// TwinCAT 3 PLC project PLC
// ProgramVersion: 3.1.4024.0
// libraries:
//   Tc2_ModbusRTU, * (Beckhoff Automation GmbH)
//   Tc2_Standard, * (Beckhoff Automation GmbH)
//   Tc2_System, * (Beckhoff Automation GmbH)
//   Tc2_Utilities, * (Beckhoff Automation GmbH)
//   Tc3_Module, * (Beckhoff Automation GmbH)
// project tree:
//   DUTs/_00_DUTs_IOMapping/INPUT/ dut_EXH_Input.TcDUT, dut_GB_Input.TcDUT, dut_OP_INPUT.TcDUT
//   DUTs/_00_DUTs_IOMapping/OUTPUT/ dut_EX260_SEC.TcDUT, dut_EXH_Output.TcDUT, dut_GB_Output.TcDUT, dut_OP_Output.TcDUT
//   DUTs/_01_DUTs_PMC_PLC/ dut_Interlock.TcDUT, dut_PMC_to_PLC.TcDUT, dut_PLC_to_PMC.TcDUT
//   DUTs/_09_DUTs_Function/ dut_32Bits.TcDUT, dut_8Bits.TcDUT, dut_UDINT_BOOL.TcDUT, dut_USINT_BOOL.TcDUT
//   GVLs/ AI.TcGVL, AO.TcGVL, GVL.TcGVL, GVL_IO_Mapping.TcGVL
//   / PlcTask.TcTTO
//   POUs/_000_MainPro/ MAIN.TcPOU
//   POUs/_100_IOMapping/ IOMapping.TcPOU
//   POUs/_200_Interlock/ Interlock.TcPOU
//   POUs/_900_FB/ AnalogConverter.TcPOU, FFU.TcPOU, Valve.TcPOU

CONFIGURATION PLC
    RESOURCE PLC ON TwinCAT3
        TASK PlcTask(INTERVAL := T#10ms, PRIORITY := 20);
        PROGRAM MAIN WITH PlcTask : MAIN;
        PROGRAM IOMapping WITH PlcTask : IOMapping;
    END_RESOURCE
END_CONFIGURATION

// ---- DUTs/_00_DUTs_IOMapping/INPUT/dut_EXH_Input.TcDUT
TYPE dut_EXH_Input :
STRUCT

	I300_00			:BOOL;	//	FS105_RHC_Flow_Alarm
	I300_01			:BOOL;	//	FS106_Heater_Jacket_Flow_Alarm
	I300_02			:BOOL;	//	FS202_Heater_Upper_Alarm
	I300_03			:BOOL;	//	FS104_Shutter_Flow_Alarm
	I300_04			:BOOL;	//	FS111_BoatRotation_Flow_Alarm
	I300_05			:BOOL;	//	FS102_Flange_Flow_Alarm
	I300_06			:BOOL;	//	Spare
	I300_07			:BOOL;	//	Spare
	I300_08			:BOOL;	//	VG11_Status_OK
	I300_09			:BOOL;	//	VG11_Low_Alarm
	I300_10			:BOOL;	//	VG11_High_Alarm
	I300_11			:BOOL;	//	VG13_Status_OK
	I300_12			:BOOL;	//	VG13_Low_Alarm
	I300_13			:BOOL;	//	VG13_High_Alarm
	I300_14			:BOOL;	//	AV71_Fan1_Alarm
	I300_15			:BOOL;	//	AV71_Fan2_Alarm
	I301_00			:BOOL;	//	DG1_Low_Limit_Alarm
	I301_01			:BOOL;	//	DG1_High_Limit_Alarm
	I301_02			:BOOL;	//	Spare
	I301_03			:BOOL;	//	Spare
	I301_04			:BOOL;	//	Spare
	I301_05			:BOOL;	//	Spare
	I301_06			:BOOL;	//	Spare
	I301_07			:BOOL;	//	Spare
	I301_08			:BOOL;	//	MP/PS21_Pressure_Low_Alarm
	I301_09			:BOOL;	//	FS101_MainWater_Flow_Alarm-1
	I301_10			:BOOL;	//	FS101_FMainWater_low_Alarm-2
	I301_11			:BOOL;	//	FL301_Flow_Switch
	I301_12			:BOOL;	//	Spare
	I301_13			:BOOL;	//	FS116_Zaxis_Flow_Alarm
	I301_14			:BOOL;	//	PS110_Pressure_Low_Alarm
	I301_15			:BOOL;	//	PS110_Pressure_High_Alarm
	I302_00			:BOOL;	//	PG/PS12_Pressure_Low_Alarm
	I302_01			:BOOL;	//	PG/PS12_Pressure_High_Alarm
	I302_02			:BOOL;	//	PS13_ATM_Status
	I302_03			:BOOL;	//	PS13_High_Limit_Alarm
	I302_04			:BOOL;	//	PG101_Water_Pressure_Low_Alarm
	I302_05			:BOOL;	//	PG101_Water_Pressure_High_Alarm
	I302_06			:BOOL;	//	VG14_Status_OK
	I302_07			:BOOL;	//	VG14_LOW_Alarm
	I302_08			:BOOL;	//	VG14_High_Alarm
	I302_09			:BOOL;	//	PS14_Pressure_Low_Alarm
	I302_10			:BOOL;	//	PS14_Pressure_High_Alarm
	I302_11			:BOOL;	//	Spare
	I302_12			:BOOL;	//	Spare
	I302_13			:BOOL;	//	Spare
	I302_14			:BOOL;	//	Spare
	I302_15			:BOOL;	//	Spare
	I303_00			:BOOL;	//	APC_Valve_Status
	I303_01			:BOOL;	//	APC_Alarm_Status
	I303_02			:BOOL;	//	RHC_Cooling_Air_cylinder1_Open
	I303_03			:BOOL;	//	RHC_Cooling_Air_cylinder1_Close
	I303_04			:BOOL;	//	RHC_Cooling_Air_cylinder2_Open
	I303_05			:BOOL;	//	RHC_Cooling_Air_cylinder2_Close
	I303_06			:BOOL;	//	RHC_Cooling_Valve_Open
	I303_07			:BOOL;	//	RHC_Cooling_Valve_Close
	I303_08			:BOOL;	//	RHC_Cooling_ButterflyValves_Open
	I303_09			:BOOL;	//	RHC_Cooling_ButterflyValves_Close
	I303_10			:BOOL;	//	Spare
	I303_11			:BOOL;	//	Spare
	I303_12			:BOOL;	//	GV_Open_NC
	I303_13			:BOOL;	//	GV_Open_NO
	I303_14			:BOOL;	//	GV_Close_NC
	I303_15			:BOOL;	//	GV_Close_NO
	I304_00			:BOOL;	//	RHC_Cooling_BallValve_Open
	I304_01			:BOOL;	//	RHC_Cooling_BallValve_Close
	I304_02			:BOOL;	//	Spare
	I304_03			:BOOL;	//	Spare
	I304_04			:BOOL;	//	Spare
	I304_05			:BOOL;	//	Spare
	I304_06			:BOOL;	//	Spare
	I304_07			:BOOL;	//	Spare
	I304_08			:BOOL;	//	Spare
	I304_09			:BOOL;	//	Spare
	I304_10			:BOOL;	//	Spare
	I304_11			:BOOL;	//	Spare
	I304_12			:BOOL;	//	Spare
	I304_13			:BOOL;	//	Spare
	I304_14			:BOOL;	//	Spare
	I304_15			:BOOL;	//	Spare	

	IW300			:INT;	//	FS105_RHC_Colling_Water_Flow
	IW301			:INT;	//	FS106_Heater_Jacket_Cooling_Water_Flow
	IW302			:INT;	//	FS202_Furnace_Cooling_Water_Flow
	IW303			:INT;	//	FS104_Shutter_Cooling_Water_Flow
	IW304			:INT;	//	FS111_Boat_Rotation_Cooling_Water_Flow
	IW305			:INT;	//	FS102_Flange_Cooling_Water_Flow
	IW306			:INT;	//	SPARE
	IW307			:INT;	//	SPARE
	IW308			:INT;	//	DG1_Pressure
	IW309			:INT;	//	SPARE
	IW310			:INT;	//	SPARE
	IW311			:INT;	//	FS116_Radiator_Cooling_Water_Flow
	IW312			:INT;	//	PS13_Pressure
	IW313			:INT;	//	SPARE
	IW314			:INT;	//	SPARE
	IW315			:INT;	//	SPARE
	IW316			:INT;	//	SPARE
	IW317			:INT;	//	SPARE
	IW318			:INT;	//	PS21_Pressure
	IW319			:INT;	//	PS110_Pressure
	IW320			:INT;	//	PG/PS12_Pressure
	IW321			:INT;	//	VG14_Pressure
	IW322			:INT;	//	PS14_Pressure
	IW323			:INT;	//	SPARE
	IW324			:INT;	//	SPARE
	IW325			:INT;	//	SPARE
	IW326			:INT;	//	SPARE
	IW327			:INT;	//	SPARE
	IW328			:INT;	//	SPARE
	IW329			:INT;	//	SPARE
	IW330			:INT;	//	SPARE
	IW331			:INT;	//	SPARE
	IW332			:INT;	//	spare
	IW333			:INT;	//	SPARE
	IW334			:INT;	//	SPARE
	IW335			:INT;	//	SPARE

END_STRUCT
END_TYPE

// ---- DUTs/_00_DUTs_IOMapping/INPUT/dut_GB_Input.TcDUT
TYPE dut_GB_Input :
STRUCT

	I200_00			:BOOL;	//	PG3_LOW_ALARM
	I200_01			:BOOL;	//	PG3_HIGH_ALARM
	I200_02			:BOOL;	//	PG4_LOW_ALARM
	I200_03			:BOOL;	//	PG4_HIGH_ALARM
	I200_04			:BOOL;	//	PG5_LOW_ALARM
	I200_05			:BOOL;	//	PG5_HIGH_ALARM
	I200_06			:BOOL;	//	PG6_LOW_ALARM
	I200_07			:BOOL;	//	PG6_HIGH_ALARM
	I200_08			:BOOL;	//	PG7_LOW_ALARM
	I200_09			:BOOL;	//	PG7_HIGH_ALARM
	I200_10			:BOOL;	//	PG8_LOW_ALARM
	I200_11			:BOOL;	//	PG8_HIGH_ALARM
	I200_12			:BOOL;	//	PG31_LOW_ALARM
	I200_13			:BOOL;	//	PG31_HIGH_ALARM
	I200_14			:BOOL;	//	PG32_LOW_ALARM
	I200_15			:BOOL;	//	PG32_HIGH_ALARM
	I201_00			:BOOL;	//	LSC_H_LEVEL
	I201_01			:BOOL;	//	LSC_M_LEVEL
	I201_02			:BOOL;	//	LSC_L_LEVEL
	I201_03			:BOOL;	//	VG31_STATUS_OK
	I201_04			:BOOL;	//	VG31_LOW_ALARM
	I201_05			:BOOL;	//	VG31_HIGH_ALARM
	I201_06			:BOOL;	//	GD_FAN1_STOP
	I201_07			:BOOL;	//	GD_FAN2_STOP
	I201_08			:BOOL;	//	OX_MS1
	I201_09			:BOOL;	//	OX_MS2
	I201_10			:BOOL;	//	OX_MS3
	I201_11			:BOOL;	//	OX_MSI1
	I201_12			:BOOL;	//	OX_MSI2
	I201_13			:BOOL;	//	OX_RC1
	I201_14			:BOOL;	//	OX_RC2
	I201_15			:BOOL;	//	OX_RC3
	I202_00			:BOOL;	//	MS2_Pressure_LOW_ALARM
	I202_01			:BOOL;	//	MS2_Pressure_HIGH_ALARM
	I202_02			:BOOL;	//	MS5_Pressure_LOW_ALARM
	I202_03			:BOOL;	//	MS5_Pressure_HIGH_ALARM
	I202_04			:BOOL;	//	SPARE
	I202_05			:BOOL;	//	SPARE
	I202_06			:BOOL;	//	MP/PS20_Pressure_ALARM
	I202_07			:BOOL;	//	MP/PS11_Pressure_ALARM
	I202_08			:BOOL;	//	SPARE
	I202_09			:BOOL;	//	SPARE
	I202_10			:BOOL;	//	SPARE
	I202_11			:BOOL;	//	PG1_LOW_ALARM
	I202_12			:BOOL;	//	PG1_HIGH_ALARM
	I202_13			:BOOL;	//	SPARE
	I202_14			:BOOL;	//	SPARE
	I202_15			:BOOL;	//	SPARE
	I203_00			:BOOL;	//	SPARE
	I203_01			:BOOL;	//	SPARE	
	I203_02			:BOOL;	//	SPARE	
	I203_03			:BOOL;	//	SPARE	
	I203_04			:BOOL;	//	SPARE	
	I203_05			:BOOL;	//	SPARE	
	I203_06			:BOOL;	//	SPARE	
	I203_07			:BOOL;	//	SPARE	
	I203_08			:BOOL;	//	SPARE	
	I203_09			:BOOL;	//	SPARE	
	I203_10			:BOOL;	//	SPARE	
	I203_11			:BOOL;	//	SPARE	
	I203_12			:BOOL;	//	SPARE	
	I203_13			:BOOL;	//	SPARE	
	I203_14			:BOOL;	//	SPARE	
	I203_15			:BOOL;	//	SPARE	
	
	IW250			:INT;	//	PG3_Pressure
	IW251			:INT;	//	PG4_Pressure
	IW252			:INT;	//	PG5_Pressure
	IW253			:INT;	//	PG6_Pressure
	IW254			:INT;	//	PG7_Pressure
	IW255			:INT;	//	PG8_PressureE
	IW256			:INT;	//	PG31_Pressure
	IW257			:INT;	//	PG32_Pressure
	IW258			:INT;	//	VG31_Pressure
	IW259			:INT;	//	PG2_Pressure
	IW260			:INT;	//	PS11_Pressure
	IW261			:INT;	//	PG1_Pressure
	IW262			:INT;	//	MS2_Gasboxleft	 
	IW263			:INT;	//	MS5_Loadingarea	
	IW264			:INT;	//	OX_Value
	IW265			:INT;	//	SPARE
	IW266			:INT;	//	PG21_Pressure
	IW267			:INT;	//	PG22_Pressure
	IW268			:INT;	//	PG23_Pressure
	IW269			:INT;	//	PG33_Pressure
	
END_STRUCT
END_TYPE

// ---- DUTs/_00_DUTs_IOMapping/INPUT/dut_OP_INPUT.TcDUT
TYPE dut_OP_INPUT :
STRUCT
	I600_00			:BOOL;	//	MS8_HC_ExhPress_LOW_ALARM
	I600_01			:BOOL;	//	MS8_HC_ExhPress_HIGH_ALARM
	I600_02			:BOOL;	//	MS1_Heater_ExhPress_LOW_ALARM
	I600_03			:BOOL;	//	MS1_Heater_ExhPress_HIGH_ALARM
	I600_04			:BOOL;	//	MS3_Scavenger_ExhPress_LOW_ALARM
	I600_05			:BOOL;	//	MS3_Scavenger_ExhPress_HIGH_ALARM
	I600_06			:BOOL;	//	MS6_Frontbody_ExhPress_LOW_ALARM
	I600_07			:BOOL;	//	MS6_Frontbody_ExhPress_HIGH_ALARM
	I600_08			:BOOL;	//	MS9_LSC1_ExhPress_LOW_ALARM
	I600_09			:BOOL;	//	MS9_LSC1_ExhPress_HIGH_ALARM
	I600_10			:BOOL;	//	MS11_GasBox_ExhPress_LOW_ALARM
	I600_11			:BOOL;	//	MS11_GasBox_ExhPress_HIGH_ALARM
	I600_12			:BOOL;	//	MS12_GasBox_ExhPress_LOW_ALARM
	I600_13			:BOOL;	//	MS12_GasBox_ExhPress_HIGH_ALARM
	I600_14			:BOOL;	//	SPARE
	I600_15			:BOOL;	//	SPARE
	
	IW600			:INT;	//	MS8_RHC_ExhPress
	IW601			:INT;	//	MS1_Heater_ExhPress
	IW602			:INT;	//	MS3_Scavenger_ExhPress
	IW603			:INT;	//	MS6_Frontbody_ExhPress
	IW604			:INT;	//	MS9_LSC1_ExhPress
	IW605			:INT;	//	MS11_GasBox_ExhPress
	IW606			:INT;	//	MS12_GasBox_ExhPress
	IW607			:INT;	//	SPARE

END_STRUCT
END_TYPE

// ---- DUTs/_00_DUTs_IOMapping/OUTPUT/dut_EX260_SEC.TcDUT
TYPE dut_EX260_SEC :
STRUCT
	A:dut_USINT_BOOL;
	B:dut_USINT_BOOL;
	C:dut_USINT_BOOL;
	D:dut_USINT_BOOL;
END_STRUCT
END_TYPE

// ---- DUTs/_00_DUTs_IOMapping/OUTPUT/dut_EXH_Output.TcDUT
TYPE dut_EXH_Output :
STRUCT
	
	Q300_00				:BOOL;	//	CoolingValve1_Boat
	Q300_01				:BOOL;	//	CoolingValve2_Flange
	Q300_02				:BOOL;
	Q300_03				:BOOL;
	Q300_04				:BOOL;
	Q300_05				:BOOL;
	Q300_06				:BOOL;
	Q300_07				:BOOL;
	Q300_08				:BOOL;	//	APC_auto_close
	Q300_09				:BOOL;	//	APC_pump_on
	Q300_10				:BOOL;
	Q300_11				:BOOL;
	Q300_12				:BOOL;
	Q300_13				:BOOL;
	Q300_14				:BOOL;
	Q300_15				:BOOL;
		
	QEV					:ARRAY[1..1]OF	dut_EX260_SEC ;	//阀岛输出
	
END_STRUCT
END_TYPE

// ---- DUTs/_00_DUTs_IOMapping/OUTPUT/dut_GB_Output.TcDUT
TYPE dut_GB_Output :
STRUCT
								    									
	Q200_00			:BOOL;	//	OX_Pump_On
	Q200_01			:BOOL;	//	Spare1
	Q200_02			:BOOL;	//	Spare2
	Q200_03			:BOOL;	//	Spare3
	Q200_04			:BOOL;	//	Spare4
	Q200_05			:BOOL;	//	Spare5
	Q200_06			:BOOL;	//	Spare6
	Q200_07			:BOOL;	//	Spare7
	Q200_08			:BOOL;	//	Spare8
	Q200_09			:BOOL;	//	Spare9
	Q200_10			:BOOL;	//	Spare10
	Q200_11			:BOOL;	//	Spare11
	Q200_12			:BOOL;	//	Spare12
	Q200_13			:BOOL;	//	Spare13
	Q200_14			:BOOL;	//	Spare14
	Q200_15			:BOOL;	//	Spare15
	
	QEV				:ARRAY[1..5]OF dut_EX260_SEC;	//阀岛输出
	
END_STRUCT
END_TYPE

// ---- DUTs/_00_DUTs_IOMapping/OUTPUT/dut_OP_Output.TcDUT
TYPE dut_OP_Output :
STRUCT
	










END_STRUCT
END_TYPE

// ---- DUTs/_01_DUTs_PMC_PLC/dut_Interlock.TcDUT
TYPE dut_Interlock :
STRUCT
	Alarm1		: BOOL;	// N2-8 pressure low
	Alarm2		: BOOL;	// N2-1 pressure low or high
	Alarm3		: BOOL;	// NH3-1 pressure low or high
	Alarm4		: BOOL;	// NH3-2 pressure low or high
	Alarm5		: BOOL;	// SiH4 pressure low or high
	Alarm6		: BOOL;	// N2-2 pressure low or high
	Alarm7		: BOOL;	// NF3 pressure low or high
	Alarm8		: BOOL;	// 20%F2/N2 pressure low or high
	Alarm9		: BOOL;	// N2-9 pressure low or high
	Alarm10		: BOOL;	// N2-10 pressure low or high
	Alarm11		: BOOL;	// N2-11 pressure low or high
	Alarm12		: BOOL;	// N2-13 pressure low or high
	Alarm13		: BOOL;	// LSC tank over pressure
	Alarm14		: BOOL;	// TI tank over pressure
	Alarm15		: BOOL;	// NH3-1 tank over pressure
	Alarm16		: BOOL;	// Vacuum pressure low
	Alarm17		: BOOL;	// air/N2-1 pressure low
	Alarm18		: BOOL;	// N2-4 pressure low
	Alarm19		: BOOL;	// N2-5 pressure low
	Alarm20		: BOOL;	// N2-6 pressure low
	Alarm21		: BOOL;	// NH3-2 tank over pressure
	Alarm22		: BOOL;	// gas box lower and upper exhaust pressure low
	Alarm23		: BOOL;	// Scavenger exhaust pressure low
	Alarm24		: BOOL;	// Heater exhaust pressure low
	Alarm25		: BOOL;	// RHC pressure low
	Alarm26		: BOOL;	// Z purge in LSC-1 pressure
	Alarm27		: BOOL;	// Gas box lower an upper exhaust pressure low
	Alarm28		: BOOL;	// Abnormal diaphragm sensor reading value
	Alarm29		: BOOL;	// spare
	Alarm30		: BOOL;	// Abnormal furnace port cap seal level
	Alarm31		: BOOL;	// Heater exceeds the upper limit
	Alarm32		: BOOL;	// Heater room temperature high
	Alarm33		: BOOL;	// spare
	Alarm34		: BOOL;	// Heater transformer temperature high
	Alarm35		: BOOL;	// spare
	Alarm36		: BOOL;   // AC100V transformer temperature high
	Alarm37		: BOOL;   // spare
	Alarm38		: BOOL;	// spare
	Alarm39		: BOOL;	// N2 does not flow in each foup
	Alarm40		: BOOL;	// Exhaust pressure high
	Alarm41		: BOOL;	// Power down detected
	Alarm42		: BOOL;	// Front door kept open
	Alarm43		: BOOL;	// Transfer room door kept open
	Alarm44		: BOOL;	// Heater room door kept open
	Alarm45		: BOOL;	// Heater power down
	Alarm46		: BOOL;	// spare
	Alarm47		: BOOL;	// Pump down
	Alarm48		: BOOL;	// Pump alarm
	Alarm49		: BOOL;	// Pump warning
	Alarm50		: BOOL;	// spare
	Alarm51		: BOOL;	// NH3 leak detection
	Alarm52		: BOOL;	// SiH4 leak detection
	Alarm53		: BOOL;	// HCL leak detection
	Alarm54		: BOOL;	// Diaphgram sensor-VG11 negative value
	Alarm55		: BOOL;	// Diaphgram sensor-VG13 negative value
	Alarm56		: BOOL;	// Diaphgram sensor-VG14 negative value
	Alarm57		: BOOL;	// APC alarm
	Alarm58		: BOOL;	// Too high furnace pressure
	Alarm59		: BOOL;	// Main cooling water flow low
	Alarm60		: BOOL;	// Cooling water flow low
	Alarm61		: BOOL;	// NF3 gas leak detection
	Alarm62		: BOOL;	// 20%F2/N2 leak detection
	Alarm63		: BOOL;	// scrubber NG DEPO
	Alarm64		: BOOL;	// scrubber NG CLN
	Alarm65		: BOOL;	// FFU stop
	Alarm66		: BOOL;	// SPARE
	Alarm67		: BOOL;	// Loading area differential pressure abnormal
	Alarm68		: BOOL;	// Clean unit temperature high
	Alarm69		: BOOL;	// Differential pressure NG-DG1
	Alarm70		: BOOL; // RHC flow low
	Alarm71		: BOOL;	// RHC damper abnormal position
	Alarm72		: BOOL;	// Blower overload
	Alarm73		: BOOL;	// RHC cooling water bypass line flow low/damper position abnormal in energy-saving mode
	Alarm74		: BOOL;	// Cooling water pressure low
	Alarm75		: BOOL;	// TI tank refll incorrect
	Alarm76		: BOOL;	// Abnormal float sw position in TI tank
	Alarm77		: BOOL;	// N2-7 pressure low or high
	Alarm78		: BOOL;	// N2-70 pressure low or high
	Alarm79		: BOOL;	// Vent exhaust pressure high
	Alarm80		: BOOL;	// Gas box door kept open
	Alarm81		: BOOL;	// Magnetic leak
	Alarm82		: BOOL;	// Heater room leak
	Alarm83		: BOOL;	// Loading area leak
	Alarm84		: BOOL;	// Exhaust box main leak
	Alarm85		: BOOL;	// SPARE
	Alarm86		: BOOL;	// RHC leak
	Alarm87		: BOOL;	// Exhaust box sup leak
	Alarm88		: BOOL;	// O2 analyzer fault
	Alarm89		: BOOL;	// Heater contactor tripped
	Alarm90		: BOOL;	// AC100V transformer contactor tripped
	Alarm91		: BOOL;	// gas box door kept open
	Alarm92		: BOOL;	// spare
	Alarm93		: BOOL;	// spare
	Alarm94		: BOOL;	// failure of exhaust pressure sensor
	Alarm95		: BOOL;	// Transfer room EMS
	Alarm96		: BOOL;	// Furnace pressure is below ATM pressure
	Alarm97		: BOOL; // Front body exhaust pressure low
	Alarm98		: BOOL;	// Gage valve position error
	Alarm99		: BOOL;	// LSC heater temperature abnormal
	Alarm100	: BOOL;	// Gas line heater temperature abnormal
	Alarm101	: BOOL;	// Exhaust line heater temperature abnormal
	Alarm102	: BOOL;	// VG11/13/14 heater temperature abnormal
	Alarm103	: BOOL;	// Seal cap heater temperature high
	Alarm104	: BOOL;	// spare
	Alarm105	: BOOL;	// Furnace & exhaust line heater temperature beyond a preset value
	Alarm106	: BOOL;	// Intake damper position abnormal
	Alarm107	: BOOL;	// ATM damper position abnormal
	Alarm108	: BOOL;	// Cycle damper position abnormal
	Alarm109	: BOOL;	// LSC tank level HH
	Alarm110	: BOOL;	// LSC tank level H
	Alarm111	: BOOL;	// LSC tank level M
	Alarm112	: BOOL;	// LSC tank level L
	Alarm113	: BOOL;	// LSC leak
	Alarm114	: BOOL;	// spare
	Alarm115	: BOOL;	// sspare
	Alarm116	: BOOL;	// HPM interlock
	Alarm117	: BOOL;	// Scrubber alarm
	Alarm118	: BOOL;	// Foreline heater alarm
	Alarm119	: BOOL;	// Scrubber warning
	Alarm120	: BOOL;	// spare
	Alarm121	: BOOL;	// Customer's auto refill alarm
	Alarm122	: BOOL;	// Customer's auto refill warning
	Alarm123	: BOOL;	// Customer's auto refill bulk empty(not ready)
	Alarm124	: BOOL;	// Gas detector trouble
	Alarm125	: BOOL;	// External EMO in
	Alarm126	: BOOL;	// spare
	Alarm127	: BOOL;	// spare
	Alarm128	: BOOL;	// spare
	Alarm129	: BOOL;	// spare
	Alarm130	: BOOL;	// spare
	Alarm131	: BOOL;	// spare
	Alarm132	: BOOL;	// spare
	Alarm133	: BOOL;	// spare
	Alarm134	: BOOL;	// spare
	Alarm135	: BOOL;	// spare
	Alarm136	: BOOL;	// spare
	Alarm137	: BOOL;	// spare
	Alarm138	: BOOL;	// spare
	Alarm139	: BOOL;	// spare
	Alarm140	: BOOL;	// spare
	Alarm141	: BOOL;	// spare
	Alarm142	: BOOL;	// spare
	Alarm143	: BOOL;	// spare
	Alarm144	: BOOL;	// spare
	Alarm145	: BOOL;	// spare
	Alarm146	: BOOL;	// spare
	Alarm147	: BOOL;	// spare
	Alarm148	: BOOL;	// spare
	Alarm149	: BOOL;	// spare
	Alarm150	: BOOL;	// spare
	
END_STRUCT
END_TYPE

// ---- DUTs/_01_DUTs_PMC_PLC/dut_PMC_to_PLC.TcDUT
TYPE dut_PMC_to_PLC :
STRUCT
	bHeartBeatMonitor	: BOOL;		

	// UI switch
	DP_sw						,
	BWR_sw						,
	DPR1_sw						,
	DPR2_sw						,
	WAT_R_sw					,
	WAT_F_sw					,
	HTR1_sw						,
	HTR2_sw						,
	HTR3_sw						,
	HTR4_sw						,
	HTR5_sw						,
	AGV_sw						,
	DEPO_sw						,
	CLN_sw						,
	T_MNT_sw					,
	T_REF_sw					,
	Pump1_ECO_sw				,
	SP1_sw						,
	PZ_sw						,
	P_CONT_sw					,
	DGZERO_sw					,
	C_EXH_sw					,
	F2_CLN_sw					,
	F_N_sw						,
	GV_AV79_Open				,
	GV_AV79_Close				,
	APC_AV71_Open				,
	APC_AV71_Close				
	: BOOL;
	
	aAV							: ARRAY[1..250] OF BOOL;	
	bAV65Open					: BOOL;
	bAV65Close					: BOOL;
	bAV79Open					: BOOL;
	bAV79Close					: BOOL;
	bAV91Open					: BOOL;
	bAV91Close					: BOOL;
	bAV202Open					: BOOL;
	bAV202Close					: BOOL;
	
	//heater
	Furnace_Temp_abnormal		: BOOL;	// Furnace temp over 1000℃
	LSC_Ht_temp_abnormal		: BOOL;	// LSC heater temperature beyond preset value
	GB_Ht_temp_abnormal			: BOOL; // Gas line heater temperature beyond preset value
	EXH_Ht_temp_abnormal		: BOOL;	// Exhaust line heater temperature beyond preset value
	CLN_Temp_abnormal			: BOOL; // furnace&exhaust line heater temperature beyond preset value
	R_Axis_Temp					: REAL;	// R axis temperature
	Inlet_Ht_1_temp				: REAL;	// Inlet heater 1 temperature
	Inlet_Ht_2_temp				: REAL;	// Inlet heater 2 temperature
	Port_Ht_1_temp				: REAL; // Port heater 1 temperature
	Port_Ht_2_temp				: REAL; // Port heater 2 temperature
	Port_Ht_3_temp				: REAL; // Port heater 3 temperature
	Port_Ht_4_temp				: REAL; // Port heater 4 temperature
	Port_Ht_5_temp				: REAL; // Port heater 5 temperature

	//Power box
	I100_00			:BOOL;	//	UPS_Fault              
	I100_01			:BOOL;	//	UPS_Alarm              
	I100_02			:BOOL;	//	UPS_Bypass_Status      
	I100_03			:BOOL;	//	UPS_Battery_Voltage_Low
	I100_04			:BOOL;	//	UPS_Start              
	I100_05			:BOOL;	//	UPS_AC_Input_Cut_Off   
	I100_06			:BOOL;	//	Powerbox_FrontDoor_sw1
	I100_07			:BOOL;	//	Powerbox_FrontDoor_sw2
	I100_08			:BOOL;	//	Powerbox_BackDoor_sw1
	I100_09			:BOOL;	//	Powerbox_BackDoor_sw2
	I100_10			:BOOL;	//	Spare11
	I100_11			:BOOL;	//	Spare12
	I100_12			:BOOL;	//	Spare13
	I100_13			:BOOL;	//	Spare14
	I100_14			:BOOL;	//	Spare15
	I100_15			:BOOL;	//	Spare16
	I101_00			:BOOL;	//	KM101_ON
	I101_01			:BOOL;	//	KM201_ON
	I101_02			:BOOL;	//	KM102_ON
	I101_03			:BOOL;	//	KM103_ON
	I101_04			:BOOL;	//	KM104_ON
	I101_05			:BOOL;	//	SPARE
	I101_06			:BOOL;	//	SPARE
	I101_07			:BOOL;	//	Furnace_Main_Breaker_Status_Monitor
	I101_08			:BOOL;	//	Blower_Breaker_Status_Feedback
	I101_09			:BOOL;	//	Zone1_Circuit_Breaker_Status_Monitor
	I101_10			:BOOL;	//	Zone2_Circuit_Breaker_Status_Monitor
	I101_11			:BOOL;	//	Zone3_Circuit_Breaker_Status_Monitor
	I101_12			:BOOL;	//	Zone4_Circuit_Breaker_Status_Monitor
	I101_13			:BOOL;	//	Zone5_Circuit_Breaker_Status_Monitor
	I101_14			:BOOL;	//	Zone6_Circuit_Breaker_Status_Monitor
	I101_15			:BOOL;	//	Zone7_Circuit_Breaker_Status_Monitor
	I102_00			:BOOL;	//	LDS1_bulk_to_process_running
	I102_01			:BOOL;	//	LDS1_supply_doing
	I102_02			:BOOL;	//	LDS1_system_ready
	I102_03			:BOOL;	//	LDS1_major_alarm
	I102_04			:BOOL;	//	LDS1_minor_alarm
	I102_05			:BOOL;	//	LDS1_low_level_status
	I102_06			:BOOL;	//	LDS1_process_reservoir_empty
	I102_07			:BOOL;	//	LDS2_bulk_to_process_running
	I102_08			:BOOL;	//	LDS2_supply_doing           
	I102_09			:BOOL;	//	LDS2_system_ready           
	I102_10			:BOOL;	//	LDS2_major_alarm            
	I102_11			:BOOL;	//	LDS2_minor_alarm            
	I102_12			:BOOL;	//	LDS2_low_level_status       
	I102_13			:BOOL;	//	LDS2_process_reservoir_empty
	I102_14			:BOOL;	//	SPARE
	I102_15			:BOOL;	//	SPARE
	I103_00			:BOOL;	//	Vaccum1_Pump_Both_On
	I103_01			:BOOL;	//	Vaccum1_Pump_Warning
	I103_02			:BOOL;	//	Vaccum1_Pump_Alarm
	I103_03			:BOOL;	//	Spare19
	I103_04			:BOOL;	//	Spare20
	I103_05			:BOOL;	//	Spare21
	I103_06			:BOOL;	//	N2_Purge_BOX_PG13_CNT1
	I103_07			:BOOL;	//	N2_Purge_BOX_PG13_CNT2
	I103_08			:BOOL;	//	N2_Purge_BOX_PG14_CNT1
	I103_09			:BOOL;	//	N2_Purge_BOX_PG14_CNT2
	I103_10			:BOOL;	//	N2_Purge_Box_PG15_CNT1
	I103_11			:BOOL;	//	N2_Purge_Box_PG15_CNT2
	I103_12			:BOOL;	//	N2_Purge_Box_PG16_CNT1
	I103_13			:BOOL;	//	N2_Purge_Box_PG16_CNT2
	I103_14			:BOOL;	//	N2_Purge_Box_PG130_CNT1
	I103_15			:BOOL;	//	N2_Purge_Box_PG130_CNT2
	I104_00			:BOOL;	//	PS17_Low_pressure_alarm
	I104_01			:BOOL;	//	Foreline_heater_light_alarm
	I104_02			:BOOL;  //	Foreline_heater_heavy_alarm
	I104_03			:BOOL;  //	Scrubber_warning
	I104_04			:BOOL;  //	Scrubber_alarm
	I104_05			:BOOL;  //	External_HPM_alarm
	I104_06			:BOOL;  //	External_EMO_In
	I104_07			:BOOL;  //	SPARE
	I104_08			:BOOL;  //	SPARE
	I104_09			:BOOL;  //	SPARE
	I104_10			:BOOL;  //	SPARE
	I104_11			:BOOL;  //	SPARE
	I104_12			:BOOL;  //	SPARE
	I104_13			:BOOL;  //	SPARE
	I104_14			:BOOL;  //	SPARE
	I104_15			:BOOL;  //	SPARE
	
	Q100_00			:BOOL;	//	VFD_RES
	Q100_01			:BOOL;	//	VFD_MRS
	Q100_02			:BOOL;	//	VFD_RT
	Q100_03			:BOOL;	//	VFD_JOG
	Q100_04			:BOOL;	//	VFD_RL
	Q100_05			:BOOL;	//	VFD_RM
	Q100_06			:BOOL;	//	VFD_RH
	Q100_07			:BOOL;	//	VFD_STP
	Q100_08			:BOOL;	//	VFD_RTR
	Q100_09			:BOOL;	//	VFD_RTF
	Q100_10			:BOOL;	//	Spare1
	Q100_11			:BOOL;	//	Spare2
	Q100_12			:BOOL;	//	Spare3
	Q100_13			:BOOL;	//	Spare4
	Q100_14			:BOOL;	//	Spare5
	Q100_15			:BOOL;	//	Spare6
	Q101_00			:BOOL;	//	Furnace 1 Zone Heating Enable
	Q101_01			:BOOL;	//	Furnace 2 Zone Heating Enable
	Q101_02			:BOOL;	//	Furnace 3 Zone Heating Enable
	Q101_03			:BOOL;	//	Furnace 4 Zone Heating Enable
	Q101_04			:BOOL;	//	Furnace 5 Zone Heating Enable
	Q101_05			:BOOL;	//	Furnace 6 Zone Heating Enable
	Q101_06			:BOOL;	//	Furnace 7 Zone Heating Enable
	Q101_07			:BOOL;	//	LSC_1_AutoRefill1 Request Or Valve Open
	Q101_08			:BOOL;	//	LSC_1_External_Shutdown
	Q101_09			:BOOL;	//	HPM Valve Out Status
	Q101_10			:BOOL;	//	Forline Heater On
	Q101_11			:BOOL;	//	Spare7
	Q101_12			:BOOL;	//	Spare8
	Q101_13			:BOOL;	//	Spare9
	Q101_14			:BOOL;	//	Spare10
	Q101_15			:BOOL;	//	Spare11
	Q102_00			:BOOL;	//	Vaccum Pump Both On
	Q102_01			:BOOL;	//	Vaccum Pump AUC On
	Q102_02			:BOOL;	//	Vaccum Pump AGV Open
	Q102_03			:BOOL;	//	LSC_2_AutoRefill1 Request Or Valve Open
	Q102_04			:BOOL;	//	LSC_2_External_Shutdown
	Q102_05			:BOOL;	//	Spare
	Q102_06			:BOOL;	//	Spare
	Q102_07			:BOOL;	//	Spare
	Q102_08			:BOOL;	//	Spare
	Q102_09			:BOOL;	//	Spare
	Q102_10			:BOOL;	//	Spare
	Q102_11			:BOOL;	//	Spare
	Q102_12			:BOOL;	//	Spare
	Q102_13			:BOOL;	//	Spare
	Q102_14			:BOOL;	//	Spare
	Q102_15			:BOOL;	//	Spare
	Q103_00			:BOOL;	//	Spare
	Q103_01			:BOOL;	//	Spare
	Q103_02			:BOOL;	//	Spare
	Q103_03			:BOOL;	//	Spare
	Q103_04			:BOOL;	//	Spare
	Q103_05			:BOOL;	//	Spare
	Q103_06			:BOOL;	//	Spare
	Q103_07			:BOOL;	//	Spare
	Q103_08			:BOOL;	//	Spare
	Q103_09			:BOOL;	//	Spare
	Q103_10			:BOOL;	//	Spare
	Q103_11			:BOOL;	//	Spare
	Q103_12			:BOOL;	//	Spare
	Q103_13			:BOOL;	//	Spare
	Q103_14			:BOOL;	//	Spare
	Q103_15			:BOOL;	//	Spare	
	
	PS17_Pressure				: REAL;	// PS17_Pressure
	
	//Gas box
	Q200_00			:BOOL;	//	OX_Pump_On
	Q200_01			:BOOL;	//	Spare1
	Q200_02			:BOOL;	//	Spare2
	Q200_03			:BOOL;	//	Spare3
	Q200_04			:BOOL;	//	Spare4
	Q200_05			:BOOL;	//	Spare5
	Q200_06			:BOOL;	//	Spare6
	Q200_07			:BOOL;	//	Spare7
	Q200_08			:BOOL;	//	Spare8
	Q200_09			:BOOL;	//	Spare9
	Q200_10			:BOOL;	//	Spare10
	Q200_11			:BOOL;	//	Spare11
	Q200_12			:BOOL;	//	Spare12
	Q200_13			:BOOL;	//	Spare13
	Q200_14			:BOOL;	//	Spare14
	Q200_15			:BOOL;	//	Spare15
	
	VG31_Reading_Valid					: BOOL;
	VG31_Overrange_Exceeded				: BOOL;
	VG31_Underrange_Exceeded			: BOOL;
	VG31_Sensor_Value					: REAL;	
	VG31_Active_Device_Warning_Details	: UDINT;
	VG31_Active_Device_Error_Details	: UDINT;
	
	//Exhaust box
	Q300_00				:BOOL;	//	CoolingValve1_Boat
	Q300_01				:BOOL;	//	CoolingValve2_Flange
	Q300_02				:BOOL;
	Q300_03				:BOOL;
	Q300_04				:BOOL;
	Q300_05				:BOOL;
	Q300_06				:BOOL;
	Q300_07				:BOOL;
	Q300_08				:BOOL;	//	APC_auto_close
	Q300_09				:BOOL;	//	APC_pump_on
	Q300_10				:BOOL;	//	BallValve_Open_Close
	Q300_11				:BOOL;
	Q300_12				:BOOL;
	Q300_13				:BOOL;
	Q300_14				:BOOL;
	Q300_15				:BOOL;

	VG11_Reading_Valid					: BOOL;
	VG11_Overrange_Exceeded				: BOOL;
	VG11_Underrange_Exceeded			: BOOL;
	VG11_Sensor_Value					: REAL;	
	VG11_Active_Device_Warning_Details	: UDINT;
	VG11_Active_Device_Error_Details	: UDINT;
	
	VG13_Reading_Valid					: BOOL;
	VG13_Overrange_Exceeded				: BOOL;
	VG13_Underrange_Exceeded			: BOOL;
	VG13_Sensor_Value					: REAL;	
	VG13_Active_Device_Warning_Details	: UDINT;
	VG13_Active_Device_Error_Details	: UDINT;
	
	VG14_Reading_Valid					: BOOL;
	VG14_Overrange_Exceeded				: BOOL;
	VG14_Underrange_Exceeded			: BOOL;
	VG14_Sensor_Value					: REAL;	
	VG14_Active_Device_Warning_Details	: UDINT;
	VG14_Active_Device_Error_Details	: UDINT;
	
	//Frontbody box
	FB_Buffer_N2_Press_Low		: BOOL;
	
	//LA box
	LA_Buffer_N2_Press_Low		: BOOL;
	Boat_at_cap_position		: BOOL;
	
	I500_00			:BOOL;	//	FIMS1_FOUP_Dock
	I500_01			:BOOL;	//	FIMS1_FOUP_Undock
	I500_02			:BOOL;	//	FIMS1_FOUP_Exist
	I500_03			:BOOL;	//	FIMS2_FOUP_Dock
	I500_04			:BOOL;	//	FIMS2_FOUP_Undock
	I500_05			:BOOL;	//	FIMS2_FOUP_Exist
	I500_06			:BOOL;	//	FIMS1_FOUP_Wafer_Shift_Detection
	I500_07			:BOOL;	//	FIMS2_FOUP_Wafer_Shift_Detection
	I500_08			:BOOL;	//	FIMS1_FOUP_Negative_Pressure
	I500_09			:BOOL;	//	FIMS1_FOUP_Ordinary_Pressure
	I500_10			:BOOL;	//	FIMS2_FOUP_Negative_Pressure
	I500_11			:BOOL;	//	FIMS2_FOUP_Ordinary_Pressure
	I500_12			:BOOL;	//	BOAT_Slow_Down_Position_Detection
	I500_13			:BOOL;	//	Buffer_Rotation_Conv_Detect_Sensor
	I500_14			:BOOL;	//	Spare1
	I500_15			:BOOL;	//	Spare2
	I501_00			:BOOL;	//	LA_Internal_Cycle_Switch_Open
	I501_01			:BOOL;	//	LA_Internal_Cycle_Switch_Close
	I501_02			:BOOL;	//	LA_ATM_Switch_Open
	I501_03			:BOOL;	//	LA_ATM_Switch_Close
	I501_04			:BOOL;	//	R-Axis_Air_Cylinder_Extend_Position
	I501_05			:BOOL;	//	R-Axis_Air_Cylinder_Retract_Position
	I501_06			:BOOL;	//	Furnace_Shutter_Open
	I501_07			:BOOL;	//	Furnace_Shutter_Close
	I501_08			:BOOL;	//	FIMS1_Exhaust_Open_Position
	I501_09			:BOOL;	//	FIMS1_Exhaust_Close_Position
	I501_10			:BOOL;	//	FIMS2_Exhaust_Open_Position
	I501_11			:BOOL;	//	FIMS2_Exhaust_Close_Position
	I501_12			:BOOL;	//	Spare3
	I501_13			:BOOL;	//	Spare4
	I501_14			:BOOL;	//	Spare5
	I501_15			:BOOL;	//	Spare6
	I502_00			:BOOL;	//	FIMS1_Seal
	I502_01			:BOOL;	//	FIMS1_Release
	I502_02			:BOOL;	//	FIMS1_Door_Close
	I502_03			:BOOL;	//	FIMS1_Door_Open
	I502_04			:BOOL;	//	FIMS1_FOUP_Latch_Off
	I502_05			:BOOL;	//	FIMS1_FOUP_Latch_On
	I502_06			:BOOL;	//	FIMS1_Collision_Avoidance_Up
	I502_07			:BOOL;	//	FIMS1_Collision_Avoidance_Down
	I502_08			:BOOL;	//	FIMS2_Seal
	I502_09			:BOOL;	//	FIMS2_Release
	I502_10			:BOOL;	//	FIMS2_Door_Close
	I502_11			:BOOL;	//	FIMS2_Door_Open
	I502_12			:BOOL;	//	FIMS2_FOUP_Latch_Off
	I502_13			:BOOL;	//	FIMS2_FOUP_Latch_On
	I502_14			:BOOL;	//	FIMS2_Collision_Avoidance_Up
	I502_15			:BOOL;	//	FIMS2_Collision_Avoidance_Down
	I503_00			:BOOL;	//	Spare7
	I503_01			:BOOL;	//	Spare8
	I503_02			:BOOL;	//	Spare9
	I503_03			:BOOL;	//	Spare10
	I503_04			:BOOL;	//	Spare11
	I503_05			:BOOL;	//	Spare12
	I503_06			:BOOL;	//	Spare13
	I503_07			:BOOL;	//	Spare14
	I503_08			:BOOL;	//	Spare15
	I503_09			:BOOL;	//	Spare16
	I503_10			:BOOL;	//	Spare17
	I503_11			:BOOL;	//	Spare18
	I503_12			:BOOL;	//	Spare19
	I503_13			:BOOL;	//	Spare20
	I503_14			:BOOL;	//	Spare21
	I503_15			:BOOL;	//	Spare22
	I504_00			:BOOL;	//	Spare23
	I504_01			:BOOL;	//	Spare24
	I504_02			:BOOL;	//	Spare25
	I504_03			:BOOL;	//	Spare26
	I504_04			:BOOL;	//	Spare27
	I504_05			:BOOL;	//	Spare28
	I504_06			:BOOL;	//	Spare29
	I504_07			:BOOL;	//	Spare30
	I504_08			:BOOL;	//	Spare31
	I504_09			:BOOL;	//	Spare32
	I504_10			:BOOL;	//	Spare33
	I504_11			:BOOL;	//	Spare34
	I504_12			:BOOL;	//	Spare35
	I504_13			:BOOL;	//	Spare36
	I504_14			:BOOL;	//	Spare37
	I504_15			:BOOL;	//	Spare38
	I505_00			:BOOL;	//	Buffer_A1_N2_Pressure_Alarm
	I505_01			:BOOL;	//	Buffer_A1_FOUP_Detect
	I505_02			:BOOL;	//	Buffer_B1_N2_Pressure_Alarm
	I505_03			:BOOL;	//	Buffer_B1_FOUP_Detect
	I505_04			:BOOL;	//	Buffer_C1_N2_Pressure_Alarm
	I505_05			:BOOL;	//	Buffer_C1_FOUP_Detect
	I505_06			:BOOL;	//	Buffer_D1_N2_Pressure_Alarm
	I505_07			:BOOL;	//	Buffer_D1_FOUP_Detect
	I505_08			:BOOL;	//	Buffer_A2_N2_Pressure_Alarm
	I505_09			:BOOL;	//	Buffer_A2_FOUP_Detect
	I505_10			:BOOL;	//	Buffer_B2_N2_Pressure_Alarm
	I505_11			:BOOL;	//	Buffer_B2_FOUP_Detect
	I505_12			:BOOL;	//	Buffer_C2_N2_Pressure_Alarm
	I505_13			:BOOL;	//	Buffer_C2_FOUP_Detect
	I505_14			:BOOL;	//	Buffer_D2_N2_Pressure_Alarm
	I505_15			:BOOL;	//	Buffer_D2_FOUP_Detect
	I506_00			:BOOL;	//	Buffer_A3_N2_Pressure_Alarm
	I506_01			:BOOL;	//	Buffer_A3_FOUP_Detect
	I506_02			:BOOL;	//	Buffer_B3_N2_Pressure_Alarm
	I506_03			:BOOL;	//	Buffer_B3_FOUP_Detect
	I506_04			:BOOL;	//	Buffer_C3_N2_Pressure_Alarm
	I506_05			:BOOL;	//	Buffer_C3_FOUP_Detect
	I506_06			:BOOL;	//	Buffer_D3_N2_Pressure_Alarm
	I506_07			:BOOL;	//	Buffer_D3_FOUP_Detect
	I506_08			:BOOL;	//	Buffer_A4_N2_Pressure_Alarm
	I506_09			:BOOL;	//	Buffer_A4_FOUP_Detect
	I506_10			:BOOL;	//	Buffer_B4_N2_Pressure_Alarm
	I506_11			:BOOL;	//	Buffer_B4_FOUP_Detect
	I506_12			:BOOL;	//	Buffer_C4_N2_Pressure_Alarm
	I506_13			:BOOL;	//	Buffer_C4_FOUP_Detect
	I506_14			:BOOL;	//	Buffer_D4_N2_Pressure_Alarm
	I506_15			:BOOL;	//	Buffer_D4_FOUP_Detect
	
	Q500_00			:BOOL;	//	LA_Internal_Air_Cycle_Switch_Open
	Q500_01			:BOOL;	//	LA_Internal_Air_Cycle_Switch_Close
	Q500_02			:BOOL;	//	LA_ATM_Switch_Open
	Q500_03			:BOOL;	//	LA_ATM_Switch_Close
	Q500_04			:BOOL;	//	R_Axis_Air_Cylinder_Extend_Switch
	Q500_05			:BOOL;	//	R_Axis_Air_Cylinder_Retract_Switch
	Q500_06			:BOOL;	//	O2_Detector_Switch_LA_POD
	Q500_07			:BOOL;	//	O2_Detector_Switch_POD1_POD2
	Q500_08			:BOOL;	//	LA_Internal_Air_Cycle_Fan1_Switch
	Q500_09			:BOOL;	//	LA_Internal_Air_Cycle_Fan2_Switch
	Q500_10			:BOOL;	//	LA_Internal_Air_Cycle_Fan3_Switch
	Q500_11			:BOOL;	//	LA_Internal_Air_Cycle_Fan4_Switch
	Q500_12			:BOOL;	//	Furnace_Shutter_Open
	Q500_13			:BOOL;	//	Furnace_Shutter_Close
	Q500_14			:BOOL;	//	Spare1
	Q500_15			:BOOL;	//	Spare2
	Q501_00			:BOOL;	//	POD1_Exhaust_Switch_Open
	Q501_01			:BOOL;	//	POD1_Exhaust_Switch_Close
	Q501_02			:BOOL;	//	POD2_Exhaust_Switch_Open
	Q501_03			:BOOL;	//	POD2_Exhaust_Switch_Close
	Q501_04			:BOOL;	//	Spare3
	Q501_05			:BOOL;	//	Spare4
	Q501_06			:BOOL;	//	Spare5
	Q501_07			:BOOL;	//	Spare6
	Q501_08			:BOOL;	//	Spare7
	Q501_09			:BOOL;	//	Spare8
	Q501_10			:BOOL;	//	Spare9
	Q501_11			:BOOL;	//	Spare10
	Q501_12			:BOOL;	//	Spare11
	Q501_13			:BOOL;	//	Spare12
	Q501_14			:BOOL;	//	Spare13
	Q501_15			:BOOL;	//	Spare14
	Q502_00			:BOOL;	//	Buffer_A1_N2_Purge_Switch
	Q502_01			:BOOL;	//	Buffer_B1_N2_Purge_Switch
	Q502_02			:BOOL;	//	Buffer_C1_N2_Purge_Switch
	Q502_03			:BOOL;	//	Buffer_D1_N2_Purge_Switch
	Q502_04			:BOOL;	//	Buffer_A2_N2_Purge_Switch
	Q502_05			:BOOL;	//	Buffer_B2_N2_Purge_Switch
	Q502_06			:BOOL;	//	Buffer_C2_N2_Purge_Switch
	Q502_07			:BOOL;	//	Buffer_D2_N2_Purge_Switch
	Q502_08			:BOOL;	//	Buffer_A3_N2_Purge_Switch
	Q502_09			:BOOL;	//	Buffer_B3_N2_Purge_Switch
	Q502_10			:BOOL;	//	Buffer_C3_N2_Purge_Switch
	Q502_11			:BOOL;	//	Buffer_D3_N2_Purge_Switch
	Q502_12			:BOOL;	//	Buffer_A4_N2_Purge_Switch
	Q502_13			:BOOL;	//	Buffer_B4_N2_Purge_Switch
	Q502_14			:BOOL;	//	Buffer_C4_N2_Purge_Switch
	Q502_15			:BOOL;	//	Buffer_D4_N2_Purge_Switch
	Q503_00			:BOOL;
	Q503_01         :BOOL;
	Q503_02         :BOOL;
	Q503_03         :BOOL;
	Q503_04         :BOOL;
	Q503_05         :BOOL;
	Q503_06         :BOOL;
	Q503_07         :BOOL;
	Q503_08         :BOOL;
	Q503_09         :BOOL;
	Q503_10         :BOOL;
	Q503_11         :BOOL;
	Q503_12         :BOOL;
	Q503_13         :BOOL;
	Q503_14         :BOOL;
	Q503_15	        :BOOL;
	
	//Safety box
	O2_analyzer_over_range_alarm		,
	SCR_ONOFF_SWITCH					,
	O2_analyzer_fault					,
	SMK1_detector_operator				,
	SMK1_detector_fault					,
	SMK1_detector_fire_alarm			,
	GD201_NF3_gas_leak_1st_alarm		,
	GD201_NF3_gas_leak_2nd_alarm		,
	GD202_SiH4_gas_leak_1st_alarm		,
	GD201_fault							,
	GD202_SiH4_gas_leak_2nd_alarm		,
	GD202_fault							,
	GD203_NH3_gas_leak_2nd_alarm		,
	GD203_NH3_gas_leak_1st_alarm		,
	GD203_fault							,
	GD204_HCL_gas_leak_1st_alarm		,
	GD204_fault							,
	GD204_HCL_gas_leak_2nd_alarm		,
	GD205_F2_gas_leak_1st_alarm			,
	GD205_F2_gas_leak_2nd_alarm			,
	GD206_NF3_gas_leak_1st_alarm		,
	GD205_fault							,
	GD206_NF3_gas_leak_2nd_alarm		,
	GD206_fault							,
	GD207_SiH4_gas_leak_2nd_alarm		,
	GD207_SiH4_gas_leak_1st_alarm		,
	GD207_fault							,
	GD208_NH3_gas_leak_1st_alarm		,
	GD208_fault							,
	GD208_NH3_gas_leak_2nd_alarm		,
	GD209_HCL_gas_leak_1st_alarm		,
	GD209_HCL_gas_leak_2nd_alarm		,
	GD210_F2_gas_leak_1st_alarm			,
	GD209_fault							,
	GD210_F2_gas_leak_2nd_alarm			,
	GD210_fault							,
	TS31_Cap_outside_temp_sw			,
	TS30_Cap_inside_temp_sw				,
	TS34_R_axis_rotation_temp_sw		,
	Loading_area_EMS					,
	SL201_gas_box_door_sw1_1			,
	FFU_temp_sw							,
	SL201_gas_box_door_sw1_2			,
	SL202_gas_box_door_sw2_1			,
	SL203_gas_box_door_sw3_1			,
	SL202_gas_box_door_sw2_2			,
	SL203_gas_box_door_sw3_2			,
	SL204_gas_box_door_sw4_1			,
	SL205_gas_box_door_sw5_1			,
	SL204_gas_box_door_sw4_2			,
	SL205_gas_box_door_sw5_2			,
	SL501_LA_door_sw1					,
	SL503_LA_door_sw3					,
	SL502_LA_door_sw2					,
	SL504_furnace_door_sw				,
	Gas_box_exhaust_pressure_alarm_1st	,
	MS2_S_gas_box_exhaust_alarm			,
	Gas_box_exhaust_pressure_alarm_2nd	,
	MS11_S_gas_box_exhaust_alarm		,
	MS12_S_gas_box_exhaust_alarm		,
	LSC_1_leak_alarm					,
	LD501_Magnetic_fluid_leak			,
	LD502_Cooling_water_leak			,
	TS305_RHC_temp_sw					,
	LD503_RHC_leak						,
	TS306_Main_furnace_Temp_sw			,
	LD301_water_leak_alarm				,
	EMO301_Exhaust_box_EMO				,
	LD302_water_leak_alarm				,
	FS101_water_flow_alarm1				,	//水路总流量
	Buffer_motor_EDM					,
	R_axis_motor_EDM					,
	E_axis_motor_EDM					,
	FS101_water_flow_alarm2				,	//水路总流量
	EMO101_power_box_EMO				,
	Furnace_transformer_temp_sw			,
	Power_box_fire_detector_alarm		,
	AC100V_transformer_temp_sw			,
	Furnace_power_on_switch				,
	Power_box_reset_button				,
	AC100V_transformer_power_on_switch	,
	VFD_EDM								,
	Light_curtain_fault					,
	Light_curtain_OSSD2					,
	Light_curtain_OSSD1					,
	Gas_box_reset_button				,
	EMO401_frontbody_EMO				,
	Frontbody_IO_shutter				,
	Frontbody_door_sw					,
	Frontbody_reset_button	
	:BOOL;
	
	//IO mapping
	HPM_valve_power_on_off				,
	Furnace_power_on					,
	Cap_heater_enable					,
	//spare
	AC100V_transformer_power_on			,
	VFD_Enable							,
	Blower_power_on						,
	Buffer_motor_enable1				,
	Buffer_motor_enable2				,
	Boat_motor_enable2					,
	Boat_motor_enable1					,
	FTR_enable1							,
	FTR_enable2							,
	WTR_enable1							,
	FTR_interlock_reset					,
	WTR_enable2							,
	WTR_interlock_reset					,
	R_axis_motor_enable2				,
	R_axis_motor_enable1				,
	//spare
	//spare
	Light_curtain_idle					,
	//spare
	Frontbody_interlock_indicator		,
	GasBox_interlock_indicator
	: BOOL;
	
	//FFU
	FFU_ALARM_EN	:	REAL;	//报警输出使能
	FFU_HSPEED		:	REAL;	//转速上限
	FFU_LSPEED		:	REAL;	//转速下限
	
	FFU1_1_POWER_ON	:	REAL	;	//	0:停止，1：运行
	FFU1_2_POWER_ON	:	REAL	;	//	0:停止，1：运行
	FFU1_3_POWER_ON	:	REAL	;	//	0:停止，1：运行
	FFU1_4_POWER_ON	:	REAL	;	//	0:停止，1：运行
	FFU1_5_POWER_ON	:	REAL	;	//	0:停止，1：运行
	FFU1_6_POWER_ON	:	REAL	;	//	0:停止，1：运行
	FFU2_1_POWER_ON	:	REAL	;	//	0:停止，1：运行
	FFU2_2_POWER_ON	:	REAL	;	//	0:停止，1：运行
	FFU2_3_POWER_ON	:	REAL	;	//	0:停止，1：运行
	FFU2_4_POWER_ON	:	REAL	;	//	0:停止，1：运行
	FFU2_5_POWER_ON	:	REAL	;	//	0:停止，1：运行
	FFU2_6_POWER_ON	:	REAL	;	//	0:停止，1：运行
	FFU3_1_POWER_ON	:	REAL	;	//	0:停止，1：运行
	FFU3_2_POWER_ON	:	REAL	;	//	0:停止，1：运行
	FFU3_3_POWER_ON	:	REAL	;	//	0:停止，1：运行
	FFU3_4_POWER_ON	:	REAL	;	//	0:停止，1：运行
	FFU3_5_POWER_ON	:	REAL	;	//	0:停止，1：运行
	FFU3_6_POWER_ON	:	REAL	;	//	0:停止，1：运行
	
	FFU1_1_SPEED_SV	:	REAL	;	//	FFU1_1设定转速
	FFU1_2_SPEED_SV	:	REAL	;	//	FFU1_2设定转速
	FFU1_3_SPEED_SV	:	REAL	;	//	FFU1_3设定转速
	FFU1_4_SPEED_SV	:	REAL	;	//	FFU1_4设定转速
	FFU1_5_SPEED_SV	:	REAL	;	//	FFU1_5设定转速
	FFU1_6_SPEED_SV	:	REAL	;	//	FFU1_6设定转速
	FFU2_1_SPEED_SV	:	REAL	;	//	FFU2_1设定转速
	FFU2_2_SPEED_SV	:	REAL	;	//	FFU2_2设定转速
	FFU2_3_SPEED_SV	:	REAL	;	//	FFU2_3设定转速
	FFU2_4_SPEED_SV	:	REAL	;	//	FFU2_4设定转速
	FFU2_5_SPEED_SV	:	REAL	;	//	FFU2_5设定转速
	FFU2_6_SPEED_SV	:	REAL	;	//	FFU2_6设定转速
	FFU3_1_SPEED_SV	:	REAL	;	//	FFU3_1设定转速
	FFU3_2_SPEED_SV	:	REAL	;	//	FFU3_2设定转速
	FFU3_3_SPEED_SV	:	REAL	;	//	FFU3_3设定转速
	FFU3_4_SPEED_SV	:	REAL	;	//	FFU3_4设定转速
	FFU3_5_SPEED_SV	:	REAL	;	//	FFU3_5设定转速
	FFU3_6_SPEED_SV	:	REAL	;	//	FFU3_6设定转速
	
	FFU1_1_EN		:	REAL	;	//	FFU1_1使能
	FFU1_2_EN		:	REAL	;	//	FFU1_2使能
	FFU1_3_EN		:	REAL	;	//	FFU1_3使能
	FFU1_4_EN		:	REAL	;	//	FFU1_4使能
	FFU1_5_EN		:	REAL	;	//	FFU1_5使能
	FFU1_6_EN		:	REAL	;	//	FFU1_6使能
	FFU2_1_EN		:	REAL	;	//	FFU2_1使能
	FFU2_2_EN		:	REAL	;	//	FFU2_2使能
	FFU2_3_EN		:	REAL	;	//	FFU2_3使能
	FFU2_4_EN		:	REAL	;	//	FFU2_4使能
	FFU2_5_EN		:	REAL	;	//	FFU2_5使能
	FFU2_6_EN		:	REAL	;	//	FFU2_6使能
	FFU3_1_EN		:	REAL	;	//	FFU3_1使能
	FFU3_2_EN		:	REAL	;	//	FFU3_2使能
	FFU3_3_EN		:	REAL	;	//	FFU3_3使能
	FFU3_4_EN		:	REAL	;	//	FFU3_4使能
	FFU3_5_EN		:	REAL	;	//	FFU3_5使能
	FFU3_6_EN		:	REAL	;	//	FFU3_6使能
		
END_STRUCT
END_TYPE

// ---- DUTs/_01_DUTs_PMC_PLC/dut_PLC_to_PMC.TcDUT
TYPE dut_PLC_to_PMC :
STRUCT
	bHeartBeatMonitor	: BOOL;		

	//interlock status
	DP					,
	BWR					,
	DPR1				,
	DPR2				,
	WAT_R				,
	WAT_F				,
	HTR1				,
	HTR2				,
	HTR3				,
	HTR4				,
	HTR5				,
	T_MNT				,
	T_REF				,
	DEPO				,
	CLN					,
	ECO					,
	AGV					,
	SP1					,
	PZ					,
	P_CONT				,
	DGZERO				,
	C_EXH				,
	F2_CLN				,
	F_N					
	: BOOL;
	
	//automatic valve status
	P_RUN				,
	LSC1_Level_HH		,
	LSC1_Level_H		,
	LSC1_Level_M		,
	LSC1_Level_L		,
	LSC1_OverFill		,
	LSC1_Ref_RDY		,
	T_REF_On			,
	D_Gas_OK			,
	DEPO_OK				,
	CLN_OK				,
	ATM					,
	F2_CLN_OK			,
	VAC1				,
	VAC2				,
	VAC3				,
	VAC4				,
	VAC5				
	: BOOL;
	

	aILK_AV				: ARRAY[1..250]	OF BOOL;
	aVAC				: ARRAY[1..10]	OF BOOL;
	bAV540				: BOOL;
	bBoatUnLoad_ILK		: BOOL;// boat unload condition
	stIntlk				: dut_Interlock ;
	
	
	//Gas box input
	
	I200_00			:BOOL;	//	PG3_LOW_ALARM
	I200_01			:BOOL;	//	PG3_HIGH_ALARM
	I200_02			:BOOL;	//	PG4_LOW_ALARM
	I200_03			:BOOL;	//	PG4_HIGH_ALARM
	I200_04			:BOOL;	//	PG5_LOW_ALARM
	I200_05			:BOOL;	//	PG5_HIGH_ALARM
	I200_06			:BOOL;	//	PG6_LOW_ALARM
	I200_07			:BOOL;	//	PG6_HIGH_ALARM
	I200_08			:BOOL;	//	PG7_LOW_ALARM
	I200_09			:BOOL;	//	PG7_HIGH_ALARM
	I200_10			:BOOL;	//	PG8_LOW_ALARM
	I200_11			:BOOL;	//	PG8_HIGH_ALARM
	I200_12			:BOOL;	//	PG31_LOW_ALARM
	I200_13			:BOOL;	//	PG31_HIGH_ALARM
	I200_14			:BOOL;	//	PG32_LOW_ALARM
	I200_15			:BOOL;	//	PG32_HIGH_ALARM
	I201_00			:BOOL;	//	LSC_H_LEVEL
	I201_01			:BOOL;	//	LSC_M_LEVEL
	I201_02			:BOOL;	//	LSC_L_LEVEL
	I201_03			:BOOL;	//	VG31_STATUS_OK
	I201_04			:BOOL;	//	VG31_LOW_ALARM
	I201_05			:BOOL;	//	VG31_HIGH_ALARM
	I201_06			:BOOL;	//	GD_FAN1_STOP
	I201_07			:BOOL;	//	GD_FAN2_STOP
	I201_08			:BOOL;	//	OX_MS1
	I201_09			:BOOL;	//	OX_MS2
	I201_10			:BOOL;	//	OX_MS3
	I201_11			:BOOL;	//	OX_MSI1
	I201_12			:BOOL;	//	OX_MSI2
	I201_13			:BOOL;	//	OX_RC1
	I201_14			:BOOL;	//	OX_RC2
	I201_15			:BOOL;	//	OX_RC3
	I202_00			:BOOL;	//	MS2_Pressure_LOW_ALARM
	I202_01			:BOOL;	//	MS2_Pressure_HIGH_ALARM
	I202_02			:BOOL;	//	MS321_Pressure_LOW_ALARM
	I202_03			:BOOL;	//	MS321_Pressure_HIGH_ALARM
	I202_04			:BOOL;	//	SPARE
	I202_05			:BOOL;	//	SPARE
	I202_06			:BOOL;	//	MP/PS20_Pressure_ALARM
	I202_07			:BOOL;	//	MP/PS11_Pressure_ALARM
	I202_08			:BOOL;	//	SPARE
	I202_09			:BOOL;	//	SPARE
	I202_10			:BOOL;	//	SPARE
	I202_11			:BOOL;	//	PG1_LOW_ALARM
	I202_12			:BOOL;	//	PG1_HIGH_ALARM
	I202_13			:BOOL;	//	PG2_LOW_ALARM
	I202_14			:BOOL;	//	PG2_HIGH_ALARM
	I202_15			:BOOL;	//	SPARE
	
	//Exhaust box input
	
	I300_00			:BOOL;	//	FS105_RHC_Flow_Alarm
	I300_01			:BOOL;	//	FS106_Heater_Jacket_Flow_Alarm
	I300_02			:BOOL;	//	FS202_Heater_Upper_Alarm
	I300_03			:BOOL;	//	FS104_Shutter_Flow_Alarm
	I300_04			:BOOL;	//	FS111_BoatRotation_Flow_Alarm
	I300_05			:BOOL;	//	FS102_Flange_Flow_Alarm
	I300_06			:BOOL;	//	Spare
	I300_07			:BOOL;	//	Spare
	I300_08			:BOOL;	//	VG11_Status_OK
	I300_09			:BOOL;	//	VG11_Low_Alarm
	I300_10			:BOOL;	//	VG11_High_Alarm
	I300_11			:BOOL;	//	VG13_Status_OK
	I300_12			:BOOL;	//	VG13_Low_Alarm
	I300_13			:BOOL;	//	VG13_High_Alarm
	I300_14			:BOOL;	//	AV71_Fan1_Alarm
	I300_15			:BOOL;	//	AV71_Fan2_Alarm
	I301_00			:BOOL;	//	DG1_Low_Limit_Alarm
	I301_01			:BOOL;	//	DG1_High_Limit_Alarm
	I301_02			:BOOL;	//	Spare
	I301_03			:BOOL;	//	Spare
	I301_04			:BOOL;	//	Spare
	I301_05			:BOOL;	//	Spare
	I301_06			:BOOL;	//	Spare
	I301_07			:BOOL;	//	Spare
	I301_08			:BOOL;	//	MP21/PS_Pressure_Low_Alarm
	I301_09			:BOOL;	//	FS101_MainWater_Flow_Alarm-1
	I301_10			:BOOL;	//	FS101_FMainWater_low_Alarm-2
	I301_11			:BOOL;	//	FL301_Flow_Switch
	I301_12			:BOOL;	//	FL72_Flow_Switch
	I301_13			:BOOL;	//	FS116_Zaxis_Flow_Alarm
	I301_14			:BOOL;	//	PS110_Pressure_Low_Alarm
	I301_15			:BOOL;	//	PS110_Pressure_High_Alarm
	I302_00			:BOOL;	//	PG/PS12_Pressure_Low_Alarm
	I302_01			:BOOL;	//	PG/PS12_Pressure_High_Alarm
	I302_02			:BOOL;	//	PS13_ATM_Status
	I302_03			:BOOL;	//	PS13_High_Limit_Alarm
	I302_04			:BOOL;	//	PG101_Water_Pressure_Low_Alarm
	I302_05			:BOOL;	//	PG101_Water_Pressure_High_Alarm
	I302_06			:BOOL;	//	VG14_Status_OK
	I302_07			:BOOL;	//	VG14_LOW_Alarm
	I302_08			:BOOL;	//	VG14_High_Alarm
	I302_09			:BOOL;	//	PS14_Pressure_Low_Alarm
	I302_10			:BOOL;	//	PS14_Pressure_High_Alarm
	I302_11			:BOOL;	//	Spare
	I302_12			:BOOL;	//	Spare
	I302_13			:BOOL;	//	Spare
	I302_14			:BOOL;	//	Spare
	I302_15			:BOOL;	//	Spare
	I303_00			:BOOL;	//	APC_Valve_Status
	I303_01			:BOOL;	//	APC_Alarm_Status
	I303_02			:BOOL;	//	RHC_Cooling_Air_cylinder1_Open
	I303_03			:BOOL;	//	RHC_Cooling_Air_cylinder1_Close
	I303_04			:BOOL;	//	RHC_Cooling_Air_cylinder2_Open
	I303_05			:BOOL;	//	RHC_Cooling_Air_cylinder2_Close
	I303_06			:BOOL;	//	RHC_Cooling_Valve_Open
	I303_07			:BOOL;	//	RHC_Cooling_Valve_Close
	I303_08			:BOOL;	//	RHC_Cooling_ButterflyValves_Open
	I303_09			:BOOL;	//	RHC_Cooling_ButterflyValves_Close
	I303_10			:BOOL;	//	Spare
	I303_11			:BOOL;	//	Spare
	I303_12			:BOOL;	//	GV_Open_NC
	I303_13			:BOOL;	//	GV_Open_NO
	I303_14			:BOOL;	//	GV_Close_NC
	I303_15			:BOOL;	//	GV_Close_NO
	I304_00			:BOOL;	//	RHC_Cooling_BallValve_Open
	I304_01			:BOOL;	//	RHC_Cooling_BallValve_Close
	I304_02			:BOOL;	//	Spare
	I304_03			:BOOL;	//	Spare
	I304_04			:BOOL;	//	Spare
	I304_05			:BOOL;	//	Spare
	I304_06			:BOOL;	//	Spare
	I304_07			:BOOL;	//	Spare
	I304_08			:BOOL;	//	Spare
	I304_09			:BOOL;	//	Spare
	I304_10			:BOOL;	//	Spare
	I304_11			:BOOL;	//	Spare
	I304_12			:BOOL;	//	Spare
	I304_13			:BOOL;	//	Spare
	I304_14			:BOOL;	//	Spare
	I304_15			:BOOL;	//	Spare	
	
	//Operation box input
	
	I600_00			:BOOL;	//	MS8_HC_ExhPress_LOW_ALARM
	I600_01			:BOOL;	//	MS8_HC_ExhPress_HIGH_ALARM
	I600_02			:BOOL;	//	MS1_Heater_ExhPress_LOW_ALARM
	I600_03			:BOOL;	//	MS1_Heater_ExhPress_HIGH_ALARM
	I600_04			:BOOL;	//	MS3_Scavenger_ExhPress_LOW_ALARM
	I600_05			:BOOL;	//	MS3_Scavenger_ExhPress_HIGH_ALARM
	I600_06			:BOOL;	//	MS6_Frontbody_ExhPress_LOW_ALARM
	I600_07			:BOOL;	//	MS6_Frontbody_ExhPress_HIGH_ALARM
	I600_08			:BOOL;	//	MS9_LSC1_ExhPress_LOW_ALARM
	I600_09			:BOOL;	//	MS9_LSC1_ExhPress_HIGH_ALARM
	I600_10			:BOOL;	//	MS11_GasBox_ExhPress_LOW_ALARM
	I600_11			:BOOL;	//	MS11_GasBox_ExhPress_HIGH_ALARM
	I600_12			:BOOL;	//	MS12_GasBox_ExhPress_LOW_ALARM
	I600_13			:BOOL;	//	MS12_GasBox_ExhPress_HIGH_ALARM
	I600_14			:BOOL;	//	SPARE
	I600_15			:BOOL;	//	SPARE
	
	//Sensor reading value
	
	PG3_Pressure		,	// IW250
	PG4_Pressure		,	// IW251
	PG5_Pressure		,	// IW252
	PG6_Pressure		,	// IW253
	PG7_Pressure		,	// IW254
	PG8_Pressure		,	// IW255
	PG31_Pressure		,	// IW256
	PG32_Pressure		,	// IW257
	VG31_Pressure		,	// IW258
	PG2_Pressure		,	// IW259
	PS11_Pressure		,	// IW260
	PG1_Pressure		,	// IW261
	MS2_Gasboxleft		,	// IW262
	MS5_Loadingarea		,	// IW263
	OX_Value			,	// IW264
                   	
	PG21_Pressure		,	// IW266
	PG22_Pressure		,	// IW267
	PG23_Pressure		,	// IW268
	PS33_Pressure		,	// IW269
	

	FS105_Flow			,	// IW300
	FS106_Flow          ,   // IW301
	FS202_Flow          ,   // IW302
	FS104_Flow          ,   // IW303
	FS111_Flow          ,   // IW304
	FS102_Flow          ,   // IW305
	DG1_Pressure        ,   // IW308
	FS116_Flow          ,   // IW311
	PS13_Pressure       ,   // IW312
	PS21_Pressure    	,   // IW318
	PS110_Pressure      ,   // IW319
	PG12_Pressure    	,   // IW320
	VG14_Pressure       ,   // IW321
	PS14_Pressure       ,   // IW322
	MS8_RHC_ExhPress    ,  	// IW332
	
	
	(*MS8_RHC_ExhPress		// IW600*)
	MS1_Heater			,	// IW601
	MS3_Scavenger		,	// IW602
	MS6_Frontbody		,	// IW603
	MS9_LSC1			,	// IW604
	MS11_GasBox			,	// IW605
	MS12_GasBox				// IW606
	:REAL;
	
	//FFU
	FFU1_1_STATUS	:	REAL	;	//	FFU1_1运行状态	
	FFU1_2_STATUS	:	REAL	;	//	FFU1_2运行状态	
	FFU1_3_STATUS	:	REAL	;	//	FFU1_3运行状态	
	FFU1_4_STATUS	:	REAL	;	//	FFU1_4运行状态	
	FFU1_5_STATUS	:	REAL	;	//	FFU1_5运行状态	
	FFU1_6_STATUS	:	REAL	;	//	FFU1_6运行状态	
	FFU2_1_STATUS	:	REAL	;	//	FFU2_1运行状态	
	FFU2_2_STATUS	:	REAL	;	//	FFU2_2运行状态	
	FFU2_3_STATUS	:	REAL	;	//	FFU2_3运行状态	
	FFU2_4_STATUS	:	REAL	;	//	FFU2_4运行状态	
	FFU2_5_STATUS	:	REAL	;	//	FFU2_5运行状态	
	FFU2_6_STATUS	:	REAL	;	//	FFU2_6运行状态	
	FFU3_1_STATUS	:	REAL	;	//	FFU3_1运行状态	
	FFU3_2_STATUS	:	REAL	;	//	FFU3_2运行状态	
	FFU3_3_STATUS	:	REAL	;	//	FFU3_3运行状态	
	FFU3_4_STATUS	:	REAL	;	//	FFU3_4运行状态	
	FFU3_5_STATUS	:	REAL	;	//	FFU3_5运行状态	
	FFU3_6_STATUS	:	REAL	;	//	FFU3_6运行状态	
		
	FFU1_1_SPEED_PV	:	REAL	;	//	FFU1_1当前转速	
	FFU1_2_SPEED_PV	:	REAL	;	//	FFU1_2当前转速	
	FFU1_3_SPEED_PV	:	REAL	;	//	FFU1_3当前转速	
	FFU1_4_SPEED_PV	:	REAL	;	//	FFU1_4当前转速	
	FFU1_5_SPEED_PV	:	REAL	;	//	FFU1_5当前转速	
	FFU1_6_SPEED_PV	:	REAL	;	//	FFU1_6当前转速	
	FFU2_1_SPEED_PV	:	REAL	;	//	FFU2_1当前转速	
	FFU2_2_SPEED_PV	:	REAL	;	//	FFU2_2当前转速	
	FFU2_3_SPEED_PV	:	REAL	;	//	FFU2_3当前转速	
	FFU2_4_SPEED_PV	:	REAL	;	//	FFU2_4当前转速	
	FFU2_5_SPEED_PV	:	REAL	;	//	FFU2_5当前转速	
	FFU2_6_SPEED_PV	:	REAL	;	//	FFU2_6当前转速	
	FFU3_1_SPEED_PV	:	REAL	;	//	FFU3_1当前转速	
	FFU3_2_SPEED_PV	:	REAL	;	//	FFU3_2当前转速	
	FFU3_3_SPEED_PV	:	REAL	;	//	FFU3_3当前转速	
	FFU3_4_SPEED_PV	:	REAL	;	//	FFU3_4当前转速	
	FFU3_5_SPEED_PV	:	REAL	;	//	FFU3_5当前转速	
	FFU3_6_SPEED_PV	:	REAL	;	//	FFU3_6当前转速	
	
	
END_STRUCT
END_TYPE

// ---- DUTs/_09_DUTs_Function/dut_32Bits.TcDUT
TYPE dut_32Bits :
STRUCT
	
	bBit0	: BIT;
	bBit1	: BIT;
	bBit2	: BIT;
	bBit3	: BIT;
	bBit4	: BIT;
	bBit5	: BIT;
	bBit6	: BIT;
	bBit7	: BIT;
	bBit8	: BIT;
	bBit9	: BIT;
	bBit10	: BIT;
	bBit11	: BIT;
	bBit12	: BIT;
	bBit13	: BIT;
	bBit14	: BIT;
	bBit15	: BIT;
	bBit16	: BIT;
	bBit17	: BIT;
	bBit18	: BIT;
	bBit19	: BIT;
	bBit20	: BIT;
	bBit21	: BIT;
	bBit22	: BIT;
	bBit23	: BIT;
	bBit24	: BIT;
	bBit25	: BIT;
	bBit26	: BIT;
	bBit27	: BIT;
	bBit28	: BIT;
	bBit29	: BIT;
	bBit30	: BIT;
	bBit31	: BIT;
	
END_STRUCT
END_TYPE

// ---- DUTs/_09_DUTs_Function/dut_8Bits.TcDUT
TYPE dut_8Bits :
STRUCT
	v1 ,
	v2 ,
	v3 ,
	v4 ,
	v5 ,
	v6 ,
	v7 ,
	v8 
	:BIT;
END_STRUCT
END_TYPE

// ---- DUTs/_09_DUTs_Function/dut_UDINT_BOOL.TcDUT
TYPE dut_UDINT_BOOL :
UNION
	Data_UDINT	:UDINT;
	Data_Bit	:dut_32Bits;
END_UNION
END_TYPE

// ---- DUTs/_09_DUTs_Function/dut_USINT_BOOL.TcDUT
TYPE dut_USINT_BOOL :
UNION
	uUSINT 	: USINT;
	uBit  	: dut_8Bits;
END_UNION
END_TYPE

// ---- GVLs/AI.TcGVL
{attribute 'qualified_only'}
VAR_GLOBAL
	//FFU
	FFU1_1_STATUS	:	UINT	;	//	FFU1_1运行状态
	FFU1_2_STATUS	:	UINT	;	//	FFU1_2运行状态
	FFU1_3_STATUS	:	UINT	;	//	FFU1_3运行状态
	FFU1_4_STATUS	:	UINT	;	//	FFU1_4运行状态
	FFU1_5_STATUS	:	UINT	;	//	FFU1_5运行状态
	FFU1_6_STATUS	:	UINT	;	//	FFU1_6运行状态
	FFU2_1_STATUS	:	UINT	;	//	FFU2_1运行状态
	FFU2_2_STATUS	:	UINT	;	//	FFU2_2运行状态
	FFU2_3_STATUS	:	UINT	;	//	FFU2_3运行状态
	FFU2_4_STATUS	:	UINT	;	//	FFU2_4运行状态
	FFU2_5_STATUS	:	UINT	;	//	FFU2_5运行状态
	FFU2_6_STATUS	:	UINT	;	//	FFU2_6运行状态
	FFU3_1_STATUS	:	UINT	;	//	FFU3_1运行状态
	FFU3_2_STATUS	:	UINT	;	//	FFU3_2运行状态
	FFU3_3_STATUS	:	UINT	;	//	FFU3_3运行状态
	FFU3_4_STATUS	:	UINT	;	//	FFU3_4运行状态
	FFU3_5_STATUS	:	UINT	;	//	FFU3_5运行状态
	FFU3_6_STATUS	:	UINT	;	//	FFU3_6运行状态

	FFU1_1_SPEED_PV	:	UINT	;	//	FFU1_1当前转速
	FFU1_2_SPEED_PV	:	UINT	;	//	FFU1_2当前转速
	FFU1_3_SPEED_PV	:	UINT	;	//	FFU1_3当前转速
	FFU1_4_SPEED_PV	:	UINT	;	//	FFU1_4当前转速
	FFU1_5_SPEED_PV	:	UINT	;	//	FFU1_5当前转速
	FFU1_6_SPEED_PV	:	UINT	;	//	FFU1_6当前转速
	FFU2_1_SPEED_PV	:	UINT	;	//	FFU2_1当前转速
	FFU2_2_SPEED_PV	:	UINT	;	//	FFU2_2当前转速
	FFU2_3_SPEED_PV	:	UINT	;	//	FFU2_3当前转速
	FFU2_4_SPEED_PV	:	UINT	;	//	FFU2_4当前转速
	FFU2_5_SPEED_PV	:	UINT	;	//	FFU2_5当前转速
	FFU2_6_SPEED_PV	:	UINT	;	//	FFU2_6当前转速
	FFU3_1_SPEED_PV	:	UINT	;	//	FFU3_1当前转速
	FFU3_2_SPEED_PV	:	UINT	;	//	FFU3_2当前转速
	FFU3_3_SPEED_PV	:	UINT	;	//	FFU3_3当前转速
	FFU3_4_SPEED_PV	:	UINT	;	//	FFU3_4当前转速
	FFU3_5_SPEED_PV	:	UINT	;	//	FFU3_5当前转速
	FFU3_6_SPEED_PV	:	UINT	;	//	FFU3_6当前转速


END_VAR

// ---- GVLs/AO.TcGVL
{attribute 'qualified_only'}
VAR_GLOBAL

	//FFU
	FFU_ALARM_EN	:	UINT;	//报警输出使能
	FFU_HSPEED		:	UINT;	//转速上限
	FFU_LSPEED		:	UINT;	//转速下限
	
	FFU1_1_POWER_ON	:	UINT	;	//	0:停止，1：运行
	FFU1_2_POWER_ON	:	UINT	;	//	0:停止，1：运行
	FFU1_3_POWER_ON	:	UINT	;	//	0:停止，1：运行
	FFU1_4_POWER_ON	:	UINT	;	//	0:停止，1：运行
	FFU1_5_POWER_ON	:	UINT	;	//	0:停止，1：运行
	FFU1_6_POWER_ON	:	UINT	;	//	0:停止，1：运行
	FFU2_1_POWER_ON	:	UINT	;	//	0:停止，1：运行
	FFU2_2_POWER_ON	:	UINT	;	//	0:停止，1：运行
	FFU2_3_POWER_ON	:	UINT	;	//	0:停止，1：运行
	FFU2_4_POWER_ON	:	UINT	;	//	0:停止，1：运行
	FFU2_5_POWER_ON	:	UINT	;	//	0:停止，1：运行
	FFU2_6_POWER_ON	:	UINT	;	//	0:停止，1：运行
	FFU3_1_POWER_ON	:	UINT	;	//	0:停止，1：运行
	FFU3_2_POWER_ON	:	UINT	;	//	0:停止，1：运行
	FFU3_3_POWER_ON	:	UINT	;	//	0:停止，1：运行
	FFU3_4_POWER_ON	:	UINT	;	//	0:停止，1：运行
	FFU3_5_POWER_ON	:	UINT	;	//	0:停止，1：运行
	FFU3_6_POWER_ON	:	UINT	;	//	0:停止，1：运行

	FFU1_1_SPEED_SV	:	UINT	;	//	FFU1_1设定转速
	FFU1_2_SPEED_SV	:	UINT	;	//	FFU1_2设定转速
	FFU1_3_SPEED_SV	:	UINT	;	//	FFU1_3设定转速
	FFU1_4_SPEED_SV	:	UINT	;	//	FFU1_4设定转速
	FFU1_5_SPEED_SV	:	UINT	;	//	FFU1_5设定转速
	FFU1_6_SPEED_SV	:	UINT	;	//	FFU1_6设定转速
	FFU2_1_SPEED_SV	:	UINT	;	//	FFU2_1设定转速
	FFU2_2_SPEED_SV	:	UINT	;	//	FFU2_2设定转速
	FFU2_3_SPEED_SV	:	UINT	;	//	FFU2_3设定转速
	FFU2_4_SPEED_SV	:	UINT	;	//	FFU2_4设定转速
	FFU2_5_SPEED_SV	:	UINT	;	//	FFU2_5设定转速
	FFU2_6_SPEED_SV	:	UINT	;	//	FFU2_6设定转速
	FFU3_1_SPEED_SV	:	UINT	;	//	FFU3_1设定转速
	FFU3_2_SPEED_SV	:	UINT	;	//	FFU3_2设定转速
	FFU3_3_SPEED_SV	:	UINT	;	//	FFU3_3设定转速
	FFU3_4_SPEED_SV	:	UINT	;	//	FFU3_4设定转速
	FFU3_5_SPEED_SV	:	UINT	;	//	FFU3_5设定转速
	FFU3_6_SPEED_SV	:	UINT	;	//	FFU3_6设定转速

	FFU1_1_EN		:	UINT	;	//	FFU1_1使能
	FFU1_2_EN		:	UINT	;	//	FFU1_2使能
	FFU1_3_EN		:	UINT	;	//	FFU1_3使能
	FFU1_4_EN		:	UINT	;	//	FFU1_4使能
	FFU1_5_EN		:	UINT	;	//	FFU1_5使能
	FFU1_6_EN		:	UINT	;	//	FFU1_6使能
	FFU2_1_EN		:	UINT	;	//	FFU2_1使能
	FFU2_2_EN		:	UINT	;	//	FFU2_2使能
	FFU2_3_EN		:	UINT	;	//	FFU2_3使能
	FFU2_4_EN		:	UINT	;	//	FFU2_4使能
	FFU2_5_EN		:	UINT	;	//	FFU2_5使能
	FFU2_6_EN		:	UINT	;	//	FFU2_6使能
	FFU3_1_EN		:	UINT	;	//	FFU3_1使能
	FFU3_2_EN		:	UINT	;	//	FFU3_2使能
	FFU3_3_EN		:	UINT	;	//	FFU3_3使能
	FFU3_4_EN		:	UINT	;	//	FFU3_4使能
	FFU3_5_EN		:	UINT	;	//	FFU3_5使能
	FFU3_6_EN		:	UINT	;	//	FFU3_6使能

END_VAR

// ---- GVLs/GVL.TcGVL
{attribute 'qualified_only'}
VAR_GLOBAL
	stPLCtoPMC		:	dut_PLC_to_PMC ;	// PLC传送到PMC数据
	stPMCtoPLC		:	dut_PMC_to_PLC ;	// PMC传送到PLC数据
	
	bAV65Open		:BOOL;
	bAV65Close		:BOOL;
	bAV79Open		:BOOL;
	bAV79Close		:BOOL;
	bAV202Open		: BOOL;
	bAV202Close		: BOOL;
	bAV91Open		:BOOL;
	bAV91Close		:BOOL;
END_VAR

// ---- GVLs/GVL_IO_Mapping.TcGVL

VAR_GLOBAL
//***********************************************
//!!!!!以下对应实际硬件，绝对禁止在程序中使用!!!!
//***********************************************
	GB_EL1889 	AT %I*: ARRAY[1..3, 0..15] OF BOOL;
	GB_EL3164 	AT %I*: ARRAY[1..4, 1..4]  OF INT;
	GB_EL3124 	AT %I*: ARRAY[1..1, 1..4]  OF INT;
	GB_EL6022 	AT %Q*: ARRAY[1..1, 0..21] OF USINT;
	GB_EL2889 	AT %Q*: ARRAY[1..1, 0..15] OF BOOL;
	GB_EV		AT %Q*:	ARRAY[1..5] OF dut_EX260_SEC;
	
	EXH_EL1889  AT %I*: ARRAY[1..5, 0..15] OF BOOL;
	EXH_EL3124  AT %I*: ARRAY[1..5, 1..4]  OF INT;
	EXH_EL3164  AT %I*: ARRAY[1..4, 1..4]  OF INT;
	EXH_EL2889  AT %Q*: ARRAY[1..1, 0..15] OF BOOL;
	EXH_EV		AT %Q*:	ARRAY[1..1] OF dut_EX260_SEC;
	
	OP_EL1889   AT %I*: ARRAY[1..1, 0..15] OF BOOL;
	OP_EL3124   AT %I*: ARRAY[1..2, 1..4]  OF INT;
	
//***********************************************
//!!!!!以下对对应软件，允许在程序中使用
//***********************************************
	//程序内部使用输入
	stGBI			:	dut_GB_Input;
	stEXHI			:	dut_EXH_Input;
	stOPI			:	dut_OP_INPUT;
	
	//程序内部使用输出
	stGBQ			:	dut_GB_Output;
	stEXHQ			:	dut_EXH_Output;
	stOPQ			:	dut_OP_Output;
	
	
	stILK			:	dut_Interlock ;
	aILK_AV			:	ARRAY[1..250] OF BOOL ;
	aVAC			:	ARRAY[1..10]  OF BOOL ;
	
	aAV				:	ARRAY[1..250] OF BOOL ;
	bAV540			: 	BOOL;
	
END_VAR

// ---- POUs/_000_MainPro/MAIN.TcPOU
PROGRAM MAIN
VAR
	FFU:FFU;
	tHeatbeat					:Ton;
	tON							:TON;
	bAdsCommErr					:BOOL;
	tOFF						:TON;
	
	//CE远程桌面开启
	bEnableCerDisp:BOOL;
	NT_StartProcess_Test:NT_StartProcess;
	
END_VAR

FFU();
IOMapping();
Interlock();


// PLC建立心跳
tHeatbeat(IN:=NOT tHeatbeat.Q , PT:=T#1S , Q=> , ET=> );
IF tHeatbeat.Q THEN
	GVL.stPLCtoPMC.bHeartBeatMonitor			:=NOT GVL.stPLCtoPMC.bHeartBeatMonitor;
END_IF

// PLC监控PMC心跳
IF GVL.stPMCtoPLC.bHeartBeatMonitor THEN
	tON(IN:=GVL.stPMCtoPLC.bHeartBeatMonitor , PT:=T#2S , Q=> , ET=> );
	tOFF(IN:=FALSE , PT:=T#2S , Q=> , ET=> );
	IF tON.Q THEN
		bAdsCommErr					:=TRUE;
	ELSE
		bAdsCommErr					:=FALSE;
	END_IF
ELSE
	tOFF(IN:=NOT GVL.stPMCtoPLC.bHeartBeatMonitor , PT:=T#2S , Q=> , ET=> );
	tON(IN:=FALSE , PT:=T#2S , Q=> , ET=> );
	IF tOFF.Q THEN
		bAdsCommErr					:=TRUE;
	ELSE
		bAdsCommErr					:=FALSE;
	END_IF
END_IF


//CE远程桌面开启
NT_StartProcess_Test(
	NETID:= ,
	PATHSTR:='\windows\CerDisp.exe' ,
	DIRNAME:='\windows' ,
	COMNDLINE:= , 
	START:=bEnableCerDisp ,
	TMOUT:= , 
	BUSY=> , 
	ERR=> , 
	ERRID=> );

END_PROGRAM

// ---- POUs/_900_FB/FFU.TcPOU
FUNCTION_BLOCK FFU
VAR_INPUT
END_VAR
VAR_OUTPUT
END_VAR
VAR
    MBMaster			:ModbusRtuMaster_KL6x22B;  // ModbusRTU Master功能块
	STAGE				:INT;
	STAGE_BF			:INT;
	
	FFU_ALARM_EN		:UINT;	//报警输出使能
	FFU_HSPEED			:UINT;	//转速上限
	FFU_LSPEED			:UINT;	//转速下限
	
	DATA_READ			:ARRAY[1..18] OF UINT;
	DATA_WRITE			:ARRAY[1..18] OF UINT;
	
	FFU_AI_STATUS		:ARRAY[1..18] OF UINT;
	FFU_AI_SPEED_PV		:ARRAY[1..18] OF UINT;
	
	FFU_AO_CTRLWORD		:ARRAY[1..3] OF UINT;
	FFU_AO_POWER_ON		:ARRAY[1..18] OF UINT;
	FFU_AO_SPEED_SV		:ARRAY[1..18] OF WORD;
	FFU_AO_EN			:ARRAY[1..18] OF UINT;
	
	FFU_CTRLWORD_BUFFER	:ARRAY[1..3] OF UINT;
	FFU_POWER_ON_BUFFER	:ARRAY[1..18] OF UINT;
	FFU_SPEED_SV_BUFFER	:ARRAY[1..18] OF UINT;
	FFU_EN_BUFFER			:ARRAY[1..18] OF UINT;
	
	WRITE_EN1			:DINT;
	WRITE_EN2			:DINT;
	WRITE_EN3			:DINT;
	WRITE_EN4			:DINT;
	WRITE_EN5			:DINT;
	WRITE_EN6			:DINT;
	WRITE_EN7			:DINT;
	
	FORCE_WRITE_TIMES	:INT;
	FORCE_WRITE			:BOOL;
	ERRID				:INT;
	TEST1:BOOL;
	TEST2:BOOL;
	TEST3:BOOL;
	TEST4:BOOL;
	TEST5:BOOL;
	TEST6:BOOL;
	TEST7:BOOL;
END_VAR

//AI数据
	AI.	FFU1_1_STATUS	:=	FFU_AI_STATUS	[	1	]	;
	AI.	FFU1_2_STATUS	:=	FFU_AI_STATUS	[	2	]	;
	AI.	FFU1_3_STATUS	:=	FFU_AI_STATUS	[	3	]	;
	AI.	FFU1_4_STATUS	:=	FFU_AI_STATUS	[	4	]	;
	AI.	FFU1_5_STATUS	:=	FFU_AI_STATUS	[	5	]	;
	AI.	FFU1_6_STATUS	:=	FFU_AI_STATUS	[	6	]	;
	AI.	FFU2_1_STATUS	:=	FFU_AI_STATUS	[	7	]	;
	AI.	FFU2_2_STATUS	:=	FFU_AI_STATUS	[	8	]	;
	AI.	FFU2_3_STATUS	:=	FFU_AI_STATUS	[	9	]	;
	AI.	FFU2_4_STATUS	:=	FFU_AI_STATUS	[	10	]	;
	AI.	FFU2_5_STATUS	:=	FFU_AI_STATUS	[	11	]	;
	AI.	FFU2_6_STATUS	:=	FFU_AI_STATUS	[	12	]	;
	AI.	FFU3_1_STATUS	:=	FFU_AI_STATUS	[	13	]	;
	AI.	FFU3_2_STATUS	:=	FFU_AI_STATUS	[	14	]	;
	AI.	FFU3_3_STATUS	:=	FFU_AI_STATUS	[	15	]	;
	AI.	FFU3_4_STATUS	:=	FFU_AI_STATUS	[	16	]	;
	AI.	FFU3_5_STATUS	:=	FFU_AI_STATUS	[	17	]	;
	AI.	FFU3_6_STATUS	:=	FFU_AI_STATUS	[	18	]	;
								
	AI.	FFU1_1_SPEED_PV	:=	FFU_AI_SPEED_PV	[	1	]	;
	AI.	FFU1_2_SPEED_PV	:=	FFU_AI_SPEED_PV	[	2	]	;
	AI.	FFU1_3_SPEED_PV	:=	FFU_AI_SPEED_PV	[	3	]	;
	AI.	FFU1_4_SPEED_PV	:=	FFU_AI_SPEED_PV	[	4	]	;
	AI.	FFU1_5_SPEED_PV	:=	FFU_AI_SPEED_PV	[	5	]	;
	AI.	FFU1_6_SPEED_PV	:=	FFU_AI_SPEED_PV	[	6	]	;
	AI.	FFU2_1_SPEED_PV	:=	FFU_AI_SPEED_PV	[	7	]	;
	AI.	FFU2_2_SPEED_PV	:=	FFU_AI_SPEED_PV	[	8	]	;
	AI.	FFU2_3_SPEED_PV	:=	FFU_AI_SPEED_PV	[	9	]	;
	AI.	FFU2_4_SPEED_PV	:=	FFU_AI_SPEED_PV	[	10	]	;
	AI.	FFU2_5_SPEED_PV	:=	FFU_AI_SPEED_PV	[	11	]	;
	AI.	FFU2_6_SPEED_PV	:=	FFU_AI_SPEED_PV	[	12	]	;
	AI.	FFU3_1_SPEED_PV	:=	FFU_AI_SPEED_PV	[	13	]	;
	AI.	FFU3_2_SPEED_PV	:=	FFU_AI_SPEED_PV	[	14	]	;
	AI.	FFU3_3_SPEED_PV	:=	FFU_AI_SPEED_PV	[	15	]	;
	AI.	FFU3_4_SPEED_PV	:=	FFU_AI_SPEED_PV	[	16	]	;
	AI.	FFU3_5_SPEED_PV	:=	FFU_AI_SPEED_PV	[	17	]	;
	AI.	FFU3_6_SPEED_PV	:=	FFU_AI_SPEED_PV	[	18	]	;

//AO数据比较
	FFU_AO_CTRLWORD	[	1	]	:=	AO.	FFU_ALARM_EN	;
	FFU_AO_CTRLWORD	[	2	]	:=	AO.	FFU_LSPEED		;
	FFU_AO_CTRLWORD	[	3	]	:=	AO.	FFU_HSPEED	;
								
	FFU_AO_POWER_ON	[	1	]	:=	AO.	FFU1_1_POWER_ON	;
	FFU_AO_POWER_ON	[	2	]	:=	AO.	FFU1_2_POWER_ON	;
	FFU_AO_POWER_ON	[	3	]	:=	AO.	FFU1_3_POWER_ON	;
	FFU_AO_POWER_ON	[	4	]	:=	AO.	FFU1_4_POWER_ON	;
	FFU_AO_POWER_ON	[	5	]	:=	AO.	FFU1_5_POWER_ON	;
	FFU_AO_POWER_ON	[	6	]	:=	AO.	FFU1_6_POWER_ON	;
	FFU_AO_POWER_ON	[	7	]	:=	AO.	FFU2_1_POWER_ON	;
	FFU_AO_POWER_ON	[	8	]	:=	AO.	FFU2_2_POWER_ON	;
	FFU_AO_POWER_ON	[	9	]	:=	AO.	FFU2_3_POWER_ON	;
	FFU_AO_POWER_ON	[	10	]	:=	AO.	FFU2_4_POWER_ON	;
	FFU_AO_POWER_ON	[	11	]	:=	AO.	FFU2_5_POWER_ON	;
	FFU_AO_POWER_ON	[	12	]	:=	AO.	FFU2_6_POWER_ON	;
	FFU_AO_POWER_ON	[	13	]	:=	AO.	FFU3_1_POWER_ON	;
	FFU_AO_POWER_ON	[	14	]	:=	AO.	FFU3_2_POWER_ON	;
	FFU_AO_POWER_ON	[	15	]	:=	AO.	FFU3_3_POWER_ON	;
	FFU_AO_POWER_ON	[	16	]	:=	AO.	FFU3_4_POWER_ON	;
	FFU_AO_POWER_ON	[	17	]	:=	AO.	FFU3_5_POWER_ON	;
	FFU_AO_POWER_ON	[	18	]	:=	AO.	FFU3_6_POWER_ON	;
								
	FFU_AO_SPEED_SV	[	1	]	:=	AO.	FFU1_1_SPEED_SV	;
	FFU_AO_SPEED_SV	[	2	]	:=	AO.	FFU1_2_SPEED_SV	;
	FFU_AO_SPEED_SV	[	3	]	:=	AO.	FFU1_3_SPEED_SV	;
	FFU_AO_SPEED_SV	[	4	]	:=	AO.	FFU1_4_SPEED_SV	;
	FFU_AO_SPEED_SV	[	5	]	:=	AO.	FFU1_5_SPEED_SV	;
	FFU_AO_SPEED_SV	[	6	]	:=	AO.	FFU1_6_SPEED_SV	;
	FFU_AO_SPEED_SV	[	7	]	:=	AO.	FFU2_1_SPEED_SV	;
	FFU_AO_SPEED_SV	[	8	]	:=	AO.	FFU2_2_SPEED_SV	;
	FFU_AO_SPEED_SV	[	9	]	:=	AO.	FFU2_3_SPEED_SV	;
	FFU_AO_SPEED_SV	[	10	]	:=	AO.	FFU2_4_SPEED_SV	;	
	FFU_AO_SPEED_SV	[	11	]	:=	AO.	FFU2_5_SPEED_SV	;
	FFU_AO_SPEED_SV	[	12	]	:=	AO.	FFU2_6_SPEED_SV	;
	FFU_AO_SPEED_SV	[	13	]	:=	AO.	FFU3_1_SPEED_SV	;
	FFU_AO_SPEED_SV	[	14	]	:=	AO.	FFU3_2_SPEED_SV	;
	FFU_AO_SPEED_SV	[	15	]	:=	AO.	FFU3_3_SPEED_SV	;
	FFU_AO_SPEED_SV	[	16	]	:=	AO.	FFU3_4_SPEED_SV	;
	FFU_AO_SPEED_SV	[	17	]	:=	AO.	FFU3_5_SPEED_SV	;
	FFU_AO_SPEED_SV	[	18	]	:=	AO.	FFU3_6_SPEED_SV	;
	
	FFU_AO_EN	[	1	]	:=	AO.	FFU1_1_EN	;
	FFU_AO_EN	[	2	]	:=	AO.	FFU1_2_EN	;
	FFU_AO_EN	[	3	]	:=	AO.	FFU1_3_EN	;
	FFU_AO_EN	[	4	]	:=	AO.	FFU1_4_EN	;
	FFU_AO_EN	[	5	]	:=	AO.	FFU1_5_EN	;
	FFU_AO_EN	[	6	]	:=	AO.	FFU1_6_EN	;
	FFU_AO_EN	[	7	]	:=	AO.	FFU2_1_EN	;
	FFU_AO_EN	[	8	]	:=	AO.	FFU2_2_EN	;
	FFU_AO_EN	[	9	]	:=	AO.	FFU2_3_EN	;
	FFU_AO_EN	[	10	]	:=	AO.	FFU2_4_EN	;	
	FFU_AO_EN	[	11	]	:=	AO.	FFU2_5_EN	;
	FFU_AO_EN	[	12	]	:=	AO.	FFU2_6_EN	;
	FFU_AO_EN	[	13	]	:=	AO.	FFU3_1_EN	;
	FFU_AO_EN	[	14	]	:=	AO.	FFU3_2_EN	;
	FFU_AO_EN	[	15	]	:=	AO.	FFU3_3_EN	;
	FFU_AO_EN	[	16	]	:=	AO.	FFU3_4_EN	;
	FFU_AO_EN	[	17	]	:=	AO.	FFU3_5_EN	;
	FFU_AO_EN	[	18	]	:=	AO.	FFU3_6_EN	;



	WRITE_EN1:=MEMCMP(pBuf1:=ADR(FFU_AO_CTRLWORD) , pBuf2:= ADR(FFU_CTRLWORD_BUFFER), n:=SIZEOF(FFU_CTRLWORD_BUFFER) );
	
	WRITE_EN2:=MEMCMP(pBuf1:=ADR(FFU_AO_POWER_ON) , pBuf2:= ADR(FFU_POWER_ON_BUFFER), n:=SIZEOF(FFU_POWER_ON_BUFFER) );
	
	WRITE_EN3:=MEMCMP(pBuf1:=ADR(FFU_AO_SPEED_SV) , pBuf2:= ADR(FFU_SPEED_SV_BUFFER), n:=SIZEOF(FFU_SPEED_SV_BUFFER) );
	
	WRITE_EN4:=MEMCMP(pBuf1:=ADR(FFU_AO_EN) , pBuf2:= ADR(FFU_EN_BUFFER), n:=SIZEOF(FFU_EN_BUFFER) );
	
	
	
IF FORCE_WRITE_TIMES>=1000 
	THEN 
	FORCE_WRITE:=TRUE;	
END_IF


(*
	MBMaster.WriteRegs(
	UnitID:= 1, 
	Quantity:= 18, 
	MBAddr:= 16#401, 
	cbLength:= SIZEOF(FFU_AO_SPEED_SV), 
	pMemoryAddr:= ADR(FFU_AO_SPEED_SV), 
	Execute:= TEST6,//TRUE, 
	Timeout:= T#2000MS,
	);
	TEST6:=FALSE;
	MBMaster.BUSY;
	MBMaster.Error;
	MBMaster.ErrorId;
*)
(*
	MBMaster.ReadRegs(
	UnitID:= 1, 
	Quantity:= 18, 
	MBAddr:= 257, 
	cbLength:= SIZEOF(FFU_AI_STATUS), 
	pMemoryAddr:= ADR(FFU_AI_STATUS), 
	Execute:= TEST1,//TRUE, 
	Timeout:= T#200MS, 
	 );
	ERRID:= MBMaster.ErrorId;
	IF NOT MBMaster.BUSY THEN
		TEST1:=FALSE; 
		//MBMaster.ReadRegs(Execute:=FALSE,);
		//FORCE_WRITE_TIMES:=FORCE_WRITE_TIMES+1;
		STAGE:=2;
	END_IF
*)

CASE STAGE OF 
	0://首次通讯
	STAGE:=1;
	
	1://读状态
	MBMaster.ReadRegs(
	UnitID:= 1, 
	Quantity:= 18, 
	MBAddr:= 257, 
	cbLength:= SIZEOF(FFU_AI_STATUS), 
	pMemoryAddr:= ADR(FFU_AI_STATUS), 
	Execute:= TRUE, 
	Timeout:= T#200MS, 
	 );
	IF NOT MBMaster.BUSY THEN
		//TEST1:=FALSE; 
		MBMaster.ReadRegs(Execute:=FALSE,);
		FORCE_WRITE_TIMES:=FORCE_WRITE_TIMES+1;
		STAGE:=2;
	END_IF
	
	2://读转速
	MBMaster.ReadRegs(
	UnitID:= 1, 
	Quantity:= 18, 
	MBAddr:= 513, 
	cbLength:= SIZEOF(FFU_AI_SPEED_PV), 
	pMemoryAddr:= ADR(FFU_AI_SPEED_PV), 
	Execute:= TRUE, 
	Timeout:= T#200MS, 
	 );
	IF NOT MBMaster.BUSY THEN
		//TEST2:=FALSE; 
		MBMaster.ReadRegs(Execute:=FALSE,);
		FORCE_WRITE_TIMES:=FORCE_WRITE_TIMES+1;
		STAGE:=3;
	END_IF
	
	3://数值变更判断
	IF WRITE_EN1<>0 OR FORCE_WRITE
		THEN
		STAGE:=4;
		ELSIF WRITE_EN2<>0
			THEN
			STAGE:=5;
			ELSIF WRITE_EN3<>0
				THEN
				STAGE:=6;
				ELSIF WRITE_EN4<>0
					THEN
					STAGE:=7;
					ELSIF WRITE_EN5<>0
						THEN
						STAGE:=8;				
	ELSE
		STAGE:=1;
	END_IF
	
	4://写控制字
	MBMaster.WriteRegs(
	UnitID:= 1, 
	Quantity:= 3, 
	MBAddr:= 2, 
	cbLength:= SIZEOF(FFU_AO_CTRLWORD), 
	pMemoryAddr:= ADR(FFU_AO_CTRLWORD), 
	Execute:= TRUE, 
	Timeout:= T#200MS,
	);
	IF NOT MBMaster.BUSY THEN 
		//TEST4:=FALSE;
		MBMaster.WriteRegs(Execute:=FALSE,);
		MEMCPY(destAddr:= ADR(FFU_CTRLWORD_BUFFER), srcAddr:= ADR(FFU_AO_CTRLWORD), n:= SIZEOF(FFU_AO_CTRLWORD));
		IF NOT FORCE_WRITE
		THEN
		STAGE:=1;
		ELSE
		STAGE:=5;
		END_IF		
	END_IF
	
	5://写启停
	MBMaster.WriteRegs(
	UnitID:= 1, 
	Quantity:= 18, 
	MBAddr:= 769, 
	cbLength:= SIZEOF(FFU_AO_POWER_ON), 
	pMemoryAddr:= ADR(FFU_AO_POWER_ON), 
	Execute:= TRUE, 
	Timeout:= T#200MS,
	);
	IF NOT MBMaster.BUSY THEN 
		//TEST5:=FALSE;
		MBMaster.WriteRegs(Execute:=FALSE,);
		MEMCPY(destAddr:= ADR(FFU_POWER_ON_BUFFER), srcAddr:= ADR(FFU_AO_POWER_ON), n:= SIZEOF(FFU_AO_POWER_ON));
		IF NOT FORCE_WRITE
		THEN
		STAGE:=1;
		ELSE
		STAGE:=6;
		END_IF		
	END_IF
	
	6://写转速
	MBMaster.WriteRegs(
	UnitID:= 1, 
	Quantity:= 18, 
	MBAddr:= 1025, 
	cbLength:= SIZEOF(FFU_AO_SPEED_SV), 
	pMemoryAddr:= ADR(FFU_AO_SPEED_SV), 
	Execute:= TRUE, 
	Timeout:= T#200MS,
	);
	IF NOT MBMaster.BUSY THEN 
		//TEST6:=FALSE;
		MBMaster.WriteRegs(Execute:=FALSE,);
		MEMCPY(destAddr:= ADR(FFU_SPEED_SV_BUFFER), srcAddr:= ADR(FFU_AO_SPEED_SV), n:= SIZEOF(FFU_AO_SPEED_SV));
		IF NOT FORCE_WRITE
		THEN
		STAGE:=1;
		ELSE
		STAGE:=7;
		END_IF		
	END_IF
	
	7://写使能
	MBMaster.WriteRegs(
	UnitID:= 1, 
	Quantity:= 18, 
	MBAddr:= 1281, 
	cbLength:= SIZEOF(FFU_AO_EN), 
	pMemoryAddr:= ADR(FFU_AO_EN), 
	Execute:= TRUE, 
	Timeout:= T#200MS,
	);
	IF NOT MBMaster.BUSY THEN 
		//TEST7:=FALSE;
		MBMaster.WriteRegs(Execute:=FALSE,);
		MEMCPY(destAddr:= ADR(FFU_EN_BUFFER), srcAddr:= ADR(FFU_AO_EN), n:= SIZEOF(FFU_AO_EN));
		STAGE:=1;
		IF FORCE_WRITE
		THEN
		FORCE_WRITE_TIMES:=0;
		FORCE_WRITE:=FALSE;
		END_IF		
	END_IF	
END_CASE

END_FUNCTION_BLOCK

// ---- POUs/_100_IOMapping/IOMapping.TcPOU
PROGRAM IOMapping
VAR
	GasAnalogRead	: ARRAY[250..269] OF AnalogConverter ;
	ExhAnalogRead	: ARRAY[300..335] OF AnalogConverter ;
	OpAnalogRead	: ARRAY[600..607] OF AnalogConverter ;
	AV				: ARRAY[1..250] OF Valve ;
	bEMOStatus		: BOOL;
	aForceOpValve	: ARRAY[1..250] OF BOOL;
	AV65Open: Valve;
	bForceAV65Open: BOOL;
	AV65Close: Valve;
	bForceAV65Close: BOOL;
	AV202Open: Valve;
	AV202Close:Valve ;
	bForceAV202Open: BOOL;
	bForceAV202Close: BOOL;
	AV79Open: Valve;
	bForceAV79Open: BOOL;
	bForceAV79Close: BOOL;
	AV79Close: Valve;
	rO2Range: REAL;
	AV91Open: Valve;
	bForceAV91Open: BOOL;
	AV91Close: Valve;
	bForceAV91Close: BOOL;
END_VAR

Input();
Output();
Analog();
ValveCtrl();
ValveMapping();
PLC_to_PMC();
PMC_to_PLC();

ACTION Analog:
//模拟量读值转换实际读值程序
GasAnalogRead[250](	// PG/PS3 NH3 in pipe pressure
	AnalogRdValue_In_Int:= stGBI.IW250 , 
	AnalogResMin_In_Int:= 0 , 
	AnalogResMax_In_Int:= 32767 , 
	AnalogPhyMin_In_Real:= -0.1 , 
	AnalogPhyMax_In_Real:= 1 , 
	AnalogRdOffset_In_Real:= , 
	ActRdValue_Out_Real=> GVL.stPLCtoPMC.PG3_Pressure );
	
GasAnalogRead[251](	// PG/PS4 NH3-2 in pipe pressure
	AnalogRdValue_In_Int:= stGBI.IW251 , 
	AnalogResMin_In_Int:= 0 , 
	AnalogResMax_In_Int:= 32767 , 
	AnalogPhyMin_In_Real:= -0.1 , 
	AnalogPhyMax_In_Real:= 1 , 
	AnalogRdOffset_In_Real:= , 
	ActRdValue_Out_Real=> GVL.stPLCtoPMC.PG4_Pressure );

GasAnalogRead[252](	// PG/PS5 SiH4 in pipe pressure
	AnalogRdValue_In_Int:= stGBI.IW252 , 
	AnalogResMin_In_Int:= 0 , 
	AnalogResMax_In_Int:= 32767 , 
	AnalogPhyMin_In_Real:= -0.1 , 
	AnalogPhyMax_In_Real:= 1 , 
	AnalogRdOffset_In_Real:= , 
	ActRdValue_Out_Real=> GVL.stPLCtoPMC.PG5_Pressure );

GasAnalogRead[253](	// PG/PS6 N2-2 in pipe pressure
	AnalogRdValue_In_Int:= stGBI.IW253 , 
	AnalogResMin_In_Int:= 0 , 
	AnalogResMax_In_Int:= 32767 , 
	AnalogPhyMin_In_Real:= -0.1 , 
	AnalogPhyMax_In_Real:= 1 , 
	AnalogRdOffset_In_Real:= , 
	ActRdValue_Out_Real=> GVL.stPLCtoPMC.PG6_Pressure );
	
GasAnalogRead[254](	// PG/PS7 NF3 in pipe pressure
	AnalogRdValue_In_Int:= stGBI.IW254 , 
	AnalogResMin_In_Int:= 0 , 
	AnalogResMax_In_Int:= 32767 , 
	AnalogPhyMin_In_Real:= -0.1 , 
	AnalogPhyMax_In_Real:= 1 , 
	AnalogRdOffset_In_Real:= , 
	ActRdValue_Out_Real=> GVL.stPLCtoPMC.PG7_Pressure );
	
GasAnalogRead[255](	// PG/PS8 20%F2/N2 in pipe pressure
	AnalogRdValue_In_Int:= stGBI.IW255 ,  
	AnalogResMin_In_Int:= 0 , 
	AnalogResMax_In_Int:= 32767 , 
	AnalogPhyMin_In_Real:= -0.1 , 
	AnalogPhyMax_In_Real:= 1 , 
	AnalogRdOffset_In_Real:= , 
	ActRdValue_Out_Real=> GVL.stPLCtoPMC.PG8_Pressure );
	
GasAnalogRead[256](	// PG/PS31 N2-10 in pipe pressure
	AnalogRdValue_In_Int:= stGBI.IW256 , 
	AnalogResMin_In_Int:= 0 , 
	AnalogResMax_In_Int:= 32767 , 
	AnalogPhyMin_In_Real:= -0.1 , 
	AnalogPhyMax_In_Real:= 1 , 
	AnalogRdOffset_In_Real:= , 
	ActRdValue_Out_Real=> GVL.stPLCtoPMC.PG31_Pressure );
	
GasAnalogRead[257](	// PG/PS32 N2-11 in pipe pressure
	AnalogRdValue_In_Int:= stGBI.IW257 , 
	AnalogResMin_In_Int:= 0 , 
	AnalogResMax_In_Int:= 32767 , 
	AnalogPhyMin_In_Real:= -0.1 , 
	AnalogPhyMax_In_Real:= 1 , 
	AnalogRdOffset_In_Real:= , 
	ActRdValue_Out_Real=> GVL.stPLCtoPMC.PG32_Pressure );
	
GasAnalogRead[258](	// VG31 tank-1 backward pipe pressure (0~100torr)
	AnalogRdValue_In_Int:= stGBI.IW258 , 
	AnalogResMin_In_Int:= 0 , 
	AnalogResMax_In_Int:= 32767 , 
	AnalogPhyMin_In_Real:= 0 , 
	AnalogPhyMax_In_Real:= 100 , 
	AnalogRdOffset_In_Real:= , 
	ActRdValue_Out_Real=> GVL.stPLCtoPMC.VG31_Pressure );
	
GasAnalogRead[259](	// PG/PS2 HCL pressure
	AnalogRdValue_In_Int:= stGBI.IW259 , 
	AnalogResMin_In_Int:= 0 , 
	AnalogResMax_In_Int:= 32767 , 
	AnalogPhyMin_In_Real:= -0.1 , 
	AnalogPhyMax_In_Real:= 1 , 
	AnalogRdOffset_In_Real:= , 
	ActRdValue_Out_Real=> GVL.stPLCtoPMC.OX_Value );
	
GasAnalogRead[260](	// PS11 N2-8 in pipe pressure
	AnalogRdValue_In_Int:= stGBI.IW260 , 
	AnalogResMin_In_Int:= 1996 , 
	AnalogResMax_In_Int:= 16383 , 
	AnalogPhyMin_In_Real:= 0 , 
	AnalogPhyMax_In_Real:= 1 , 
	AnalogRdOffset_In_Real:= , 
	ActRdValue_Out_Real=> GVL.stPLCtoPMC.PS11_Pressure );
	
GasAnalogRead[261](	// PG/PS1 N2-1 in pipe pressure
	AnalogRdValue_In_Int:= stGBI.IW261 , 
	AnalogResMin_In_Int:= 0 , 
	AnalogResMax_In_Int:= 32767 , 
	AnalogPhyMin_In_Real:= -0.1 , 
	AnalogPhyMax_In_Real:= 1 , 
	AnalogRdOffset_In_Real:= , 
	ActRdValue_Out_Real=> GVL.stPLCtoPMC.PG1_Pressure );
	
GasAnalogRead[262](	// MS2 gas box(左) exhaust pressure
	AnalogRdValue_In_Int:= stGBI.IW262 , 
	AnalogResMin_In_Int:= 0 , 
	AnalogResMax_In_Int:= 32767 , 
	AnalogPhyMin_In_Real:= 0 , 
	AnalogPhyMax_In_Real:= 200 , 
	AnalogRdOffset_In_Real:= , 
	ActRdValue_Out_Real=> GVL.stPLCtoPMC.MS2_Gasboxleft );
	
GasAnalogRead[263]( // MS5 loading area exhaust pressure
	AnalogRdValue_In_Int:= stGBI.IW263 , 
	AnalogResMin_In_Int:= 0 , 
	AnalogResMax_In_Int:= 32767 , 
	AnalogPhyMin_In_Real:= 0 , 
	AnalogPhyMax_In_Real:= 200 , 
	AnalogRdOffset_In_Real:= , 
	ActRdValue_Out_Real=> GVL.stPLCtoPMC.MS5_Loadingarea );
	

//O2 Range judgment
IF NOT stGBI.I201_13 AND stGBI.I201_14 AND stGBI.I201_15 THEN
	rO2Range := 1000000 ; // O2 range 0~100%
END_IF

IF stGBI.I201_13 AND NOT stGBI.I201_14 AND stGBI.I201_15 THEN
	rO2Range := 100000 ; // O2 range 0~10%
END_IF

IF NOT stGBI.I201_13 AND NOT stGBI.I201_14 AND stGBI.I201_15 THEN
	rO2Range := 10000 ; // O2 range 0~1%
END_IF

IF stGBI.I201_13 AND stGBI.I201_14 AND NOT stGBI.I201_15 THEN
	rO2Range := 1000 ; // O2 range 0~1000ppm
END_IF

IF NOT stGBI.I201_13 AND stGBI.I201_14 AND NOT stGBI.I201_15 THEN
	rO2Range := 100 ; // O2 range 0~100ppm
END_IF

IF stGBI.I201_13 AND NOT stGBI.I201_14 AND NOT stGBI.I201_15 THEN
	rO2Range := 10 ; // O2 range 0~10ppm
END_IF

GasAnalogRead[264](	// O2 concention
	AnalogRdValue_In_Int:= stGBI.IW264 ,  
	AnalogResMin_In_Int:= 0 , 
	AnalogResMax_In_Int:= 32767 , 
	AnalogPhyMin_In_Real:= 0 , 
	AnalogPhyMax_In_Real:= rO2Range , 
	AnalogRdOffset_In_Real:= , 
	ActRdValue_Out_Real=> GVL.stPLCtoPMC.OX_Value );
	
GasAnalogRead[265](	// spare
	AnalogRdValue_In_Int:= stGBI.IW265 , 
	AnalogResMin_In_Int:= 0 , 
	AnalogResMax_In_Int:= 32767 , 
	AnalogPhyMin_In_Real:= 0 , 
	AnalogPhyMax_In_Real:= 1 , 
	AnalogRdOffset_In_Real:= , 
	ActRdValue_Out_Real=> );
	
GasAnalogRead[266](	// PG/PS21 Tank-1 forward pipe pressure
	AnalogRdValue_In_Int:= stGBI.IW266 , 
	AnalogResMin_In_Int:= 3277 , 
	AnalogResMax_In_Int:= 16383 , 
	AnalogPhyMin_In_Real:= -100 , 
	AnalogPhyMax_In_Real:= 300 , 
	AnalogRdOffset_In_Real:= , 
	ActRdValue_Out_Real=> GVL.stPLCtoPMC.PG21_Pressure );
	
GasAnalogRead[267](	// PG/PS22 Tank-2 forward pipe pressure
	AnalogRdValue_In_Int:= stGBI.IW267 , 
	AnalogResMin_In_Int:= 3277 , 
	AnalogResMax_In_Int:= 16383 , 
	AnalogPhyMin_In_Real:= -100 , 
	AnalogPhyMax_In_Real:= 300 , 
	AnalogRdOffset_In_Real:= , 
	ActRdValue_Out_Real=> GVL.stPLCtoPMC.PG22_Pressure );
	
GasAnalogRead[268](	// PG/PS23 Tank-3 forward pipe pressure
	AnalogRdValue_In_Int:= stGBI.IW268 , 
	AnalogResMin_In_Int:= 3277 , 
	AnalogResMax_In_Int:= 16383 , 
	AnalogPhyMin_In_Real:= -100 , 
	AnalogPhyMax_In_Real:= 300 , 
	AnalogRdOffset_In_Real:= , 
	ActRdValue_Out_Real=> GVL.stPLCtoPMC.PG23_Pressure );
	
GasAnalogRead[269](	// PS33  LSC tank pressure
	AnalogRdValue_In_Int:= stGBI.IW269 ,  
	AnalogResMin_In_Int:= 3277 , 
	AnalogResMax_In_Int:= 16383 , 
	AnalogPhyMin_In_Real:= -100 , 
	AnalogPhyMax_In_Real:= 500 , 
	AnalogRdOffset_In_Real:= , 
	ActRdValue_Out_Real=> GVL.stPLCtoPMC.PS33_Pressure );	
	
ExhAnalogRead[300](	// FS105 RHC cooling water flow
	AnalogRdValue_In_Int:= stEXHI.IW300 , 
	AnalogResMin_In_Int:= 0 ,
	AnalogResMax_In_Int:= 32767 , 
	AnalogPhyMin_In_Real:= 0 , 
	AnalogPhyMax_In_Real:= 40 , 
	AnalogRdOffset_In_Real:= , 
	ActRdValue_Out_Real=> GVL.stPLCtoPMC.FS105_Flow );
	
ExhAnalogRead[301](	// FS106 Heater jacket cooling water flow
	AnalogRdValue_In_Int:= stEXHI.IW301 , 
	AnalogResMin_In_Int:= 0 ,
	AnalogResMax_In_Int:= 32767 , 
	AnalogPhyMin_In_Real:= 0 , 
	AnalogPhyMax_In_Real:= 16 , 
	AnalogRdOffset_In_Real:= , 
	ActRdValue_Out_Real=> GVL.stPLCtoPMC.FS106_Flow );
	
ExhAnalogRead[302](	// FS202 Furnace cooling water flow
	AnalogRdValue_In_Int:= stEXHI.IW302 , 
	AnalogResMin_In_Int:= 0 ,
	AnalogResMax_In_Int:= 32767 , 
	AnalogPhyMin_In_Real:= 0 , 
	AnalogPhyMax_In_Real:= 16 , 
	AnalogRdOffset_In_Real:= , 
	ActRdValue_Out_Real=> GVL.stPLCtoPMC.FS202_Flow );
	
ExhAnalogRead[303](	// FS104 Shutter cooling water flow
	AnalogRdValue_In_Int:= stEXHI.IW303 , 
	AnalogResMin_In_Int:= 0 ,
	AnalogResMax_In_Int:= 32767 , 
	AnalogPhyMin_In_Real:= 0 , 
	AnalogPhyMax_In_Real:= 4 , 
	AnalogRdOffset_In_Real:= , 
	ActRdValue_Out_Real=> GVL.stPLCtoPMC.FS104_Flow );
	
ExhAnalogRead[304](	// FS111 boat rotation cooling water flow
	AnalogRdValue_In_Int:= stEXHI.IW304 , 
	AnalogResMin_In_Int:= 0 ,
	AnalogResMax_In_Int:= 32767 , 
	AnalogPhyMin_In_Real:= 0 , 
	AnalogPhyMax_In_Real:= 4 , 
	AnalogRdOffset_In_Real:= , 
	ActRdValue_Out_Real=> GVL.stPLCtoPMC.FS111_Flow );
	
ExhAnalogRead[305](	// FS102 Flange cooling water flow
	AnalogRdValue_In_Int:= stEXHI.IW305 , 
	AnalogResMin_In_Int:= 0 ,
	AnalogResMax_In_Int:= 32767 , 
	AnalogPhyMin_In_Real:= 0 , 
	AnalogPhyMax_In_Real:= 4 , 
	AnalogRdOffset_In_Real:= , 
	ActRdValue_Out_Real=> GVL.stPLCtoPMC.FS102_Flow );
	
ExhAnalogRead[306](	// spare
	AnalogRdValue_In_Int:= stEXHI.IW306 , 
	AnalogResMin_In_Int:= 0 ,
	AnalogResMax_In_Int:= 32767 , 
	AnalogPhyMin_In_Real:= 0 , 
	AnalogPhyMax_In_Real:= 1 , 
	AnalogRdOffset_In_Real:= , 
	ActRdValue_Out_Real=> );
	
ExhAnalogRead[307](	// spare
	AnalogRdValue_In_Int:= stEXHI.IW307 , 
	AnalogResMin_In_Int:= 0 ,
	AnalogResMax_In_Int:= 32767 , 
	AnalogPhyMin_In_Real:= 0 , 
	AnalogPhyMax_In_Real:= 1 , 
	AnalogRdOffset_In_Real:= , 
	ActRdValue_Out_Real=> );
	
ExhAnalogRead[308](	// DG1 tube and loading area differential pressure
	AnalogRdValue_In_Int:= stEXHI.IW308 , 
	AnalogResMin_In_Int:= 0 ,
	AnalogResMax_In_Int:= 32767 , 
	AnalogPhyMin_In_Real:= -300 , 
	AnalogPhyMax_In_Real:= 300 , 
	AnalogRdOffset_In_Real:= , 
	ActRdValue_Out_Real=> GVL.stPLCtoPMC.DG1_Pressure );
	
ExhAnalogRead[309](	// spare
	AnalogRdValue_In_Int:= stEXHI.IW309 , 
	AnalogResMin_In_Int:= 0 ,
	AnalogResMax_In_Int:= 32767 , 
	AnalogPhyMin_In_Real:= 0 , 
	AnalogPhyMax_In_Real:= 1 , 
	AnalogRdOffset_In_Real:= , 
	ActRdValue_Out_Real=> );
	
ExhAnalogRead[310](	// spare
	AnalogRdValue_In_Int:= stEXHI.IW310 , 
	AnalogResMin_In_Int:= 0 ,
	AnalogResMax_In_Int:= 32767 , 
	AnalogPhyMin_In_Real:= 0 , 
	AnalogPhyMax_In_Real:= 1 , 
	AnalogRdOffset_In_Real:= , 
	ActRdValue_Out_Real=> );
	
ExhAnalogRead[311](	// FS116 Cooling unit flow
	AnalogRdValue_In_Int:= stEXHI.IW311 , 
	AnalogResMin_In_Int:= 0 ,
	AnalogResMax_In_Int:= 32767 , 
	AnalogPhyMin_In_Real:= 0 , 
	AnalogPhyMax_In_Real:= 16 , 
	AnalogRdOffset_In_Real:= , 
	ActRdValue_Out_Real=> GVL.stPLCtoPMC.FS116_Flow );
	
ExhAnalogRead[312](	// PS13 pressure
	AnalogRdValue_In_Int:= stEXHI.IW312 , 
	AnalogResMin_In_Int:= 0 ,
	AnalogResMax_In_Int:= 32767 , 
	AnalogPhyMin_In_Real:= 0 , 
	AnalogPhyMax_In_Real:= 98.1 , 
	AnalogRdOffset_In_Real:= , 
	ActRdValue_Out_Real=> GVL.stPLCtoPMC.PS13_Pressure );
	
ExhAnalogRead[313](	// spare
	AnalogRdValue_In_Int:= stEXHI.IW313 , 
	AnalogResMin_In_Int:= 0 ,
	AnalogResMax_In_Int:= 32767 , 
	AnalogPhyMin_In_Real:= 0 , 
	AnalogPhyMax_In_Real:= 1 , 
	AnalogRdOffset_In_Real:= , 
	ActRdValue_Out_Real=> );
	
ExhAnalogRead[314](	// spare
	AnalogRdValue_In_Int:= stEXHI.IW314 , 
	AnalogResMin_In_Int:= 0 ,
	AnalogResMax_In_Int:= 32767 , 
	AnalogPhyMin_In_Real:= 0 , 
	AnalogPhyMax_In_Real:= 1 , 
	AnalogRdOffset_In_Real:= , 
	ActRdValue_Out_Real=> );
	
ExhAnalogRead[315](	// spare
	AnalogRdValue_In_Int:= stEXHI.IW315 , 
	AnalogResMin_In_Int:= 0 ,
	AnalogResMax_In_Int:= 32767 , 
	AnalogPhyMin_In_Real:= 0 , 
	AnalogPhyMax_In_Real:= 1 , 
	AnalogRdOffset_In_Real:= , 
	ActRdValue_Out_Real=> );
	
ExhAnalogRead[316](	// spare
	AnalogRdValue_In_Int:= stEXHI.IW316 , 
	AnalogResMin_In_Int:= 0 ,
	AnalogResMax_In_Int:= 32767 , 
	AnalogPhyMin_In_Real:= 0 , 
	AnalogPhyMax_In_Real:= 1 , 
	AnalogRdOffset_In_Real:= , 
	ActRdValue_Out_Real=> );
	
ExhAnalogRead[317](	// spare
	AnalogRdValue_In_Int:= stEXHI.IW317 , 
	AnalogResMin_In_Int:= 0 ,
	AnalogResMax_In_Int:= 32767 , 
	AnalogPhyMin_In_Real:= 0 , 
	AnalogPhyMax_In_Real:= 1 , 
	AnalogRdOffset_In_Real:= , 
	ActRdValue_Out_Real=> );
	
ExhAnalogRead[318](	// PS21 N2-13 in pipe pressure 0.6~5V
	AnalogRdValue_In_Int:= stEXHI.IW318 , 
	AnalogResMin_In_Int:= 3276 ,
	AnalogResMax_In_Int:= 16383 , 
	AnalogPhyMin_In_Real:= -0.1 , 
	AnalogPhyMax_In_Real:= 1 , 
	AnalogRdOffset_In_Real:= , 
	ActRdValue_Out_Real=> GVL.stPLCtoPMC.PS21_Pressure );
	
ExhAnalogRead[319](	// PS110 exhaust pressure
	AnalogRdValue_In_Int:= stEXHI.IW319 , 
	AnalogResMin_In_Int:= 3276 ,
	AnalogResMax_In_Int:= 16383 , 
	AnalogPhyMin_In_Real:= -100 , 
	AnalogPhyMax_In_Real:= 100 , 
	AnalogRdOffset_In_Real:= , 
	ActRdValue_Out_Real=> GVL.stPLCtoPMC.PS110_Pressure );
	
ExhAnalogRead[320](	// PG/PS12 N2-9 in pipe pressure
	AnalogRdValue_In_Int:= stEXHI.IW320 , 
	AnalogResMin_In_Int:= 0 ,
	AnalogResMax_In_Int:= 32767 , 
	AnalogPhyMin_In_Real:= -0.1 , 
	AnalogPhyMax_In_Real:= 1 , 
	AnalogRdOffset_In_Real:= , 
	ActRdValue_Out_Real=> GVL.stPLCtoPMC.PG12_Pressure );
	
ExhAnalogRead[321](	// VG14 pressure
	AnalogRdValue_In_Int:= stEXHI.IW321 , 
	AnalogResMin_In_Int:= 0 ,
	AnalogResMax_In_Int:= 32767 , 
	AnalogPhyMin_In_Real:= 0 , 
	AnalogPhyMax_In_Real:= 10 , 
	AnalogRdOffset_In_Real:= , 
	ActRdValue_Out_Real=> GVL.stPLCtoPMC.VG14_Pressure );
	
ExhAnalogRead[322](	// PS14 pressure
	AnalogRdValue_In_Int:= stEXHI.IW322 , 
	AnalogResMin_In_Int:= 3276 ,
	AnalogResMax_In_Int:= 16383 , 
	AnalogPhyMin_In_Real:= -100 , 
	AnalogPhyMax_In_Real:= 100 , 
	AnalogRdOffset_In_Real:= , 
	ActRdValue_Out_Real=> GVL.stPLCtoPMC.PS14_Pressure );
	
ExhAnalogRead[323](	// spare
	AnalogRdValue_In_Int:= stEXHI.IW323 , 
	AnalogResMin_In_Int:= 0 ,
	AnalogResMax_In_Int:= 32767 , 
	AnalogPhyMin_In_Real:= 0 , 
	AnalogPhyMax_In_Real:= 1 , 
	AnalogRdOffset_In_Real:= , 
	ActRdValue_Out_Real=> );
	
ExhAnalogRead[324](	// spare
	AnalogRdValue_In_Int:= stEXHI.IW324 , 
	AnalogResMin_In_Int:= 0 ,
	AnalogResMax_In_Int:= 32767 , 
	AnalogPhyMin_In_Real:= 0 , 
	AnalogPhyMax_In_Real:= 1 , 
	AnalogRdOffset_In_Real:= , 
	ActRdValue_Out_Real=> );
	
ExhAnalogRead[325](	// spare
	AnalogRdValue_In_Int:= stEXHI.IW325 , 
	AnalogResMin_In_Int:= 0 ,
	AnalogResMax_In_Int:= 32767 , 
	AnalogPhyMin_In_Real:= 0 , 
	AnalogPhyMax_In_Real:= 1 , 
	AnalogRdOffset_In_Real:= , 
	ActRdValue_Out_Real=> );
	
ExhAnalogRead[326](	// spare
	AnalogRdValue_In_Int:= stEXHI.IW326 , 
	AnalogResMin_In_Int:= 0 ,
	AnalogResMax_In_Int:= 32767 , 
	AnalogPhyMin_In_Real:= 0 , 
	AnalogPhyMax_In_Real:= 1 , 
	AnalogRdOffset_In_Real:= , 
	ActRdValue_Out_Real=> );
	
ExhAnalogRead[327](	// spare
	AnalogRdValue_In_Int:= stEXHI.IW327 , 
	AnalogResMin_In_Int:= 0 ,
	AnalogResMax_In_Int:= 32767 , 
	AnalogPhyMin_In_Real:= 0 , 
	AnalogPhyMax_In_Real:= 1 , 
	AnalogRdOffset_In_Real:= , 
	ActRdValue_Out_Real=> );
	
ExhAnalogRead[328](	// spare
	AnalogRdValue_In_Int:= stEXHI.IW328 , 
	AnalogResMin_In_Int:= 0 ,
	AnalogResMax_In_Int:= 32767 , 
	AnalogPhyMin_In_Real:= 0 , 
	AnalogPhyMax_In_Real:= 1 , 
	AnalogRdOffset_In_Real:= , 
	ActRdValue_Out_Real=> );
	
ExhAnalogRead[329](	// spare
	AnalogRdValue_In_Int:= stEXHI.IW329 , 
	AnalogResMin_In_Int:= 0 ,
	AnalogResMax_In_Int:= 32767 , 
	AnalogPhyMin_In_Real:= 0 , 
	AnalogPhyMax_In_Real:= 1 , 
	AnalogRdOffset_In_Real:= , 
	ActRdValue_Out_Real=> );
	
ExhAnalogRead[330](	// spare
	AnalogRdValue_In_Int:= stEXHI.IW330 , 
	AnalogResMin_In_Int:= 0 ,
	AnalogResMax_In_Int:= 32767 , 
	AnalogPhyMin_In_Real:= 0 , 
	AnalogPhyMax_In_Real:= 1 , 
	AnalogRdOffset_In_Real:= , 
	ActRdValue_Out_Real=> );
	
ExhAnalogRead[331](	// spare
	AnalogRdValue_In_Int:= stEXHI.IW331 , 
	AnalogResMin_In_Int:= 0 ,
	AnalogResMax_In_Int:= 32767 , 
	AnalogPhyMin_In_Real:= 0 , 
	AnalogPhyMax_In_Real:= 1 , 
	AnalogRdOffset_In_Real:= , 
	ActRdValue_Out_Real=> );
	
ExhAnalogRead[332](	// spare
	AnalogRdValue_In_Int:= stEXHI.IW332 , 
	AnalogResMin_In_Int:= 0 ,
	AnalogResMax_In_Int:= 32767 , 
	AnalogPhyMin_In_Real:= 0 , 
	AnalogPhyMax_In_Real:= 1 , 
	AnalogRdOffset_In_Real:= , 
	ActRdValue_Out_Real=> );
	
ExhAnalogRead[333](	// spare
	AnalogRdValue_In_Int:= stEXHI.IW333 , 
	AnalogResMin_In_Int:= 0 ,
	AnalogResMax_In_Int:= 32767 , 
	AnalogPhyMin_In_Real:= 0 , 
	AnalogPhyMax_In_Real:= 1 , 
	AnalogRdOffset_In_Real:= , 
	ActRdValue_Out_Real=> );
	
ExhAnalogRead[334](	// spare
	AnalogRdValue_In_Int:= stEXHI.IW334 , 
	AnalogResMin_In_Int:= 0 ,
	AnalogResMax_In_Int:= 32767 , 
	AnalogPhyMin_In_Real:= 0 , 
	AnalogPhyMax_In_Real:= 1 , 
	AnalogRdOffset_In_Real:= , 
	ActRdValue_Out_Real=> );
	
ExhAnalogRead[335](	// spare
	AnalogRdValue_In_Int:= stEXHI.IW335 , 
	AnalogResMin_In_Int:= 0 ,
	AnalogResMax_In_Int:= 32767 , 
	AnalogPhyMin_In_Real:= 0 , 
	AnalogPhyMax_In_Real:= 1 , 
	AnalogRdOffset_In_Real:= , 
	ActRdValue_Out_Real=> );
	
OpAnalogRead[600](	// MS8 RHC exhaust pressure
	AnalogRdValue_In_Int:= stOPI.IW600 , 
	AnalogResMin_In_Int:= 0 ,
	AnalogResMax_In_Int:= 32767 , 
	AnalogPhyMin_In_Real:= 0 , 
	AnalogPhyMax_In_Real:= 2 , 
	AnalogRdOffset_In_Real:= , 
	ActRdValue_Out_Real=> GVL.stPLCtoPMC.MS8_RHC_ExhPress );
	
OpAnalogRead[601](	// MS1 Heater exhaust pressure
	AnalogRdValue_In_Int:= stOPI.IW601 , 
	AnalogResMin_In_Int:= 0 ,
	AnalogResMax_In_Int:= 32767 , 
	AnalogPhyMin_In_Real:= 0 , 
	AnalogPhyMax_In_Real:= 200 , 
	AnalogRdOffset_In_Real:= , 
	ActRdValue_Out_Real=> GVL.stPLCtoPMC.MS1_Heater );
	
OpAnalogRead[602](	// MS3 Scavenger exhaust pressure
	AnalogRdValue_In_Int:= stOPI.IW602 , 
	AnalogResMin_In_Int:= 0 ,
	AnalogResMax_In_Int:= 32767 , 
	AnalogPhyMin_In_Real:= 0 , 
	AnalogPhyMax_In_Real:= 200 , 
	AnalogRdOffset_In_Real:= , 
	ActRdValue_Out_Real=> GVL.stPLCtoPMC.MS3_Scavenger );
	
OpAnalogRead[603](	// MS6 Frontbody exhaust pressure
	AnalogRdValue_In_Int:= stOPI.IW603 , 
	AnalogResMin_In_Int:= 0 ,
	AnalogResMax_In_Int:= 32767 , 
	AnalogPhyMin_In_Real:= 0 , 
	AnalogPhyMax_In_Real:= 200 , 
	AnalogRdOffset_In_Real:= , 
	ActRdValue_Out_Real=> GVL.stPLCtoPMC.MS6_Frontbody );
	
OpAnalogRead[604](	// MS9 LSC1 exhaust pressure
	AnalogRdValue_In_Int:= stOPI.IW604 , 
	AnalogResMin_In_Int:= 0 ,
	AnalogResMax_In_Int:= 32767 , 
	AnalogPhyMin_In_Real:= 0 , 
	AnalogPhyMax_In_Real:= 200 , 
	AnalogRdOffset_In_Real:= , 
	ActRdValue_Out_Real=> GVL.stPLCtoPMC.MS9_LSC1 );
	
OpAnalogRead[605](	// MS11 Gas box(右上) exhaust pressure
	AnalogRdValue_In_Int:= stOPI.IW605 , 
	AnalogResMin_In_Int:= 0 ,
	AnalogResMax_In_Int:= 32767 , 
	AnalogPhyMin_In_Real:= 0 , 
	AnalogPhyMax_In_Real:= 200 , 
	AnalogRdOffset_In_Real:= , 
	ActRdValue_Out_Real=> GVL.stPLCtoPMC.MS11_GasBox );
	
OpAnalogRead[606](	// MS12 Gas box(右下) exhaust pressure
	AnalogRdValue_In_Int:= stOPI.IW606 , 
	AnalogResMin_In_Int:= 0 ,
	AnalogResMax_In_Int:= 32767 , 
	AnalogPhyMin_In_Real:= 0 , 
	AnalogPhyMax_In_Real:= 200 , 
	AnalogRdOffset_In_Real:= , 
	ActRdValue_Out_Real=> GVL.stPLCtoPMC.MS12_GasBox );
	
OpAnalogRead[607](	// spare
	AnalogRdValue_In_Int:= stOPI.IW607 , 
	AnalogResMin_In_Int:= 0 ,
	AnalogResMax_In_Int:= 32767 , 
	AnalogPhyMin_In_Real:= 0 , 
	AnalogPhyMax_In_Real:= 200 , 
	AnalogRdOffset_In_Real:= , 
	ActRdValue_Out_Real=> );
END_ACTION

ACTION Input:
//************************************************************************
//02.Gas Box INput/OUTPUT(气体柜输入/出映射）
//************************************************************************
stGBI.	I200_00	:=		GB_EL1889[1,0]	;
stGBI.	I200_01	:=		GB_EL1889[1,1]	;
stGBI.	I200_02	:=		GB_EL1889[1,2]	;
stGBI.	I200_03	:=		GB_EL1889[1,3]	;
stGBI.	I200_04	:=		GB_EL1889[1,4]	;
stGBI.	I200_05	:=		GB_EL1889[1,5]	;
stGBI.	I200_06	:=		GB_EL1889[1,6]	;
stGBI.	I200_07	:=		GB_EL1889[1,7]	;
stGBI.	I200_08	:=		GB_EL1889[1,8]	;
stGBI.	I200_09	:=		GB_EL1889[1,9]	;
stGBI.	I200_10	:=		GB_EL1889[1,10]	;
stGBI.	I200_11	:=		GB_EL1889[1,11]	;
stGBI.	I200_12	:=		GB_EL1889[1,12]	;
stGBI.	I200_13	:=		GB_EL1889[1,13]	;
stGBI.	I200_14	:=		GB_EL1889[1,14]	;
stGBI.	I200_15	:=		GB_EL1889[1,15]	;
stGBI.	I201_00	:=		GB_EL1889[2,0]	;
stGBI.	I201_01	:=		GB_EL1889[2,1]	;
stGBI.	I201_02	:=		GB_EL1889[2,2]	;
stGBI.	I201_03	:=		GB_EL1889[2,3]	;
stGBI.	I201_04	:=		GB_EL1889[2,4]	;
stGBI.	I201_05	:=		GB_EL1889[2,5]	;
stGBI.	I201_06	:=		GB_EL1889[2,6]	;
stGBI.	I201_07	:=		GB_EL1889[2,7]	;
stGBI.	I201_08	:=		GB_EL1889[2,8]	;
stGBI.	I201_09	:=		GB_EL1889[2,9]	;
stGBI.	I201_10	:=		GB_EL1889[2,10]	;
stGBI.	I201_11	:=		GB_EL1889[2,11]	;
stGBI.	I201_12	:=		GB_EL1889[2,12]	;
stGBI.	I201_13	:=		GB_EL1889[2,13]	;
stGBI.	I201_14	:=		GB_EL1889[2,14]	;
stGBI.	I201_15	:=		GB_EL1889[2,15]	;
stGBI.	I203_00	:=		GB_EL1889[3,0]	;
stGBI.	I203_01	:=		GB_EL1889[3,1]	;
stGBI.	I203_02	:=		GB_EL1889[3,2]	;
stGBI.	I203_03	:=		GB_EL1889[3,3]	;
stGBI.	I203_04	:=		GB_EL1889[3,4]	;
stGBI.	I203_05	:=		GB_EL1889[3,5]	;
stGBI.	I203_06	:=		GB_EL1889[3,6]	;
stGBI.	I203_07	:=		GB_EL1889[3,7]	;
stGBI.	I203_08	:=		GB_EL1889[3,8]	;
stGBI.	I203_09	:=		GB_EL1889[3,9]	;
stGBI.	I203_10	:=		GB_EL1889[3,10]	;
stGBI.	I203_11	:=		GB_EL1889[3,11]	;
stGBI.	I203_12	:=		GB_EL1889[3,12]	;
stGBI.	I203_13	:=		GB_EL1889[3,13]	;
stGBI.	I203_14	:=		GB_EL1889[3,14]	;
stGBI.	I203_15	:=		GB_EL1889[3,15]	;

stGBI.	IW250	:=		GB_EL3164[1,	1]	;
stGBI.	IW251	:=		GB_EL3164[1,	2]	;
stGBI.	IW252	:=		GB_EL3164[1,	3]	;
stGBI.	IW253	:=		GB_EL3164[1,	4]	;
stGBI.	IW254	:=		GB_EL3164[2,	1]	;
stGBI.	IW255	:=		GB_EL3164[2,	2]	;
stGBI.	IW256	:=		GB_EL3164[2,	3]	;
stGBI.	IW257	:=		GB_EL3164[2,	4]	;
stGBI.	IW258	:=		GB_EL3164[3,	1]	;
stGBI.	IW259	:=		GB_EL3164[3,	2]	;
stGBI.	IW260	:=		GB_EL3164[3,	3]	;
stGBI.	IW261	:=		GB_EL3164[3,	4]	;
stGBI.	IW262	:=		GB_EL3124[1,	1]	;
stGBI.	IW263	:=		GB_EL3124[1,	2]	;
stGBI.	IW264	:=		GB_EL3124[1,	3]	;
stGBI.	IW265	:=		GB_EL3124[1,	4]	;
stGBI.	IW266	:=		GB_EL3164[4,	1]	;
stGBI.	IW267	:=		GB_EL3164[4,	2]	;
stGBI.	IW268	:=		GB_EL3164[4,	3]	;
stGBI.	IW269	:=		GB_EL3164[4,	4]	;


//************************************************************************
//03.EXH Box INput/OUTPUT(排气柜输入/出映射）
//************************************************************************
stEXHI.	I300_00	:=		EXH_EL1889[1,0]	;
stEXHI.	I300_01	:=		EXH_EL1889[1,1]	;
stEXHI.	I300_02	:=		EXH_EL1889[1,2]	;
stEXHI.	I300_03	:=		EXH_EL1889[1,3]	;
stEXHI.	I300_04	:=		EXH_EL1889[1,4]	;
stEXHI.	I300_05	:=		EXH_EL1889[1,5]	;
stEXHI.	I300_06	:=		EXH_EL1889[1,6]	;
stEXHI.	I300_07	:=		EXH_EL1889[1,7]	;
stEXHI.	I300_08	:=		EXH_EL1889[1,8]	;
stEXHI.	I300_09	:=		EXH_EL1889[1,9]	;
stEXHI.	I300_10	:=		EXH_EL1889[1,10]	;
stEXHI.	I300_11	:=		EXH_EL1889[1,11]	;
stEXHI.	I300_12	:=		EXH_EL1889[1,12]	;
stEXHI.	I300_13	:=		EXH_EL1889[1,13]	;
stEXHI.	I300_14	:=		EXH_EL1889[1,14]	;
stEXHI.	I300_15	:=		EXH_EL1889[1,15]	;
stEXHI.	I301_00	:=		EXH_EL1889[2,0]	;
stEXHI.	I301_01	:=		EXH_EL1889[2,1]	;
stEXHI.	I301_02	:=		EXH_EL1889[2,2]	;
stEXHI.	I301_03	:=		EXH_EL1889[2,3]	;
stEXHI.	I301_04	:=		EXH_EL1889[2,4]	;
stEXHI.	I301_05	:=		EXH_EL1889[2,5]	;
stEXHI.	I301_06	:=		EXH_EL1889[2,6]	;
stEXHI.	I301_07	:=		EXH_EL1889[2,7]	;
stEXHI.	I301_08	:=		EXH_EL1889[2,8]	;
stEXHI.	I301_09	:=		EXH_EL1889[2,9]	;
stEXHI.	I301_10	:=		EXH_EL1889[2,10]	;
stEXHI.	I301_11	:=		EXH_EL1889[2,11]	;
stEXHI.	I301_12	:=		EXH_EL1889[2,12]	;
stEXHI.	I301_13	:=		EXH_EL1889[2,13]	;
stEXHI.	I301_14	:=		EXH_EL1889[2,14]	;
stEXHI.	I301_15	:=		EXH_EL1889[2,15]	;
stEXHI.	I302_00	:=		EXH_EL1889[3,0]	;
stEXHI.	I302_01	:=		EXH_EL1889[3,1]	;
stEXHI.	I302_02	:=		EXH_EL1889[3,2]	;
stEXHI.	I302_03	:=		EXH_EL1889[3,3]	;
stEXHI.	I302_04	:=		EXH_EL1889[3,4]	;
stEXHI.	I302_05	:=		EXH_EL1889[3,5]	;
stEXHI.	I302_06	:=		EXH_EL1889[3,6]	;
stEXHI.	I302_07	:=		EXH_EL1889[3,7]	;
stEXHI.	I302_08	:=		EXH_EL1889[3,8]	;
stEXHI.	I302_09	:=		EXH_EL1889[3,9]	;
stEXHI.	I302_10	:=		EXH_EL1889[3,10]	;
stEXHI.	I302_11	:=		EXH_EL1889[3,11]	;
stEXHI.	I302_12	:=		EXH_EL1889[3,12]	;
stEXHI.	I302_13	:=		EXH_EL1889[3,13]	;
stEXHI.	I302_14	:=		EXH_EL1889[3,14]	;
stEXHI.	I302_15	:=		EXH_EL1889[3,15]	;
stEXHI.	I303_00	:=		EXH_EL1889[4,0]	;
stEXHI.	I303_01	:=		EXH_EL1889[4,1]	;
stEXHI.	I303_02	:=		EXH_EL1889[4,2]	;
stEXHI.	I303_03	:=		EXH_EL1889[4,3]	;
stEXHI.	I303_04	:=		EXH_EL1889[4,4]	;
stEXHI.	I303_05	:=		EXH_EL1889[4,5]	;
stEXHI.	I303_06	:=		EXH_EL1889[4,6]	;
stEXHI.	I303_07	:=		EXH_EL1889[4,7]	;
stEXHI.	I303_08	:=		EXH_EL1889[4,8]	;
stEXHI.	I303_09	:=		EXH_EL1889[4,9]	;
stEXHI.	I303_10	:=		EXH_EL1889[4,10]	;
stEXHI.	I303_11	:=		EXH_EL1889[4,11]	;
stEXHI.	I303_12	:=		EXH_EL1889[4,12]	;
stEXHI.	I303_13	:=		EXH_EL1889[4,13]	;
stEXHI.	I303_14	:=		EXH_EL1889[4,14]	;
stEXHI.	I303_15	:=		EXH_EL1889[4,15]	;
stEXHI.	I304_00	:=		EXH_EL1889[5,0]	;
stEXHI. I304_01	:=		EXH_EL1889[5,1]	;
stEXHI. I304_02	:=		EXH_EL1889[5,2]	;
stEXHI. I304_03	:=		EXH_EL1889[5,3]	;
stEXHI. I304_04	:=		EXH_EL1889[5,4]	;
stEXHI. I304_05	:=		EXH_EL1889[5,5]	;
stEXHI. I304_06	:=		EXH_EL1889[5,6]	;
stEXHI. I304_07	:=		EXH_EL1889[5,7]	;
stEXHI. I304_08	:=		EXH_EL1889[5,8]	;
stEXHI. I304_09	:=		EXH_EL1889[5,9]	;
stEXHI. I304_10	:=		EXH_EL1889[5,10]	;
stEXHI. I304_11	:=		EXH_EL1889[5,11]	;
stEXHI. I304_12	:=		EXH_EL1889[5,12]	;
stEXHI. I304_13	:=		EXH_EL1889[5,13]	;
stEXHI. I304_14	:=		EXH_EL1889[5,14]	;
stEXHI. I304_15	:=		EXH_EL1889[5,15]	;

stEXHI.	IW300	:=		EXH_EL3124[1,	1]	;
stEXHI.	IW301	:=		EXH_EL3124[1,	2]	;
stEXHI.	IW302	:=		EXH_EL3124[1,	3]	;
stEXHI.	IW303	:=		EXH_EL3124[1,	4]	;
stEXHI.	IW304	:=		EXH_EL3124[2,	1]	;
stEXHI.	IW305	:=		EXH_EL3124[2,	2]	;
stEXHI.	IW306	:=		EXH_EL3124[2,	3]	;
stEXHI.	IW307	:=		EXH_EL3124[2,	4]	;
stEXHI.	IW308	:=		EXH_EL3124[3,	1]	;
stEXHI.	IW309	:=		EXH_EL3124[3,	2]	;
stEXHI.	IW310	:=		EXH_EL3124[3,	3]	;
stEXHI.	IW311	:=		EXH_EL3124[3,	4]	;
stEXHI.	IW312	:=		EXH_EL3124[4,	1]	;
stEXHI.	IW313	:=		EXH_EL3124[4,	2]	;
stEXHI.	IW314	:=		EXH_EL3124[4,	3]	;
stEXHI.	IW315	:=		EXH_EL3124[4,	4]	;
stEXHI.	IW316	:=		EXH_EL3164[1,	1]	;
stEXHI.	IW317	:=		EXH_EL3164[1,	2]	;
stEXHI.	IW318	:=		EXH_EL3164[1,	3]	;
stEXHI.	IW319	:=		EXH_EL3164[1,	4]	;
stEXHI.	IW320	:=		EXH_EL3164[2,	1]	;
stEXHI.	IW321	:=		EXH_EL3164[2,	2]	;
stEXHI.	IW322	:=		EXH_EL3164[2,	3]	;
stEXHI.	IW323	:=		EXH_EL3164[2,	4]	;
stEXHI.	IW324	:=		EXH_EL3164[3,	1]	;
stEXHI.	IW325	:=		EXH_EL3164[3,	2]	;
stEXHI.	IW326	:=		EXH_EL3164[3,	3]	;
stEXHI.	IW327	:=		EXH_EL3164[3,	4]	;
stEXHI.	IW328	:=		EXH_EL3164[4,	1]	;
stEXHI.	IW329	:=		EXH_EL3164[4,	2]	;
stEXHI.	IW330	:=		EXH_EL3164[4,	3]	;
stEXHI.	IW331	:=		EXH_EL3164[4,	4]	;
stEXHI.	IW332	:=		EXH_EL3124[5,	1]	;
stEXHI.	IW333	:=		EXH_EL3124[5,	2]	;
stEXHI.	IW334	:=		EXH_EL3124[5,	3]	;
stEXHI.	IW335	:=		EXH_EL3124[5,	4]	;

//************************************************************************
//06.OP Box INput/OUTPUT(天桥内PLC输入/出映射）
//************************************************************************
stOPI.	I600_00	:=		OP_EL1889[1,0]	;
stOPI.	I600_01	:=		OP_EL1889[1,1]	;
stOPI.	I600_02	:=		OP_EL1889[1,2]	;
stOPI.	I600_03	:=		OP_EL1889[1,3]	;
stOPI.	I600_04	:=		OP_EL1889[1,4]	;
stOPI.	I600_05	:=		OP_EL1889[1,5]	;
stOPI.	I600_06	:=		OP_EL1889[1,6]	;
stOPI.	I600_07	:=		OP_EL1889[1,7]	;
stOPI.	I600_08	:=		OP_EL1889[1,8]	;
stOPI.	I600_09	:=		OP_EL1889[1,9]	;
stOPI.	I600_10	:=		OP_EL1889[1,10]	;
stOPI.	I600_11	:=		OP_EL1889[1,11]	;
stOPI.	I600_12	:=		OP_EL1889[1,12]	;
stOPI.	I600_13	:=		OP_EL1889[1,13]	;
stOPI.	I600_14	:=		OP_EL1889[1,14]	;
stOPI.	I600_15	:=		OP_EL1889[1,15]	;

stOPI.	IW600	:=		OP_EL3124[1,	1]	;
stOPI.	IW601	:=		OP_EL3124[1,	2]	;
stOPI.	IW602	:=		OP_EL3124[1,	3]	;
stOPI.	IW603	:=		OP_EL3124[1,	4]	;
stOPI.	IW604	:=		OP_EL3124[2,	1]	;
stOPI.	IW605	:=		OP_EL3124[2,	2]	;
stOPI.	IW606	:=		OP_EL3124[2,	3]	;
stOPI.	IW607	:=		OP_EL3124[2,	4]	;
END_ACTION

ACTION Output:
//========================================================================
//!!!!!!!!!!!!!!!!!!!!以下依托于硬件，硬件无变动禁止更改!!!!!!!!!!!!!!!!!!
//=======================================================================

//************************************************************************
//02.Gas Box INput/OUTPUT(气体柜输入/出映射）
//************************************************************************
GB_EL2889[1,0]	:=	FALSE(*stGBQ.	Q200_00*)	;
GB_EL2889[1,1]	:=	stGBQ.	Q200_01	;
GB_EL2889[1,2]	:=	stGBQ.	Q200_02	;
GB_EL2889[1,3]	:=	stGBQ.	Q200_03	;
GB_EL2889[1,4]	:=	stGBQ.	Q200_04	;
GB_EL2889[1,5]	:=	stGBQ.	Q200_05	;
GB_EL2889[1,6]	:=	stGBQ.	Q200_06	;
GB_EL2889[1,7]	:=	stGBQ.	Q200_07	;
GB_EL2889[1,8]	:=	stGBQ.	Q200_08	;
GB_EL2889[1,9]	:=	stGBQ.	Q200_09	;
GB_EL2889[1,10]	:=	stGBQ.	Q200_10	;
GB_EL2889[1,11]	:=	stGBQ.	Q200_11	;
GB_EL2889[1,12]	:=	stGBQ.	Q200_12	;
GB_EL2889[1,13]	:=	stGBQ.	Q200_13	;
GB_EL2889[1,14]	:=	stGBQ.	Q200_14	;
GB_EL2889[1,15]	:=	stGBQ.	Q200_15	;

GB_EV := stGBQ.QEV ;

//************************************************************************
//03.EXH Box INput/OUTPUT(排气柜输入/出映射）
//************************************************************************
EXH_EL2889[1,0]		:=	NOT GVL.stPMCtoPLC.WAT_R_sw OR ( GVL.stPMCtoPLC.R_Axis_Temp > 80 ) (*stEXHQ.	Q300_00*)	;
EXH_EL2889[1,1]		:=	FALSE(*NOT GVL.stPMCtoPLC.WAT_F_sw OR 
						(	
							( GVL.stPMCtoPLC.Inlet_Ht_1_temp > 200) OR 
							( GVL.stPMCtoPLC.Inlet_Ht_2_temp > 200) OR
							( GVL.stPMCtoPLC.Port_Ht_1_temp > 200) 	OR
							( GVL.stPMCtoPLC.Port_Ht_2_temp > 200) 	OR
							( GVL.stPMCtoPLC.Port_Ht_3_temp > 200) 	OR
							( GVL.stPMCtoPLC.Port_Ht_4_temp > 200) 	OR
							( GVL.stPMCtoPLC.Port_Ht_5_temp > 200) 	
						)*)(*stEXHQ.	Q300_01*)	;
EXH_EL2889[1,2]		:=	stEXHQ.	Q300_02	;
EXH_EL2889[1,3]		:=	stEXHQ.	Q300_03	;
EXH_EL2889[1,4]		:=	stEXHQ.	Q300_04	;
EXH_EL2889[1,5]		:=	stEXHQ.	Q300_05	;
EXH_EL2889[1,6]		:=	stEXHQ.	Q300_06	;
EXH_EL2889[1,7]		:=	stEXHQ.	Q300_07	;
EXH_EL2889[1,8]		:=	TRUE(*stEXHQ.	Q300_08*) ;
EXH_EL2889[1,9]		:=	GVL.stPMCtoPLC.I103_00(*stEXHQ.	Q300_09*) ;
EXH_EL2889[1,10]	:=	TRUE(*stEXHQ.	Q300_10*) ;
EXH_EL2889[1,11]	:=	stEXHQ.	Q300_11	;
EXH_EL2889[1,12]	:=	stEXHQ.	Q300_12	;
EXH_EL2889[1,13]	:=	stEXHQ.	Q300_13	;
EXH_EL2889[1,14]	:=	stEXHQ.	Q300_14	;
EXH_EL2889[1,15]	:=	stEXHQ.	Q300_15	;

EXH_EV := stEXHQ.QEV ;
END_ACTION

ACTION PLC_to_PMC:
//Gas box
GVL.stPLCtoPMC.	I200_00	:=	stGBI.	I200_00	;
GVL.stPLCtoPMC.	I200_01	:=	stGBI.	I200_01	;
GVL.stPLCtoPMC.	I200_02	:=	stGBI.	I200_02	;
GVL.stPLCtoPMC.	I200_03	:=	stGBI.	I200_03	;
GVL.stPLCtoPMC.	I200_04	:=	stGBI.	I200_04	;
GVL.stPLCtoPMC.	I200_05	:=	stGBI.	I200_05	;
GVL.stPLCtoPMC.	I200_06	:=	stGBI.	I200_06	;
GVL.stPLCtoPMC.	I200_07	:=	stGBI.	I200_07	;
GVL.stPLCtoPMC.	I200_08	:=	stGBI.	I200_08	;
GVL.stPLCtoPMC.	I200_09	:=	stGBI.	I200_09	;
GVL.stPLCtoPMC.	I200_10	:=	stGBI.	I200_10	;
GVL.stPLCtoPMC.	I200_11	:=	stGBI.	I200_11	;
GVL.stPLCtoPMC.	I200_12	:=	stGBI.	I200_12	;
GVL.stPLCtoPMC.	I200_13	:=	stGBI.	I200_13	;
GVL.stPLCtoPMC.	I200_14	:=	stGBI.	I200_14	;
GVL.stPLCtoPMC.	I200_15	:=	stGBI.	I200_15	;
GVL.stPLCtoPMC.	I201_00	:=	stGBI.	I201_00	;
GVL.stPLCtoPMC.	I201_01	:=	stGBI.	I201_01	;
GVL.stPLCtoPMC.	I201_02	:=	stGBI.	I201_02	;
GVL.stPLCtoPMC.	I201_03	:=	stGBI.	I201_03	;
GVL.stPLCtoPMC.	I201_04	:=	stGBI.	I201_04	;
GVL.stPLCtoPMC.	I201_05	:=	stGBI.	I201_05	;
GVL.stPLCtoPMC.	I201_06	:=	stGBI.	I201_06	;
GVL.stPLCtoPMC.	I201_07	:=	stGBI.	I201_07	;
GVL.stPLCtoPMC.	I201_08	:=	stGBI.	I201_08	;
GVL.stPLCtoPMC.	I201_09	:=	stGBI.	I201_09	;
GVL.stPLCtoPMC.	I201_10	:=	stGBI.	I201_10	;
GVL.stPLCtoPMC.	I201_11	:=	stGBI.	I201_11	;
GVL.stPLCtoPMC.	I201_12	:=	stGBI.	I201_12	;
GVL.stPLCtoPMC.	I201_13	:=	stGBI.	I201_13	;
GVL.stPLCtoPMC.	I201_14	:=	stGBI.	I201_14	;
GVL.stPLCtoPMC.	I201_15	:=	stGBI.	I201_15	;
GVL.stPLCtoPMC.	I202_00	:=	stGBI.	I203_00	;
GVL.stPLCtoPMC.	I202_01	:=	stGBI.	I203_01	;
GVL.stPLCtoPMC.	I202_02	:=	stGBI.	I203_02	;
GVL.stPLCtoPMC.	I202_03	:=	stGBI.	I203_03	;
GVL.stPLCtoPMC.	I202_04	:=	stGBI.	I203_04	;
GVL.stPLCtoPMC.	I202_05	:=	stGBI.	I203_05	;
GVL.stPLCtoPMC.	I202_06	:=	stGBI.	I203_06	;
GVL.stPLCtoPMC.	I202_07	:=	stGBI.	I203_07	;
GVL.stPLCtoPMC.	I202_08	:=	stGBI.	I203_08	;
GVL.stPLCtoPMC.	I202_09	:=	stGBI.	I203_09	;
GVL.stPLCtoPMC.	I202_10	:=	stGBI.	I203_10	;
GVL.stPLCtoPMC.	I202_11	:=	stGBI.	I203_11	;
GVL.stPLCtoPMC.	I202_12	:=	stGBI.	I203_12	;
GVL.stPLCtoPMC.	I202_13	:=	stGBI.	I203_13	;
GVL.stPLCtoPMC.	I202_14	:=	stGBI.	I203_14	;
GVL.stPLCtoPMC.	I202_15	:=	stGBI.	I203_15	;

//Exhaust box
GVL.stPLCtoPMC.	I300_00	:=	stEXHI.	I300_00	;
GVL.stPLCtoPMC.	I300_01	:=	stEXHI.	I300_01	;
GVL.stPLCtoPMC.	I300_02	:=	stEXHI.	I300_02	;
GVL.stPLCtoPMC.	I300_03	:=	stEXHI.	I300_03	;
GVL.stPLCtoPMC.	I300_04	:=	stEXHI.	I300_04	;
GVL.stPLCtoPMC.	I300_05	:=	stEXHI.	I300_05	;
GVL.stPLCtoPMC.	I300_06	:=	stEXHI.	I300_06	;
GVL.stPLCtoPMC.	I300_07	:=	stEXHI.	I300_07	;
GVL.stPLCtoPMC.	I300_08	:=	stEXHI.	I300_08	;
GVL.stPLCtoPMC.	I300_09	:=	stEXHI.	I300_09	;
GVL.stPLCtoPMC.	I300_10	:=	stEXHI.	I300_10	;
GVL.stPLCtoPMC.	I300_11	:=	stEXHI.	I300_11	;
GVL.stPLCtoPMC.	I300_12	:=	stEXHI.	I300_12	;
GVL.stPLCtoPMC.	I300_13	:=	stEXHI.	I300_13	;
GVL.stPLCtoPMC.	I300_14	:=	stEXHI.	I300_14	;
GVL.stPLCtoPMC.	I300_15	:=	stEXHI.	I300_15	;
GVL.stPLCtoPMC.	I301_00	:=	stEXHI.	I301_00	;
GVL.stPLCtoPMC.	I301_01	:=	stEXHI.	I301_01	;
GVL.stPLCtoPMC.	I301_02	:=	stEXHI.	I301_02	;
GVL.stPLCtoPMC.	I301_03	:=	stEXHI.	I301_03	;
GVL.stPLCtoPMC.	I301_04	:=	stEXHI.	I301_04	;
GVL.stPLCtoPMC.	I301_05	:=	stEXHI.	I301_05	;
GVL.stPLCtoPMC.	I301_06	:=	stEXHI.	I301_06	;
GVL.stPLCtoPMC.	I301_07	:=	stEXHI.	I301_07	;
GVL.stPLCtoPMC.	I301_08	:=	stEXHI.	I301_08	;
GVL.stPLCtoPMC.	I301_09	:=	stEXHI.	I301_09	;
GVL.stPLCtoPMC.	I301_10	:=	stEXHI.	I301_10	;
GVL.stPLCtoPMC.	I301_11	:=	stEXHI.	I301_11	;
GVL.stPLCtoPMC.	I301_12	:=	stEXHI.	I301_12	;
GVL.stPLCtoPMC.	I301_13	:=	stEXHI.	I301_13	;
GVL.stPLCtoPMC.	I301_14	:=	stEXHI.	I301_14	;
GVL.stPLCtoPMC.	I301_15	:=	stEXHI.	I301_15	;
GVL.stPLCtoPMC.	I302_00	:=	stEXHI.	I302_00	;
GVL.stPLCtoPMC.	I302_01	:=	stEXHI.	I302_01	;
GVL.stPLCtoPMC.	I302_02	:=	stEXHI.	I302_02	;
GVL.stPLCtoPMC.	I302_03	:=	stEXHI.	I302_03	;
GVL.stPLCtoPMC.	I302_04	:=	stEXHI.	I302_04	;
GVL.stPLCtoPMC.	I302_05	:=	stEXHI.	I302_05	;
GVL.stPLCtoPMC.	I302_06	:=	stEXHI.	I302_06	;
GVL.stPLCtoPMC.	I302_07	:=	stEXHI.	I302_07	;
GVL.stPLCtoPMC.	I302_08	:=	stEXHI.	I302_08	;
GVL.stPLCtoPMC.	I302_09	:=	stEXHI.	I302_09	;
GVL.stPLCtoPMC.	I302_10	:=	stEXHI.	I302_10	;
GVL.stPLCtoPMC.	I302_11	:=	stEXHI.	I302_11	;
GVL.stPLCtoPMC.	I302_12	:=	stEXHI.	I302_12	;
GVL.stPLCtoPMC.	I302_13	:=	stEXHI.	I302_13	;
GVL.stPLCtoPMC.	I302_14	:=	stEXHI.	I302_14	;
GVL.stPLCtoPMC.	I302_15	:=	stEXHI.	I302_15	;
GVL.stPLCtoPMC.	I303_00	:=	stEXHI.	I303_00	;
GVL.stPLCtoPMC.	I303_01	:=	stEXHI.	I303_01	;
GVL.stPLCtoPMC.	I303_02	:=	stEXHI.	I303_02	;
GVL.stPLCtoPMC.	I303_03	:=	stEXHI.	I303_03	;
GVL.stPLCtoPMC.	I303_04	:=	stEXHI.	I303_04	;
GVL.stPLCtoPMC.	I303_05	:=	stEXHI.	I303_05	;
GVL.stPLCtoPMC.	I303_06	:=	stEXHI.	I303_06	;
GVL.stPLCtoPMC.	I303_07	:=	stEXHI.	I303_07	;
GVL.stPLCtoPMC.	I303_08	:=	stEXHI.	I303_08	;
GVL.stPLCtoPMC.	I303_09	:=	stEXHI.	I303_09	;
GVL.stPLCtoPMC.	I303_10	:=	stEXHI.	I303_10	;
GVL.stPLCtoPMC.	I303_11	:=	stEXHI.	I303_11	;
GVL.stPLCtoPMC.	I303_12	:=	stEXHI.	I303_12	;
GVL.stPLCtoPMC.	I303_13	:=	stEXHI.	I303_13	;
GVL.stPLCtoPMC.	I303_14	:=	stEXHI.	I303_14	;
GVL.stPLCtoPMC.	I303_15	:=	stEXHI.	I303_15	;
GVL.stPLCtoPMC.	I304_00	:=	stEXHI.	I304_00	;
GVL.stPLCtoPMC.	I304_01	:=	stEXHI.	I304_01	;
GVL.stPLCtoPMC.	I304_02	:=	stEXHI.	I304_02	;
GVL.stPLCtoPMC.	I304_03	:=	stEXHI.	I304_03	;
GVL.stPLCtoPMC.	I304_04	:=	stEXHI.	I304_04	;
GVL.stPLCtoPMC.	I304_05	:=	stEXHI.	I304_05	;
GVL.stPLCtoPMC.	I304_06	:=	stEXHI.	I304_06	;
GVL.stPLCtoPMC.	I304_07	:=	stEXHI.	I304_07	;
GVL.stPLCtoPMC.	I304_08	:=	stEXHI.	I304_08	;
GVL.stPLCtoPMC.	I304_09	:=	stEXHI.	I304_09	;
GVL.stPLCtoPMC.	I304_10	:=	stEXHI.	I304_10	;
GVL.stPLCtoPMC.	I304_11	:=	stEXHI.	I304_11	;
GVL.stPLCtoPMC.	I304_12	:=	stEXHI.	I304_12	;
GVL.stPLCtoPMC.	I304_13	:=	stEXHI.	I304_13	;
GVL.stPLCtoPMC.	I304_14	:=	stEXHI.	I304_14	;
GVL.stPLCtoPMC.	I304_15	:=	stEXHI.	I304_15	;

//Operation box
GVL.stPLCtoPMC.	I600_00	:=	stOPI.	I600_00	;
GVL.stPLCtoPMC.	I600_01	:=	stOPI.	I600_01	;
GVL.stPLCtoPMC.	I600_02	:=	stOPI.	I600_02	;
GVL.stPLCtoPMC.	I600_03	:=	stOPI.	I600_03	;
GVL.stPLCtoPMC.	I600_04	:=	stOPI.	I600_04	;
GVL.stPLCtoPMC.	I600_05	:=	stOPI.	I600_05	;
GVL.stPLCtoPMC.	I600_06	:=	stOPI.	I600_06	;
GVL.stPLCtoPMC.	I600_07	:=	stOPI.	I600_07	;
GVL.stPLCtoPMC.	I600_08	:=	stOPI.	I600_08	;
GVL.stPLCtoPMC.	I600_09	:=	stOPI.	I600_09	;
GVL.stPLCtoPMC.	I600_10	:=	stOPI.	I600_10	;
GVL.stPLCtoPMC.	I600_11	:=	stOPI.	I600_11	;
GVL.stPLCtoPMC.	I600_12	:=	stOPI.	I600_12	;
GVL.stPLCtoPMC.	I600_13	:=	stOPI.	I600_13	;
GVL.stPLCtoPMC.	I600_14	:=	stOPI.	I600_14	;
GVL.stPLCtoPMC.	I600_15	:=	stOPI.	I600_15	;

//FFU
GVL.stPLCtoPMC.	FFU1_1_STATUS	:=	UINT_TO_REAL(AI.	FFU1_1_STATUS	);
GVL.stPLCtoPMC.	FFU1_2_STATUS	:=	UINT_TO_REAL(AI.	FFU1_2_STATUS	);
GVL.stPLCtoPMC.	FFU1_3_STATUS	:=	UINT_TO_REAL(AI.	FFU1_3_STATUS	);
GVL.stPLCtoPMC.	FFU1_4_STATUS	:=	UINT_TO_REAL(AI.	FFU1_4_STATUS	);
GVL.stPLCtoPMC.	FFU1_5_STATUS	:=	UINT_TO_REAL(AI.	FFU1_5_STATUS	);
GVL.stPLCtoPMC.	FFU1_6_STATUS	:=	UINT_TO_REAL(AI.	FFU1_6_STATUS	);
GVL.stPLCtoPMC.	FFU2_1_STATUS	:=	UINT_TO_REAL(AI.	FFU2_1_STATUS	);
GVL.stPLCtoPMC.	FFU2_2_STATUS	:=	UINT_TO_REAL(AI.	FFU2_2_STATUS	);
GVL.stPLCtoPMC.	FFU2_3_STATUS	:=	UINT_TO_REAL(AI.	FFU2_3_STATUS	);
GVL.stPLCtoPMC.	FFU2_4_STATUS	:=	UINT_TO_REAL(AI.	FFU2_4_STATUS	);
GVL.stPLCtoPMC.	FFU2_5_STATUS	:=	UINT_TO_REAL(AI.	FFU2_5_STATUS	);
GVL.stPLCtoPMC.	FFU2_6_STATUS	:=	UINT_TO_REAL(AI.	FFU2_6_STATUS	);
GVL.stPLCtoPMC.	FFU3_1_STATUS	:=	UINT_TO_REAL(AI.	FFU3_1_STATUS	);
GVL.stPLCtoPMC.	FFU3_2_STATUS	:=	UINT_TO_REAL(AI.	FFU3_2_STATUS	);
GVL.stPLCtoPMC.	FFU3_3_STATUS	:=	UINT_TO_REAL(AI.	FFU3_3_STATUS	);
GVL.stPLCtoPMC.	FFU3_4_STATUS	:=	UINT_TO_REAL(AI.	FFU3_4_STATUS	);
GVL.stPLCtoPMC.	FFU3_5_STATUS	:=	UINT_TO_REAL(AI.	FFU3_5_STATUS	);
GVL.stPLCtoPMC.	FFU3_6_STATUS	:=	UINT_TO_REAL(AI.	FFU3_6_STATUS	);

GVL.stPLCtoPMC.	FFU1_1_SPEED_PV	:=	UINT_TO_REAL(AI.	FFU1_1_SPEED_PV	);
GVL.stPLCtoPMC.	FFU1_2_SPEED_PV	:=	UINT_TO_REAL(AI.	FFU1_2_SPEED_PV	);
GVL.stPLCtoPMC.	FFU1_3_SPEED_PV	:=	UINT_TO_REAL(AI.	FFU1_3_SPEED_PV	);
GVL.stPLCtoPMC.	FFU1_4_SPEED_PV	:=	UINT_TO_REAL(AI.	FFU1_4_SPEED_PV	);
GVL.stPLCtoPMC.	FFU1_5_SPEED_PV	:=	UINT_TO_REAL(AI.	FFU1_5_SPEED_PV	);
GVL.stPLCtoPMC.	FFU1_6_SPEED_PV	:=	UINT_TO_REAL(AI.	FFU1_6_SPEED_PV	);
GVL.stPLCtoPMC.	FFU2_1_SPEED_PV	:=	UINT_TO_REAL(AI.	FFU2_1_SPEED_PV	);
GVL.stPLCtoPMC.	FFU2_2_SPEED_PV	:=	UINT_TO_REAL(AI.	FFU2_2_SPEED_PV	);
GVL.stPLCtoPMC.	FFU2_3_SPEED_PV	:=	UINT_TO_REAL(AI.	FFU2_3_SPEED_PV	);
GVL.stPLCtoPMC.	FFU2_4_SPEED_PV	:=	UINT_TO_REAL(AI.	FFU2_4_SPEED_PV	);
GVL.stPLCtoPMC.	FFU2_5_SPEED_PV	:=	UINT_TO_REAL(AI.	FFU2_5_SPEED_PV	);
GVL.stPLCtoPMC.	FFU2_6_SPEED_PV	:=	UINT_TO_REAL(AI.	FFU2_6_SPEED_PV	);
GVL.stPLCtoPMC.	FFU3_1_SPEED_PV	:=	UINT_TO_REAL(AI.	FFU3_1_SPEED_PV	);
GVL.stPLCtoPMC.	FFU3_2_SPEED_PV	:=	UINT_TO_REAL(AI.	FFU3_2_SPEED_PV	);
GVL.stPLCtoPMC.	FFU3_3_SPEED_PV	:=	UINT_TO_REAL(AI.	FFU3_3_SPEED_PV	);
GVL.stPLCtoPMC.	FFU3_4_SPEED_PV	:=	UINT_TO_REAL(AI.	FFU3_4_SPEED_PV	);
GVL.stPLCtoPMC.	FFU3_5_SPEED_PV	:=	UINT_TO_REAL(AI.	FFU3_5_SPEED_PV	);
GVL.stPLCtoPMC.	FFU3_6_SPEED_PV	:=	UINT_TO_REAL(AI.	FFU3_6_SPEED_PV	);
END_ACTION

ACTION PMC_to_PLC:
//Gas box
stGBQ.	Q200_00	:=	GVL.stPMCtoPLC.	Q200_00	;
stGBQ.	Q200_01	:=	GVL.stPMCtoPLC.	Q200_01	;
stGBQ.	Q200_02	:=	GVL.stPMCtoPLC.	Q200_02	;
stGBQ.	Q200_03	:=	GVL.stPMCtoPLC.	Q200_03	;
stGBQ.	Q200_04	:=	GVL.stPMCtoPLC.	Q200_04	;
stGBQ.	Q200_05	:=	GVL.stPMCtoPLC.	Q200_05	;
stGBQ.	Q200_06	:=	GVL.stPMCtoPLC.	Q200_06	;
stGBQ.	Q200_07	:=	GVL.stPMCtoPLC.	Q200_07	;
stGBQ.	Q200_08	:=	GVL.stPMCtoPLC.	Q200_08	;
stGBQ.	Q200_09	:=	GVL.stPMCtoPLC.	Q200_09	;
stGBQ.	Q200_10	:=	GVL.stPMCtoPLC.	Q200_10	;
stGBQ.	Q200_11	:=	GVL.stPMCtoPLC.	Q200_11	;
stGBQ.	Q200_12	:=	GVL.stPMCtoPLC.	Q200_12	;
stGBQ.	Q200_13	:=	GVL.stPMCtoPLC.	Q200_13	;
stGBQ.	Q200_14	:=	GVL.stPMCtoPLC.	Q200_14	;
stGBQ.	Q200_15	:=	GVL.stPMCtoPLC.	Q200_15	;

//Exhaust box
stEXHQ.	Q300_00	:=	GVL.stPMCtoPLC.	Q300_00	;
stEXHQ.	Q300_01	:=	GVL.stPMCtoPLC.	Q300_01	;
stEXHQ.	Q300_02	:=	GVL.stPMCtoPLC.	Q300_02	;
stEXHQ.	Q300_03	:=	GVL.stPMCtoPLC.	Q300_03	;
stEXHQ.	Q300_04	:=	GVL.stPMCtoPLC.	Q300_04	;
stEXHQ.	Q300_05	:=	GVL.stPMCtoPLC.	Q300_05	;
stEXHQ.	Q300_06	:=	GVL.stPMCtoPLC.	Q300_06	;
stEXHQ.	Q300_07	:=	GVL.stPMCtoPLC.	Q300_07	;
stEXHQ.	Q300_08	:=	GVL.stPMCtoPLC.	Q300_08	;
stEXHQ.	Q300_09	:=	GVL.stPMCtoPLC.	Q300_09	;
stEXHQ.	Q300_10	:=	GVL.stPMCtoPLC.	Q300_10	;
stEXHQ.	Q300_11	:=	GVL.stPMCtoPLC.	Q300_11	;
stEXHQ.	Q300_12	:=	GVL.stPMCtoPLC.	Q300_12	;
stEXHQ.	Q300_13	:=	GVL.stPMCtoPLC.	Q300_13	;
stEXHQ.	Q300_14	:=	GVL.stPMCtoPLC.	Q300_14	;
stEXHQ.	Q300_15	:=	GVL.stPMCtoPLC.	Q300_15	;

//FFU
AO.	FFU_ALARM_EN	:=	REAL_TO_UINT(GVL.stPMCtoPLC.	FFU_ALARM_EN	);
AO.	FFU_HSPEED		:=	REAL_TO_UINT(GVL.stPMCtoPLC.	FFU_HSPEED		);
AO.	FFU_LSPEED		:=	REAL_TO_UINT(GVL.stPMCtoPLC.	FFU_LSPEED		);
AO.	FFU1_1_POWER_ON	:=	REAL_TO_UINT(GVL.stPMCtoPLC.	FFU1_1_POWER_ON	);
AO.	FFU1_2_POWER_ON	:=	REAL_TO_UINT(GVL.stPMCtoPLC.	FFU1_2_POWER_ON	);
AO.	FFU1_3_POWER_ON	:=	REAL_TO_UINT(GVL.stPMCtoPLC.	FFU1_3_POWER_ON	);
AO.	FFU1_4_POWER_ON	:=	REAL_TO_UINT(GVL.stPMCtoPLC.	FFU1_4_POWER_ON	);
AO.	FFU1_5_POWER_ON	:=	REAL_TO_UINT(GVL.stPMCtoPLC.	FFU1_5_POWER_ON	);
AO.	FFU1_6_POWER_ON	:=	REAL_TO_UINT(GVL.stPMCtoPLC.	FFU1_6_POWER_ON	);
AO.	FFU2_1_POWER_ON	:=	REAL_TO_UINT(GVL.stPMCtoPLC.	FFU2_1_POWER_ON	);
AO.	FFU2_2_POWER_ON	:=	REAL_TO_UINT(GVL.stPMCtoPLC.	FFU2_2_POWER_ON	);
AO.	FFU2_3_POWER_ON	:=	REAL_TO_UINT(GVL.stPMCtoPLC.	FFU2_3_POWER_ON	);
AO.	FFU2_4_POWER_ON	:=	REAL_TO_UINT(GVL.stPMCtoPLC.	FFU2_4_POWER_ON	);
AO.	FFU2_5_POWER_ON	:=	REAL_TO_UINT(GVL.stPMCtoPLC.	FFU2_5_POWER_ON	);
AO.	FFU2_6_POWER_ON	:=	REAL_TO_UINT(GVL.stPMCtoPLC.	FFU2_6_POWER_ON	);
AO.	FFU3_1_POWER_ON	:=	REAL_TO_UINT(GVL.stPMCtoPLC.	FFU3_1_POWER_ON	);
AO.	FFU3_2_POWER_ON	:=	REAL_TO_UINT(GVL.stPMCtoPLC.	FFU3_2_POWER_ON	);
AO.	FFU3_3_POWER_ON	:=	REAL_TO_UINT(GVL.stPMCtoPLC.	FFU3_3_POWER_ON	);
AO.	FFU3_4_POWER_ON	:=	REAL_TO_UINT(GVL.stPMCtoPLC.	FFU3_4_POWER_ON	);
AO.	FFU3_5_POWER_ON	:=	REAL_TO_UINT(GVL.stPMCtoPLC.	FFU3_5_POWER_ON	);
AO.	FFU3_6_POWER_ON	:=	REAL_TO_UINT(GVL.stPMCtoPLC.	FFU3_6_POWER_ON	);
AO.	FFU1_1_SPEED_SV	:=	REAL_TO_UINT(GVL.stPMCtoPLC.	FFU1_1_SPEED_SV	);
AO.	FFU1_2_SPEED_SV	:=	REAL_TO_UINT(GVL.stPMCtoPLC.	FFU1_2_SPEED_SV	);
AO.	FFU1_3_SPEED_SV	:=	REAL_TO_UINT(GVL.stPMCtoPLC.	FFU1_3_SPEED_SV	);
AO.	FFU1_4_SPEED_SV	:=	REAL_TO_UINT(GVL.stPMCtoPLC.	FFU1_4_SPEED_SV	);
AO.	FFU1_5_SPEED_SV	:=	REAL_TO_UINT(GVL.stPMCtoPLC.	FFU1_5_SPEED_SV	);
AO.	FFU1_6_SPEED_SV	:=	REAL_TO_UINT(GVL.stPMCtoPLC.	FFU1_6_SPEED_SV	);
AO.	FFU2_1_SPEED_SV	:=	REAL_TO_UINT(GVL.stPMCtoPLC.	FFU2_1_SPEED_SV	);
AO.	FFU2_2_SPEED_SV	:=	REAL_TO_UINT(GVL.stPMCtoPLC.	FFU2_2_SPEED_SV	);
AO.	FFU2_3_SPEED_SV	:=	REAL_TO_UINT(GVL.stPMCtoPLC.	FFU2_3_SPEED_SV	);
AO.	FFU2_4_SPEED_SV	:=	REAL_TO_UINT(GVL.stPMCtoPLC.	FFU2_4_SPEED_SV	);
AO.	FFU2_5_SPEED_SV	:=	REAL_TO_UINT(GVL.stPMCtoPLC.	FFU2_5_SPEED_SV	);
AO.	FFU2_6_SPEED_SV	:=	REAL_TO_UINT(GVL.stPMCtoPLC.	FFU2_6_SPEED_SV	);
AO.	FFU3_1_SPEED_SV	:=	REAL_TO_UINT(GVL.stPMCtoPLC.	FFU3_1_SPEED_SV	);
AO.	FFU3_2_SPEED_SV	:=	REAL_TO_UINT(GVL.stPMCtoPLC.	FFU3_2_SPEED_SV	);
AO.	FFU3_3_SPEED_SV	:=	REAL_TO_UINT(GVL.stPMCtoPLC.	FFU3_3_SPEED_SV	);
AO.	FFU3_4_SPEED_SV	:=	REAL_TO_UINT(GVL.stPMCtoPLC.	FFU3_4_SPEED_SV	);
AO.	FFU3_5_SPEED_SV	:=	REAL_TO_UINT(GVL.stPMCtoPLC.	FFU3_5_SPEED_SV	);
AO.	FFU3_6_SPEED_SV	:=	REAL_TO_UINT(GVL.stPMCtoPLC.	FFU3_6_SPEED_SV	);
AO.	FFU1_1_EN		:=	REAL_TO_UINT(GVL.stPMCtoPLC.	FFU1_1_EN		);
AO.	FFU1_2_EN		:=	REAL_TO_UINT(GVL.stPMCtoPLC.	FFU1_2_EN		);
AO.	FFU1_3_EN		:=	REAL_TO_UINT(GVL.stPMCtoPLC.	FFU1_3_EN		);
AO.	FFU1_4_EN		:=	REAL_TO_UINT(GVL.stPMCtoPLC.	FFU1_4_EN		);
AO.	FFU1_5_EN		:=	REAL_TO_UINT(GVL.stPMCtoPLC.	FFU1_5_EN		);
AO.	FFU1_6_EN		:=	REAL_TO_UINT(GVL.stPMCtoPLC.	FFU1_6_EN		);
AO.	FFU2_1_EN		:=	REAL_TO_UINT(GVL.stPMCtoPLC.	FFU2_1_EN		);
AO.	FFU2_2_EN		:=	REAL_TO_UINT(GVL.stPMCtoPLC.	FFU2_2_EN		);
AO.	FFU2_3_EN		:=	REAL_TO_UINT(GVL.stPMCtoPLC.	FFU2_3_EN		);
AO.	FFU2_4_EN		:=	REAL_TO_UINT(GVL.stPMCtoPLC.	FFU2_4_EN		);
AO.	FFU2_5_EN		:=	REAL_TO_UINT(GVL.stPMCtoPLC.	FFU2_5_EN		);
AO.	FFU2_6_EN		:=	REAL_TO_UINT(GVL.stPMCtoPLC.	FFU2_6_EN		);
AO.	FFU3_1_EN		:=	REAL_TO_UINT(GVL.stPMCtoPLC.	FFU3_1_EN		);
AO.	FFU3_2_EN		:=	REAL_TO_UINT(GVL.stPMCtoPLC.	FFU3_2_EN		);
AO.	FFU3_3_EN		:=	REAL_TO_UINT(GVL.stPMCtoPLC.	FFU3_3_EN		);
AO.	FFU3_4_EN		:=	REAL_TO_UINT(GVL.stPMCtoPLC.	FFU3_4_EN		);
AO.	FFU3_5_EN		:=	REAL_TO_UINT(GVL.stPMCtoPLC.	FFU3_5_EN		);
AO.	FFU3_6_EN		:=	REAL_TO_UINT(GVL.stPMCtoPLC.	FFU3_6_EN		);
END_ACTION

ACTION ValveCtrl:
//EMO status
bEMOStatus := 
	GVL.stPMCtoPLC.EMO101_power_box_EMO AND GVL.stPMCtoPLC.EMO301_Exhaust_box_EMO AND GVL.stPMCtoPLC.EMO401_frontbody_EMO AND
	GVL.stPMCtoPLC.SMK1_detector_operator AND GVL.stPMCtoPLC.Power_box_fire_detector_alarm ;

AV[1]				
(	bValveEnable_In 	:= TRUE ,		
	bInterlock1_In		:= bEMOStatus ,	
	bInterlock2_In		:= TRUE ,	
	bInterlock3_In		:= TRUE ,	
	bInterlock4_In		:= TRUE ,	
	bInterlock5_In		:= TRUE ,	
	bForceOpen_In		:= aForceOpValve[1],
	bValveInterlock_In	:= aILK_AV[1] ,		
	bPMCCtrl_In			:= GVL.stPMCtoPLC.aAV[1] ,
	bValveOpen_Out		=> aAV[1] 
);				
				
AV[2]				
(	bValveEnable_In 	:= TRUE ,		
	bInterlock1_In		:= bEMOStatus ,	
	bInterlock2_In		:= TRUE ,	
	bInterlock3_In		:= TRUE ,	
	bInterlock4_In		:= TRUE ,	
	bInterlock5_In		:= TRUE ,	
	bForceOpen_In		:= aForceOpValve[2],
	bValveInterlock_In	:= aILK_AV[2] ,		
	bPMCCtrl_In			:= GVL.stPMCtoPLC.aAV[2] ,
	bValveOpen_Out		=> aAV[2] 	
);				
				
AV[3]				
(	bValveEnable_In 	:= TRUE ,		
	bInterlock1_In		:= bEMOStatus ,	
	bInterlock2_In		:= TRUE ,	
	bInterlock3_In		:= TRUE ,	
	bInterlock4_In		:= TRUE ,	
	bInterlock5_In		:= TRUE ,	
	bForceOpen_In		:= aForceOpValve[3],
	bValveInterlock_In	:= aILK_AV[3] ,		
	bPMCCtrl_In			:= GVL.stPMCtoPLC.aAV[3] ,
	bValveOpen_Out		=> aAV[3] 	
);				
				
AV[4]				
(	bValveEnable_In 	:= TRUE ,		
	bInterlock1_In		:= bEMOStatus ,	
	bInterlock2_In		:= TRUE ,	
	bInterlock3_In		:= TRUE ,	
	bInterlock4_In		:= TRUE ,	
	bInterlock5_In		:= TRUE ,	
	bForceOpen_In		:= aForceOpValve[4],
	bValveInterlock_In	:= aILK_AV[4] ,		
	bPMCCtrl_In			:= GVL.stPMCtoPLC.aAV[4] ,
	bValveOpen_Out		=> aAV[4] 	
);				
				
AV[5]				
(	bValveEnable_In 	:= TRUE ,		
	bInterlock1_In		:= bEMOStatus ,	
	bInterlock2_In		:= TRUE ,	
	bInterlock3_In		:= TRUE ,	
	bInterlock4_In		:= TRUE ,	
	bInterlock5_In		:= TRUE ,	
	bForceOpen_In		:= aForceOpValve[5],
	bValveInterlock_In	:= aILK_AV[5] ,		
	bPMCCtrl_In			:= GVL.stPMCtoPLC.aAV[5] ,
	bValveOpen_Out		=> aAV[5] 	
);				
				
AV[6]				
(	bValveEnable_In 	:= TRUE ,		
	bInterlock1_In		:= bEMOStatus ,	
	bInterlock2_In		:= TRUE ,	
	bInterlock3_In		:= TRUE ,	
	bInterlock4_In		:= TRUE ,	
	bInterlock5_In		:= TRUE ,	
	bForceOpen_In		:= aForceOpValve[6],
	bValveInterlock_In	:= aILK_AV[6] ,		
	bPMCCtrl_In			:= GVL.stPMCtoPLC.aAV[6] ,
	bValveOpen_Out		=> aAV[6] 	
);				
				
AV[7]				
(	bValveEnable_In 	:= TRUE ,		
	bInterlock1_In		:= bEMOStatus ,	
	bInterlock2_In		:= TRUE ,	
	bInterlock3_In		:= TRUE ,	
	bInterlock4_In		:= TRUE ,	
	bInterlock5_In		:= TRUE ,	
	bForceOpen_In		:= aForceOpValve[7],
	bValveInterlock_In	:= aILK_AV[7] ,		
	bPMCCtrl_In			:= GVL.stPMCtoPLC.aAV[7] ,
	bValveOpen_Out		=> aAV[7] 	
);				
				
AV[8]				
(	bValveEnable_In 	:= TRUE ,		
	bInterlock1_In		:= bEMOStatus ,	
	bInterlock2_In		:= TRUE ,	
	bInterlock3_In		:= TRUE ,	
	bInterlock4_In		:= TRUE ,	
	bInterlock5_In		:= TRUE ,	
	bForceOpen_In		:= aForceOpValve[8],
	bValveInterlock_In	:= aILK_AV[8] ,		
	bPMCCtrl_In			:= GVL.stPMCtoPLC.aAV[8] ,
	bValveOpen_Out		=> aAV[8] 	
);				
				
AV[9]				
(	bValveEnable_In 	:= TRUE ,		
	bInterlock1_In		:= bEMOStatus ,	
	bInterlock2_In		:= TRUE ,	
	bInterlock3_In		:= TRUE ,	
	bInterlock4_In		:= TRUE ,	
	bInterlock5_In		:= TRUE ,	
	bForceOpen_In		:= aForceOpValve[9],
	bValveInterlock_In	:= aILK_AV[9] ,		
	bPMCCtrl_In			:= GVL.stPMCtoPLC.aAV[9] ,
	bValveOpen_Out		=> aAV[9] 	
);				
				
AV[10]				
(	bValveEnable_In 	:= TRUE ,		
	bInterlock1_In		:= bEMOStatus ,	
	bInterlock2_In		:= TRUE ,	
	bInterlock3_In		:= TRUE ,	
	bInterlock4_In		:= TRUE ,	
	bInterlock5_In		:= TRUE ,	
	bForceOpen_In		:= aForceOpValve[10],
	bValveInterlock_In	:= aILK_AV[10] ,		
	bPMCCtrl_In			:= GVL.stPMCtoPLC.aAV[10] ,
	bValveOpen_Out		=> aAV[10] 	
);				
				
AV[11]				
(	bValveEnable_In 	:= TRUE ,		
	bInterlock1_In		:= bEMOStatus ,	
	bInterlock2_In		:= TRUE ,	
	bInterlock3_In		:= TRUE ,	
	bInterlock4_In		:= TRUE ,	
	bInterlock5_In		:= TRUE ,	
	bForceOpen_In		:= aForceOpValve[11],
	bValveInterlock_In	:= aILK_AV[11] ,		
	bPMCCtrl_In			:= GVL.stPMCtoPLC.aAV[11] ,
	bValveOpen_Out		=> aAV[11] 	
);				
				
AV[12]				
(	bValveEnable_In 	:= TRUE ,		
	bInterlock1_In		:= bEMOStatus ,	
	bInterlock2_In		:= TRUE ,	
	bInterlock3_In		:= TRUE ,	
	bInterlock4_In		:= TRUE ,	
	bInterlock5_In		:= TRUE ,	
	bForceOpen_In		:= aForceOpValve[12],
	bValveInterlock_In	:= aILK_AV[12] ,		
	bPMCCtrl_In			:= GVL.stPMCtoPLC.aAV[12] ,
	bValveOpen_Out		=> aAV[12] 	
);				
				
AV[13]				
(	bValveEnable_In 	:= TRUE ,		
	bInterlock1_In		:= bEMOStatus ,	
	bInterlock2_In		:= TRUE ,	
	bInterlock3_In		:= TRUE ,	
	bInterlock4_In		:= TRUE ,	
	bInterlock5_In		:= TRUE ,	
	bForceOpen_In		:= aForceOpValve[13],
	bValveInterlock_In	:= aILK_AV[13] ,		
	bPMCCtrl_In			:= GVL.stPMCtoPLC.aAV[13] ,
	bValveOpen_Out		=> aAV[13] 	
);				
				
AV[14]				
(	bValveEnable_In 	:= TRUE ,		
	bInterlock1_In		:= bEMOStatus ,	
	bInterlock2_In		:= TRUE ,	
	bInterlock3_In		:= TRUE ,	
	bInterlock4_In		:= TRUE ,	
	bInterlock5_In		:= TRUE ,	
	bForceOpen_In		:= aForceOpValve[14],
	bValveInterlock_In	:= aILK_AV[14] ,		
	bPMCCtrl_In			:= GVL.stPMCtoPLC.aAV[14] ,
	bValveOpen_Out		=> aAV[14] 	
);				
				
AV[15]				
(	bValveEnable_In 	:= TRUE ,		
	bInterlock1_In		:= bEMOStatus ,	
	bInterlock2_In		:= TRUE ,	
	bInterlock3_In		:= TRUE ,	
	bInterlock4_In		:= TRUE ,	
	bInterlock5_In		:= TRUE ,	
	bForceOpen_In		:= aForceOpValve[15],
	bValveInterlock_In	:= aILK_AV[15] ,		
	bPMCCtrl_In			:= GVL.stPMCtoPLC.aAV[15] ,
	bValveOpen_Out		=> aAV[15] 	
);				
				
AV[16]				
(	bValveEnable_In 	:= TRUE ,		
	bInterlock1_In		:= bEMOStatus ,	
	bInterlock2_In		:= TRUE ,	
	bInterlock3_In		:= TRUE ,	
	bInterlock4_In		:= TRUE ,	
	bInterlock5_In		:= TRUE ,	
	bForceOpen_In		:= aForceOpValve[16],
	bValveInterlock_In	:= aILK_AV[16] ,		
	bPMCCtrl_In			:= GVL.stPMCtoPLC.aAV[16] ,
	bValveOpen_Out		=> aAV[16] 	
);				
				
AV[17]				
(	bValveEnable_In 	:= TRUE ,		
	bInterlock1_In		:= bEMOStatus ,	
	bInterlock2_In		:= TRUE ,	
	bInterlock3_In		:= TRUE ,	
	bInterlock4_In		:= TRUE ,	
	bInterlock5_In		:= TRUE ,	
	bForceOpen_In		:= aForceOpValve[17],
	bValveInterlock_In	:= aILK_AV[17] ,		
	bPMCCtrl_In			:= GVL.stPMCtoPLC.aAV[17] ,
	bValveOpen_Out		=> aAV[17] 	
);				
				
AV[18]				
(	bValveEnable_In 	:= TRUE ,		
	bInterlock1_In		:= bEMOStatus ,	
	bInterlock2_In		:= TRUE ,	
	bInterlock3_In		:= TRUE ,	
	bInterlock4_In		:= TRUE ,	
	bInterlock5_In		:= TRUE ,	
	bForceOpen_In		:= aForceOpValve[18],
	bValveInterlock_In	:= aILK_AV[18] ,		
	bPMCCtrl_In			:= GVL.stPMCtoPLC.aAV[18] ,
	bValveOpen_Out		=> aAV[18] 	
);				
				
AV[19]				
(	bValveEnable_In 	:= TRUE ,		
	bInterlock1_In		:= bEMOStatus ,	
	bInterlock2_In		:= TRUE ,	
	bInterlock3_In		:= TRUE ,	
	bInterlock4_In		:= TRUE ,	
	bInterlock5_In		:= TRUE ,	
	bForceOpen_In		:= aForceOpValve[19],
	bValveInterlock_In	:= aILK_AV[19] ,		
	bPMCCtrl_In			:= GVL.stPMCtoPLC.aAV[19] ,
	bValveOpen_Out		=> aAV[19] 	
);				
				
AV[20]				
(	bValveEnable_In 	:= TRUE ,		
	bInterlock1_In		:= bEMOStatus ,	
	bInterlock2_In		:= TRUE ,	
	bInterlock3_In		:= TRUE ,	
	bInterlock4_In		:= TRUE ,	
	bInterlock5_In		:= TRUE ,	
	bForceOpen_In		:= aForceOpValve[20],
	bValveInterlock_In	:= aILK_AV[20] ,		
	bPMCCtrl_In			:= GVL.stPMCtoPLC.aAV[20] ,
	bValveOpen_Out		=> aAV[20] 	
);				
				
AV[21]				
(	bValveEnable_In 	:= TRUE ,		
	bInterlock1_In		:= bEMOStatus ,	
	bInterlock2_In		:= TRUE ,	
	bInterlock3_In		:= TRUE ,	
	bInterlock4_In		:= TRUE ,	
	bInterlock5_In		:= TRUE ,	
	bForceOpen_In		:= aForceOpValve[21],
	bValveInterlock_In	:= aILK_AV[21] ,		
	bPMCCtrl_In			:= GVL.stPMCtoPLC.aAV[21] ,
	bValveOpen_Out		=> aAV[21] 	
);				
				
AV[22]				
(	bValveEnable_In 	:= TRUE ,		
	bInterlock1_In		:= bEMOStatus ,	
	bInterlock2_In		:= TRUE ,	
	bInterlock3_In		:= TRUE ,	
	bInterlock4_In		:= TRUE ,	
	bInterlock5_In		:= TRUE ,	
	bForceOpen_In		:= aForceOpValve[22],
	bValveInterlock_In	:= aILK_AV[22] ,		
	bPMCCtrl_In			:= GVL.stPMCtoPLC.aAV[22] ,
	bValveOpen_Out		=> aAV[22] 	
);				
				
AV[23]				
(	bValveEnable_In 	:= TRUE ,		
	bInterlock1_In		:= bEMOStatus ,	
	bInterlock2_In		:= TRUE ,	
	bInterlock3_In		:= TRUE ,	
	bInterlock4_In		:= TRUE ,	
	bInterlock5_In		:= TRUE ,	
	bForceOpen_In		:= aForceOpValve[23],
	bValveInterlock_In	:= aILK_AV[23] ,		
	bPMCCtrl_In			:= GVL.stPMCtoPLC.aAV[23] ,
	bValveOpen_Out		=> aAV[23] 	
);				
				
AV[24]				
(	bValveEnable_In 	:= TRUE ,		
	bInterlock1_In		:= bEMOStatus ,	
	bInterlock2_In		:= TRUE ,	
	bInterlock3_In		:= TRUE ,	
	bInterlock4_In		:= TRUE ,	
	bInterlock5_In		:= TRUE ,	
	bForceOpen_In		:= aForceOpValve[24],
	bValveInterlock_In	:= aILK_AV[24] ,		
	bPMCCtrl_In			:= GVL.stPMCtoPLC.aAV[24] ,
	bValveOpen_Out		=> aAV[24] 	
);				
				
AV[25]				
(	bValveEnable_In 	:= TRUE ,		
	bInterlock1_In		:= bEMOStatus ,	
	bInterlock2_In		:= TRUE ,	
	bInterlock3_In		:= TRUE ,	
	bInterlock4_In		:= TRUE ,	
	bInterlock5_In		:= TRUE ,	
	bForceOpen_In		:= aForceOpValve[25],
	bValveInterlock_In	:= aILK_AV[25] ,		
	bPMCCtrl_In			:= GVL.stPMCtoPLC.aAV[25] ,
	bValveOpen_Out		=> aAV[25] 	
);				
				
AV[26]				
(	bValveEnable_In 	:= TRUE ,		
	bInterlock1_In		:= bEMOStatus ,	
	bInterlock2_In		:= TRUE ,	
	bInterlock3_In		:= TRUE ,	
	bInterlock4_In		:= TRUE ,	
	bInterlock5_In		:= TRUE ,	
	bForceOpen_In		:= aForceOpValve[26],
	bValveInterlock_In	:= aILK_AV[26] ,		
	bPMCCtrl_In			:= GVL.stPMCtoPLC.aAV[26] ,
	bValveOpen_Out		=> aAV[26] 	
);				
				
AV[27]				
(	bValveEnable_In 	:= TRUE ,		
	bInterlock1_In		:= bEMOStatus ,	
	bInterlock2_In		:= TRUE ,	
	bInterlock3_In		:= TRUE ,	
	bInterlock4_In		:= TRUE ,	
	bInterlock5_In		:= TRUE ,	
	bForceOpen_In		:= aForceOpValve[27],
	bValveInterlock_In	:= aILK_AV[27] ,		
	bPMCCtrl_In			:= GVL.stPMCtoPLC.aAV[27] ,
	bValveOpen_Out		=> aAV[27] 	
);				
				
AV[28]				
(	bValveEnable_In 	:= TRUE ,		
	bInterlock1_In		:= bEMOStatus ,	
	bInterlock2_In		:= TRUE ,	
	bInterlock3_In		:= TRUE ,	
	bInterlock4_In		:= TRUE ,	
	bInterlock5_In		:= TRUE ,	
	bForceOpen_In		:= aForceOpValve[28],
	bValveInterlock_In	:= aILK_AV[28] ,		
	bPMCCtrl_In			:= GVL.stPMCtoPLC.aAV[28] ,
	bValveOpen_Out		=> aAV[28] 	
);				
				
AV[29]				
(	bValveEnable_In 	:= TRUE ,		
	bInterlock1_In		:= bEMOStatus ,	
	bInterlock2_In		:= TRUE ,	
	bInterlock3_In		:= TRUE ,	
	bInterlock4_In		:= TRUE ,	
	bInterlock5_In		:= TRUE ,	
	bForceOpen_In		:= aForceOpValve[29],
	bValveInterlock_In	:= aILK_AV[29] ,		
	bPMCCtrl_In			:= GVL.stPMCtoPLC.aAV[29] ,
	bValveOpen_Out		=> aAV[29] 	
);				
				
AV[30]				
(	bValveEnable_In 	:= TRUE ,		
	bInterlock1_In		:= bEMOStatus ,	
	bInterlock2_In		:= TRUE ,	
	bInterlock3_In		:= TRUE ,	
	bInterlock4_In		:= TRUE ,	
	bInterlock5_In		:= TRUE ,	
	bForceOpen_In		:= aForceOpValve[30],
	bValveInterlock_In	:= aILK_AV[30] ,		
	bPMCCtrl_In			:= GVL.stPMCtoPLC.aAV[30] ,
	bValveOpen_Out		=> aAV[30] 	
);				
				
AV[31]				
(	bValveEnable_In 	:= TRUE ,		
	bInterlock1_In		:= bEMOStatus ,	
	bInterlock2_In		:= TRUE ,	
	bInterlock3_In		:= TRUE ,	
	bInterlock4_In		:= TRUE ,	
	bInterlock5_In		:= TRUE ,	
	bForceOpen_In		:= aForceOpValve[31],
	bValveInterlock_In	:= aILK_AV[31] ,		
	bPMCCtrl_In			:= GVL.stPMCtoPLC.aAV[31] ,
	bValveOpen_Out		=> aAV[31] 	
);				
				
AV[32]				
(	bValveEnable_In 	:= TRUE ,		
	bInterlock1_In		:= bEMOStatus ,	
	bInterlock2_In		:= TRUE ,	
	bInterlock3_In		:= TRUE ,	
	bInterlock4_In		:= TRUE ,	
	bInterlock5_In		:= TRUE ,	
	bForceOpen_In		:= aForceOpValve[32],
	bValveInterlock_In	:= aILK_AV[32] ,		
	bPMCCtrl_In			:= GVL.stPMCtoPLC.aAV[32] ,
	bValveOpen_Out		=> aAV[32] 	
);				
				
AV[33]				
(	bValveEnable_In 	:= TRUE ,		
	bInterlock1_In		:= bEMOStatus ,	
	bInterlock2_In		:= TRUE ,	
	bInterlock3_In		:= TRUE ,	
	bInterlock4_In		:= TRUE ,	
	bInterlock5_In		:= TRUE ,	
	bForceOpen_In		:= aForceOpValve[33],
	bValveInterlock_In	:= aILK_AV[33] ,		
	bPMCCtrl_In			:= GVL.stPMCtoPLC.aAV[33] ,
	bValveOpen_Out		=> aAV[33] 	
);				
				
AV[34]				
(	bValveEnable_In 	:= TRUE ,		
	bInterlock1_In		:= bEMOStatus ,	
	bInterlock2_In		:= TRUE ,	
	bInterlock3_In		:= TRUE ,	
	bInterlock4_In		:= TRUE ,	
	bInterlock5_In		:= TRUE ,	
	bForceOpen_In		:= aForceOpValve[34],
	bValveInterlock_In	:= aILK_AV[34] ,		
	bPMCCtrl_In			:= GVL.stPMCtoPLC.aAV[34] ,
	bValveOpen_Out		=> aAV[34] 	
);				
				
AV[35]				
(	bValveEnable_In 	:= TRUE ,		
	bInterlock1_In		:= bEMOStatus ,	
	bInterlock2_In		:= TRUE ,	
	bInterlock3_In		:= TRUE ,	
	bInterlock4_In		:= TRUE ,	
	bInterlock5_In		:= TRUE ,	
	bForceOpen_In		:= aForceOpValve[35],
	bValveInterlock_In	:= aILK_AV[35] ,		
	bPMCCtrl_In			:= GVL.stPMCtoPLC.aAV[35] ,
	bValveOpen_Out		=> aAV[35] 	
);				
				
AV[36]				
(	bValveEnable_In 	:= TRUE ,		
	bInterlock1_In		:= bEMOStatus ,	
	bInterlock2_In		:= TRUE ,	
	bInterlock3_In		:= TRUE ,	
	bInterlock4_In		:= TRUE ,	
	bInterlock5_In		:= TRUE ,	
	bForceOpen_In		:= aForceOpValve[36],
	bValveInterlock_In	:= aILK_AV[36] ,		
	bPMCCtrl_In			:= GVL.stPMCtoPLC.aAV[36] ,
	bValveOpen_Out		=> aAV[36] 	
);				
				
AV[37]				
(	bValveEnable_In 	:= TRUE ,		
	bInterlock1_In		:= bEMOStatus ,	
	bInterlock2_In		:= TRUE ,	
	bInterlock3_In		:= TRUE ,	
	bInterlock4_In		:= TRUE ,	
	bInterlock5_In		:= TRUE ,	
	bForceOpen_In		:= aForceOpValve[37],
	bValveInterlock_In	:= aILK_AV[37] ,		
	bPMCCtrl_In			:= GVL.stPMCtoPLC.aAV[37] ,
	bValveOpen_Out		=> aAV[37] 	
);				
				
AV[38]				
(	bValveEnable_In 	:= TRUE ,		
	bInterlock1_In		:= bEMOStatus ,	
	bInterlock2_In		:= TRUE ,	
	bInterlock3_In		:= TRUE ,	
	bInterlock4_In		:= TRUE ,	
	bInterlock5_In		:= TRUE ,	
	bForceOpen_In		:= aForceOpValve[38],
	bValveInterlock_In	:= aILK_AV[38] ,		
	bPMCCtrl_In			:= GVL.stPMCtoPLC.aAV[38] ,
	bValveOpen_Out		=> aAV[38] 	
);				
				
AV[39]				
(	bValveEnable_In 	:= TRUE ,		
	bInterlock1_In		:= bEMOStatus ,	
	bInterlock2_In		:= TRUE ,	
	bInterlock3_In		:= TRUE ,	
	bInterlock4_In		:= TRUE ,	
	bInterlock5_In		:= TRUE ,	
	bForceOpen_In		:= aForceOpValve[39],
	bValveInterlock_In	:= aILK_AV[39] ,		
	bPMCCtrl_In			:= GVL.stPMCtoPLC.aAV[39] ,
	bValveOpen_Out		=> aAV[39] 	
);				
				
AV[40]				
(	bValveEnable_In 	:= TRUE ,		
	bInterlock1_In		:= bEMOStatus ,	
	bInterlock2_In		:= TRUE ,	
	bInterlock3_In		:= TRUE ,	
	bInterlock4_In		:= TRUE ,	
	bInterlock5_In		:= TRUE ,	
	bForceOpen_In		:= aForceOpValve[40],
	bValveInterlock_In	:= aILK_AV[40] ,		
	bPMCCtrl_In			:= GVL.stPMCtoPLC.aAV[40] ,
	bValveOpen_Out		=> aAV[40] 	
);				
				
AV[41]				
(	bValveEnable_In 	:= TRUE ,		
	bInterlock1_In		:= bEMOStatus ,	
	bInterlock2_In		:= TRUE ,	
	bInterlock3_In		:= TRUE ,	
	bInterlock4_In		:= TRUE ,	
	bInterlock5_In		:= TRUE ,	
	bForceOpen_In		:= aForceOpValve[41],
	bValveInterlock_In	:= aILK_AV[41] ,		
	bPMCCtrl_In			:= GVL.stPMCtoPLC.aAV[41] ,
	bValveOpen_Out		=> aAV[41] 	
);				
				
AV[42]				
(	bValveEnable_In 	:= TRUE ,		
	bInterlock1_In		:= bEMOStatus ,	
	bInterlock2_In		:= TRUE ,	
	bInterlock3_In		:= TRUE ,	
	bInterlock4_In		:= TRUE ,	
	bInterlock5_In		:= TRUE ,	
	bForceOpen_In		:= aForceOpValve[42],
	bValveInterlock_In	:= aILK_AV[42] ,		
	bPMCCtrl_In			:= GVL.stPMCtoPLC.aAV[42] ,
	bValveOpen_Out		=> aAV[42] 	
);				
				
AV[43]				
(	bValveEnable_In 	:= TRUE ,		
	bInterlock1_In		:= bEMOStatus ,	
	bInterlock2_In		:= TRUE ,	
	bInterlock3_In		:= TRUE ,	
	bInterlock4_In		:= TRUE ,	
	bInterlock5_In		:= TRUE ,	
	bForceOpen_In		:= aForceOpValve[43],
	bValveInterlock_In	:= aILK_AV[43] ,		
	bPMCCtrl_In			:= GVL.stPMCtoPLC.aAV[43] ,
	bValveOpen_Out		=> aAV[43] 	
);				
				
AV[44]				
(	bValveEnable_In 	:= TRUE ,		
	bInterlock1_In		:= bEMOStatus ,	
	bInterlock2_In		:= TRUE ,	
	bInterlock3_In		:= TRUE ,	
	bInterlock4_In		:= TRUE ,	
	bInterlock5_In		:= TRUE ,	
	bForceOpen_In		:= aForceOpValve[44],
	bValveInterlock_In	:= aILK_AV[44] ,		
	bPMCCtrl_In			:= GVL.stPMCtoPLC.aAV[44] ,
	bValveOpen_Out		=> aAV[44] 	
);				
				
AV[45]				
(	bValveEnable_In 	:= TRUE ,		
	bInterlock1_In		:= bEMOStatus ,	
	bInterlock2_In		:= TRUE ,	
	bInterlock3_In		:= TRUE ,	
	bInterlock4_In		:= TRUE ,	
	bInterlock5_In		:= TRUE ,	
	bForceOpen_In		:= aForceOpValve[45],
	bValveInterlock_In	:= aILK_AV[45] ,		
	bPMCCtrl_In			:= GVL.stPMCtoPLC.aAV[45] ,
	bValveOpen_Out		=> aAV[45] 	
);				
				
AV[46]				
(	bValveEnable_In 	:= TRUE ,		
	bInterlock1_In		:= bEMOStatus ,	
	bInterlock2_In		:= TRUE ,	
	bInterlock3_In		:= TRUE ,	
	bInterlock4_In		:= TRUE ,	
	bInterlock5_In		:= TRUE ,	
	bForceOpen_In		:= aForceOpValve[46],
	bValveInterlock_In	:= aILK_AV[46] ,		
	bPMCCtrl_In			:= GVL.stPMCtoPLC.aAV[46] ,
	bValveOpen_Out		=> aAV[46] 	
);				
				
AV[47]				
(	bValveEnable_In 	:= TRUE ,		
	bInterlock1_In		:= bEMOStatus ,	
	bInterlock2_In		:= TRUE ,	
	bInterlock3_In		:= TRUE ,	
	bInterlock4_In		:= TRUE ,	
	bInterlock5_In		:= TRUE ,	
	bForceOpen_In		:= aForceOpValve[47],
	bValveInterlock_In	:= aILK_AV[47] ,		
	bPMCCtrl_In			:= GVL.stPMCtoPLC.aAV[47] ,
	bValveOpen_Out		=> aAV[47] 	
);				
				
AV[48]				
(	bValveEnable_In 	:= TRUE ,		
	bInterlock1_In		:= bEMOStatus ,	
	bInterlock2_In		:= TRUE ,	
	bInterlock3_In		:= TRUE ,	
	bInterlock4_In		:= TRUE ,	
	bInterlock5_In		:= TRUE ,	
	bForceOpen_In		:= aForceOpValve[48],
	bValveInterlock_In	:= aILK_AV[48] ,		
	bPMCCtrl_In			:= GVL.stPMCtoPLC.aAV[48] ,
	bValveOpen_Out		=> aAV[48] 	
);				
				
AV[49]				
(	bValveEnable_In 	:= TRUE ,		
	bInterlock1_In		:= bEMOStatus ,	
	bInterlock2_In		:= TRUE ,	
	bInterlock3_In		:= TRUE ,	
	bInterlock4_In		:= TRUE ,	
	bInterlock5_In		:= TRUE ,	
	bForceOpen_In		:= aForceOpValve[49],
	bValveInterlock_In	:= aILK_AV[49] ,		
	bPMCCtrl_In			:= GVL.stPMCtoPLC.aAV[49] ,
	bValveOpen_Out		=> aAV[49] 	
);				
				
AV[50]				
(	bValveEnable_In 	:= TRUE ,		
	bInterlock1_In		:= bEMOStatus ,	
	bInterlock2_In		:= TRUE ,	
	bInterlock3_In		:= TRUE ,	
	bInterlock4_In		:= TRUE ,	
	bInterlock5_In		:= TRUE ,	
	bForceOpen_In		:= aForceOpValve[50],
	bValveInterlock_In	:= aILK_AV[50] ,		
	bPMCCtrl_In			:= GVL.stPMCtoPLC.aAV[50] ,
	bValveOpen_Out		=> aAV[50] 	
);				
				
AV[51]				
(	bValveEnable_In 	:= TRUE ,		
	bInterlock1_In		:= bEMOStatus ,	
	bInterlock2_In		:= TRUE ,	
	bInterlock3_In		:= TRUE ,	
	bInterlock4_In		:= TRUE ,	
	bInterlock5_In		:= TRUE ,	
	bForceOpen_In		:= aForceOpValve[51],
	bValveInterlock_In	:= aILK_AV[51] ,		
	bPMCCtrl_In			:= GVL.stPMCtoPLC.aAV[51] ,
	bValveOpen_Out		=> aAV[51] 	
);				
				
AV[52]				
(	bValveEnable_In 	:= TRUE ,		
	bInterlock1_In		:= bEMOStatus ,	
	bInterlock2_In		:= TRUE ,	
	bInterlock3_In		:= TRUE ,	
	bInterlock4_In		:= TRUE ,	
	bInterlock5_In		:= TRUE ,	
	bForceOpen_In		:= aForceOpValve[52],
	bValveInterlock_In	:= aILK_AV[52] ,		
	bPMCCtrl_In			:= GVL.stPMCtoPLC.aAV[52] ,
	bValveOpen_Out		=> aAV[52] 	
);				
				
AV[53]				
(	bValveEnable_In 	:= TRUE ,		
	bInterlock1_In		:= bEMOStatus ,	
	bInterlock2_In		:= TRUE ,	
	bInterlock3_In		:= TRUE ,	
	bInterlock4_In		:= TRUE ,	
	bInterlock5_In		:= TRUE ,	
	bForceOpen_In		:= aForceOpValve[53],
	bValveInterlock_In	:= aILK_AV[53] ,		
	bPMCCtrl_In			:= GVL.stPMCtoPLC.aAV[53] ,
	bValveOpen_Out		=> aAV[53] 	
);				
				
AV[54]				
(	bValveEnable_In 	:= TRUE ,		
	bInterlock1_In		:= bEMOStatus ,	
	bInterlock2_In		:= TRUE ,	
	bInterlock3_In		:= TRUE ,	
	bInterlock4_In		:= TRUE ,	
	bInterlock5_In		:= TRUE ,	
	bForceOpen_In		:= aForceOpValve[54],
	bValveInterlock_In	:= aILK_AV[54] ,		
	bPMCCtrl_In			:= GVL.stPMCtoPLC.aAV[54] ,
	bValveOpen_Out		=> aAV[54] 	
);				
				
AV[55]				
(	bValveEnable_In 	:= TRUE ,		
	bInterlock1_In		:= bEMOStatus ,	
	bInterlock2_In		:= TRUE ,	
	bInterlock3_In		:= TRUE ,	
	bInterlock4_In		:= TRUE ,	
	bInterlock5_In		:= TRUE ,	
	bForceOpen_In		:= aForceOpValve[55],
	bValveInterlock_In	:= aILK_AV[55] ,		
	bPMCCtrl_In			:= GVL.stPMCtoPLC.aAV[55] ,
	bValveOpen_Out		=> aAV[55] 	
);				
				
AV[56]				
(	bValveEnable_In 	:= TRUE ,		
	bInterlock1_In		:= bEMOStatus ,	
	bInterlock2_In		:= TRUE ,	
	bInterlock3_In		:= TRUE ,	
	bInterlock4_In		:= TRUE ,	
	bInterlock5_In		:= TRUE ,	
	bForceOpen_In		:= aForceOpValve[56],
	bValveInterlock_In	:= aILK_AV[56] ,		
	bPMCCtrl_In			:= GVL.stPMCtoPLC.aAV[56] ,
	bValveOpen_Out		=> aAV[56] 	
);				
				
AV[57]				
(	bValveEnable_In 	:= TRUE ,		
	bInterlock1_In		:= bEMOStatus ,	
	bInterlock2_In		:= TRUE ,	
	bInterlock3_In		:= TRUE ,	
	bInterlock4_In		:= TRUE ,	
	bInterlock5_In		:= TRUE ,	
	bForceOpen_In		:= aForceOpValve[57],
	bValveInterlock_In	:= aILK_AV[57] ,		
	bPMCCtrl_In			:= GVL.stPMCtoPLC.aAV[57] ,
	bValveOpen_Out		=> aAV[57] 	
);				
				
AV[58]				
(	bValveEnable_In 	:= TRUE ,		
	bInterlock1_In		:= bEMOStatus ,	
	bInterlock2_In		:= TRUE ,	
	bInterlock3_In		:= TRUE ,	
	bInterlock4_In		:= TRUE ,	
	bInterlock5_In		:= TRUE ,
	bForceOpen_In		:= aForceOpValve[58],	
	bValveInterlock_In	:= aILK_AV[58] ,		
	bPMCCtrl_In			:= GVL.stPMCtoPLC.aAV[58] ,
	bValveOpen_Out		=> aAV[58] 	
);				
				
AV[59]				
(	bValveEnable_In 	:= TRUE ,		
	bInterlock1_In		:= bEMOStatus ,	
	bInterlock2_In		:= TRUE ,	
	bInterlock3_In		:= TRUE ,	
	bInterlock4_In		:= TRUE ,	
	bInterlock5_In		:= TRUE ,	
	bForceOpen_In		:= aForceOpValve[59],
	bValveInterlock_In	:= aILK_AV[59] ,		
	bPMCCtrl_In			:= GVL.stPMCtoPLC.aAV[59] ,
	bValveOpen_Out		=> aAV[59] 	
);				
				
AV[60]	//auto valve				
(	bValveEnable_In 	:= TRUE ,		
	bInterlock1_In		:= bEMOStatus ,	
	bInterlock2_In		:= TRUE ,	
	bInterlock3_In		:= TRUE ,	
	bInterlock4_In		:= TRUE ,	
	bInterlock5_In		:= TRUE ,	
	bForceOpen_In		:= aForceOpValve[60],
	bValveInterlock_In	:= aILK_AV[60] ,		
	bPMCCtrl_In			:= TRUE(*GVL.stPMCtoPLC.aAV[60]*) ,
	bValveOpen_Out		=> aAV[60] 	
);				
				
AV[61]				
(	bValveEnable_In 	:= TRUE ,		
	bInterlock1_In		:= bEMOStatus ,	
	bInterlock2_In		:= TRUE ,	
	bInterlock3_In		:= TRUE ,	
	bInterlock4_In		:= TRUE ,	
	bInterlock5_In		:= TRUE ,	
	bForceOpen_In		:= aForceOpValve[61],
	bValveInterlock_In	:= aILK_AV[61] ,		
	bPMCCtrl_In			:= GVL.stPMCtoPLC.aAV[61] ,
	bValveOpen_Out		=> aAV[61] 	
);				
				
AV[62]				
(	bValveEnable_In 	:= TRUE ,		
	bInterlock1_In		:= bEMOStatus ,	
	bInterlock2_In		:= TRUE ,	
	bInterlock3_In		:= TRUE ,	
	bInterlock4_In		:= TRUE ,	
	bInterlock5_In		:= TRUE ,	
	bForceOpen_In		:= aForceOpValve[62],
	bValveInterlock_In	:= aILK_AV[62] ,		
	bPMCCtrl_In			:= GVL.stPMCtoPLC.aAV[62] ,
	bValveOpen_Out		=> aAV[62] 	
);				
				
AV[63]				
(	bValveEnable_In 	:= TRUE ,		
	bInterlock1_In		:= bEMOStatus ,	
	bInterlock2_In		:= TRUE ,	
	bInterlock3_In		:= TRUE ,	
	bInterlock4_In		:= TRUE ,	
	bInterlock5_In		:= TRUE ,	
	bForceOpen_In		:= aForceOpValve[63],
	bValveInterlock_In	:= aILK_AV[63] ,		
	bPMCCtrl_In			:= GVL.stPMCtoPLC.aAV[63] ,
	bValveOpen_Out		=> aAV[63] 	
);				
				
AV[64]				
(	bValveEnable_In 	:= TRUE ,		
	bInterlock1_In		:= bEMOStatus ,	
	bInterlock2_In		:= TRUE ,	
	bInterlock3_In		:= TRUE ,	
	bInterlock4_In		:= TRUE ,	
	bInterlock5_In		:= TRUE ,	
	bForceOpen_In		:= aForceOpValve[64],
	bValveInterlock_In	:= aILK_AV[64] ,		
	bPMCCtrl_In			:= GVL.stPMCtoPLC.aAV[64] ,
	bValveOpen_Out		=> aAV[64] 	
);				
				
(*AV[65]				
(	bValveEnable_In 	:= TRUE ,		
	bInterlock1_In		:= bEMOStatus ,	
	bInterlock2_In		:= TRUE ,	
	bInterlock3_In		:= TRUE ,	
	bInterlock4_In		:= TRUE ,	
	bInterlock5_In		:= TRUE ,
	bForceOpen_In		:= aForceOpValve[65],	
	bValveInterlock_In	:= aILK_AV[65] ,		
	bPMCCtrl_In			:= GVL.stPMCtoPLC.aAV[65] ,
	bValveOpen_Out		=> aAV[65] 	
);	*)	

AV65Open				
(	bValveEnable_In 	:= TRUE ,		
	bInterlock1_In		:= bEMOStatus ,	
	bInterlock2_In		:= TRUE ,	
	bInterlock3_In		:= TRUE ,	
	bInterlock4_In		:= TRUE ,	
	bInterlock5_In		:= TRUE ,
	bForceOpen_In		:= bForceAV65Open,	
	bValveInterlock_In	:= aILK_AV[65] ,		
	bPMCCtrl_In			:= GVL.stPMCtoPLC.bAV65Open ,
	bValveOpen_Out		=> GVL.bAV65Open 	
);	

AV65Close				
(	bValveEnable_In 	:= TRUE ,		
	bInterlock1_In		:= bEMOStatus ,	
	bInterlock2_In		:= TRUE ,	
	bInterlock3_In		:= TRUE ,	
	bInterlock4_In		:= TRUE ,	
	bInterlock5_In		:= TRUE ,
	bForceOpen_In		:= bForceAV65Close,	
	bValveInterlock_In	:= aILK_AV[65] ,		
	bPMCCtrl_In			:= GVL.stPMCtoPLC.bAV65Close ,
	bValveOpen_Out		=> GVL.bAV65Close 	
);	
				
AV[66]				
(	bValveEnable_In 	:= TRUE ,		
	bInterlock1_In		:= bEMOStatus ,	
	bInterlock2_In		:= TRUE ,	
	bInterlock3_In		:= TRUE ,	
	bInterlock4_In		:= TRUE ,	
	bInterlock5_In		:= TRUE ,	
	bForceOpen_In		:= aForceOpValve[66],
	bValveInterlock_In	:= aILK_AV[66] ,		
	bPMCCtrl_In			:= GVL.stPMCtoPLC.aAV[66] ,
	bValveOpen_Out		=> aAV[66] 	
);				
				
AV[67]				
(	bValveEnable_In 	:= TRUE ,		
	bInterlock1_In		:= bEMOStatus ,	
	bInterlock2_In		:= TRUE ,	
	bInterlock3_In		:= TRUE ,	
	bInterlock4_In		:= TRUE ,	
	bInterlock5_In		:= TRUE ,	
	bForceOpen_In		:= aForceOpValve[67],
	bValveInterlock_In	:= aILK_AV[67] ,		
	bPMCCtrl_In			:= GVL.stPMCtoPLC.aAV[67] ,
	bValveOpen_Out		=> aAV[67] 	
);				
				
AV[68]	// auto valve				
(	bValveEnable_In 	:= TRUE ,		
	bInterlock1_In		:= bEMOStatus ,	
	bInterlock2_In		:= TRUE ,	
	bInterlock3_In		:= TRUE ,	
	bInterlock4_In		:= TRUE ,	
	bInterlock5_In		:= TRUE ,	
	bForceOpen_In		:= aForceOpValve[68],
	bValveInterlock_In	:= aILK_AV[68] ,		
	bPMCCtrl_In			:= TRUE(*GVL.stPMCtoPLC.aAV[68]*) ,
	bValveOpen_Out		=> aAV[68] 	
);				
				
AV[69]				
(	bValveEnable_In 	:= TRUE ,		
	bInterlock1_In		:= bEMOStatus ,	
	bInterlock2_In		:= TRUE ,	
	bInterlock3_In		:= TRUE ,	
	bInterlock4_In		:= TRUE ,	
	bInterlock5_In		:= TRUE ,	
	bForceOpen_In		:= aForceOpValve[69],
	bValveInterlock_In	:= aILK_AV[69] ,		
	bPMCCtrl_In			:= GVL.stPMCtoPLC.aAV[69] ,
	bValveOpen_Out		=> aAV[69] 	
);				
				
AV[70]				
(	bValveEnable_In 	:= TRUE ,		
	bInterlock1_In		:= bEMOStatus ,	
	bInterlock2_In		:= TRUE ,	
	bInterlock3_In		:= TRUE ,	
	bInterlock4_In		:= TRUE ,	
	bInterlock5_In		:= TRUE ,	
	bForceOpen_In		:= aForceOpValve[70],
	bValveInterlock_In	:= aILK_AV[70] ,		
	bPMCCtrl_In			:= GVL.stPMCtoPLC.aAV[70] ,
	bValveOpen_Out		=> aAV[70] 	
);				
				
AV[71]				
(	bValveEnable_In 	:= TRUE ,		
	bInterlock1_In		:= bEMOStatus ,	
	bInterlock2_In		:= TRUE ,	
	bInterlock3_In		:= TRUE ,	
	bInterlock4_In		:= TRUE ,	
	bInterlock5_In		:= TRUE ,	
	bForceOpen_In		:= aForceOpValve[71],
	bValveInterlock_In	:= aILK_AV[71] ,		
	bPMCCtrl_In			:= GVL.stPMCtoPLC.aAV[71] ,
	bValveOpen_Out		=> aAV[71] 	
);				
				
AV[72]				
(	bValveEnable_In 	:= TRUE ,		
	bInterlock1_In		:= bEMOStatus ,	
	bInterlock2_In		:= TRUE ,	
	bInterlock3_In		:= TRUE ,	
	bInterlock4_In		:= TRUE ,	
	bInterlock5_In		:= TRUE ,	
	bForceOpen_In		:= aForceOpValve[72],
	bValveInterlock_In	:= aILK_AV[72] ,		
	bPMCCtrl_In			:= GVL.stPMCtoPLC.aAV[72] ,
	bValveOpen_Out		=> aAV[72] 	
);				
				
AV[73]	// auto valve				
(	bValveEnable_In 	:= TRUE ,		
	bInterlock1_In		:= bEMOStatus ,	
	bInterlock2_In		:= TRUE ,	
	bInterlock3_In		:= TRUE ,	
	bInterlock4_In		:= TRUE ,	
	bInterlock5_In		:= TRUE ,	
	bForceOpen_In		:= aForceOpValve[73],
	bValveInterlock_In	:= aILK_AV[73] ,		
	bPMCCtrl_In			:= TRUE(*GVL.stPMCtoPLC.aAV[73]*) ,
	bValveOpen_Out		=> aAV[73] 	
);				
				
AV[74]	// auto valve				
(	bValveEnable_In 	:= TRUE ,		
	bInterlock1_In		:= bEMOStatus ,	
	bInterlock2_In		:= TRUE ,	
	bInterlock3_In		:= TRUE ,	
	bInterlock4_In		:= TRUE ,	
	bInterlock5_In		:= TRUE ,	
	bForceOpen_In		:= aForceOpValve[74],
	bValveInterlock_In	:= aILK_AV[74] ,		
	bPMCCtrl_In			:= TRUE(*GVL.stPMCtoPLC.aAV[74]*) ,
	bValveOpen_Out		=> aAV[74] 	
);				
				
AV[75]				
(	bValveEnable_In 	:= TRUE ,		
	bInterlock1_In		:= bEMOStatus ,	
	bInterlock2_In		:= TRUE ,	
	bInterlock3_In		:= TRUE ,	
	bInterlock4_In		:= TRUE ,	
	bInterlock5_In		:= TRUE ,	
	bForceOpen_In		:= aForceOpValve[75],
	bValveInterlock_In	:= aILK_AV[75] ,		
	bPMCCtrl_In			:= GVL.stPMCtoPLC.aAV[75] ,
	bValveOpen_Out		=> aAV[75] 	
);				
				
AV[76]				
(	bValveEnable_In 	:= TRUE ,		
	bInterlock1_In		:= bEMOStatus ,	
	bInterlock2_In		:= TRUE ,	
	bInterlock3_In		:= TRUE ,	
	bInterlock4_In		:= TRUE ,	
	bInterlock5_In		:= TRUE ,	
	bForceOpen_In		:= aForceOpValve[76],
	bValveInterlock_In	:= aILK_AV[76] ,		
	bPMCCtrl_In			:= GVL.stPMCtoPLC.aAV[76] ,
	bValveOpen_Out		=> aAV[76] 	
);				
				
AV[77]				
(	bValveEnable_In 	:= TRUE ,		
	bInterlock1_In		:= bEMOStatus ,	
	bInterlock2_In		:= TRUE ,	
	bInterlock3_In		:= TRUE ,	
	bInterlock4_In		:= TRUE ,	
	bInterlock5_In		:= TRUE ,	
	bForceOpen_In		:= aForceOpValve[77],
	bValveInterlock_In	:= aILK_AV[77] ,		
	bPMCCtrl_In			:= GVL.stPMCtoPLC.aAV[77] ,
	bValveOpen_Out		=> aAV[77] 	
);				
				
AV[78]				
(	bValveEnable_In 	:= TRUE ,		
	bInterlock1_In		:= bEMOStatus ,	
	bInterlock2_In		:= TRUE ,	
	bInterlock3_In		:= TRUE ,	
	bInterlock4_In		:= TRUE ,	
	bInterlock5_In		:= TRUE ,	
	bForceOpen_In		:= aForceOpValve[78],
	bValveInterlock_In	:= aILK_AV[78] ,		
	bPMCCtrl_In			:= GVL.stPMCtoPLC.aAV[78] ,
	bValveOpen_Out		=> aAV[78] 	
);		
		
AV79Open				
(	bValveEnable_In 	:= TRUE ,		
	bInterlock1_In		:= bEMOStatus ,	
	bInterlock2_In		:= TRUE ,	
	bInterlock3_In		:= TRUE ,	
	bInterlock4_In		:= TRUE ,	
	bInterlock5_In		:= TRUE ,
	bForceOpen_In		:= bForceAV79Open,	
	bValveInterlock_In	:= aILK_AV[79] ,		
	bPMCCtrl_In			:= GVL.stPMCtoPLC.bAV79Open ,
	bValveOpen_Out		=> GVL.bAV79Open 	
);	

AV79Close				
(	bValveEnable_In 	:= TRUE ,		
	bInterlock1_In		:= bEMOStatus ,	
	bInterlock2_In		:= TRUE ,	
	bInterlock3_In		:= TRUE ,	
	bInterlock4_In		:= TRUE ,	
	bInterlock5_In		:= TRUE ,
	bForceOpen_In		:= bForceAV79Close,	
	bValveInterlock_In	:= aILK_AV[79] ,		
	bPMCCtrl_In			:= GVL.stPMCtoPLC.bAV79Close ,
	bValveOpen_Out		=> GVL.bAV79Close 	
);
		
(*AV[79]				
(	bValveEnable_In 	:= TRUE ,		
	bInterlock1_In		:= bEMOStatus ,	
	bInterlock2_In		:= TRUE ,	
	bInterlock3_In		:= TRUE ,	
	bInterlock4_In		:= TRUE ,	
	bInterlock5_In		:= TRUE ,	
	bForceOpen_In		:= aForceOpValve[79],
	bValveInterlock_In	:= aILK_AV[79] ,		
	bPMCCtrl_In			:= GVL.stPMCtoPLC.aAV[79] ,
	bValveOpen_Out		=> aAV[79] 	
);	*)			
				
AV[80]				
(	bValveEnable_In 	:= TRUE ,		
	bInterlock1_In		:= bEMOStatus ,	
	bInterlock2_In		:= TRUE ,	
	bInterlock3_In		:= TRUE ,	
	bInterlock4_In		:= TRUE ,	
	bInterlock5_In		:= TRUE ,	
	bForceOpen_In		:= aForceOpValve[80],
	bValveInterlock_In	:= aILK_AV[80] ,		
	bPMCCtrl_In			:= GVL.stPMCtoPLC.aAV[80] ,
	bValveOpen_Out		=> aAV[80] 	
);				
				
AV[81]				
(	bValveEnable_In 	:= TRUE ,		
	bInterlock1_In		:= bEMOStatus ,	
	bInterlock2_In		:= TRUE ,	
	bInterlock3_In		:= TRUE ,	
	bInterlock4_In		:= TRUE ,	
	bInterlock5_In		:= TRUE ,	
	bForceOpen_In		:= aForceOpValve[81],
	bValveInterlock_In	:= aILK_AV[81] ,		
	bPMCCtrl_In			:= GVL.stPMCtoPLC.aAV[81] ,
	bValveOpen_Out		=> aAV[81] 	
);				
				
AV[82]				
(	bValveEnable_In 	:= TRUE ,		
	bInterlock1_In		:= bEMOStatus ,	
	bInterlock2_In		:= TRUE ,	
	bInterlock3_In		:= TRUE ,	
	bInterlock4_In		:= TRUE ,	
	bInterlock5_In		:= TRUE ,	
	bForceOpen_In		:= aForceOpValve[82],
	bValveInterlock_In	:= aILK_AV[82] ,		
	bPMCCtrl_In			:= GVL.stPMCtoPLC.aAV[82] ,
	bValveOpen_Out		=> aAV[82] 	
);				
				
AV[83]				
(	bValveEnable_In 	:= TRUE ,		
	bInterlock1_In		:= bEMOStatus ,	
	bInterlock2_In		:= TRUE ,	
	bInterlock3_In		:= TRUE ,	
	bInterlock4_In		:= TRUE ,	
	bInterlock5_In		:= TRUE ,	
	bForceOpen_In		:= aForceOpValve[83],
	bValveInterlock_In	:= aILK_AV[83] ,		
	bPMCCtrl_In			:= GVL.stPMCtoPLC.aAV[83] ,
	bValveOpen_Out		=> aAV[83] 	
);				
				
AV[84]				
(	bValveEnable_In 	:= TRUE ,		
	bInterlock1_In		:= bEMOStatus ,	
	bInterlock2_In		:= TRUE ,	
	bInterlock3_In		:= TRUE ,	
	bInterlock4_In		:= TRUE ,	
	bInterlock5_In		:= TRUE ,	
	bForceOpen_In		:= aForceOpValve[84],
	bValveInterlock_In	:= aILK_AV[84] ,		
	bPMCCtrl_In			:= GVL.stPMCtoPLC.aAV[84] ,
	bValveOpen_Out		=> aAV[84] 	
);				
				
AV[85]				
(	bValveEnable_In 	:= TRUE ,		
	bInterlock1_In		:= bEMOStatus ,	
	bInterlock2_In		:= TRUE ,	
	bInterlock3_In		:= TRUE ,	
	bInterlock4_In		:= TRUE ,	
	bInterlock5_In		:= TRUE ,	
	bForceOpen_In		:= aForceOpValve[85],
	bValveInterlock_In	:= aILK_AV[85] ,		
	bPMCCtrl_In			:= GVL.stPMCtoPLC.aAV[85] ,
	bValveOpen_Out		=> aAV[85] 	
);				
				
AV[86]				
(	bValveEnable_In 	:= TRUE ,		
	bInterlock1_In		:= bEMOStatus ,	
	bInterlock2_In		:= TRUE ,	
	bInterlock3_In		:= TRUE ,	
	bInterlock4_In		:= TRUE ,	
	bInterlock5_In		:= TRUE ,	
	bForceOpen_In		:= aForceOpValve[86],
	bValveInterlock_In	:= aILK_AV[86] ,		
	bPMCCtrl_In			:= GVL.stPMCtoPLC.aAV[86] ,
	bValveOpen_Out		=> aAV[86] 	
);				
				
AV[87]				
(	bValveEnable_In 	:= TRUE ,		
	bInterlock1_In		:= bEMOStatus ,	
	bInterlock2_In		:= TRUE ,	
	bInterlock3_In		:= TRUE ,	
	bInterlock4_In		:= TRUE ,	
	bInterlock5_In		:= TRUE ,	
	bForceOpen_In		:= aForceOpValve[87],
	bValveInterlock_In	:= aILK_AV[87] ,		
	bPMCCtrl_In			:= GVL.stPMCtoPLC.aAV[87] ,
	bValveOpen_Out		=> aAV[87] 	
);				
				
AV[88]				
(	bValveEnable_In 	:= TRUE ,		
	bInterlock1_In		:= bEMOStatus ,	
	bInterlock2_In		:= TRUE ,	
	bInterlock3_In		:= TRUE ,	
	bInterlock4_In		:= TRUE ,	
	bInterlock5_In		:= TRUE ,	
	bForceOpen_In		:= aForceOpValve[88],
	bValveInterlock_In	:= aILK_AV[88] ,		
	bPMCCtrl_In			:= GVL.stPMCtoPLC.aAV[88] ,
	bValveOpen_Out		=> aAV[88] 	
);				
				
AV[89]				
(	bValveEnable_In 	:= TRUE ,		
	bInterlock1_In		:= bEMOStatus ,	
	bInterlock2_In		:= TRUE ,	
	bInterlock3_In		:= TRUE ,	
	bInterlock4_In		:= TRUE ,	
	bInterlock5_In		:= TRUE ,	
	bForceOpen_In		:= aForceOpValve[89],
	bValveInterlock_In	:= aILK_AV[89] ,		
	bPMCCtrl_In			:= GVL.stPMCtoPLC.aAV[89] ,
	bValveOpen_Out		=> aAV[89] 	
);				
				
AV[90]				
(	bValveEnable_In 	:= TRUE ,		
	bInterlock1_In		:= bEMOStatus ,	
	bInterlock2_In		:= TRUE ,	
	bInterlock3_In		:= TRUE ,	
	bInterlock4_In		:= TRUE ,	
	bInterlock5_In		:= TRUE ,	
	bForceOpen_In		:= aForceOpValve[90],
	bValveInterlock_In	:= aILK_AV[90] ,		
	bPMCCtrl_In			:= GVL.stPMCtoPLC.aAV[90] ,
	bValveOpen_Out		=> aAV[90] 	
);				
				
(*AV[91]				
(	bValveEnable_In 	:= TRUE ,		
	bInterlock1_In		:= bEMOStatus ,	
	bInterlock2_In		:= TRUE ,	
	bInterlock3_In		:= TRUE ,	
	bInterlock4_In		:= TRUE ,	
	bInterlock5_In		:= TRUE ,	
	bForceOpen_In		:= aForceOpValve[91],
	bValveInterlock_In	:= aILK_AV[91] ,		
	bPMCCtrl_In			:= FALSE ,
	bValveOpen_Out		=> aAV[91] 	
);	*)

AV91Open				
(	bValveEnable_In 	:= TRUE ,		
	bInterlock1_In		:= bEMOStatus ,	
	bInterlock2_In		:= TRUE ,	
	bInterlock3_In		:= TRUE ,	
	bInterlock4_In		:= TRUE ,	
	bInterlock5_In		:= TRUE ,
	bForceOpen_In		:= bForceAV91Open,	
	bValveInterlock_In	:= TRUE(*aILK_AV[91]*) ,		
	bPMCCtrl_In			:= GVL.stPMCtoPLC.bAV91Open ,
	bValveOpen_Out		=> GVL.bAV91Open 	
);	

AV91Close				
(	bValveEnable_In 	:= TRUE ,		
	bInterlock1_In		:= bEMOStatus ,	
	bInterlock2_In		:= TRUE ,	
	bInterlock3_In		:= TRUE ,	
	bInterlock4_In		:= TRUE ,	
	bInterlock5_In		:= TRUE ,
	bForceOpen_In		:= bForceAV91Close,	
	bValveInterlock_In	:= TRUE(*aILK_AV[91]*) ,		
	bPMCCtrl_In			:= GVL.stPMCtoPLC.bAV91Close ,
	bValveOpen_Out		=> GVL.bAV91Close 	
);			
				
AV[92]				
(	bValveEnable_In 	:= TRUE ,		
	bInterlock1_In		:= bEMOStatus ,	
	bInterlock2_In		:= TRUE ,	
	bInterlock3_In		:= TRUE ,	
	bInterlock4_In		:= TRUE ,	
	bInterlock5_In		:= TRUE ,	
	bForceOpen_In		:= aForceOpValve[92],
	bValveInterlock_In	:= aILK_AV[92] ,		
	bPMCCtrl_In			:= TRUE ,
	bValveOpen_Out		=> aAV[92] 	
);				
				
AV[93]				
(	bValveEnable_In 	:= TRUE ,		
	bInterlock1_In		:= bEMOStatus ,	
	bInterlock2_In		:= TRUE ,	
	bInterlock3_In		:= TRUE ,	
	bInterlock4_In		:= TRUE ,	
	bInterlock5_In		:= TRUE ,	
	bForceOpen_In		:= aForceOpValve[93],
	bValveInterlock_In	:= aILK_AV[93] ,		
	bPMCCtrl_In			:= GVL.stPMCtoPLC.aAV[93] ,
	bValveOpen_Out		=> aAV[93] 	
);				
				
AV[94]				
(	bValveEnable_In 	:= TRUE ,		
	bInterlock1_In		:= bEMOStatus ,	
	bInterlock2_In		:= TRUE ,	
	bInterlock3_In		:= TRUE ,	
	bInterlock4_In		:= TRUE ,	
	bInterlock5_In		:= TRUE ,
bForceOpen_In		:= aForceOpValve[94],	
	bValveInterlock_In	:= aILK_AV[94] ,		
	bPMCCtrl_In			:= GVL.stPMCtoPLC.aAV[94] ,
	bValveOpen_Out		=> aAV[94] 	
);				
				
AV[95]				
(	bValveEnable_In 	:= TRUE ,		
	bInterlock1_In		:= bEMOStatus ,	
	bInterlock2_In		:= TRUE ,	
	bInterlock3_In		:= TRUE ,	
	bInterlock4_In		:= TRUE ,	
	bInterlock5_In		:= TRUE ,	
	bForceOpen_In		:= aForceOpValve[95],
	bValveInterlock_In	:= aILK_AV[95] ,		
	bPMCCtrl_In			:= GVL.stPMCtoPLC.aAV[95] ,
	bValveOpen_Out		=> aAV[95] 	
);				
				
AV[96]				
(	bValveEnable_In 	:= TRUE ,		
	bInterlock1_In		:= bEMOStatus ,	
	bInterlock2_In		:= TRUE ,	
	bInterlock3_In		:= TRUE ,	
	bInterlock4_In		:= TRUE ,	
	bInterlock5_In		:= TRUE ,	
	bForceOpen_In		:= aForceOpValve[96],
	bValveInterlock_In	:= aILK_AV[96] ,		
	bPMCCtrl_In			:= GVL.stPMCtoPLC.aAV[96] ,
	bValveOpen_Out		=> aAV[96] 	
);				
				
AV[97]				
(	bValveEnable_In 	:= TRUE ,		
	bInterlock1_In		:= bEMOStatus ,	
	bInterlock2_In		:= TRUE ,	
	bInterlock3_In		:= TRUE ,	
	bInterlock4_In		:= TRUE ,	
	bInterlock5_In		:= TRUE ,	
	bForceOpen_In		:= aForceOpValve[97],
	bValveInterlock_In	:= aILK_AV[97] ,		
	bPMCCtrl_In			:= GVL.stPMCtoPLC.aAV[97] ,
	bValveOpen_Out		=> aAV[97] 	
);				
				
AV[98]				
(	bValveEnable_In 	:= TRUE ,		
	bInterlock1_In		:= bEMOStatus ,	
	bInterlock2_In		:= TRUE ,	
	bInterlock3_In		:= TRUE ,	
	bInterlock4_In		:= TRUE ,	
	bInterlock5_In		:= TRUE ,	
	bForceOpen_In		:= aForceOpValve[98],
	bValveInterlock_In	:= aILK_AV[98] ,		
	bPMCCtrl_In			:= GVL.stPMCtoPLC.aAV[98] ,
	bValveOpen_Out		=> aAV[98] 	
);				
				
AV[99]				
(	bValveEnable_In 	:= TRUE ,		
	bInterlock1_In		:= bEMOStatus ,	
	bInterlock2_In		:= TRUE ,	
	bInterlock3_In		:= TRUE ,	
	bInterlock4_In		:= TRUE ,	
	bInterlock5_In		:= TRUE ,	
	bForceOpen_In		:= aForceOpValve[99],
	bValveInterlock_In	:= aILK_AV[99] ,		
	bPMCCtrl_In			:= GVL.stPMCtoPLC.aAV[99] ,
	bValveOpen_Out		=> aAV[99] 	
);				
				
AV[100]				
(	bValveEnable_In 	:= TRUE ,		
	bInterlock1_In		:= bEMOStatus ,	
	bInterlock2_In		:= TRUE ,	
	bInterlock3_In		:= TRUE ,	
	bInterlock4_In		:= TRUE ,	
	bInterlock5_In		:= TRUE ,	
	bForceOpen_In		:= aForceOpValve[100],
	bValveInterlock_In	:= aILK_AV[100] ,		
	bPMCCtrl_In			:= NOT GVL.stPMCtoPLC.T_MNT_sw OR ( GVL.stPMCtoPLC.T_MNT_sw AND GVL.stPMCtoPLC.T_REF_sw AND GVL.stPMCtoPLC.aAV[100] )(*GVL.stPMCtoPLC.aAV[100]*) ,
	bValveOpen_Out		=> aAV[100] 	
);				
				
AV[101]				
(	bValveEnable_In 	:= TRUE ,		
	bInterlock1_In		:= bEMOStatus ,	
	bInterlock2_In		:= TRUE ,	
	bInterlock3_In		:= TRUE ,	
	bInterlock4_In		:= TRUE ,	
	bInterlock5_In		:= TRUE ,	
	bForceOpen_In		:= aForceOpValve[101],
	bValveInterlock_In	:= aILK_AV[101] ,		
	bPMCCtrl_In			:= NOT GVL.stPMCtoPLC.T_MNT_sw OR ( GVL.stPMCtoPLC.T_MNT_sw AND GVL.stPMCtoPLC.T_REF_sw AND GVL.stPMCtoPLC.aAV[101] )(*GVL.stPMCtoPLC.aAV[101]*) ,
	bValveOpen_Out		=> aAV[101] 	
);				
				
AV[102]				
(	bValveEnable_In 	:= TRUE ,		
	bInterlock1_In		:= bEMOStatus ,	
	bInterlock2_In		:= TRUE ,	
	bInterlock3_In		:= TRUE ,	
	bInterlock4_In		:= TRUE ,	
	bInterlock5_In		:= TRUE ,	
	bForceOpen_In		:= aForceOpValve[102],
	bValveInterlock_In	:= aILK_AV[102] ,		
	bPMCCtrl_In			:= GVL.stPMCtoPLC.aAV[102] ,
	bValveOpen_Out		=> aAV[102] 	
);				
				
AV[103]				
(	bValveEnable_In 	:= TRUE ,		
	bInterlock1_In		:= bEMOStatus ,	
	bInterlock2_In		:= TRUE ,	
	bInterlock3_In		:= TRUE ,	
	bInterlock4_In		:= TRUE ,	
	bInterlock5_In		:= TRUE ,	
	bForceOpen_In		:= aForceOpValve[103],
	bValveInterlock_In	:= aILK_AV[103] ,		
	bPMCCtrl_In			:= GVL.stPMCtoPLC.aAV[103] ,
	bValveOpen_Out		=> aAV[103] 	
);				
				
AV[104]				
(	bValveEnable_In 	:= TRUE ,		
	bInterlock1_In		:= bEMOStatus ,	
	bInterlock2_In		:= TRUE ,	
	bInterlock3_In		:= TRUE ,	
	bInterlock4_In		:= TRUE ,	
	bInterlock5_In		:= TRUE ,	
	bForceOpen_In		:= aForceOpValve[104],
	bValveInterlock_In	:= aILK_AV[104] ,		
	bPMCCtrl_In			:= GVL.stPMCtoPLC.aAV[104] ,
	bValveOpen_Out		=> aAV[104] 	
);				
				
AV[105]				
(	bValveEnable_In 	:= TRUE ,		
	bInterlock1_In		:= bEMOStatus ,	
	bInterlock2_In		:= TRUE ,	
	bInterlock3_In		:= TRUE ,	
	bInterlock4_In		:= TRUE ,	
	bInterlock5_In		:= TRUE ,	
	bForceOpen_In		:= aForceOpValve[105],
	bValveInterlock_In	:= aILK_AV[105] ,		
	bPMCCtrl_In			:= GVL.stPMCtoPLC.aAV[105] ,
	bValveOpen_Out		=> aAV[105] 	
);				
				
AV[106]				
(	bValveEnable_In 	:= TRUE ,		
	bInterlock1_In		:= bEMOStatus ,	
	bInterlock2_In		:= TRUE ,	
	bInterlock3_In		:= TRUE ,	
	bInterlock4_In		:= TRUE ,	
	bInterlock5_In		:= TRUE ,	
	bForceOpen_In		:= aForceOpValve[106],
	bValveInterlock_In	:= aILK_AV[106] ,		
	bPMCCtrl_In			:= GVL.stPMCtoPLC.aAV[106] ,
	bValveOpen_Out		=> aAV[106] 	
);				
				
AV[107]				
(	bValveEnable_In 	:= TRUE ,		
	bInterlock1_In		:= bEMOStatus ,	
	bInterlock2_In		:= TRUE ,	
	bInterlock3_In		:= TRUE ,	
	bInterlock4_In		:= TRUE ,	
	bInterlock5_In		:= TRUE ,	
	bForceOpen_In		:= aForceOpValve[107],
	bValveInterlock_In	:= aILK_AV[107] ,		
	bPMCCtrl_In			:= GVL.stPMCtoPLC.aAV[107] ,
	bValveOpen_Out		=> aAV[107] 	
);				
				
AV[108]				
(	bValveEnable_In 	:= TRUE ,		
	bInterlock1_In		:= bEMOStatus ,	
	bInterlock2_In		:= TRUE ,	
	bInterlock3_In		:= TRUE ,	
	bInterlock4_In		:= TRUE ,	
	bInterlock5_In		:= TRUE ,	
	bForceOpen_In		:= aForceOpValve[108],
	bValveInterlock_In	:= aILK_AV[108] ,		
	bPMCCtrl_In			:= GVL.stPMCtoPLC.aAV[108] ,
	bValveOpen_Out		=> aAV[108] 	
);				
				
AV[109]				
(	bValveEnable_In 	:= TRUE ,		
	bInterlock1_In		:= bEMOStatus ,	
	bInterlock2_In		:= TRUE ,	
	bInterlock3_In		:= TRUE ,	
	bInterlock4_In		:= TRUE ,	
	bInterlock5_In		:= TRUE ,	
	bForceOpen_In		:= aForceOpValve[109],
	bValveInterlock_In	:= aILK_AV[109] ,		
	bPMCCtrl_In			:= GVL.stPMCtoPLC.aAV[109] ,
	bValveOpen_Out		=> aAV[109] 	
);				
				
AV[110]				
(	bValveEnable_In 	:= TRUE ,		
	bInterlock1_In		:= bEMOStatus ,	
	bInterlock2_In		:= TRUE ,	
	bInterlock3_In		:= TRUE ,	
	bInterlock4_In		:= TRUE ,	
	bInterlock5_In		:= TRUE ,	
	bForceOpen_In		:= aForceOpValve[110],
	bValveInterlock_In	:= aILK_AV[110] ,		
	bPMCCtrl_In			:= GVL.stPMCtoPLC.aAV[110] ,
	bValveOpen_Out		=> aAV[110] 	
);				
				
AV[111]				
(	bValveEnable_In 	:= TRUE ,		
	bInterlock1_In		:= bEMOStatus ,	
	bInterlock2_In		:= TRUE ,	
	bInterlock3_In		:= TRUE ,	
	bInterlock4_In		:= TRUE ,	
	bInterlock5_In		:= TRUE ,
	bForceOpen_In		:= aForceOpValve[111],	
	bValveInterlock_In	:= aILK_AV[111] ,		
	bPMCCtrl_In			:= GVL.stPMCtoPLC.aAV[111] ,
	bValveOpen_Out		=> aAV[111] 	
);				
				
AV[112]				
(	bValveEnable_In 	:= TRUE ,		
	bInterlock1_In		:= bEMOStatus ,	
	bInterlock2_In		:= TRUE ,	
	bInterlock3_In		:= TRUE ,	
	bInterlock4_In		:= TRUE ,	
	bInterlock5_In		:= TRUE ,	
	bForceOpen_In		:= aForceOpValve[112],
	bValveInterlock_In	:= aILK_AV[112] ,		
	bPMCCtrl_In			:= GVL.stPMCtoPLC.aAV[112] ,
	bValveOpen_Out		=> aAV[112] 	
);				
				
AV[113]				
(	bValveEnable_In 	:= TRUE ,		
	bInterlock1_In		:= bEMOStatus ,	
	bInterlock2_In		:= TRUE ,	
	bInterlock3_In		:= TRUE ,	
	bInterlock4_In		:= TRUE ,	
	bInterlock5_In		:= TRUE ,	
	bForceOpen_In		:= aForceOpValve[113],
	bValveInterlock_In	:= aILK_AV[113] ,		
	bPMCCtrl_In			:= GVL.stPMCtoPLC.aAV[113] ,
	bValveOpen_Out		=> aAV[113] 	
);				
				
AV[114]				
(	bValveEnable_In 	:= TRUE ,		
	bInterlock1_In		:= bEMOStatus ,	
	bInterlock2_In		:= TRUE ,	
	bInterlock3_In		:= TRUE ,	
	bInterlock4_In		:= TRUE ,	
	bInterlock5_In		:= TRUE ,	
	bForceOpen_In		:= aForceOpValve[114],
	bValveInterlock_In	:= aILK_AV[114] ,		
	bPMCCtrl_In			:= GVL.stPMCtoPLC.aAV[114] ,
	bValveOpen_Out		=> aAV[114] 	
);				
				
AV[115]				
(	bValveEnable_In 	:= TRUE ,		
	bInterlock1_In		:= bEMOStatus ,	
	bInterlock2_In		:= TRUE ,	
	bInterlock3_In		:= TRUE ,	
	bInterlock4_In		:= TRUE ,	
	bInterlock5_In		:= TRUE ,	
	bForceOpen_In		:= aForceOpValve[115],
	bValveInterlock_In	:= aILK_AV[115] ,		
	bPMCCtrl_In			:= GVL.stPMCtoPLC.aAV[115] ,
	bValveOpen_Out		=> aAV[115] 	
);				
				
AV[116]				
(	bValveEnable_In 	:= TRUE ,		
	bInterlock1_In		:= bEMOStatus ,	
	bInterlock2_In		:= TRUE ,	
	bInterlock3_In		:= TRUE ,	
	bInterlock4_In		:= TRUE ,	
	bInterlock5_In		:= TRUE ,	
	bForceOpen_In		:= aForceOpValve[116],
	bValveInterlock_In	:= aILK_AV[116] ,		
	bPMCCtrl_In			:= GVL.stPMCtoPLC.aAV[116] ,
	bValveOpen_Out		=> aAV[116] 	
);				
				
AV[117]				
(	bValveEnable_In 	:= TRUE ,		
	bInterlock1_In		:= bEMOStatus ,	
	bInterlock2_In		:= TRUE ,	
	bInterlock3_In		:= TRUE ,	
	bInterlock4_In		:= TRUE ,	
	bInterlock5_In		:= TRUE ,	
	bForceOpen_In		:= aForceOpValve[117],
	bValveInterlock_In	:= aILK_AV[117] ,		
	bPMCCtrl_In			:= GVL.stPMCtoPLC.aAV[117] ,
	bValveOpen_Out		=> aAV[117] 	
);				
				
AV[118]				
(	bValveEnable_In 	:= TRUE ,		
	bInterlock1_In		:= bEMOStatus ,	
	bInterlock2_In		:= TRUE ,	
	bInterlock3_In		:= TRUE ,	
	bInterlock4_In		:= TRUE ,	
	bInterlock5_In		:= TRUE ,	
	bForceOpen_In		:= aForceOpValve[118],
	bValveInterlock_In	:= aILK_AV[118] ,		
	bPMCCtrl_In			:= GVL.stPMCtoPLC.aAV[118] ,
	bValveOpen_Out		=> aAV[118] 	
);				
				
AV[119]				
(	bValveEnable_In 	:= TRUE ,		
	bInterlock1_In		:= bEMOStatus ,	
	bInterlock2_In		:= TRUE ,	
	bInterlock3_In		:= TRUE ,	
	bInterlock4_In		:= TRUE ,	
	bInterlock5_In		:= TRUE ,	
	bForceOpen_In		:= aForceOpValve[119],
	bValveInterlock_In	:= aILK_AV[119] ,		
	bPMCCtrl_In			:= GVL.stPMCtoPLC.aAV[119] ,
	bValveOpen_Out		=> aAV[119] 	
);				
				
AV[120]				
(	bValveEnable_In 	:= TRUE ,		
	bInterlock1_In		:= bEMOStatus ,	
	bInterlock2_In		:= TRUE ,	
	bInterlock3_In		:= TRUE ,	
	bInterlock4_In		:= TRUE ,	
	bInterlock5_In		:= TRUE ,	
	bForceOpen_In		:= aForceOpValve[120],
	bValveInterlock_In	:= aILK_AV[120] ,		
	bPMCCtrl_In			:= GVL.stPMCtoPLC.aAV[120] ,
	bValveOpen_Out		=> aAV[120] 	
);				
				
AV[121]				
(	bValveEnable_In 	:= TRUE ,		
	bInterlock1_In		:= bEMOStatus ,	
	bInterlock2_In		:= TRUE ,	
	bInterlock3_In		:= TRUE ,	
	bInterlock4_In		:= TRUE ,	
	bInterlock5_In		:= TRUE ,	
	bForceOpen_In		:= aForceOpValve[121],
	bValveInterlock_In	:= aILK_AV[121] ,		
	bPMCCtrl_In			:= GVL.stPMCtoPLC.aAV[121] ,
	bValveOpen_Out		=> aAV[121] 	
);				
				
AV[122]				
(	bValveEnable_In 	:= TRUE ,		
	bInterlock1_In		:= bEMOStatus ,	
	bInterlock2_In		:= TRUE ,	
	bInterlock3_In		:= TRUE ,	
	bInterlock4_In		:= TRUE ,	
	bInterlock5_In		:= TRUE ,	
	bForceOpen_In		:= aForceOpValve[122],
	bValveInterlock_In	:= aILK_AV[122] ,		
	bPMCCtrl_In			:= GVL.stPMCtoPLC.aAV[122] ,
	bValveOpen_Out		=> aAV[122] 	
);				
				
AV[123]				
(	bValveEnable_In 	:= TRUE ,		
	bInterlock1_In		:= bEMOStatus ,	
	bInterlock2_In		:= TRUE ,	
	bInterlock3_In		:= TRUE ,	
	bInterlock4_In		:= TRUE ,	
	bInterlock5_In		:= TRUE ,	
	bForceOpen_In		:= aForceOpValve[123],
	bValveInterlock_In	:= aILK_AV[123] ,		
	bPMCCtrl_In			:= GVL.stPMCtoPLC.aAV[123] ,
	bValveOpen_Out		=> aAV[123] 	
);				
				
AV[124]				
(	bValveEnable_In 	:= TRUE ,		
	bInterlock1_In		:= bEMOStatus ,	
	bInterlock2_In		:= TRUE ,	
	bInterlock3_In		:= TRUE ,	
	bInterlock4_In		:= TRUE ,	
	bInterlock5_In		:= TRUE ,	
	bForceOpen_In		:= aForceOpValve[124],
	bValveInterlock_In	:= aILK_AV[124] ,		
	bPMCCtrl_In			:= GVL.stPMCtoPLC.aAV[124] ,
	bValveOpen_Out		=> aAV[124] 	
);				
				
AV[125]				
(	bValveEnable_In 	:= TRUE ,		
	bInterlock1_In		:= bEMOStatus ,	
	bInterlock2_In		:= TRUE ,	
	bInterlock3_In		:= TRUE ,	
	bInterlock4_In		:= TRUE ,	
	bInterlock5_In		:= TRUE ,	
	bForceOpen_In		:= aForceOpValve[125],
	bValveInterlock_In	:= aILK_AV[125] ,		
	bPMCCtrl_In			:= GVL.stPMCtoPLC.aAV[125] ,
	bValveOpen_Out		=> aAV[125] 	
);				
				
AV[126]				
(	bValveEnable_In 	:= TRUE ,		
	bInterlock1_In		:= bEMOStatus ,	
	bInterlock2_In		:= TRUE ,	
	bInterlock3_In		:= TRUE ,	
	bInterlock4_In		:= TRUE ,	
	bInterlock5_In		:= TRUE ,	
	bForceOpen_In		:= aForceOpValve[126],
	bValveInterlock_In	:= aILK_AV[126] ,		
	bPMCCtrl_In			:= GVL.stPMCtoPLC.aAV[126] ,
	bValveOpen_Out		=> aAV[126] 	
);				
				
AV[127]				
(	bValveEnable_In 	:= TRUE ,		
	bInterlock1_In		:= bEMOStatus ,	
	bInterlock2_In		:= TRUE ,	
	bInterlock3_In		:= TRUE ,	
	bInterlock4_In		:= TRUE ,	
	bInterlock5_In		:= TRUE ,	
	bForceOpen_In		:= aForceOpValve[127],
	bValveInterlock_In	:= aILK_AV[127] ,		
	bPMCCtrl_In			:= GVL.stPMCtoPLC.aAV[127] ,
	bValveOpen_Out		=> aAV[127] 	
);				
				
AV[128]				
(	bValveEnable_In 	:= TRUE ,		
	bInterlock1_In		:= bEMOStatus ,	
	bInterlock2_In		:= TRUE ,	
	bInterlock3_In		:= TRUE ,	
	bInterlock4_In		:= TRUE ,	
	bInterlock5_In		:= TRUE ,	
	bForceOpen_In		:= aForceOpValve[128],
	bValveInterlock_In	:= aILK_AV[128] ,		
	bPMCCtrl_In			:= GVL.stPMCtoPLC.aAV[128] ,
	bValveOpen_Out		=> aAV[128] 	
);				
				
AV[129]				
(	bValveEnable_In 	:= TRUE ,		
	bInterlock1_In		:= bEMOStatus ,	
	bInterlock2_In		:= TRUE ,	
	bInterlock3_In		:= TRUE ,	
	bInterlock4_In		:= TRUE ,	
	bInterlock5_In		:= TRUE ,	
	bForceOpen_In		:= aForceOpValve[129],
	bValveInterlock_In	:= aILK_AV[129] ,		
	bPMCCtrl_In			:= GVL.stPMCtoPLC.aAV[129] ,
	bValveOpen_Out		=> aAV[129] 	
);				
				
AV[130]				
(	bValveEnable_In 	:= TRUE ,		
	bInterlock1_In		:= bEMOStatus ,	
	bInterlock2_In		:= TRUE ,	
	bInterlock3_In		:= TRUE ,	
	bInterlock4_In		:= TRUE ,	
	bInterlock5_In		:= TRUE ,	
	bForceOpen_In		:= aForceOpValve[130],
	bValveInterlock_In	:= aILK_AV[130] ,		
	bPMCCtrl_In			:= GVL.stPMCtoPLC.aAV[130] ,
	bValveOpen_Out		=> aAV[130] 	
);				
				
AV[131]				
(	bValveEnable_In 	:= TRUE ,		
	bInterlock1_In		:= bEMOStatus ,	
	bInterlock2_In		:= TRUE ,	
	bInterlock3_In		:= TRUE ,	
	bInterlock4_In		:= TRUE ,	
	bInterlock5_In		:= TRUE ,	
	bForceOpen_In		:= aForceOpValve[131],
	bValveInterlock_In	:= aILK_AV[131] ,		
	bPMCCtrl_In			:= GVL.stPMCtoPLC.aAV[131] ,
	bValveOpen_Out		=> aAV[131] 	
);				
				
AV[132]				
(	bValveEnable_In 	:= TRUE ,		
	bInterlock1_In		:= bEMOStatus ,	
	bInterlock2_In		:= TRUE ,	
	bInterlock3_In		:= TRUE ,	
	bInterlock4_In		:= TRUE ,	
	bInterlock5_In		:= TRUE ,	
	bForceOpen_In		:= aForceOpValve[132],
	bValveInterlock_In	:= aILK_AV[132] ,		
	bPMCCtrl_In			:= GVL.stPMCtoPLC.aAV[132] ,
	bValveOpen_Out		=> aAV[132] 	
);				
				
AV[133]				
(	bValveEnable_In 	:= TRUE ,		
	bInterlock1_In		:= bEMOStatus ,	
	bInterlock2_In		:= TRUE ,	
	bInterlock3_In		:= TRUE ,	
	bInterlock4_In		:= TRUE ,	
	bInterlock5_In		:= TRUE ,	
	bForceOpen_In		:= aForceOpValve[133],
	bValveInterlock_In	:= aILK_AV[133] ,		
	bPMCCtrl_In			:= GVL.stPMCtoPLC.aAV[133] ,
	bValveOpen_Out		=> aAV[133] 	
);				
				
AV[134]				
(	bValveEnable_In 	:= TRUE ,		
	bInterlock1_In		:= bEMOStatus ,	
	bInterlock2_In		:= TRUE ,	
	bInterlock3_In		:= TRUE ,	
	bInterlock4_In		:= TRUE ,	
	bInterlock5_In		:= TRUE ,	
	bForceOpen_In		:= aForceOpValve[134],
	bValveInterlock_In	:= aILK_AV[134] ,		
	bPMCCtrl_In			:= GVL.stPMCtoPLC.aAV[134] ,
	bValveOpen_Out		=> aAV[134] 	
);				
				
AV[135]				
(	bValveEnable_In 	:= TRUE ,		
	bInterlock1_In		:= bEMOStatus ,	
	bInterlock2_In		:= TRUE ,	
	bInterlock3_In		:= TRUE ,	
	bInterlock4_In		:= TRUE ,	
	bInterlock5_In		:= TRUE ,	
	bForceOpen_In		:= aForceOpValve[135],
	bValveInterlock_In	:= aILK_AV[135] ,		
	bPMCCtrl_In			:= GVL.stPMCtoPLC.aAV[135] ,
	bValveOpen_Out		=> aAV[135] 	
);				
				
AV[136]				
(	bValveEnable_In 	:= TRUE ,		
	bInterlock1_In		:= bEMOStatus ,	
	bInterlock2_In		:= TRUE ,	
	bInterlock3_In		:= TRUE ,	
	bInterlock4_In		:= TRUE ,	
	bInterlock5_In		:= TRUE ,	
	bForceOpen_In		:= aForceOpValve[136],
	bValveInterlock_In	:= aILK_AV[136] ,		
	bPMCCtrl_In			:= GVL.stPMCtoPLC.aAV[136] ,
	bValveOpen_Out		=> aAV[136] 	
);				
				
AV[137]				
(	bValveEnable_In 	:= TRUE ,		
	bInterlock1_In		:= bEMOStatus ,	
	bInterlock2_In		:= TRUE ,	
	bInterlock3_In		:= TRUE ,	
	bInterlock4_In		:= TRUE ,	
	bInterlock5_In		:= TRUE ,	
	bForceOpen_In		:= aForceOpValve[137],
	bValveInterlock_In	:= aILK_AV[137] ,		
	bPMCCtrl_In			:= GVL.stPMCtoPLC.aAV[137] ,
	bValveOpen_Out		=> aAV[137] 	
);				
				
AV[138]				
(	bValveEnable_In 	:= TRUE ,		
	bInterlock1_In		:= bEMOStatus ,	
	bInterlock2_In		:= TRUE ,	
	bInterlock3_In		:= TRUE ,	
	bInterlock4_In		:= TRUE ,	
	bInterlock5_In		:= TRUE ,	
	bForceOpen_In		:= aForceOpValve[138],
	bValveInterlock_In	:= aILK_AV[138] ,		
	bPMCCtrl_In			:= GVL.stPMCtoPLC.aAV[138] ,
	bValveOpen_Out		=> aAV[138] 	
);				
				
AV[139]				
(	bValveEnable_In 	:= TRUE ,		
	bInterlock1_In		:= bEMOStatus ,	
	bInterlock2_In		:= TRUE ,	
	bInterlock3_In		:= TRUE ,	
	bInterlock4_In		:= TRUE ,	
	bInterlock5_In		:= TRUE ,	
	bForceOpen_In		:= aForceOpValve[139],
	bValveInterlock_In	:= aILK_AV[139] ,		
	bPMCCtrl_In			:= GVL.stPMCtoPLC.aAV[139] ,
	bValveOpen_Out		=> aAV[139] 	
);				
				
AV[140]				
(	bValveEnable_In 	:= TRUE ,		
	bInterlock1_In		:= bEMOStatus ,	
	bInterlock2_In		:= TRUE ,	
	bInterlock3_In		:= TRUE ,	
	bInterlock4_In		:= TRUE ,	
	bInterlock5_In		:= TRUE ,	
	bForceOpen_In		:= aForceOpValve[140],
	bValveInterlock_In	:= aILK_AV[140] ,		
	bPMCCtrl_In			:= GVL.stPMCtoPLC.aAV[140] ,
	bValveOpen_Out		=> aAV[140] 	
);				
				
AV[141]				
(	bValveEnable_In 	:= TRUE ,		
	bInterlock1_In		:= bEMOStatus ,	
	bInterlock2_In		:= TRUE ,	
	bInterlock3_In		:= TRUE ,	
	bInterlock4_In		:= TRUE ,	
	bInterlock5_In		:= TRUE ,	
	bForceOpen_In		:= aForceOpValve[141],
	bValveInterlock_In	:= aILK_AV[141] ,		
	bPMCCtrl_In			:= GVL.stPMCtoPLC.aAV[141] ,
	bValveOpen_Out		=> aAV[141] 	
);				
				
AV[142]				
(	bValveEnable_In 	:= TRUE ,		
	bInterlock1_In		:= bEMOStatus ,	
	bInterlock2_In		:= TRUE ,	
	bInterlock3_In		:= TRUE ,	
	bInterlock4_In		:= TRUE ,	
	bInterlock5_In		:= TRUE ,	
	bForceOpen_In		:= aForceOpValve[142],
	bValveInterlock_In	:= aILK_AV[142] ,		
	bPMCCtrl_In			:= GVL.stPMCtoPLC.aAV[142] ,
	bValveOpen_Out		=> aAV[142] 	
);				
				
AV[143]				
(	bValveEnable_In 	:= TRUE ,		
	bInterlock1_In		:= bEMOStatus ,	
	bInterlock2_In		:= TRUE ,	
	bInterlock3_In		:= TRUE ,	
	bInterlock4_In		:= TRUE ,	
	bInterlock5_In		:= TRUE ,	
	bForceOpen_In		:= aForceOpValve[143],
	bValveInterlock_In	:= aILK_AV[143] ,		
	bPMCCtrl_In			:= GVL.stPMCtoPLC.aAV[143] ,
	bValveOpen_Out		=> aAV[143] 	
);				
				
AV[144]				
(	bValveEnable_In 	:= TRUE ,		
	bInterlock1_In		:= bEMOStatus ,	
	bInterlock2_In		:= TRUE ,	
	bInterlock3_In		:= TRUE ,	
	bInterlock4_In		:= TRUE ,	
	bInterlock5_In		:= TRUE ,	
	bForceOpen_In		:= aForceOpValve[144],
	bValveInterlock_In	:= aILK_AV[144] ,		
	bPMCCtrl_In			:= GVL.stPMCtoPLC.aAV[144] ,
	bValveOpen_Out		=> aAV[144] 	
);				
				
AV[145]				
(	bValveEnable_In 	:= TRUE ,		
	bInterlock1_In		:= bEMOStatus ,	
	bInterlock2_In		:= TRUE ,	
	bInterlock3_In		:= TRUE ,	
	bInterlock4_In		:= TRUE ,	
	bInterlock5_In		:= TRUE ,	
	bForceOpen_In		:= aForceOpValve[145],
	bValveInterlock_In	:= aILK_AV[145] ,		
	bPMCCtrl_In			:= GVL.stPMCtoPLC.aAV[145] ,
	bValveOpen_Out		=> aAV[145] 	
);				
				
AV[146]				
(	bValveEnable_In 	:= TRUE ,		
	bInterlock1_In		:= bEMOStatus ,	
	bInterlock2_In		:= TRUE ,	
	bInterlock3_In		:= TRUE ,	
	bInterlock4_In		:= TRUE ,	
	bInterlock5_In		:= TRUE ,	
	bForceOpen_In		:= aForceOpValve[146],
	bValveInterlock_In	:= aILK_AV[146] ,		
	bPMCCtrl_In			:= GVL.stPMCtoPLC.aAV[146] ,
	bValveOpen_Out		=> aAV[146] 	
);				
				
AV[147]				
(	bValveEnable_In 	:= TRUE ,		
	bInterlock1_In		:= bEMOStatus ,	
	bInterlock2_In		:= TRUE ,	
	bInterlock3_In		:= TRUE ,	
	bInterlock4_In		:= TRUE ,	
	bInterlock5_In		:= TRUE ,	
	bForceOpen_In		:= aForceOpValve[147],
	bValveInterlock_In	:= aILK_AV[147] ,		
	bPMCCtrl_In			:= GVL.stPMCtoPLC.aAV[147] ,
	bValveOpen_Out		=> aAV[147] 	
);				
				
AV[148]				
(	bValveEnable_In 	:= TRUE ,		
	bInterlock1_In		:= bEMOStatus ,	
	bInterlock2_In		:= TRUE ,	
	bInterlock3_In		:= TRUE ,	
	bInterlock4_In		:= TRUE ,	
	bInterlock5_In		:= TRUE ,	
	bForceOpen_In		:= aForceOpValve[148],
	bValveInterlock_In	:= aILK_AV[148] ,		
	bPMCCtrl_In			:= GVL.stPMCtoPLC.aAV[148] ,
	bValveOpen_Out		=> aAV[148] 	
);				
				
AV[149]				
(	bValveEnable_In 	:= TRUE ,		
	bInterlock1_In		:= bEMOStatus ,	
	bInterlock2_In		:= TRUE ,	
	bInterlock3_In		:= TRUE ,	
	bInterlock4_In		:= TRUE ,	
	bInterlock5_In		:= TRUE ,	
	bForceOpen_In		:= aForceOpValve[149],
	bValveInterlock_In	:= aILK_AV[149] ,		
	bPMCCtrl_In			:= GVL.stPMCtoPLC.aAV[149] ,
	bValveOpen_Out		=> aAV[149] 	
);				
				
AV[150]				
(	bValveEnable_In 	:= TRUE ,		
	bInterlock1_In		:= bEMOStatus ,	
	bInterlock2_In		:= TRUE ,	
	bInterlock3_In		:= TRUE ,	
	bInterlock4_In		:= TRUE ,	
	bInterlock5_In		:= TRUE ,	
	bForceOpen_In		:= aForceOpValve[150],
	bValveInterlock_In	:= aILK_AV[150] ,		
	bPMCCtrl_In			:= GVL.stPMCtoPLC.aAV[150] ,
	bValveOpen_Out		=> aAV[150] 	
);		

(*AV[202]
(	bValveEnable_In 	:= TRUE ,		
	bInterlock1_In		:= bEMOStatus ,	
	bInterlock2_In		:= TRUE ,	
	bInterlock3_In		:= TRUE ,	
	bInterlock4_In		:= TRUE ,	
	bInterlock5_In		:= TRUE ,	
	bForceOpen_In		:= aForceOpValve[150],
	bValveInterlock_In	:= TRUE(*aILK_AV[202]*) ,		
	bPMCCtrl_In			:= GVL.stPMCtoPLC.aAV[202] ,
	bValveOpen_Out		=> aAV[202] 	
);	*)

AV202Open				
(	bValveEnable_In 	:= TRUE ,		
	bInterlock1_In		:= bEMOStatus ,	
	bInterlock2_In		:= TRUE ,	
	bInterlock3_In		:= TRUE ,	
	bInterlock4_In		:= TRUE ,	
	bInterlock5_In		:= TRUE ,
	bForceOpen_In		:= bForceAV202Open,	
	bValveInterlock_In	:= aILK_AV[202] ,		
	bPMCCtrl_In			:= GVL.stPMCtoPLC.bAV202Open ,
	bValveOpen_Out		=> GVL.bAV202Open 	
);	

AV202Close				
(	bValveEnable_In 	:= TRUE ,		
	bInterlock1_In		:= bEMOStatus ,	
	bInterlock2_In		:= TRUE ,	
	bInterlock3_In		:= TRUE ,	
	bInterlock4_In		:= TRUE ,	
	bInterlock5_In		:= TRUE ,
	bForceOpen_In		:= bForceAV202Close,	
	bValveInterlock_In	:= aILK_AV[202] ,		
	bPMCCtrl_In			:= GVL.stPMCtoPLC.bAV202Close ,
	bValveOpen_Out		=> GVL.bAV202Close 	
);
END_ACTION

ACTION ValveMapping:
//interlock mapping
GVL.stPLCtoPMC.stIntlk := stILK ; 

//valve interlock mapping
GVL.stPLCtoPMC.aILK_AV := aILK_AV ;

//VAC mapping
GVL.stPLCtoPMC.aVAC		:= aVAC ;

//AV540
GVL.stPLCtoPMC.bAV540	:= bAV540 ;

(*EV1*)
//stGBQ.QEV[1].A.uBit.v1	:=  aAV[];
stGBQ.QEV[1].A.uBit.v2	:=  aAV[52];
//stGBQ.QEV[1].A.uBit.v3	:=  aAV[];
stGBQ.QEV[1].A.uBit.v4	:=  aAV[100];
//stGBQ.QEV[1].A.uBit.v5	:=  aAV[];
stGBQ.QEV[1].A.uBit.v6	:=  aAV[102];
stGBQ.QEV[1].A.uBit.v7	:=  aAV[103];
stGBQ.QEV[1].A.uBit.v8	:=  aAV[104];
	
stGBQ.QEV[1].B.uBit.v1	:=  aAV[105];
stGBQ.QEV[1].B.uBit.v2	:=  aAV[106];
stGBQ.QEV[1].B.uBit.v3	:=  aAV[107];
//stGBQ.QEV[1].B.uBit.v4	:=  aAV[];
//stGBQ.QEV[1].B.uBit.v5	:=  aAV[];
stGBQ.QEV[1].B.uBit.v6	:=  aAV[110];
//stGBQ.QEV[1].B.uBit.v7	:=  aAV[];
stGBQ.QEV[1].B.uBit.v8	:=  aAV[112];
	
//stGBQ.QEV[1].C.uBit.v1	:=  aAV[];
stGBQ.QEV[1].C.uBit.v2	:=  aAV[120];
stGBQ.QEV[1].C.uBit.v3	:=  aAV[121];
stGBQ.QEV[1].C.uBit.v4	:=  aAV[122];
stGBQ.QEV[1].C.uBit.v5	:=  aAV[123];
stGBQ.QEV[1].C.uBit.v6	:=  aAV[124];
stGBQ.QEV[1].C.uBit.v7	:=  aAV[125];
stGBQ.QEV[1].C.uBit.v8	:=  aAV[126];
	
stGBQ.QEV[1].D.uBit.v1	:=  aAV[127];
stGBQ.QEV[1].D.uBit.v2	:=  aAV[128];
stGBQ.QEV[1].D.uBit.v3	:=  aAV[129];
stGBQ.QEV[1].D.uBit.v4	:=  aAV[130];
stGBQ.QEV[1].D.uBit.v5	:=  aAV[131];
//stGBQ.QEV[1].D.uBit.v6	:=  aAV[];
stGBQ.QEV[1].D.uBit.v7	:=  aAV[136];
stGBQ.QEV[1].D.uBit.v8	:=  aAV[137];


//EV2
stGBQ.QEV[2].A.uBit.v1	:=  aAV[101];
stGBQ.QEV[2].A.uBit.v2	:=  aAV[111];
//stGBQ.QEV[2].A.uBit.v3	:=  
//stGBQ.QEV[2].A.uBit.v4	:=  
//stGBQ.QEV[2].A.uBit.v5	:=  
//stGBQ.QEV[2].A.uBit.v6	:=  
//stGBQ.QEV[2].A.uBit.v7	:=  
//stGBQ.QEV[2].A.uBit.v8	:=  
	
(*sstGBQ.QEV[2].B.uBit.v1	:=  
stGBQ.QEV[2].B.uBit.v2	:=  
stGBQ.QEV[2].B.uBit.v3	:=  
stGBQ.QEV[2].B.uBit.v4	:=  
stGBQ.QEV[2].B.uBit.v5	:=  
stGBQ.QEV[2].B.uBit.v6	:=  
stGBQ.QEV[2].B.uBit.v7	:=  
stGBQ.QEV[2].B.uBit.v8	:=  
	
tGBQ.QEV[2].C.uBit.v1	:=  
stGBQ.QEV[2].C.uBit.v2	:=  
stGBQ.QEV[2].C.uBit.v3	:=  
stGBQ.QEV[2].C.uBit.v4	:=  
stGBQ.QEV[2].C.uBit.v5	:=  
stGBQ.QEV[2].C.uBit.v6	:=  
stGBQ.QEV[2].C.uBit.v7	:=  
stGBQ.QEV[2].C.uBit.v8	:=  
	
stGBQ.QEV[2].D.uBit.v1	:=  
stGBQ.QEV[2].D.uBit.v2	:=  
stGBQ.QEV[2].D.uBit.v3	:=  
stGBQ.QEV[2].D.uBit.v4	:=  
stGBQ.QEV[2].D.uBit.v5	:=  
stGBQ.QEV[2].D.uBit.v6	:=  
stGBQ.QEV[2].D.uBit.v7	:=  
stGBQ.QEV[2].D.uBit.v8	:=  *)

//EV3
stGBQ.QEV[3].A.uBit.v1	:=  aAV[1];
//stGBQ.QEV[3].A.uBit.v2	:=  aAV[];
stGBQ.QEV[3].A.uBit.v3	:=  aAV[3];
stGBQ.QEV[3].A.uBit.v4	:=  aAV[4];
stGBQ.QEV[3].A.uBit.v5	:=  aAV[5];
stGBQ.QEV[3].A.uBit.v6	:=  aAV[6];
stGBQ.QEV[3].A.uBit.v7	:=  aAV[7];
stGBQ.QEV[3].A.uBit.v8	:=  aAV[8];
	
stGBQ.QEV[3].B.uBit.v1	:=  aAV[9];
stGBQ.QEV[3].B.uBit.v2	:=  aAV[10];
stGBQ.QEV[3].B.uBit.v3	:=  aAV[11];
stGBQ.QEV[3].B.uBit.v4	:=  aAV[33];
stGBQ.QEV[3].B.uBit.v5	:=  aAV[13];
stGBQ.QEV[3].B.uBit.v6	:=  aAV[14];
stGBQ.QEV[3].B.uBit.v7	:=  aAV[15];
stGBQ.QEV[3].B.uBit.v8	:=  aAV[35];
	
stGBQ.QEV[3].C.uBit.v1	:=  aAV[17];
stGBQ.QEV[3].C.uBit.v2	:=  aAV[18];
stGBQ.QEV[3].C.uBit.v3	:=  aAV[19];
stGBQ.QEV[3].C.uBit.v4	:=  aAV[36];
stGBQ.QEV[3].C.uBit.v5	:=  aAV[21];
stGBQ.QEV[3].C.uBit.v6	:=  aAV[22];
stGBQ.QEV[3].C.uBit.v7	:=  aAV[23];
stGBQ.QEV[3].C.uBit.v8	:=  aAV[24];
	
stGBQ.QEV[3].D.uBit.v1	:=  aAV[25];
//stGBQ.QEV[3].D.uBit.v2	:=  aAV[];
stGBQ.QEV[3].D.uBit.v3	:=  aAV[27];
stGBQ.QEV[3].D.uBit.v4	:=  aAV[28];
stGBQ.QEV[3].D.uBit.v5	:=  aAV[29];
//stGBQ.QEV[3].D.uBit.v6	:=  aAV[];
stGBQ.QEV[3].D.uBit.v7	:=  aAV[31];
stGBQ.QEV[3].D.uBit.v8	:=  aAV[32];

//EV4
stGBQ.QEV[4].A.uBit.v1	:=  aAV[16];
stGBQ.QEV[4].A.uBit.v2	:=  aAV[12];
stGBQ.QEV[4].A.uBit.v3	:=  aAV[26];
stGBQ.QEV[4].A.uBit.v4	:=  aAV[20];
stGBQ.QEV[4].A.uBit.v5	:=  aAV[34];
stGBQ.QEV[4].A.uBit.v6	:=  aAV[30];
//stGBQ.QEV[4].A.uBit.v7	:=  aAV[];
//stGBQ.QEV[4].A.uBit.v8	:=  aAV[];
	
(*stGBQ.QEV[4].B.uBit.v1	:=  
stGBQ.QEV[4].B.uBit.v2	:=  
stGBQ.QEV[4].B.uBit.v3	:=  
stGBQ.QEV[4].B.uBit.v4	:=  
stGBQ.QEV[4].B.uBit.v5	:=  
stGBQ.QEV[4].B.uBit.v6	:=  
stGBQ.QEV[4].B.uBit.v7	:=  
stGBQ.QEV[4].B.uBit.v8	:=  
	
stGBQ.QEV[4].C.uBit.v1	:=  
stGBQ.QEV[4].C.uBit.v2	:=  
stGBQ.QEV[4].C.uBit.v3	:=  
stGBQ.QEV[4].C.uBit.v4	:=  
stGBQ.QEV[4].C.uBit.v5	:=  
stGBQ.QEV[4].C.uBit.v6	:=  
stGBQ.QEV[4].C.uBit.v7	:=  
stGBQ.QEV[4].C.uBit.v8	:=  
	
stGBQ.QEV[4].D.uBit.v1	:=  
stGBQ.QEV[4].D.uBit.v2	:=  
stGBQ.QEV[4].D.uBit.v3	:=  
stGBQ.QEV[4].D.uBit.v4	:=  
stGBQ.QEV[4].D.uBit.v5	:=  
stGBQ.QEV[4].D.uBit.v6	:=  
stGBQ.QEV[4].D.uBit.v7	:=  
stGBQ.QEV[4].D.uBit.v8	:=  *)

//EV5
stGBQ.QEV[5].A.uBit.v1	:=  GVL.bAV65Open;
stGBQ.QEV[5].A.uBit.v2	:=  GVL.bAV65Close;
stGBQ.QEV[5].A.uBit.v3	:=  GVL.bAV202Open;
stGBQ.QEV[5].A.uBit.v4	:=  GVL.bAV202Close;
//stGBQ.QEV[5].A.uBit.v5	:=  
//stGBQ.QEV[5].A.uBit.v6	:=  
//stGBQ.QEV[5].A.uBit.v7	:=  
//stGBQ.QEV[5].A.uBit.v8	:=  
	
(*stGBQ.QEV[5].B.uBit.v1	:=  
stGBQ.QEV[5].B.uBit.v2	:=  
stGBQ.QEV[5].B.uBit.v3	:=  
stGBQ.QEV[5].B.uBit.v4	:=  
stGBQ.QEV[5].B.uBit.v5	:=  
stGBQ.QEV[5].B.uBit.v6	:=  
stGBQ.QEV[5].B.uBit.v7	:=  
stGBQ.QEV[5].B.uBit.v8	:=  
	
stGBQ.QEV[5].C.uBit.v1	:=  
stGBQ.QEV[5].C.uBit.v2	:=  
stGBQ.QEV[5].C.uBit.v3	:=  
stGBQ.QEV[5].C.uBit.v4	:=  
stGBQ.QEV[5].C.uBit.v5	:=  
stGBQ.QEV[5].C.uBit.v6	:=  
stGBQ.QEV[5].C.uBit.v7	:=  
stGBQ.QEV[5].C.uBit.v8	:=  
	
stGBQ.QEV[5].D.uBit.v1	:=  
stGBQ.QEV[5].D.uBit.v2	:=  
stGBQ.QEV[5].D.uBit.v3	:=  
stGBQ.QEV[5].D.uBit.v4	:=  
stGBQ.QEV[5].D.uBit.v5	:=  
stGBQ.QEV[5].D.uBit.v6	:=  
stGBQ.QEV[5].D.uBit.v7	:=  
stGBQ.QEV[5].D.uBit.v8	:=  *)

//VT301
stEXHQ.QEV[1].A.uBit.v1	:=  GVL.bAV79Open(*aAV[78]*);
stEXHQ.QEV[1].A.uBit.v2	:=  GVL.bAV79Close(*aAV[78]*);
//stEXHQ.QEV[1].A.uBit.v3	:=  aAV[];
//stEXHQ.QEV[1].A.uBit.v4	:=  aAV[];
//stEXHQ.QEV[1].A.uBit.v5	:=  aAV[];
//stEXHQ.QEV[1].A.uBit.v6	:=  aAV[];
//stEXHQ.QEV[1].A.uBit.v7	:=  aAV[];
//stEXHQ.QEV[1].A.uBit.v8	:=  aAV[];
	
//stEXHQ.QEV[1].B.uBit.v1	:=  aAV[];
//stEXHQ.QEV[1].B.uBit.v2	:=  aAV[];
stEXHQ.QEV[1].B.uBit.v3	:=  GVL.bAV91Open;
stEXHQ.QEV[1].B.uBit.v4	:=  GVL.bAV91Close;
stEXHQ.QEV[1].B.uBit.v5	:=  FALSE(*aAV[71]*);
//stEXHQ.QEV[1].B.uBit.v6	:=  aAV[];
stEXHQ.QEV[1].B.uBit.v7	:=  aAV[60];
stEXHQ.QEV[1].B.uBit.v8	:=  aAV[67];
	
stEXHQ.QEV[1].C.uBit.v1	:=  aAV[68];
stEXHQ.QEV[1].C.uBit.v2	:=  aAV[72];
stEXHQ.QEV[1].C.uBit.v3	:=  aAV[73];
stEXHQ.QEV[1].C.uBit.v4	:=  aAV[74];
stEXHQ.QEV[1].C.uBit.v5	:=  aAV[75];
stEXHQ.QEV[1].C.uBit.v6	:=  aAV[77];
stEXHQ.QEV[1].C.uBit.v7	:=  aAV[85];
stEXHQ.QEV[1].C.uBit.v8	:=  aAV[86];
	
stEXHQ.QEV[1].D.uBit.v1	:=  aAV[87];
stEXHQ.QEV[1].D.uBit.v2	:=  aAV[88];
(*stEXHQ.QEV[1].D.uBit.v3	:=  
stEXHQ.QEV[1].D.uBit.v4	:=  
stEXHQ.QEV[1].D.uBit.v5	:=  
stEXHQ.QEV[1].D.uBit.v6	:=  
stEXHQ.QEV[1].D.uBit.v7	:=  
stEXHQ.QEV[1].D.uBit.v8	:=  *)
END_ACTION

END_PROGRAM

// ---- POUs/_900_FB/AnalogConverter.TcPOU
FUNCTION_BLOCK AnalogConverter
VAR_INPUT
	AnalogRdValue_In_Int: INT;
	AnalogResMin_In_Int: INT;
	AnalogResMax_In_Int: INT;
	AnalogPhyMin_In_Real: REAL;
	AnalogPhyMax_In_Real: REAL;
	AnalogRdOffset_In_Real: REAL;
END_VAR
VAR_OUTPUT
	ActRdValue_Out_Real: REAL;
END_VAR
VAR
END_VAR

//模拟量输入限定范围
AnalogRdValue_In_Int := LIMIT(	AnalogResMin_In_Int , AnalogRdValue_In_Int , AnalogResMax_In_Int );

ActRdValue_Out_Real := 
	(	INT_TO_REAL (AnalogRdValue_In_Int)  - INT_TO_REAL (AnalogResMin_In_Int) ) / (	INT_TO_REAL (AnalogResMax_In_Int ) - INT_TO_REAL (AnalogResMin_In_Int) ) * 
	(	AnalogPhyMax_In_Real - AnalogPhyMin_In_Real ) + AnalogPhyMin_In_Real + AnalogRdOffset_In_Real ;

END_FUNCTION_BLOCK

// ---- POUs/_900_FB/Valve.TcPOU
FUNCTION_BLOCK Valve
VAR_INPUT
	bValveEnable_In		: BOOL;
	bInterlock1_In		: BOOL;
	bInterlock2_In		: BOOL;
	bInterlock3_In		: BOOL;
	bInterlock4_In		: BOOL;
	bInterlock5_In		: BOOL;
	bValveInterlock_In	: BOOL;
	bPMCCtrl_In			: BOOL;
	bForceOpen_In		: BOOL;
END_VAR
VAR_OUTPUT
	bValveOpen_Out		: BOOL;
END_VAR
VAR
END_VAR

IF bValveEnable_In THEN
	IF bInterlock1_In AND bInterlock2_In AND bInterlock3_In AND bInterlock4_In AND bInterlock5_In THEN
		IF bForceOpen_In OR ( bValveInterlock_In AND bPMCCtrl_In ) THEN
			bValveOpen_Out := TRUE ;
		ELSE
			bValveOpen_Out := FALSE ;
		END_IF
	ELSE
			bValveOpen_Out := FALSE ;
	END_IF
END_IF

END_FUNCTION_BLOCK

// ---- POUs/_200_Interlock/Interlock.TcPOU
PROGRAM Interlock
VAR
	TON_PG21: TON;
	TON_PG22: TOF;
	TON_PG23: TOF;
	MS11_S_TON: TON;
	MS2_S_TON: TON;
	MS12_S_TON: TON;
	BufferN2Press_TON: TON;
	VP1Down_TON: TON;
	DG1_TON: TON;
	OT_RHC_TON: TON;
	BlowerOverLoad_RTrig: R_TRIG;
	HTConc_RTrig: R_TRIG;
	T102Conc_RTrig: R_TRIG;
	
	VAC1_TON: TON;
	VAC1_Bypass: R_TRIG;
	bVAC1_Bypass: BOOL;
	VAC2_TON: TON;
	bVAC2_Bypass: BOOL;
	VAC2_Bypass: R_TRIG;
	VAC3_TON: TON;
	bVAC3_Bypass: BOOL;
	VAC3_Bypass: R_TRIG;
	VAC4_TON: TON;
	bVAC4_Bypass: BOOL;
	VAC4_Bypass: R_TRIG;
	VAC5_TON: TON;
	bVAC5_Bypass: BOOL;
	VAC5_Bypass: R_TRIG;
	AV73_TOF: TOF;
	T_REF_TON: TON;
	FL301_TON: TON;
	
	bRHC_Damper_Open			:BOOL;	// RHC Dapmer in open position
	bRHC_Damper_Close			:BOOL;	// RHC Damper in close position
	bMS2_MS2S_Status_Abnormal	:BOOL;	// MS2和MS2-S状态不一致
	bMS11_MS11S_Status_Abnormal	:BOOL;	// MS11和MS11-S状态不一致
	bMS12_MS12S_Status_Abnormal	:BOOL;	// MS12和MS12-S状态不一致
	bGV_Open					:BOOL;	// Gate valve open status
	bGV_Close					:BOOL;	// Gate valve close status
	bFFUAlarm					:BOOL;	// FFU alarm
	GV_Open_TON: TON;
	GV_Close_TON: TON;
	ATM_Dpr_Cl_TON: TON;
	ATM_Dpr_Op_TON: TON;
	Cycle_Dpr_Op_TON: TON;
	Cycle_Dpr_Cl_TON: TON;
	LSC_Float_Abnormal_TON: TON;
	LSC_HH_TON: TON;
	LSC_H_TON:TON;
	LSC_M_TON: TON;
	LSC_L_TON: TON;
	GasMS_Abnormal_TON :TON;
	T_REF_ET: TIME;
	AV73_ET: TIME;
	GV_Open_ET: TIME;
	GV_Close_ET: TIME;
	BufferN2Press_ET: TIME;
	LSC_Float_Abnormal_ET: TIME;
	TON_PG23_ET: TIME;
	LSC_HH_TON_ET: TIME;
	LSC_H_TON_ET: TIME;
	LSC_M_TON_ET: TIME;
	LSC_L_TON_ET: TIME;
	VP1Down_TON_ET: TIME;
	ATM_Dpr_Op_TON_ET: TIME;
	ATM_Dpr_Cl_TON_ET: TIME;
	Cycle_Dpr_Op_TON_ET: TIME;
	Cycle_Dpr_Cl_TON_ET: TIME;
	MS12_S_TON_ET: TIME;
	MS11_S_TON_ET: TIME;
	MS2_S_TON_ET: TIME;
	FL301_TON_ET: TIME;
	TON_PG22_TON: TIME;
	DG1_TON_ET: TIME;
	GasMS_Abnormal_TON_ET: TIME;
	TON_PG21_ET: TIME;
	OT_RHC_TON_ET: TIME;
	VAC4_TON_ET: TIME;
	VAC1_TON_ET: TIME;
	VAC5_TON_ET: TIME;
	VAC3_TON_ET: TIME;
	VAC2_TON_ET: TIME;
	PG23_TON: TON;
	PG22_TON: TON;
	RHC_Damper_Pos_TON: TON;
	RHC_Damper_Pos_TON_ET: TIME;
	LSC1_Refill_TON: TON;
	LSC1_H_Trig: R_TRIG;
	bLSC1_H_OK: BOOL;
	LSC1_Refill_TON_ET: TIME;
	PS21_TON: TON;
	PS21_TON_ET: TIME;
	VG11_Warning	: dut_UDINT_BOOL ;
	VG11_Error		: dut_UDINT_BOOL ;
	VG13_Warning	: dut_UDINT_BOOL ;
	VG13_Error		: dut_UDINT_BOOL ;
	VG31_Warning	: dut_UDINT_BOOL ;
	VG31_Error		: dut_UDINT_BOOL ;
END_VAR
VAR // added by the converter: edge detectors and wires of the graphical bodies
    _w1, _w2, _w3, _w4, _w5, _w6, _w7, _w8, _w9, _w10, _w11, _w12, _w13, _w14, _w15, _w16, _w17 : BOOL;
    _ft1 : F_TRIG;
END_VAR

//Interlock平时不触发为OFF，触发时为ON并发出报警相关阀无法打开，需要复位后才可进一步操作

INTLK();
Valve_Intlk();
AutoValve_Intlk();
VAC_Condition();
BoatUnload_Intlk();

bRHC_Damper_Open := stEXHI.I303_02 AND stEXHI.I303_04 AND stEXHI.I303_06 AND stEXHI.I303_08 ;
bRHC_Damper_Close:= stEXHI.I303_03 AND stEXHI.I303_05 AND stEXHI.I303_07 AND stEXHI.I303_09 ;

bMS2_MS2S_Status_Abnormal   := stGBI.I202_00 XOR GVL.stPMCtoPLC.MS2_S_gas_box_exhaust_alarm  ;
bMS11_MS11S_Status_Abnormal := stOPI.I600_10 XOR GVL.stPMCtoPLC.MS11_S_gas_box_exhaust_alarm ;
bMS12_MS12S_Status_Abnormal := stOPI.I600_12 XOR GVL.stPMCtoPLC.MS12_S_gas_box_exhaust_alarm ;

bGV_Open	:= stEXHI.I303_13 AND stEXHI.I303_15 ;
bGV_Close	:= stEXHI.I303_12 AND stEXHI.I303_14 ;

VG11_Warning.Data_UDINT := GVL.stPMCtoPLC.VG11_Active_Device_Warning_Details ;
VG11_Error.Data_UDINT	:= GVL.stPMCtoPLC.VG11_Active_Device_Error_Details	 ;

VG13_Warning.Data_UDINT := GVL.stPMCtoPLC.VG13_Active_Device_Warning_Details ;
VG13_Error.Data_UDINT	:= GVL.stPMCtoPLC.VG13_Active_Device_Error_Details	 ;

VG31_Warning.Data_UDINT := GVL.stPMCtoPLC.VG31_Active_Device_Warning_Details ;
VG31_Error.Data_UDINT	:= GVL.stPMCtoPLC.VG31_Active_Device_Error_Details	 ;

//FFU停转状态
bFFUAlarm := 
	( AI.FFU1_1_STATUS = 1 OR AI.FFU1_1_STATUS = 4 ) OR 
	( AI.FFU1_2_STATUS = 1 OR AI.FFU1_2_STATUS = 4 ) OR 
	( AI.FFU1_3_STATUS = 1 OR AI.FFU1_3_STATUS = 4 ) OR 
	( AI.FFU1_4_STATUS = 1 OR AI.FFU1_4_STATUS = 4 ) OR 
	( AI.FFU1_5_STATUS = 1 OR AI.FFU1_5_STATUS = 4 ) OR 
	( AI.FFU1_6_STATUS = 1 OR AI.FFU1_6_STATUS = 4 ) OR 
	( AI.FFU2_1_STATUS = 1 OR AI.FFU2_1_STATUS = 4 ) OR 
	( AI.FFU2_2_STATUS = 1 OR AI.FFU2_2_STATUS = 4 ) OR 
	( AI.FFU2_3_STATUS = 1 OR AI.FFU2_3_STATUS = 4 ) OR 
	( AI.FFU2_4_STATUS = 1 OR AI.FFU2_4_STATUS = 4 ) OR 
	( AI.FFU2_5_STATUS = 1 OR AI.FFU2_5_STATUS = 4 ) OR 
	( AI.FFU2_6_STATUS = 1 OR AI.FFU2_6_STATUS = 4 ) OR 
	( AI.FFU3_1_STATUS = 1 OR AI.FFU3_1_STATUS = 4 ) OR 
	( AI.FFU3_2_STATUS = 1 OR AI.FFU3_2_STATUS = 4 ) OR 
	( AI.FFU3_3_STATUS = 1 OR AI.FFU3_3_STATUS = 4 ) OR 
	( AI.FFU3_4_STATUS = 1 OR AI.FFU3_4_STATUS = 4 ) OR 
	( AI.FFU3_5_STATUS = 1 OR AI.FFU3_5_STATUS = 4 ) OR 
	( AI.FFU3_6_STATUS = 1 OR AI.FFU3_6_STATUS = 4 ) ;

ACTION AutoValve_Intlk:
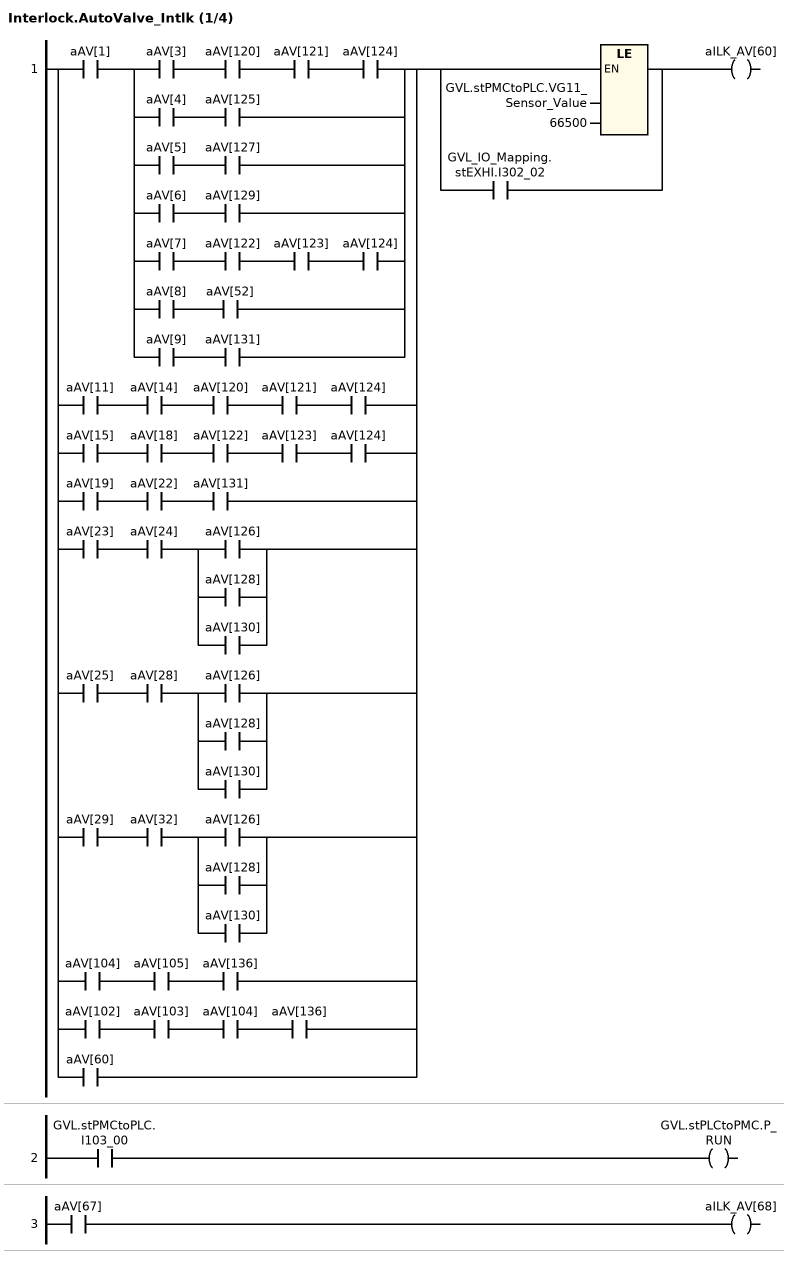
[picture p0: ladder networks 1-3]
// NETWORK 1
_w1 := aAV[1] AND (aAV[3] AND aAV[120] AND aAV[121] AND aAV[124] OR aAV[4] AND aAV[125] OR aAV[5] AND aAV[127] OR aAV[6] AND aAV[129] OR aAV[7] AND aAV[122] AND aAV[123] AND aAV[124] OR aAV[8] AND aAV[52] OR aAV[9] AND aAV[131]) OR aAV[11] AND aAV[14] AND aAV[120] AND aAV[121] AND aAV[124] OR aAV[15] AND aAV[18] AND aAV[122] AND aAV[123] AND aAV[124] OR aAV[19] AND aAV[22] AND aAV[131] OR aAV[23] AND aAV[24] AND (aAV[126] OR aAV[128] OR aAV[130]) OR aAV[25] AND aAV[28] AND (aAV[126] OR aAV[128] OR aAV[130]) OR aAV[29] AND aAV[32] AND (aAV[126] OR aAV[128] OR aAV[130]) OR aAV[104] AND aAV[105] AND aAV[136] OR aAV[102] AND aAV[103] AND aAV[104] AND aAV[136] OR aAV[60];
_w2 := _w1 AND GVL_IO_Mapping.stEXHI.I302_02;
IF NOT _w2 THEN
    _w2 := _w1 AND GVL.stPMCtoPLC.VG11_Sensor_Value <= 66500;
END_IF
aILK_AV[60] := _w2;

// NETWORK 2
GVL.stPLCtoPMC.P_RUN := GVL.stPMCtoPLC.I103_00;

// NETWORK 3
aILK_AV[68] := aAV[67];

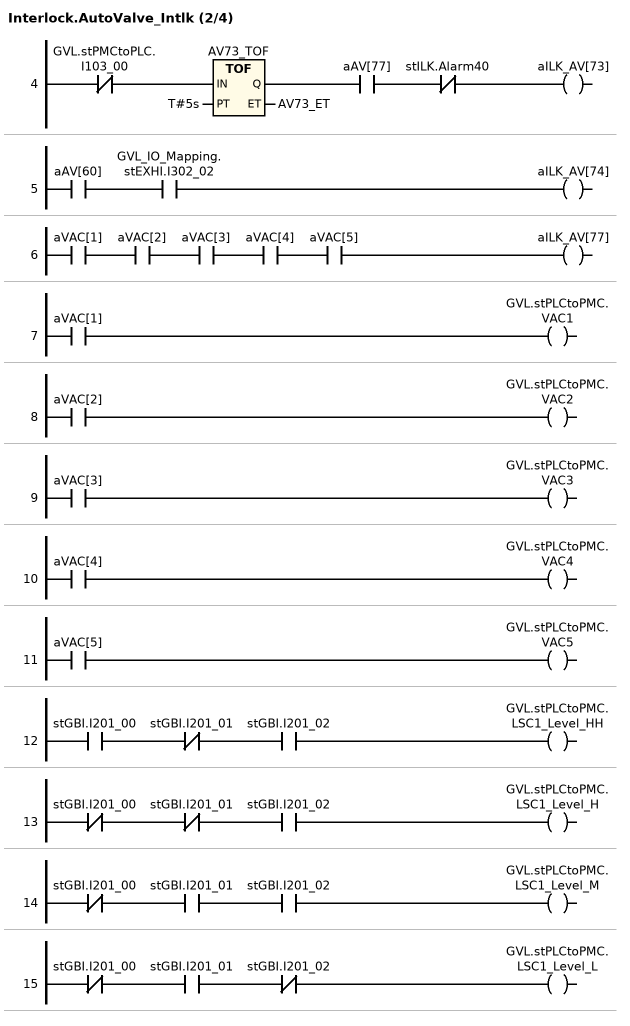
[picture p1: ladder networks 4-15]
// NETWORK 4
AV73_TOF(IN := NOT GVL.stPMCtoPLC.I103_00, PT := T#5s, ET => AV73_ET); // TOF
aILK_AV[73] := AV73_TOF.Q AND aAV[77] AND NOT stILK.Alarm40;

// NETWORK 5
aILK_AV[74] := aAV[60] AND GVL_IO_Mapping.stEXHI.I302_02;

// NETWORK 6
aILK_AV[77] := aVAC[1] AND aVAC[2] AND aVAC[3] AND aVAC[4] AND aVAC[5];

// NETWORK 7
GVL.stPLCtoPMC.VAC1 := aVAC[1];

// NETWORK 8
GVL.stPLCtoPMC.VAC2 := aVAC[2];

// NETWORK 9
GVL.stPLCtoPMC.VAC3 := aVAC[3];

// NETWORK 10
GVL.stPLCtoPMC.VAC4 := aVAC[4];

// NETWORK 11
GVL.stPLCtoPMC.VAC5 := aVAC[5];

// NETWORK 12
GVL.stPLCtoPMC.LSC1_Level_HH := stGBI.I201_00 AND NOT stGBI.I201_01 AND stGBI.I201_02;

// NETWORK 13
GVL.stPLCtoPMC.LSC1_Level_H := NOT stGBI.I201_00 AND NOT stGBI.I201_01 AND stGBI.I201_02;

// NETWORK 14
GVL.stPLCtoPMC.LSC1_Level_M := NOT stGBI.I201_00 AND stGBI.I201_01 AND stGBI.I201_02;

// NETWORK 15
GVL.stPLCtoPMC.LSC1_Level_L := NOT stGBI.I201_00 AND stGBI.I201_01 AND NOT stGBI.I201_02;

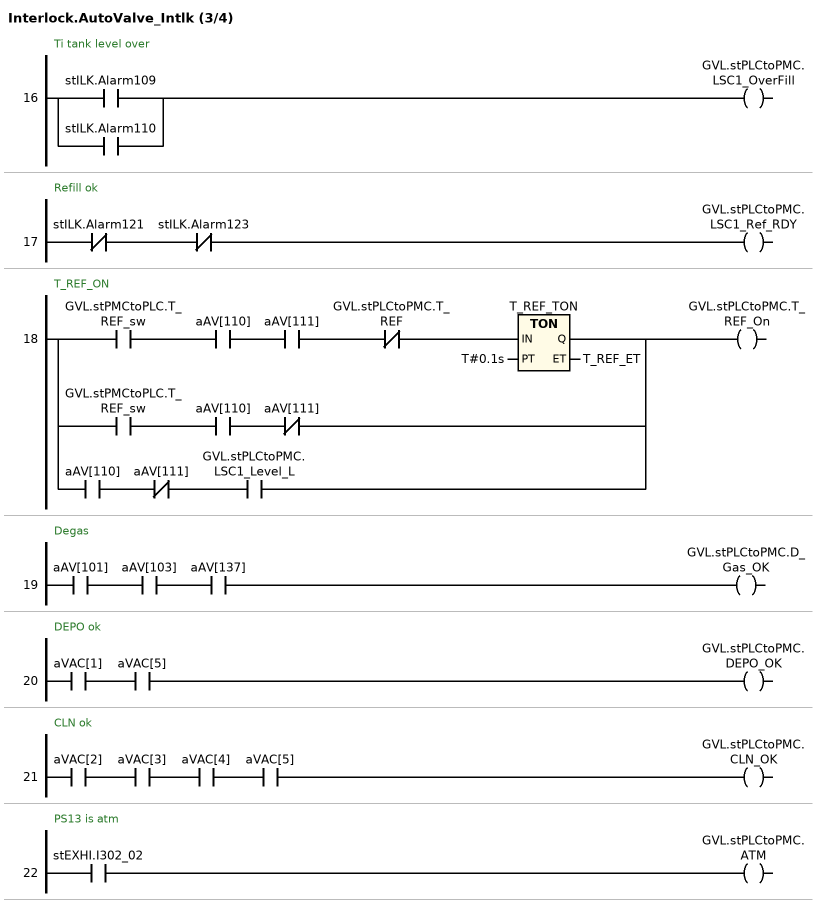
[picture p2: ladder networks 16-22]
// NETWORK 16
// Ti tank level over
GVL.stPLCtoPMC.LSC1_OverFill := stILK.Alarm109 OR stILK.Alarm110;

// NETWORK 17
// Refill ok
GVL.stPLCtoPMC.LSC1_Ref_RDY := NOT stILK.Alarm121 AND NOT stILK.Alarm123;

// NETWORK 18
// T_REF_ON
T_REF_TON(
    IN := GVL.stPMCtoPLC.T_REF_sw AND aAV[110] AND aAV[111] AND NOT GVL.stPLCtoPMC.T_REF,
    PT := T#0.1s,
    ET => T_REF_ET); // TON
GVL.stPLCtoPMC.T_REF_On := T_REF_TON.Q OR GVL.stPMCtoPLC.T_REF_sw AND aAV[110] AND NOT aAV[111] OR aAV[110] AND NOT aAV[111] AND GVL.stPLCtoPMC.LSC1_Level_L;

// NETWORK 19
// Degas
GVL.stPLCtoPMC.D_Gas_OK := aAV[101] AND aAV[103] AND aAV[137];

// NETWORK 20
// DEPO ok
GVL.stPLCtoPMC.DEPO_OK := aVAC[1] AND aVAC[5];

// NETWORK 21
// CLN ok
GVL.stPLCtoPMC.CLN_OK := aVAC[2] AND aVAC[3] AND aVAC[4] AND aVAC[5];

// NETWORK 22
// PS13 is atm
GVL.stPLCtoPMC.ATM := stEXHI.I302_02;

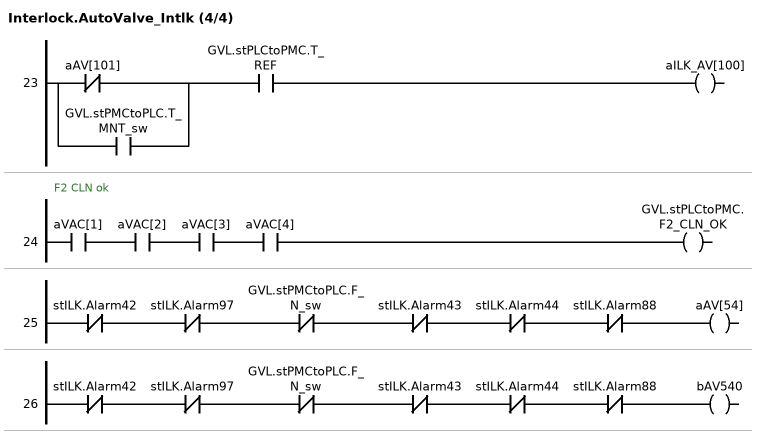
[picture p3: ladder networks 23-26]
// NETWORK 23
aILK_AV[100] := (NOT aAV[101] OR GVL.stPMCtoPLC.T_MNT_sw) AND GVL.stPLCtoPMC.T_REF;

// NETWORK 24
// F2 CLN ok
GVL.stPLCtoPMC.F2_CLN_OK := aVAC[1] AND aVAC[2] AND aVAC[3] AND aVAC[4];

// NETWORK 25
aAV[54] := NOT stILK.Alarm42 AND NOT stILK.Alarm97 AND NOT GVL.stPMCtoPLC.F_N_sw AND NOT stILK.Alarm43 AND NOT stILK.Alarm44 AND NOT stILK.Alarm88;

// NETWORK 26
bAV540 := NOT stILK.Alarm42 AND NOT stILK.Alarm97 AND NOT GVL.stPMCtoPLC.F_N_sw AND NOT stILK.Alarm43 AND NOT stILK.Alarm44 AND NOT stILK.Alarm88;
END_ACTION

ACTION BoatUnload_Intlk:
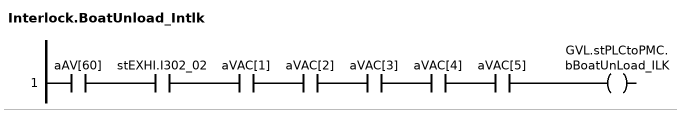
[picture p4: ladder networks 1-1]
// NETWORK 1
GVL.stPLCtoPMC.bBoatUnLoad_ILK := aAV[60] AND stEXHI.I302_02 AND aVAC[1] AND aVAC[2] AND aVAC[3] AND aVAC[4] AND aVAC[5];
END_ACTION

ACTION Intlk:
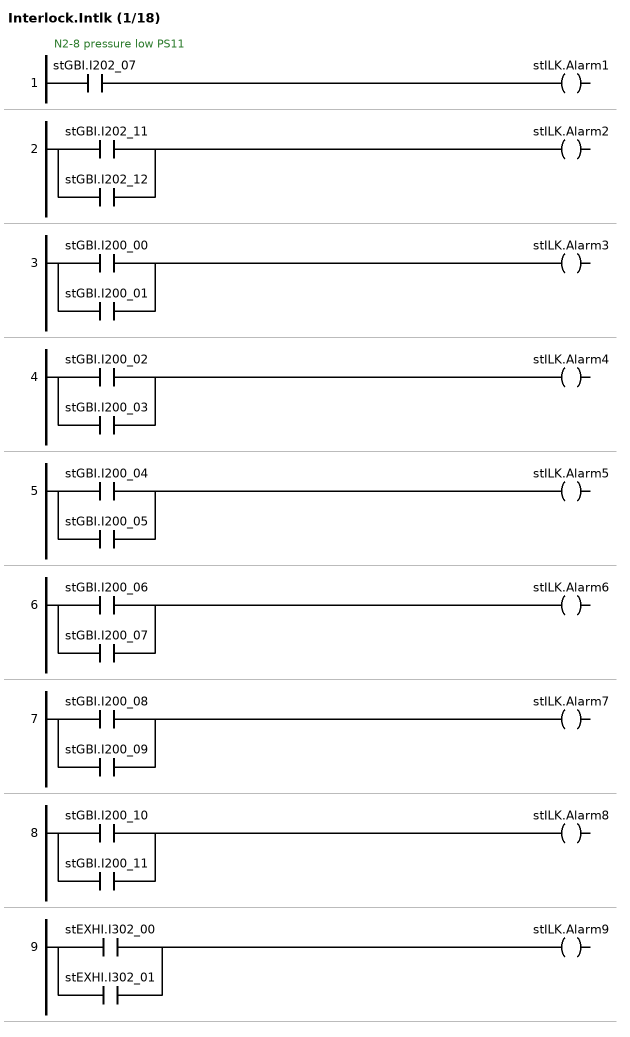
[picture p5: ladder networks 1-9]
// NETWORK 1
// N2-8 pressure low PS11
stILK.Alarm1 := stGBI.I202_07;

// NETWORK 2
stILK.Alarm2 := stGBI.I202_11 OR stGBI.I202_12;

// NETWORK 3
stILK.Alarm3 := stGBI.I200_00 OR stGBI.I200_01;

// NETWORK 4
stILK.Alarm4 := stGBI.I200_02 OR stGBI.I200_03;

// NETWORK 5
stILK.Alarm5 := stGBI.I200_04 OR stGBI.I200_05;

// NETWORK 6
stILK.Alarm6 := stGBI.I200_06 OR stGBI.I200_07;

// NETWORK 7
stILK.Alarm7 := stGBI.I200_08 OR stGBI.I200_09;

// NETWORK 8
stILK.Alarm8 := stGBI.I200_10 OR stGBI.I200_11;

// NETWORK 9
stILK.Alarm9 := stEXHI.I302_00 OR stEXHI.I302_01;

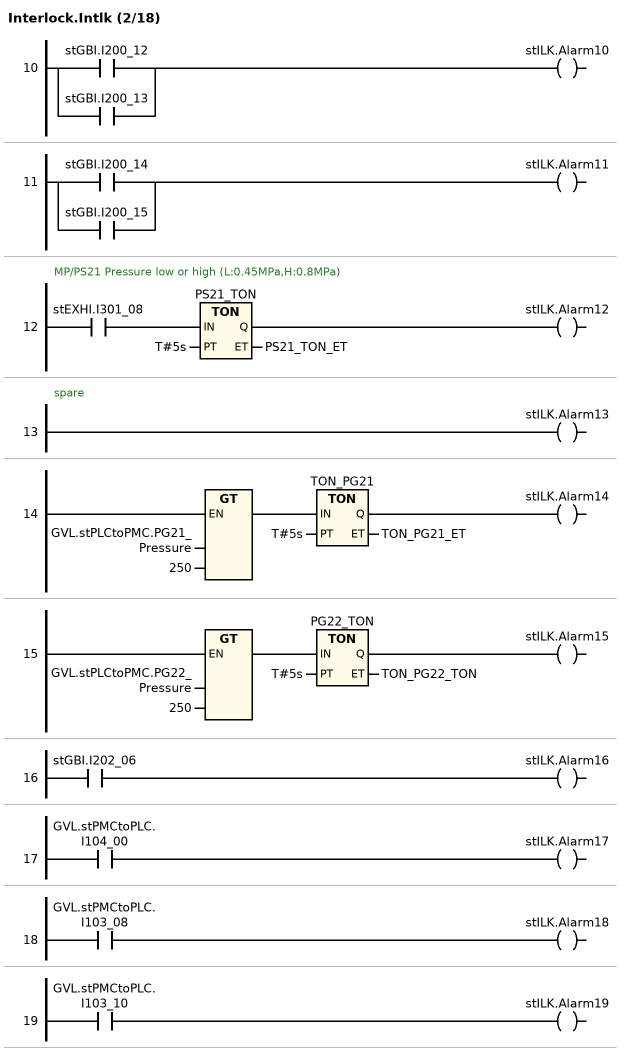
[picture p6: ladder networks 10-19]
// NETWORK 10
stILK.Alarm10 := stGBI.I200_12 OR stGBI.I200_13;

// NETWORK 11
stILK.Alarm11 := stGBI.I200_14 OR stGBI.I200_15;

// NETWORK 12
// MP/PS21 Pressure low or high (L:0.45MPa,H:0.8MPa)
PS21_TON(IN := stEXHI.I301_08, PT := T#5s, ET => PS21_TON_ET); // TON
stILK.Alarm12 := PS21_TON.Q;

// NETWORK 13
// spare
stILK.Alarm13 := TRUE;

// NETWORK 14
TON_PG21(IN := GVL.stPLCtoPMC.PG21_Pressure > 250, PT := T#5s, ET => TON_PG21_ET); // TON
stILK.Alarm14 := TON_PG21.Q;

// NETWORK 15
PG22_TON(IN := GVL.stPLCtoPMC.PG22_Pressure > 250, PT := T#5s, ET => TON_PG22_TON); // TON
stILK.Alarm15 := PG22_TON.Q;

// NETWORK 16
stILK.Alarm16 := stGBI.I202_06;

// NETWORK 17
stILK.Alarm17 := GVL.stPMCtoPLC.I104_00;

// NETWORK 18
stILK.Alarm18 := GVL.stPMCtoPLC.I103_08;

// NETWORK 19
stILK.Alarm19 := GVL.stPMCtoPLC.I103_10;

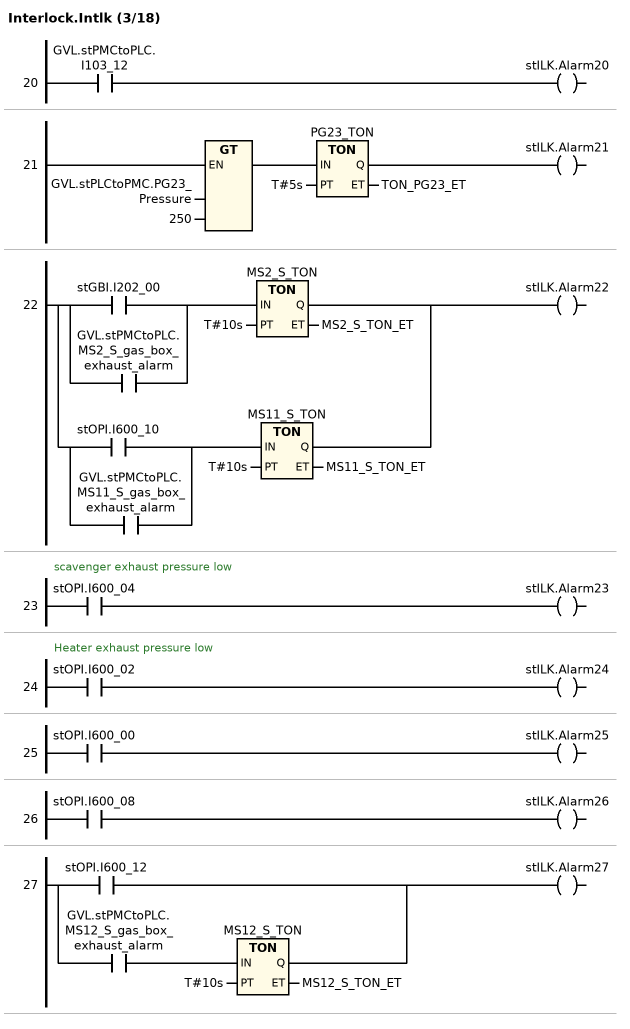
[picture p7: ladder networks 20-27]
// NETWORK 20
stILK.Alarm20 := GVL.stPMCtoPLC.I103_12;

// NETWORK 21
PG23_TON(IN := GVL.stPLCtoPMC.PG23_Pressure > 250, PT := T#5s, ET => TON_PG23_ET); // TON
stILK.Alarm21 := PG23_TON.Q;

// NETWORK 22
MS2_S_TON(IN := stGBI.I202_00 OR GVL.stPMCtoPLC.MS2_S_gas_box_exhaust_alarm, PT := T#10s, ET => MS2_S_TON_ET); // TON
MS11_S_TON(
    IN := stOPI.I600_10 OR GVL.stPMCtoPLC.MS11_S_gas_box_exhaust_alarm,
    PT := T#10s,
    ET => MS11_S_TON_ET); // TON
stILK.Alarm22 := MS2_S_TON.Q OR MS11_S_TON.Q;

// NETWORK 23
// scavenger exhaust pressure low
stILK.Alarm23 := stOPI.I600_04;

// NETWORK 24
// Heater exhaust pressure low
stILK.Alarm24 := stOPI.I600_02;

// NETWORK 25
stILK.Alarm25 := stOPI.I600_00;

// NETWORK 26
stILK.Alarm26 := stOPI.I600_08;

// NETWORK 27
MS12_S_TON(IN := GVL.stPMCtoPLC.MS12_S_gas_box_exhaust_alarm, PT := T#10s, ET => MS12_S_TON_ET); // TON
stILK.Alarm27 := stOPI.I600_12 OR MS12_S_TON.Q;

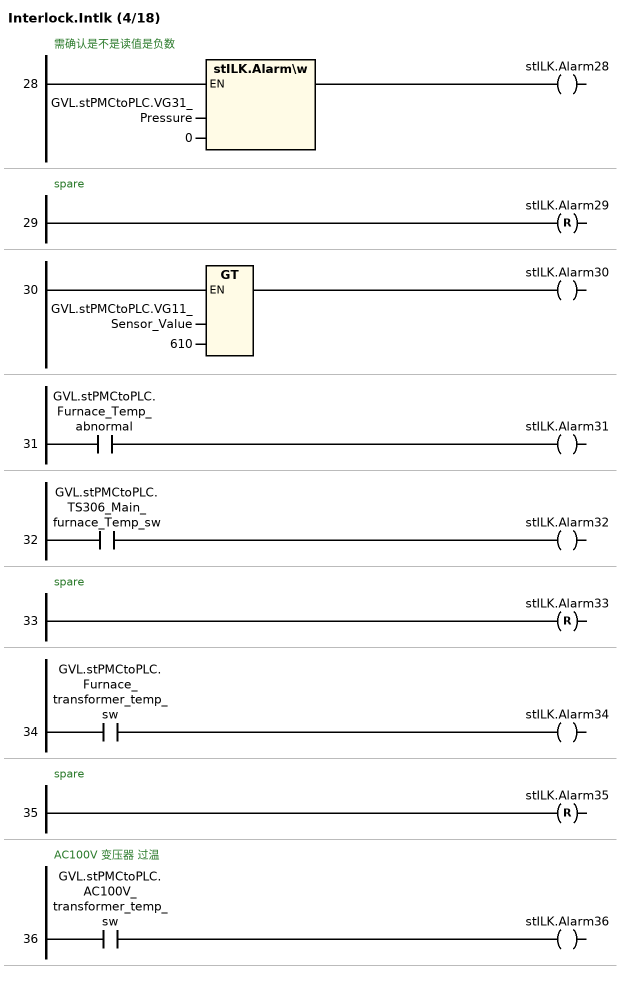
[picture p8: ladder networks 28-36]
// NETWORK 28
// 需确认是不是读值是负数
stILK.Alarm28 := stILK.Alarm\w(GVL.stPMCtoPLC.VG31_Pressure, 0);

// NETWORK 29
// spare
stILK.Alarm29 R= TRUE;

// NETWORK 30
stILK.Alarm30 := GVL.stPMCtoPLC.VG11_Sensor_Value > 610;

// NETWORK 31
stILK.Alarm31 := GVL.stPMCtoPLC.Furnace_Temp_abnormal;

// NETWORK 32
stILK.Alarm32 := GVL.stPMCtoPLC.TS306_Main_furnace_Temp_sw;

// NETWORK 33
// spare
stILK.Alarm33 R= TRUE;

// NETWORK 34
stILK.Alarm34 := GVL.stPMCtoPLC.Furnace_transformer_temp_sw;

// NETWORK 35
// spare
stILK.Alarm35 R= TRUE;

// NETWORK 36
// AC100V 变压器 过温
stILK.Alarm36 := GVL.stPMCtoPLC.AC100V_transformer_temp_sw;

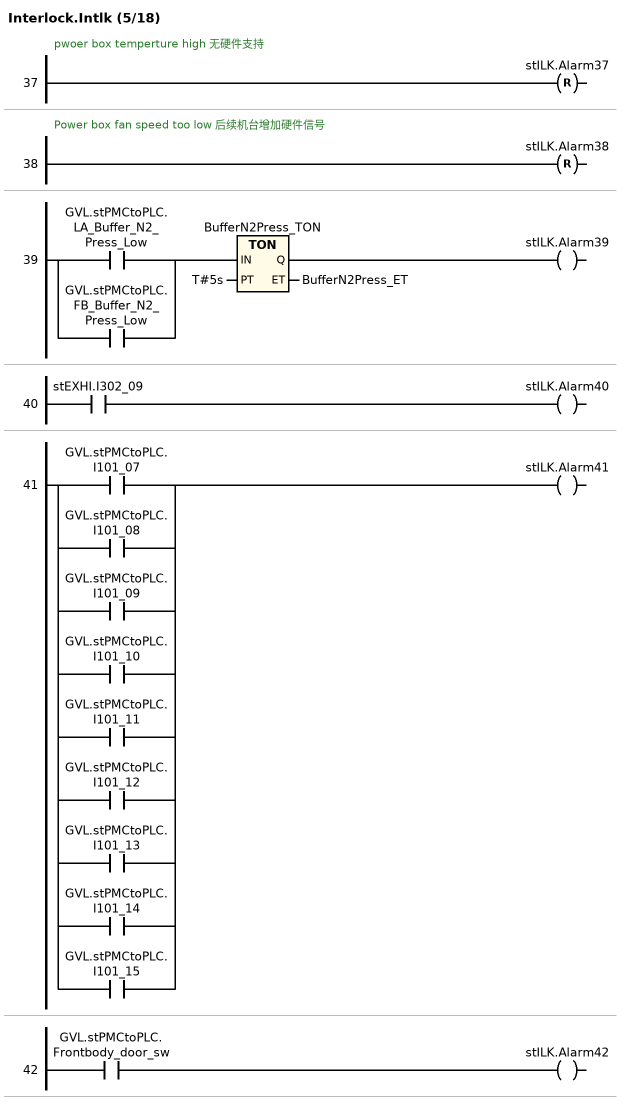
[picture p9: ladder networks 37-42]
// NETWORK 37
// pwoer box temperture high 无硬件支持
stILK.Alarm37 R= TRUE;

// NETWORK 38
// Power box fan speed too low 后续机台增加硬件信号
stILK.Alarm38 R= TRUE;

// NETWORK 39
BufferN2Press_TON(
    IN := GVL.stPMCtoPLC.LA_Buffer_N2_Press_Low OR GVL.stPMCtoPLC.FB_Buffer_N2_Press_Low,
    PT := T#5s,
    ET => BufferN2Press_ET); // TON
stILK.Alarm39 := BufferN2Press_TON.Q;

// NETWORK 40
stILK.Alarm40 := stEXHI.I302_09;

// NETWORK 41
stILK.Alarm41 := GVL.stPMCtoPLC.I101_07 OR GVL.stPMCtoPLC.I101_08 OR GVL.stPMCtoPLC.I101_09 OR GVL.stPMCtoPLC.I101_10 OR GVL.stPMCtoPLC.I101_11 OR GVL.stPMCtoPLC.I101_12 OR GVL.stPMCtoPLC.I101_13 OR GVL.stPMCtoPLC.I101_14 OR GVL.stPMCtoPLC.I101_15;

// NETWORK 42
stILK.Alarm42 := GVL.stPMCtoPLC.Frontbody_door_sw;

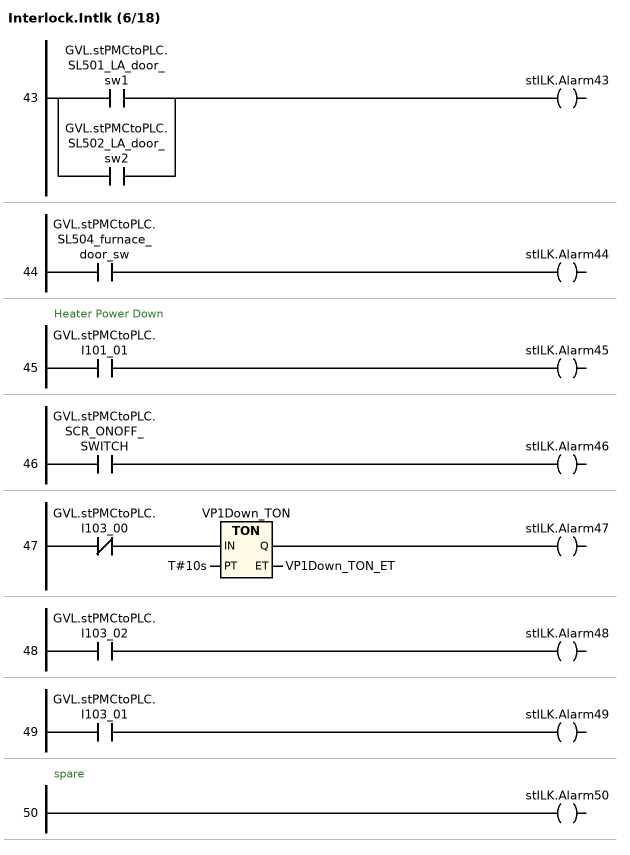
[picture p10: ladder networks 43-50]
// NETWORK 43
stILK.Alarm43 := GVL.stPMCtoPLC.SL501_LA_door_sw1 OR GVL.stPMCtoPLC.SL502_LA_door_sw2;

// NETWORK 44
stILK.Alarm44 := GVL.stPMCtoPLC.SL504_furnace_door_sw;

// NETWORK 45
// Heater Power Down
stILK.Alarm45 := GVL.stPMCtoPLC.I101_01;

// NETWORK 46
stILK.Alarm46 := GVL.stPMCtoPLC.SCR_ONOFF_SWITCH;

// NETWORK 47
VP1Down_TON(IN := NOT GVL.stPMCtoPLC.I103_00, PT := T#10s, ET => VP1Down_TON_ET); // TON
stILK.Alarm47 := VP1Down_TON.Q;

// NETWORK 48
stILK.Alarm48 := GVL.stPMCtoPLC.I103_02;

// NETWORK 49
stILK.Alarm49 := GVL.stPMCtoPLC.I103_01;

// NETWORK 50
// spare
stILK.Alarm50 := TRUE;

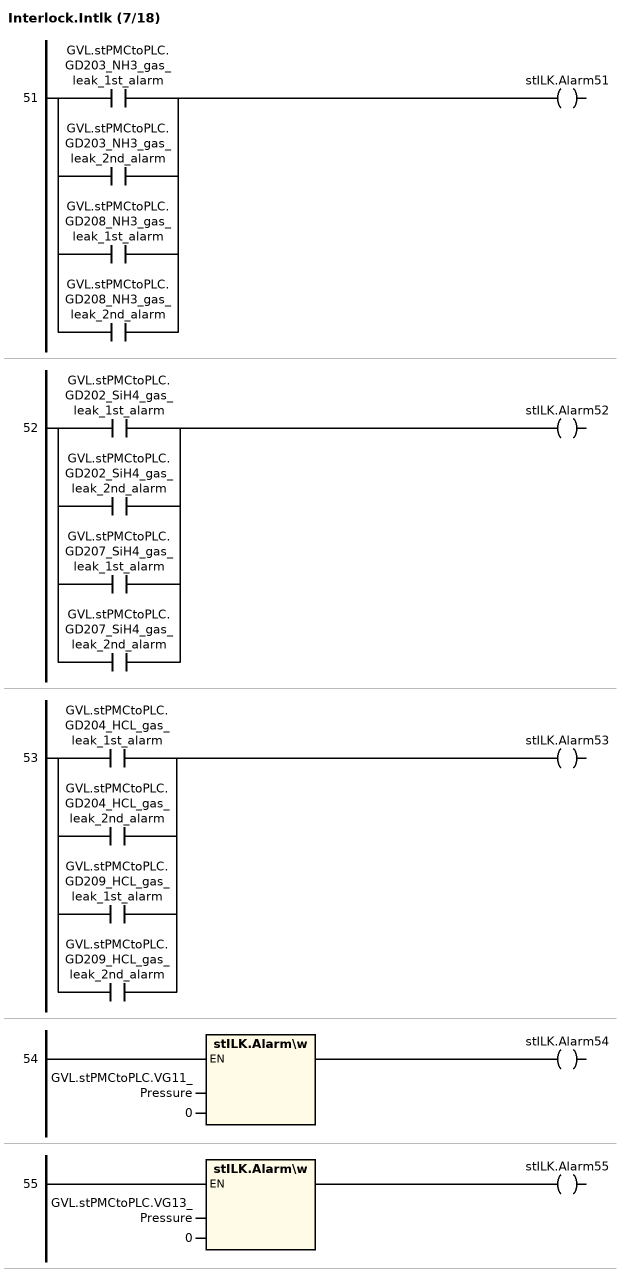
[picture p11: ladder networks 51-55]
// NETWORK 51
stILK.Alarm51 := GVL.stPMCtoPLC.GD203_NH3_gas_leak_1st_alarm OR GVL.stPMCtoPLC.GD203_NH3_gas_leak_2nd_alarm OR GVL.stPMCtoPLC.GD208_NH3_gas_leak_1st_alarm OR GVL.stPMCtoPLC.GD208_NH3_gas_leak_2nd_alarm;

// NETWORK 52
stILK.Alarm52 := GVL.stPMCtoPLC.GD202_SiH4_gas_leak_1st_alarm OR GVL.stPMCtoPLC.GD202_SiH4_gas_leak_2nd_alarm OR GVL.stPMCtoPLC.GD207_SiH4_gas_leak_1st_alarm OR GVL.stPMCtoPLC.GD207_SiH4_gas_leak_2nd_alarm;

// NETWORK 53
stILK.Alarm53 := GVL.stPMCtoPLC.GD204_HCL_gas_leak_1st_alarm OR GVL.stPMCtoPLC.GD204_HCL_gas_leak_2nd_alarm OR GVL.stPMCtoPLC.GD209_HCL_gas_leak_1st_alarm OR GVL.stPMCtoPLC.GD209_HCL_gas_leak_2nd_alarm;

// NETWORK 54
stILK.Alarm54 := stILK.Alarm\w(GVL.stPMCtoPLC.VG11_Pressure, 0);

// NETWORK 55
stILK.Alarm55 := stILK.Alarm\w(GVL.stPMCtoPLC.VG13_Pressure, 0);

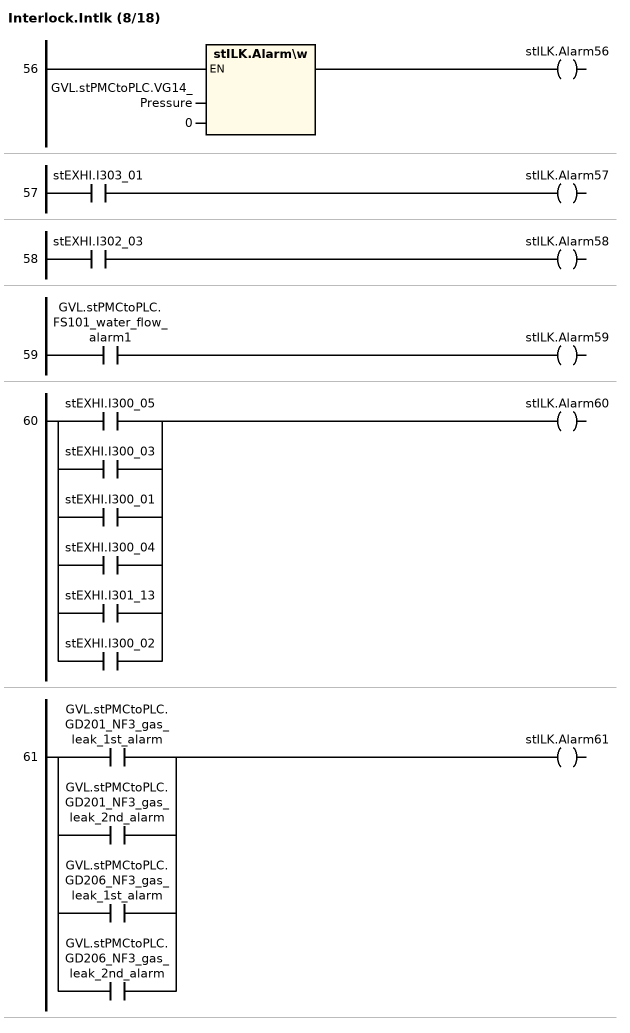
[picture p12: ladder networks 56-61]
// NETWORK 56
stILK.Alarm56 := stILK.Alarm\w(GVL.stPMCtoPLC.VG14_Pressure, 0);

// NETWORK 57
stILK.Alarm57 := stEXHI.I303_01;

// NETWORK 58
stILK.Alarm58 := stEXHI.I302_03;

// NETWORK 59
stILK.Alarm59 := GVL.stPMCtoPLC.FS101_water_flow_alarm1;

// NETWORK 60
stILK.Alarm60 := stEXHI.I300_05 OR stEXHI.I300_03 OR stEXHI.I300_01 OR stEXHI.I300_04 OR stEXHI.I301_13 OR stEXHI.I300_02;

// NETWORK 61
stILK.Alarm61 := GVL.stPMCtoPLC.GD201_NF3_gas_leak_1st_alarm OR GVL.stPMCtoPLC.GD201_NF3_gas_leak_2nd_alarm OR GVL.stPMCtoPLC.GD206_NF3_gas_leak_1st_alarm OR GVL.stPMCtoPLC.GD206_NF3_gas_leak_2nd_alarm;

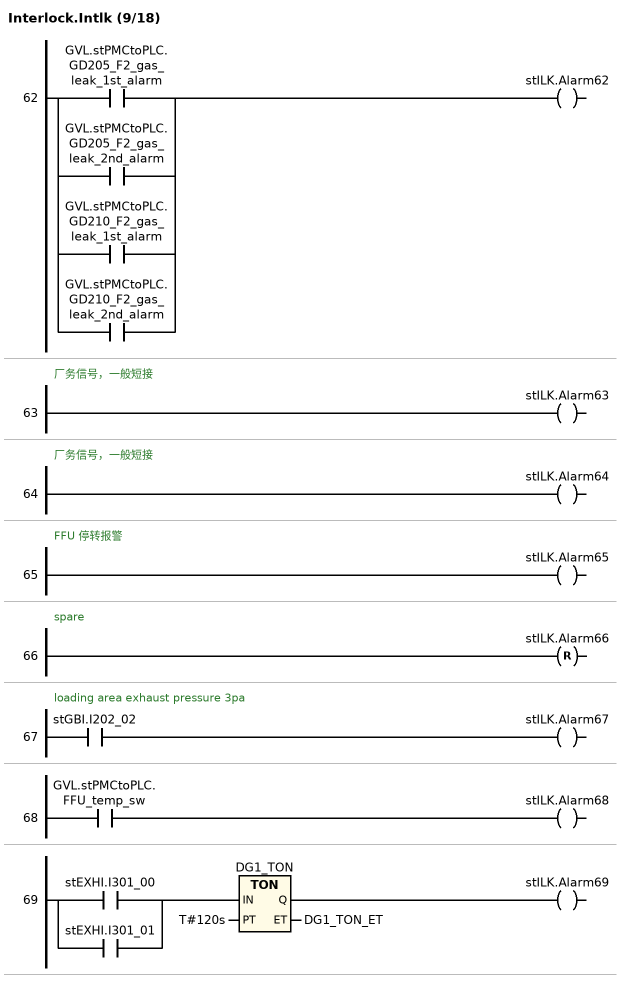
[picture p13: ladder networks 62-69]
// NETWORK 62
stILK.Alarm62 := GVL.stPMCtoPLC.GD205_F2_gas_leak_1st_alarm OR GVL.stPMCtoPLC.GD205_F2_gas_leak_2nd_alarm OR GVL.stPMCtoPLC.GD210_F2_gas_leak_1st_alarm OR GVL.stPMCtoPLC.GD210_F2_gas_leak_2nd_alarm;

// NETWORK 63
// 厂务信号，一般短接
stILK.Alarm63 := TRUE;

// NETWORK 64
// 厂务信号，一般短接
stILK.Alarm64 := TRUE;

// NETWORK 65
// FFU 停转报警
stILK.Alarm65 := TRUE;

// NETWORK 66
// spare
stILK.Alarm66 R= TRUE;

// NETWORK 67
// loading area exhaust pressure 3pa
stILK.Alarm67 := stGBI.I202_02;

// NETWORK 68
stILK.Alarm68 := GVL.stPMCtoPLC.FFU_temp_sw;

// NETWORK 69
DG1_TON(IN := stEXHI.I301_00 OR stEXHI.I301_01, PT := T#120s, ET => DG1_TON_ET); // TON
stILK.Alarm69 := DG1_TON.Q;

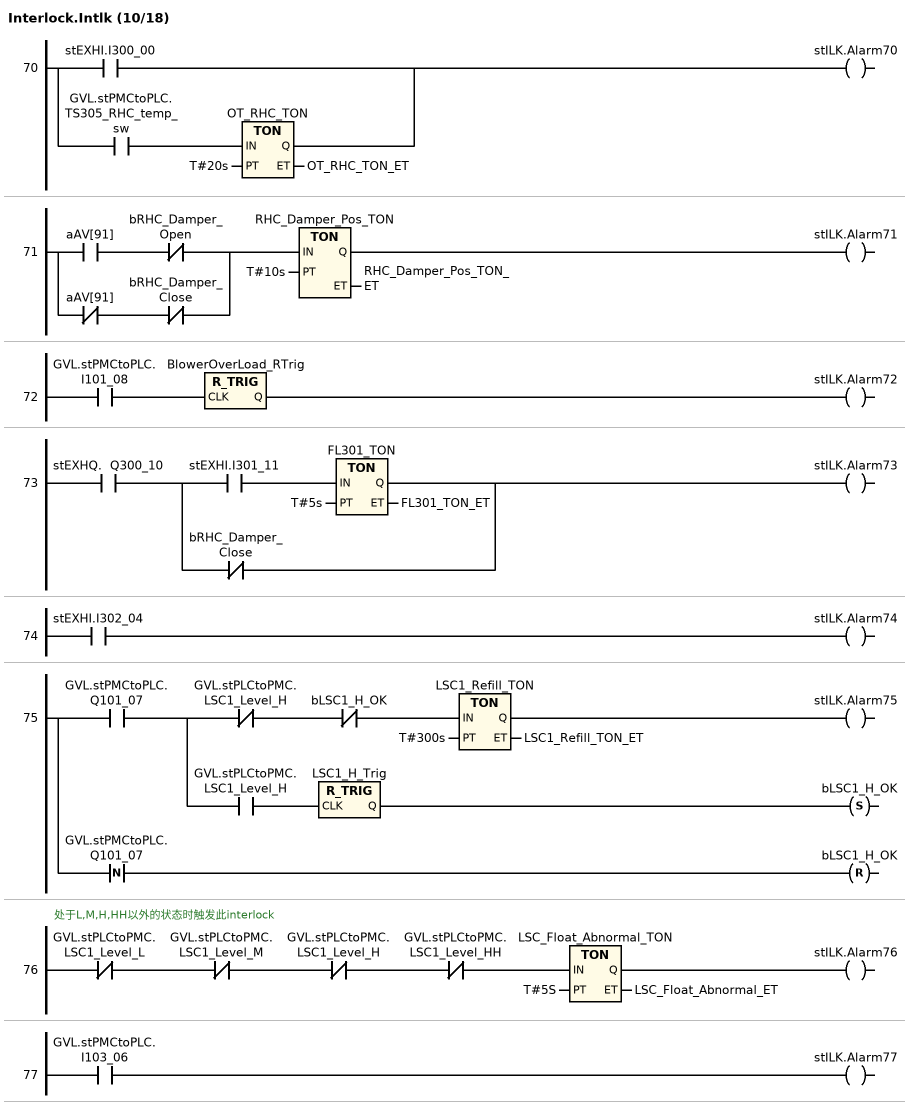
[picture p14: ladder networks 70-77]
// NETWORK 70
OT_RHC_TON(IN := GVL.stPMCtoPLC.TS305_RHC_temp_sw, PT := T#20s, ET => OT_RHC_TON_ET); // TON
stILK.Alarm70 := stEXHI.I300_00 OR OT_RHC_TON.Q;

// NETWORK 71
RHC_Damper_Pos_TON(
    IN := aAV[91] AND NOT bRHC_Damper_Open OR NOT aAV[91] AND NOT bRHC_Damper_Close,
    PT := T#10s,
    ET => RHC_Damper_Pos_TON_ET); // TON
stILK.Alarm71 := RHC_Damper_Pos_TON.Q;

// NETWORK 72
BlowerOverLoad_RTrig(CLK := GVL.stPMCtoPLC.I101_08); // R_TRIG
stILK.Alarm72 := BlowerOverLoad_RTrig.Q;

// NETWORK 73
_w3 := stEXHQ.	Q300_10;
_w4 := _w3 AND NOT bRHC_Damper_Close;
IF NOT _w4 THEN
    FL301_TON(IN := _w3 AND stEXHI.I301_11, PT := T#5s, ET => FL301_TON_ET); // TON
    _w4 := FL301_TON.Q;
END_IF
stILK.Alarm73 := _w4;

// NETWORK 74
stILK.Alarm74 := stEXHI.I302_04;

// NETWORK 75
LSC1_Refill_TON(
    IN := GVL.stPMCtoPLC.Q101_07 AND NOT GVL.stPLCtoPMC.LSC1_Level_H AND NOT bLSC1_H_OK,
    PT := T#300s,
    ET => LSC1_Refill_TON_ET); // TON
stILK.Alarm75 := LSC1_Refill_TON.Q;
LSC1_H_Trig(CLK := GVL.stPMCtoPLC.Q101_07 AND GVL.stPLCtoPMC.LSC1_Level_H); // R_TRIG
bLSC1_H_OK S= LSC1_H_Trig.Q;
_ft1(CLK := GVL.stPMCtoPLC.Q101_07);
bLSC1_H_OK R= _ft1.Q;

// NETWORK 76
// 处于L,M,H,HH以外的状态时触发此interlock
LSC_Float_Abnormal_TON(
    IN := NOT GVL.stPLCtoPMC.LSC1_Level_L AND NOT GVL.stPLCtoPMC.LSC1_Level_M AND NOT GVL.stPLCtoPMC.LSC1_Level_H AND NOT GVL.stPLCtoPMC.LSC1_Level_HH,
    PT := T#5S,
    ET => LSC_Float_Abnormal_ET); // TON
stILK.Alarm76 := LSC_Float_Abnormal_TON.Q;

// NETWORK 77
stILK.Alarm77 := GVL.stPMCtoPLC.I103_06;

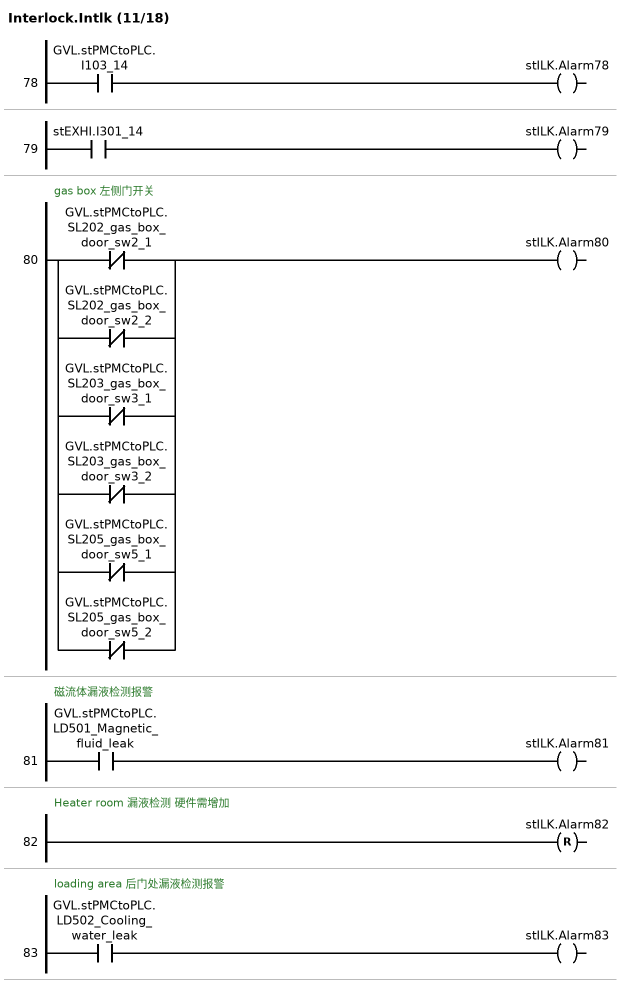
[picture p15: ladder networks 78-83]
// NETWORK 78
stILK.Alarm78 := GVL.stPMCtoPLC.I103_14;

// NETWORK 79
stILK.Alarm79 := stEXHI.I301_14;

// NETWORK 80
// gas box 左侧门开关
stILK.Alarm80 := NOT GVL.stPMCtoPLC.SL202_gas_box_door_sw2_1 OR NOT GVL.stPMCtoPLC.SL202_gas_box_door_sw2_2 OR NOT GVL.stPMCtoPLC.SL203_gas_box_door_sw3_1 OR NOT GVL.stPMCtoPLC.SL203_gas_box_door_sw3_2 OR NOT GVL.stPMCtoPLC.SL205_gas_box_door_sw5_1 OR NOT GVL.stPMCtoPLC.SL205_gas_box_door_sw5_2;

// NETWORK 81
// 磁流体漏液检测报警
stILK.Alarm81 := GVL.stPMCtoPLC.LD501_Magnetic_fluid_leak;

// NETWORK 82
// Heater room 漏液检测 硬件需增加
stILK.Alarm82 R= TRUE;

// NETWORK 83
// loading area 后门处漏液检测报警
stILK.Alarm83 := GVL.stPMCtoPLC.LD502_Cooling_water_leak;

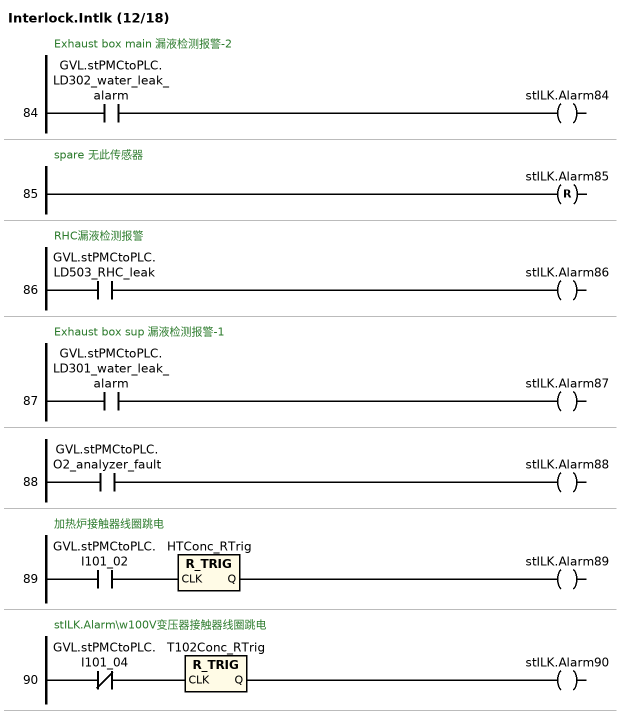
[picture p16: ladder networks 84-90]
// NETWORK 84
// Exhaust box main 漏液检测报警-2
stILK.Alarm84 := GVL.stPMCtoPLC.LD302_water_leak_alarm;

// NETWORK 85
// spare 无此传感器
stILK.Alarm85 R= TRUE;

// NETWORK 86
// RHC漏液检测报警
stILK.Alarm86 := GVL.stPMCtoPLC.LD503_RHC_leak;

// NETWORK 87
// Exhaust box sup 漏液检测报警-1
stILK.Alarm87 := GVL.stPMCtoPLC.LD301_water_leak_alarm;

// NETWORK 88
stILK.Alarm88 := GVL.stPMCtoPLC.O2_analyzer_fault;

// NETWORK 89
// 加热炉接触器线圈跳电
HTConc_RTrig(CLK := GVL.stPMCtoPLC.I101_02); // R_TRIG
stILK.Alarm89 := HTConc_RTrig.Q;

// NETWORK 90
// stILK.Alarm\w100V变压器接触器线圈跳电
T102Conc_RTrig(CLK := NOT GVL.stPMCtoPLC.I101_04); // R_TRIG
stILK.Alarm90 := T102Conc_RTrig.Q;

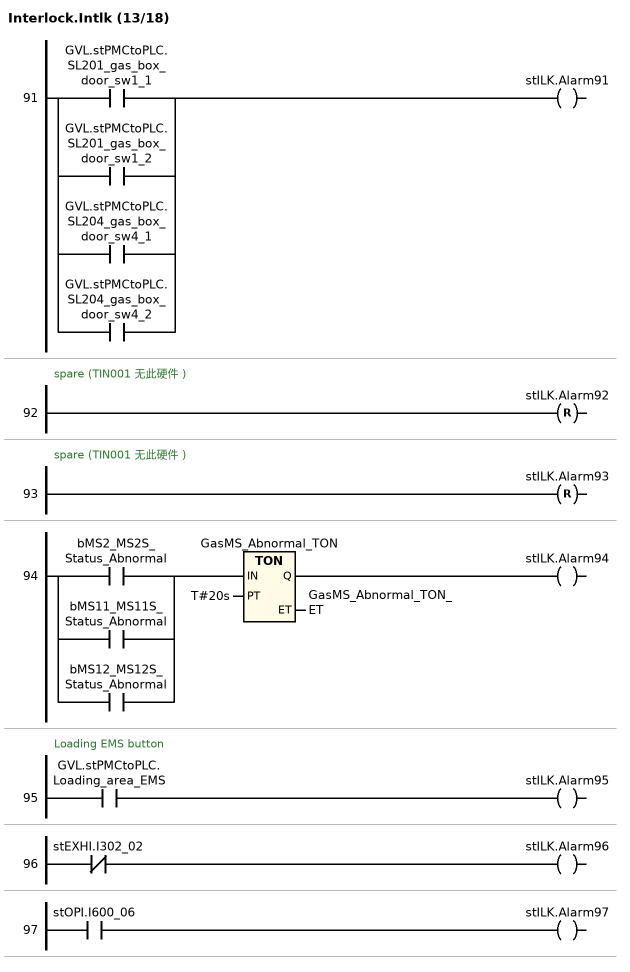
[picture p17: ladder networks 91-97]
// NETWORK 91
stILK.Alarm91 := GVL.stPMCtoPLC.SL201_gas_box_door_sw1_1 OR GVL.stPMCtoPLC.SL201_gas_box_door_sw1_2 OR GVL.stPMCtoPLC.SL204_gas_box_door_sw4_1 OR GVL.stPMCtoPLC.SL204_gas_box_door_sw4_2;

// NETWORK 92
// spare (TIN001 无此硬件 )
stILK.Alarm92 R= TRUE;

// NETWORK 93
// spare (TIN001 无此硬件 )
stILK.Alarm93 R= TRUE;

// NETWORK 94
GasMS_Abnormal_TON(
    IN := bMS2_MS2S_Status_Abnormal OR bMS11_MS11S_Status_Abnormal OR bMS12_MS12S_Status_Abnormal,
    PT := T#20s,
    ET => GasMS_Abnormal_TON_ET); // TON
stILK.Alarm94 := GasMS_Abnormal_TON.Q;

// NETWORK 95
// Loading EMS button
stILK.Alarm95 := GVL.stPMCtoPLC.Loading_area_EMS;

// NETWORK 96
stILK.Alarm96 := NOT stEXHI.I302_02;

// NETWORK 97
stILK.Alarm97 := stOPI.I600_06;

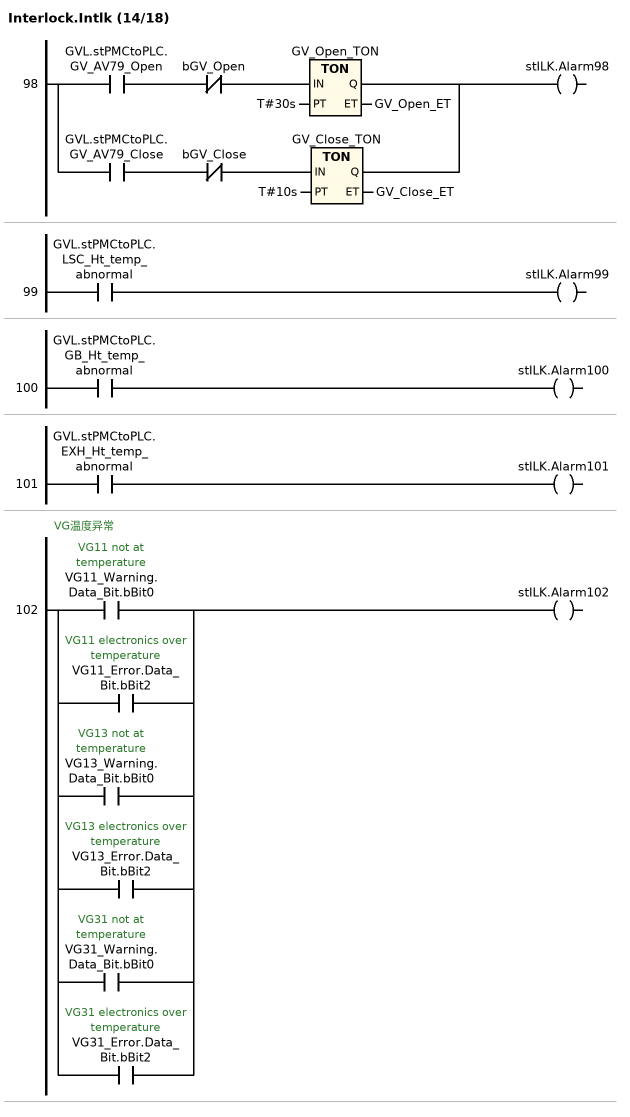
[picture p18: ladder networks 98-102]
// NETWORK 98
GV_Open_TON(IN := GVL.stPMCtoPLC.GV_AV79_Open AND NOT bGV_Open, PT := T#30s, ET => GV_Open_ET); // TON
GV_Close_TON(IN := GVL.stPMCtoPLC.GV_AV79_Close AND NOT bGV_Close, PT := T#10s, ET => GV_Close_ET); // TON
stILK.Alarm98 := GV_Open_TON.Q OR GV_Close_TON.Q;

// NETWORK 99
stILK.Alarm99 := GVL.stPMCtoPLC.LSC_Ht_temp_abnormal;

// NETWORK 100
stILK.Alarm100 := GVL.stPMCtoPLC.GB_Ht_temp_abnormal;

// NETWORK 101
stILK.Alarm101 := GVL.stPMCtoPLC.EXH_Ht_temp_abnormal;

// NETWORK 102
// VG温度异常
//   VG11_Warning.Data_Bit.bBit0: VG11 not at temperature
//   VG11_Error.Data_Bit.bBit2: VG11 electronics over temperature
//   VG13_Warning.Data_Bit.bBit0: VG13 not at temperature
//   VG13_Error.Data_Bit.bBit2: VG13 electronics over temperature
//   VG31_Warning.Data_Bit.bBit0: VG31 not at temperature
//   VG31_Error.Data_Bit.bBit2: VG31 electronics over temperature
stILK.Alarm102 := VG11_Warning.Data_Bit.bBit0 OR VG11_Error.Data_Bit.bBit2 OR VG13_Warning.Data_Bit.bBit0 OR VG13_Error.Data_Bit.bBit2 OR VG31_Warning.Data_Bit.bBit0 OR VG31_Error.Data_Bit.bBit2;

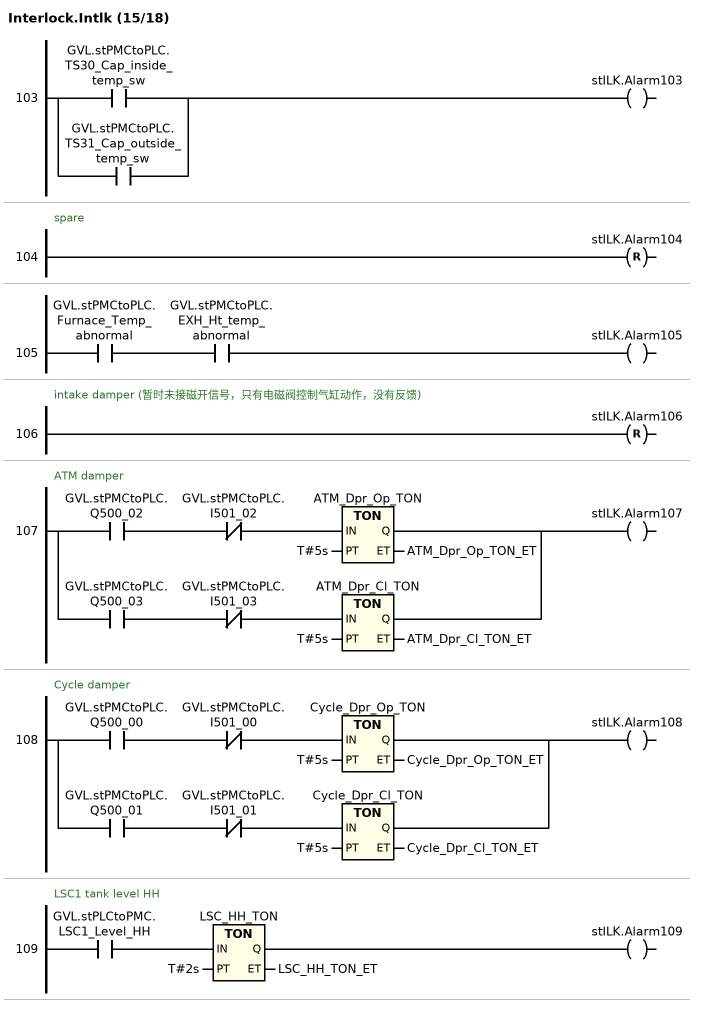
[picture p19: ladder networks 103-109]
// NETWORK 103
stILK.Alarm103 := GVL.stPMCtoPLC.TS30_Cap_inside_temp_sw OR GVL.stPMCtoPLC.TS31_Cap_outside_temp_sw;

// NETWORK 104
// spare
stILK.Alarm104 R= TRUE;

// NETWORK 105
stILK.Alarm105 := GVL.stPMCtoPLC.Furnace_Temp_abnormal AND GVL.stPMCtoPLC.EXH_Ht_temp_abnormal;

// NETWORK 106
// intake damper (暂时未接磁开信号，只有电磁阀控制气缸动作，没有反馈)
stILK.Alarm106 R= TRUE;

// NETWORK 107
// ATM damper
ATM_Dpr_Op_TON(
    IN := GVL.stPMCtoPLC.Q500_02 AND NOT GVL.stPMCtoPLC.I501_02,
    PT := T#5s,
    ET => ATM_Dpr_Op_TON_ET); // TON
ATM_Dpr_Cl_TON(
    IN := GVL.stPMCtoPLC.Q500_03 AND NOT GVL.stPMCtoPLC.I501_03,
    PT := T#5s,
    ET => ATM_Dpr_Cl_TON_ET); // TON
stILK.Alarm107 := ATM_Dpr_Op_TON.Q OR ATM_Dpr_Cl_TON.Q;

// NETWORK 108
// Cycle damper
Cycle_Dpr_Op_TON(
    IN := GVL.stPMCtoPLC.Q500_00 AND NOT GVL.stPMCtoPLC.I501_00,
    PT := T#5s,
    ET => Cycle_Dpr_Op_TON_ET); // TON
Cycle_Dpr_Cl_TON(
    IN := GVL.stPMCtoPLC.Q500_01 AND NOT GVL.stPMCtoPLC.I501_01,
    PT := T#5s,
    ET => Cycle_Dpr_Cl_TON_ET); // TON
stILK.Alarm108 := Cycle_Dpr_Op_TON.Q OR Cycle_Dpr_Cl_TON.Q;

// NETWORK 109
// LSC1 tank level HH
LSC_HH_TON(IN := GVL.stPLCtoPMC.LSC1_Level_HH, PT := T#2s, ET => LSC_HH_TON_ET); // TON
stILK.Alarm109 := LSC_HH_TON.Q;

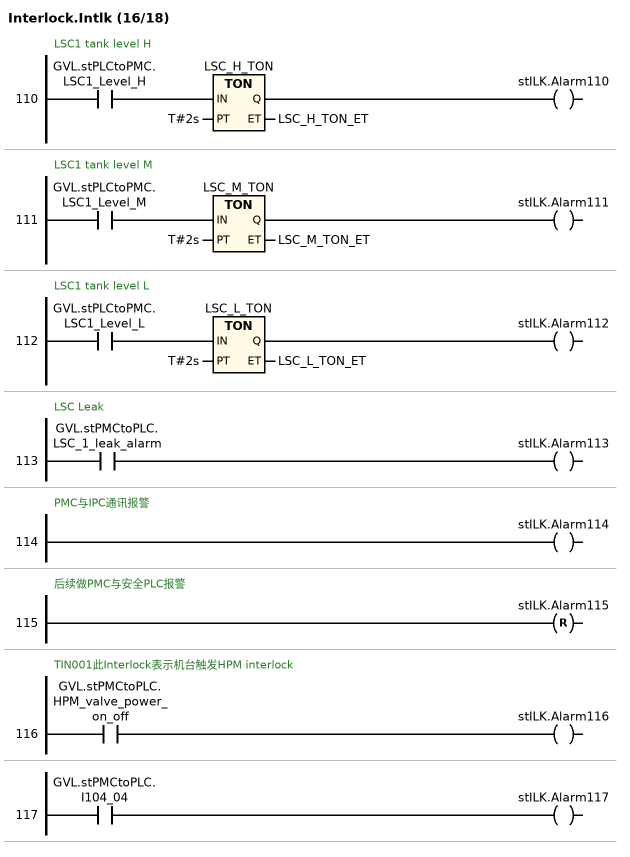
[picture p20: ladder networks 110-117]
// NETWORK 110
// LSC1 tank level H
LSC_H_TON(IN := GVL.stPLCtoPMC.LSC1_Level_H, PT := T#2s, ET => LSC_H_TON_ET); // TON
stILK.Alarm110 := LSC_H_TON.Q;

// NETWORK 111
// LSC1 tank level M
LSC_M_TON(IN := GVL.stPLCtoPMC.LSC1_Level_M, PT := T#2s, ET => LSC_M_TON_ET); // TON
stILK.Alarm111 := LSC_M_TON.Q;

// NETWORK 112
// LSC1 tank level L
LSC_L_TON(IN := GVL.stPLCtoPMC.LSC1_Level_L, PT := T#2s, ET => LSC_L_TON_ET); // TON
stILK.Alarm112 := LSC_L_TON.Q;

// NETWORK 113
// LSC Leak
stILK.Alarm113 := GVL.stPMCtoPLC.LSC_1_leak_alarm;

// NETWORK 114
// PMC与IPC通讯报警
stILK.Alarm114 := TRUE;

// NETWORK 115
// 后续做PMC与安全PLC报警
stILK.Alarm115 R= TRUE;

// NETWORK 116
// TIN001此Interlock表示机台触发HPM interlock
stILK.Alarm116 := GVL.stPMCtoPLC.HPM_valve_power_on_off;

// NETWORK 117
stILK.Alarm117 := GVL.stPMCtoPLC.I104_04;

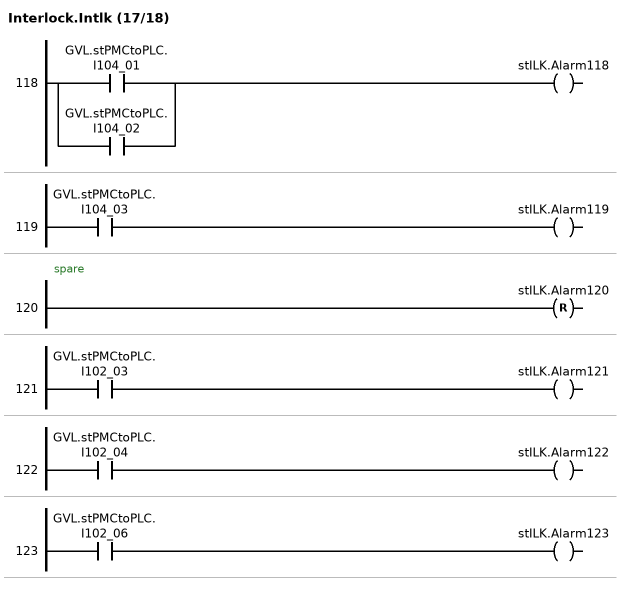
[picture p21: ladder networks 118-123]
// NETWORK 118
stILK.Alarm118 := GVL.stPMCtoPLC.I104_01 OR GVL.stPMCtoPLC.I104_02;

// NETWORK 119
stILK.Alarm119 := GVL.stPMCtoPLC.I104_03;

// NETWORK 120
// spare
stILK.Alarm120 R= TRUE;

// NETWORK 121
stILK.Alarm121 := GVL.stPMCtoPLC.I102_03;

// NETWORK 122
stILK.Alarm122 := GVL.stPMCtoPLC.I102_04;

// NETWORK 123
stILK.Alarm123 := GVL.stPMCtoPLC.I102_06;

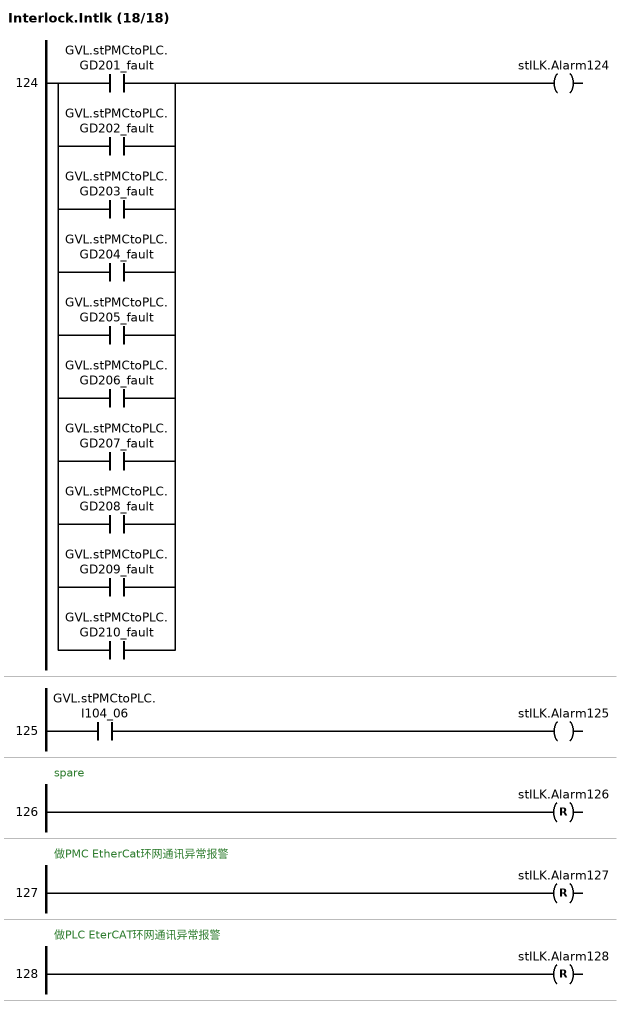
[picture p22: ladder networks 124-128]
// NETWORK 124
stILK.Alarm124 := GVL.stPMCtoPLC.GD201_fault OR GVL.stPMCtoPLC.GD202_fault OR GVL.stPMCtoPLC.GD203_fault OR GVL.stPMCtoPLC.GD204_fault OR GVL.stPMCtoPLC.GD205_fault OR GVL.stPMCtoPLC.GD206_fault OR GVL.stPMCtoPLC.GD207_fault OR GVL.stPMCtoPLC.GD208_fault OR GVL.stPMCtoPLC.GD209_fault OR GVL.stPMCtoPLC.GD210_fault;

// NETWORK 125
stILK.Alarm125 := GVL.stPMCtoPLC.I104_06;

// NETWORK 126
// spare
stILK.Alarm126 R= TRUE;

// NETWORK 127
// 做PMC EtherCat环网通讯异常报警
stILK.Alarm127 R= TRUE;

// NETWORK 128
// 做PLC EterCAT环网通讯异常报警
stILK.Alarm128 R= TRUE;
END_ACTION

ACTION VAC_Condition:
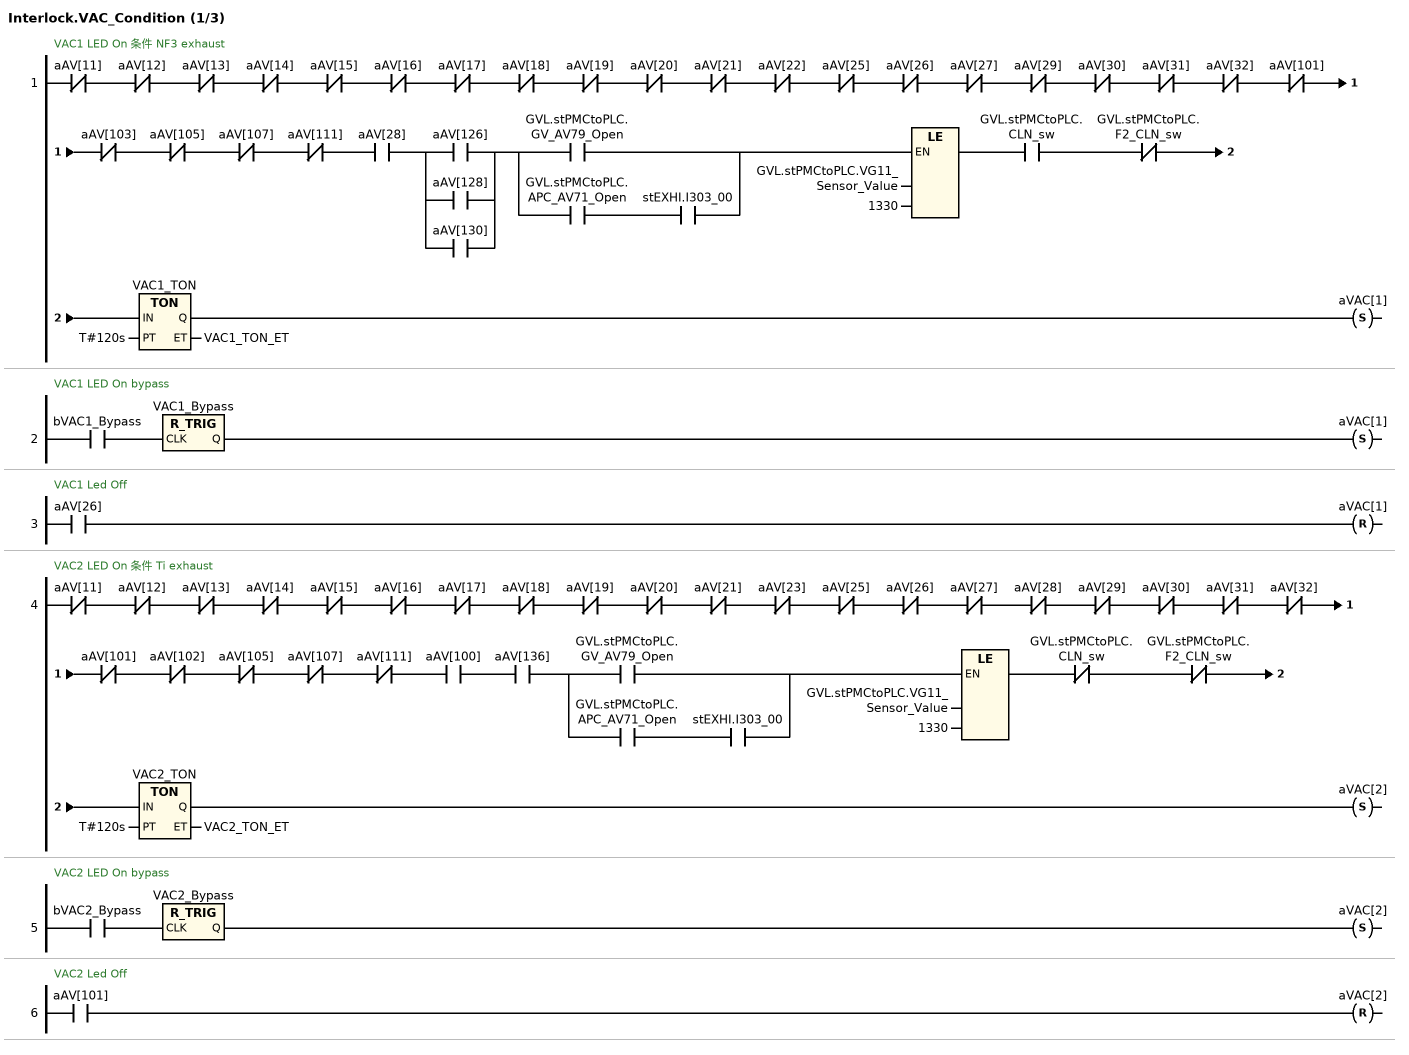
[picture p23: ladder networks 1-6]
// NETWORK 1
// VAC1 LED On 条件 NF3 exhaust
VAC1_TON(
    IN := (NOT aAV[11] AND NOT aAV[12] AND NOT aAV[13] AND NOT aAV[14] AND NOT aAV[15] AND NOT aAV[16] AND NOT aAV[17] AND NOT aAV[18] AND NOT aAV[19] AND NOT aAV[20] AND NOT aAV[21] AND NOT aAV[22] AND NOT aAV[25] AND NOT aAV[26] AND NOT aAV[27] AND NOT aAV[29] AND NOT aAV[30] AND NOT aAV[31] AND NOT aAV[32] AND NOT aAV[101] AND NOT aAV[103] AND NOT aAV[105] AND NOT aAV[107] AND NOT aAV[111] AND aAV[28] AND (aAV[126] OR aAV[128] OR aAV[130]) AND (GVL.stPMCtoPLC.GV_AV79_Open OR GVL.stPMCtoPLC.APC_AV71_Open AND stEXHI.I303_00) AND GVL.stPMCtoPLC.VG11_Sensor_Value <= 1330) AND GVL.stPMCtoPLC.CLN_sw AND NOT GVL.stPMCtoPLC.F2_CLN_sw,
    PT := T#120s,
    ET => VAC1_TON_ET); // TON
aVAC[1] S= VAC1_TON.Q;

// NETWORK 2
// VAC1 LED On bypass
VAC1_Bypass(CLK := bVAC1_Bypass); // R_TRIG
aVAC[1] S= VAC1_Bypass.Q;

// NETWORK 3
// VAC1 Led Off
aVAC[1] R= aAV[26];

// NETWORK 4
// VAC2 LED On 条件 Ti exhaust
VAC2_TON(
    IN := (NOT aAV[11] AND NOT aAV[12] AND NOT aAV[13] AND NOT aAV[14] AND NOT aAV[15] AND NOT aAV[16] AND NOT aAV[17] AND NOT aAV[18] AND NOT aAV[19] AND NOT aAV[20] AND NOT aAV[21] AND NOT aAV[23] AND NOT aAV[25] AND NOT aAV[26] AND NOT aAV[27] AND NOT aAV[28] AND NOT aAV[29] AND NOT aAV[30] AND NOT aAV[31] AND NOT aAV[32] AND NOT aAV[101] AND NOT aAV[102] AND NOT aAV[105] AND NOT aAV[107] AND NOT aAV[111] AND aAV[100] AND aAV[136] AND (GVL.stPMCtoPLC.GV_AV79_Open OR GVL.stPMCtoPLC.APC_AV71_Open AND stEXHI.I303_00) AND GVL.stPMCtoPLC.VG11_Sensor_Value <= 1330) AND NOT GVL.stPMCtoPLC.CLN_sw AND NOT GVL.stPMCtoPLC.F2_CLN_sw,
    PT := T#120s,
    ET => VAC2_TON_ET); // TON
aVAC[2] S= VAC2_TON.Q;

// NETWORK 5
// VAC2 LED On bypass
VAC2_Bypass(CLK := bVAC2_Bypass); // R_TRIG
aVAC[2] S= VAC2_Bypass.Q;

// NETWORK 6
// VAC2 Led Off
aVAC[2] R= aAV[101];

// NETWORK 7
// VAC3 LED On 条件 NH3 exhaust
VAC3_TON(
    IN := (NOT aAV[11] AND NOT aAV[12] AND NOT aAV[13] AND NOT aAV[15] AND NOT aAV[16] AND NOT aAV[17] AND NOT aAV[19] AND NOT aAV[20] AND NOT aAV[21] AND NOT aAV[22] AND NOT aAV[25] AND NOT aAV[26] AND NOT aAV[27] AND NOT aAV[29] AND NOT aAV[30] AND NOT aAV[31] AND NOT aAV[32] AND NOT aAV[101] AND NOT aAV[103] AND NOT aAV[105] AND NOT aAV[107] AND NOT aAV[111] AND aAV[14] AND aAV[120] AND aAV[121] AND aAV[124] AND (aAV[118] OR aAV[122] OR aAV[123] OR aAV[124]) AND (GVL.stPMCtoPLC.GV_AV79_Open OR GVL.stPMCtoPLC.APC_AV71_Open AND stEXHI.I303_00) AND GVL.stPMCtoPLC.VG11_Sensor_Value <= 1330) AND NOT GVL.stPMCtoPLC.CLN_sw AND NOT GVL.stPMCtoPLC.F2_CLN_sw,
    PT := T#120s,
    ET => VAC3_TON_ET); // TON
aVAC[3] S= VAC3_TON.Q;

// NETWORK 8
// VAC3 LED On bypass
VAC3_Bypass(CLK := bVAC3_Bypass); // R_TRIG
aVAC[3] S= VAC3_Bypass.Q;

// NETWORK 9
// VAC3 Led Off
aVAC[3] R= aAV[12] AND aAV[16];

// NETWORK 10
// VAC4 LED On 条件 SiH4 exhaust
VAC4_TON(
    IN := (NOT aAV[11] AND NOT aAV[12] AND NOT aAV[13] AND NOT aAV[14] AND NOT aAV[15] AND NOT aAV[16] AND NOT aAV[17] AND NOT aAV[18] AND NOT aAV[19] AND NOT aAV[20] AND NOT aAV[21] AND NOT aAV[25] AND NOT aAV[26] AND NOT aAV[27] AND NOT aAV[28] AND NOT aAV[29] AND NOT aAV[30] AND NOT aAV[31] AND NOT aAV[32] AND NOT aAV[101] AND NOT aAV[103] AND NOT aAV[105] AND NOT aAV[107] AND NOT aAV[111] AND aAV[22] AND aAV[131] AND (GVL.stPMCtoPLC.GV_AV79_Open OR GVL.stPMCtoPLC.APC_AV71_Open AND stEXHI.I303_00) AND GVL.stPMCtoPLC.VG11_Sensor_Value <= 1330) AND NOT GVL.stPMCtoPLC.CLN_sw AND NOT GVL.stPMCtoPLC.F2_CLN_sw,
    PT := T#120s,
    ET => VAC4_TON_ET); // TON
aVAC[4] S= VAC4_TON.Q;

// NETWORK 11
// VAC4 LED On bypass
VAC4_Bypass(CLK := bVAC4_Bypass); // R_TRIG
aVAC[4] S= VAC4_Bypass.Q;

// NETWORK 12
// VAC4 Led Off
aVAC[4] R= aAV[20];

// NETWORK 13
// VAC5 LED On 条件 F2 exhaust
VAC5_TON(
    IN := (NOT aAV[11] AND NOT aAV[12] AND NOT aAV[13] AND NOT aAV[14] AND NOT aAV[15] AND NOT aAV[16] AND NOT aAV[17] AND NOT aAV[18] AND NOT aAV[19] AND NOT aAV[20] AND NOT aAV[21] AND NOT aAV[22] AND NOT aAV[25] AND NOT aAV[26] AND NOT aAV[27] AND NOT aAV[28] AND NOT aAV[29] AND NOT aAV[30] AND NOT aAV[31] AND NOT aAV[101] AND NOT aAV[103] AND NOT aAV[105] AND NOT aAV[107] AND NOT aAV[111] AND aAV[32] AND (aAV[126] OR aAV[128] OR aAV[130]) AND (GVL.stPMCtoPLC.GV_AV79_Open OR GVL.stPMCtoPLC.APC_AV71_Open AND stEXHI.I303_00) AND GVL.stPMCtoPLC.VG11_Sensor_Value <= 1330) AND NOT GVL.stPMCtoPLC.CLN_sw AND GVL.stPMCtoPLC.F2_CLN_sw,
    PT := T#120s,
    ET => VAC5_TON_ET); // TON
aVAC[5] S= VAC5_TON.Q;

// NETWORK 14
// VAC5 LED On bypass
VAC5_Bypass(CLK := bVAC5_Bypass); // R_TRIG
aVAC[5] S= VAC5_Bypass.Q;

// NETWORK 15
// VAC5 Led Off
aVAC[5] R= aAV[30];
END_ACTION

ACTION Valve_Intlk:
// NETWORK 1
aILK_AV[1] := TRUE;

// NETWORK 2
// TIN001没有AV2
aILK_AV[2] := TRUE;

// NETWORK 3
aILK_AV[3] := (aAV[120] AND aAV[121] AND aAV[124] OR NOT aAV[14]) AND GVL.stPMCtoPLC.VG11_Sensor_Value <= 108000;

// NETWORK 4
aILK_AV[4] := aAV[125] AND GVL.stPMCtoPLC.VG11_Sensor_Value <= 108000;

// NETWORK 5
aILK_AV[5] := aAV[127] AND GVL.stPMCtoPLC.VG11_Sensor_Value <= 108000;

// NETWORK 6
aILK_AV[6] := aAV[129] AND GVL.stPMCtoPLC.VG11_Sensor_Value <= 108000;

// NETWORK 7
aILK_AV[7] := (aAV[122] AND aAV[123] AND aAV[124] OR NOT aAV[18]) AND GVL.stPMCtoPLC.VG11_Sensor_Value <= 108000;

// NETWORK 8
aILK_AV[8] := aAV[52] AND GVL.stPMCtoPLC.VG11_Sensor_Value <= 108000;

// NETWORK 9
aILK_AV[9] := (aAV[131] OR NOT aAV[22]) AND GVL.stPMCtoPLC.VG11_Sensor_Value <= 108000;

// NETWORK 10
// TIN001 没有AV10
aILK_AV[10] := TRUE;

// NETWORK 11
aILK_AV[11] := NOT aAV[12];

// NETWORK 12
aILK_AV[12] := (((NOT aAV[11] AND NOT aAV[17] AND NOT aAV[21] AND NOT aAV[26] AND NOT aAV[30] AND GVL.stPLCtoPMC.PG22_Pressure <= 150) AND GVL.stPMCtoPLC.I103_00 AND GVL.stPMCtoPLC.AGV_SW AND GVL.stPMCtoPLC.VG11_Sensor_Value < 1995) AND GVL.stPMCtoPLC.Boat_at_cap_position AND GVL.stPMCtoPLC.VG11_Sensor_Value <= 5320) AND GVL.stPMCtoPLC.HTR1_SW AND GVL.stPMCtoPLC.HTR2_SW AND GVL.stPMCtoPLC.HTR3_SW AND GVL.stPMCtoPLC.HTR4_SW AND GVL.stPMCtoPLC.HTR5_SW AND GVL.stPMCtoPLC.DEPO_SW AND NOT GVL.stPMCtoPLC.CLN_SW AND NOT GVL.stPMCtoPLC.F2_CLN_SW AND GVL.stPLCtoPMC.DEPO_OK AND aVAC[1] AND aVAC[5] AND GVL.stPMCtoPLC.HPM_valve_power_on_off AND NOT stILK.Alarm22 AND NOT stILK.Alarm27 AND NOT stILK.Alarm51 AND NOT stILK.Alarm52 AND NOT stILK.Alarm53 AND NOT stILK.Alarm61 AND NOT stILK.Alarm62 AND NOT stILK.Alarm80 AND NOT stILK.Alarm91 AND NOT stILK.Alarm109 AND NOT stILK.Alarm113 AND NOT stILK.Alarm116 AND NOT stILK.Alarm117;

// NETWORK 13
aILK_AV[13] := NOT aAV[14] AND NOT aAV[16] AND NOT aAV[20] AND GVL.stPMCtoPLC.I103_00 AND GVL.stPMCtoPLC.AGV_SW;

// NETWORK 14
_w5 := NOT aAV[13];
aILK_AV[14] := ((_w5 AND aAV[120]) AND aAV[121] AND aAV[124] OR _w5 AND NOT aAV[3]) AND GVL.stPMCtoPLC.VG11_Sensor_Value <= 1999.8;

// NETWORK 15
aILK_AV[15] := NOT aAV[16];

// NETWORK 16
_w6 := (NOT aAV[13] AND NOT aAV[15] AND NOT aAV[21] AND NOT aAV[26] AND NOT aAV[30] AND GVL.stPLCtoPMC.PG23_Pressure <= 150) AND GVL.stPMCtoPLC.I103_00 AND GVL.stPMCtoPLC.AGV_SW AND GVL.stPMCtoPLC.VG11_Sensor_Value < 1995;
aILK_AV[16] := (_w6 AND GVL.stPMCtoPLC.I501_07 AND GVL.stPMCtoPLC.VG11_Sensor_Value <= 5320 OR _w6 AND GVL.stPMCtoPLC.Boat_at_cap_position AND GVL.stPMCtoPLC.VG11_Sensor_Value <= 5320) AND GVL.stPMCtoPLC.HTR1_SW AND GVL.stPMCtoPLC.HTR2_SW AND GVL.stPMCtoPLC.HTR3_SW AND GVL.stPMCtoPLC.HTR4_SW AND GVL.stPMCtoPLC.HTR5_SW AND GVL.stPMCtoPLC.DEPO_SW AND NOT GVL.stPMCtoPLC.CLN_SW AND NOT GVL.stPMCtoPLC.F2_CLN_SW AND GVL.stPLCtoPMC.DEPO_OK AND aVAC[1] AND aVAC[5] AND GVL.stPMCtoPLC.HPM_valve_power_on_off AND NOT stILK.Alarm22 AND NOT stILK.Alarm27 AND NOT stILK.Alarm51 AND NOT stILK.Alarm52 AND NOT stILK.Alarm53 AND NOT stILK.Alarm61 AND NOT stILK.Alarm62 AND NOT stILK.Alarm80 AND NOT stILK.Alarm91 AND NOT stILK.Alarm109 AND NOT stILK.Alarm113 AND NOT stILK.Alarm116 AND NOT stILK.Alarm117;

// NETWORK 17
aILK_AV[17] := NOT aAV[12] AND NOT aAV[18] AND NOT aAV[20] AND GVL.stPMCtoPLC.I103_00 AND GVL.stPMCtoPLC.AGV_SW;

// NETWORK 18
_w7 := NOT aAV[17];
aILK_AV[18] := ((_w7 AND aAV[122]) AND aAV[123] AND aAV[124] OR _w7 AND NOT aAV[7]) AND GVL.stPMCtoPLC.VG11_Sensor_Value <= 1999.8;

// NETWORK 19
aILK_AV[19] := NOT aAV[20];

// NETWORK 20
_w8 := NOT aAV[13] AND NOT aAV[17] AND NOT aAV[19] AND NOT aAV[26] AND NOT aAV[30];
_w9 := _w8 AND GVL.stPMCtoPLC.VG11_Sensor_Value < 1330 OR _w8 AND aAV[75] AND GVL.stPMCtoPLC.VG13_Sensor_Value <= 1330;
aILK_AV[20] := (_w9 AND GVL.stPMCtoPLC.I501_07 AND GVL.stPMCtoPLC.VG11_Sensor_Value <= 5320 OR _w9 AND GVL.stPMCtoPLC.Boat_at_cap_position AND GVL.stPMCtoPLC.VG11_Sensor_Value <= 5320) AND GVL.stPMCtoPLC.I103_00 AND GVL.stPMCtoPLC.AGV_SW AND GVL.stPMCtoPLC.HTR1_SW AND GVL.stPMCtoPLC.HTR2_SW AND GVL.stPMCtoPLC.HTR3_SW AND GVL.stPMCtoPLC.HTR4_SW AND GVL.stPMCtoPLC.HTR5_SW AND GVL.stPMCtoPLC.DEPO_SW AND NOT GVL.stPMCtoPLC.CLN_SW AND NOT GVL.stPMCtoPLC.F2_CLN_SW AND GVL.stPLCtoPMC.DEPO_OK AND aVAC[1] AND aVAC[5] AND GVL.stPMCtoPLC.HPM_valve_power_on_off AND NOT stILK.Alarm22 AND NOT stILK.Alarm27 AND NOT stILK.Alarm51 AND NOT stILK.Alarm52 AND NOT stILK.Alarm53 AND NOT stILK.Alarm61 AND NOT stILK.Alarm62 AND NOT stILK.Alarm80 AND NOT stILK.Alarm91 AND NOT stILK.Alarm109 AND NOT stILK.Alarm113 AND NOT stILK.Alarm116 AND NOT stILK.Alarm117;

// NETWORK 21
aILK_AV[21] := NOT aAV[12] AND NOT aAV[16] AND NOT aAV[22] AND GVL.stPMCtoPLC.I103_00 AND GVL.stPMCtoPLC.AGV_SW;

// NETWORK 22
_w10 := NOT aAV[21] AND NOT aAV[124] AND aAV[131];
aILK_AV[22] := _w10 AND GVL.stPMCtoPLC.VG11_Sensor_Value <= 1330 OR _w10 AND aAV[75] AND GVL.stPMCtoPLC.VG13_Sensor_Value < 1330;

// NETWORK 23
aILK_AV[23] := TRUE;

// NETWORK 24
aILK_AV[24] := aAV[126] OR aAV[128] OR aAV[130] OR aAV[28] AND aAV[32];

// NETWORK 25
aILK_AV[25] := aAV[26];

// NETWORK 26
_w11 := NOT aAV[12] AND NOT aAV[16] AND NOT aAV[20] AND NOT aAV[25] AND NOT aAV[30] AND NOT aAV[101] AND GVL.stPMCtoPLC.VG11_Sensor_Value < 26600;
aILK_AV[26] := (_w11 AND GVL.stPMCtoPLC.I501_07 AND GVL.stPMCtoPLC.VG11_Sensor_Value <= 5320 OR _w11 AND GVL.stPMCtoPLC.Boat_at_cap_position AND GVL.stPMCtoPLC.VG11_Sensor_Value <= 5320) AND GVL.stPMCtoPLC.I103_00 AND GVL.stPMCtoPLC.AGV_SW AND GVL.stPMCtoPLC.HTR1_SW AND GVL.stPMCtoPLC.HTR2_SW AND NOT GVL.stPMCtoPLC.HTR3_SW AND GVL.stPMCtoPLC.HTR4_SW AND GVL.stPMCtoPLC.HTR5_SW AND NOT GVL.stPMCtoPLC.DEPO_SW AND GVL.stPMCtoPLC.CLN_SW AND NOT GVL.stPMCtoPLC.F2_CLN_SW AND aVAC[2] AND aVAC[3] AND aVAC[4] AND aVAC[5] AND GVL.stPMCtoPLC.HPM_valve_power_on_off AND NOT stILK.Alarm22 AND NOT stILK.Alarm27 AND NOT stILK.Alarm51 AND NOT stILK.Alarm52 AND NOT stILK.Alarm53 AND NOT stILK.Alarm61 AND NOT stILK.Alarm62 AND NOT stILK.Alarm80 AND NOT stILK.Alarm91 AND NOT stILK.Alarm109 AND NOT stILK.Alarm113 AND NOT stILK.Alarm116 AND NOT stILK.Alarm117;

// NETWORK 27
aILK_AV[27] := NOT aAV[28] AND (NOT aAV[31] OR NOT aAV[30] AND aVAC[5]) AND GVL.stPMCtoPLC.I103_00 AND GVL.stPMCtoPLC.AGV_SW;

// NETWORK 28
aILK_AV[28] := NOT aAV[27] AND NOT aAV[32] AND (aAV[126] OR aAV[128] OR aAV[130]) AND GVL.stPMCtoPLC.VG11_Sensor_Value < 26600;

// NETWORK 29
aILK_AV[29] := NOT aAV[30];

// NETWORK 30
_w12 := (NOT aAV[12] AND NOT aAV[16] AND NOT aAV[20] AND NOT aAV[26] AND NOT aAV[29] AND aAV[101] AND GVL.stPMCtoPLC.VG11_Sensor_Value < 39900) AND NOT stILK.Alarm105;
aILK_AV[30] := (_w12 AND GVL.stPMCtoPLC.I501_07 AND GVL.stPMCtoPLC.VG11_Sensor_Value <= 5320 OR _w12 AND GVL.stPMCtoPLC.Boat_at_cap_position AND GVL.stPMCtoPLC.VG11_Sensor_Value <= 5320) AND GVL.stPMCtoPLC.I103_00 AND GVL.stPMCtoPLC.AGV_SW AND GVL.stPMCtoPLC.HTR1_SW AND GVL.stPMCtoPLC.HTR2_SW AND NOT GVL.stPMCtoPLC.HTR3_SW AND GVL.stPMCtoPLC.HTR4_SW AND GVL.stPMCtoPLC.HTR5_SW AND NOT GVL.stPMCtoPLC.DEPO_SW AND NOT GVL.stPMCtoPLC.CLN_SW AND GVL.stPMCtoPLC.F2_CLN_SW AND aVAC[1] AND aVAC[2] AND aVAC[3] AND aVAC[4] AND GVL.stPMCtoPLC.HPM_valve_power_on_off AND NOT stILK.Alarm22 AND NOT stILK.alarm27 AND NOT stILK.alarm51 AND NOT stILK.alarm52 AND NOT stILK.alarm53 AND NOT stILK.alarm61 AND NOT stILK.alarm62 AND NOT stILK.alarm80 AND NOT stILK.alarm91 AND NOT stILK.alarm109 AND NOT stILK.alarm113 AND NOT stILK.alarm116 AND NOT stILK.alarm117;

// NETWORK 31
aILK_AV[31] := NOT aAV[32] AND (NOT aAV[27] OR NOT aAV[26] AND aVAC[1]) AND GVL.stPMCtoPLC.I103_00 AND GVL.stPMCtoPLC.AGV_SW;

// NETWORK 32
aILK_AV[32] := NOT aAV[28] AND NOT aAV[31] AND (aAV[126] OR aAV[128] OR aAV[130]) AND GVL.stPMCtoPLC.VG11_Sensor_Value < 39900;

// NETWORK 33
aILK_AV[33] := TRUE;

// NETWORK 34
aILK_AV[34] := TRUE;

// NETWORK 35
aILK_AV[35] := TRUE;

// NETWORK 36
aILK_AV[36] := TRUE;

// NETWORK 37
aILK_AV[37] := TRUE;

// NETWORK 38
aILK_AV[38] := TRUE;

// NETWORK 39
aILK_AV[39] := TRUE;

// NETWORK 40
aILK_AV[40] := TRUE;

// NETWORK 41
aILK_AV[41] := TRUE;

// NETWORK 42
aILK_AV[42] := TRUE;

// NETWORK 43
aILK_AV[43] := TRUE;

// NETWORK 44
aILK_AV[44] := TRUE;

// NETWORK 45
aILK_AV[45] := TRUE;

// NETWORK 46
aILK_AV[46] := TRUE;

// NETWORK 47
aILK_AV[47] := TRUE;

// NETWORK 48
aILK_AV[48] := TRUE;

// NETWORK 49
aILK_AV[49] := TRUE;

// NETWORK 50
aILK_AV[50] := TRUE;

// NETWORK 51
aILK_AV[51] := TRUE;

// NETWORK 52
// 无条件开关
aILK_AV[52] := TRUE;

// NETWORK 53
aILK_AV[53] := TRUE;

// NETWORK 54 (disabled)
// aILK_AV[54] := TRUE;

// NETWORK 55
aILK_AV[55] := TRUE;

// NETWORK 56
aILK_AV[56] := TRUE;

// NETWORK 57
aILK_AV[57] := TRUE;

// NETWORK 58
aILK_AV[58] := TRUE;

// NETWORK 59
aILK_AV[59] := TRUE;

// NETWORK 60 (disabled)
// aILK_AV[60] := TRUE;

// NETWORK 61
aILK_AV[61] := TRUE;

// NETWORK 62
aILK_AV[62] := TRUE;

// NETWORK 63
aILK_AV[63] := TRUE;

// NETWORK 64
aILK_AV[64] := TRUE;

// NETWORK 65
aILK_AV[65] := NOT bFFUAlarm;

// NETWORK 66
aILK_AV[66] := TRUE;

// NETWORK 67
// AV67 DG1 Protect
aILK_AV[67] := aVAC[1] AND aVAC[2] AND aVAC[3] AND aVAC[4] AND aVAC[5];

// NETWORK 68 (disabled)
// aILK_AV[68] := TRUE;

// NETWORK 69
aILK_AV[69] := TRUE;

// NETWORK 70
aILK_AV[70] := TRUE;

// NETWORK 71
_w13 := GVL.stPMCtoPLC.I103_00 AND GVL.stPMCtoPLC.AGV_SW;
_w14 := _w13 AND GVL.stPMCtoPLC.I501_07 OR _w13 AND GVL.stPMCtoPLC.Boat_at_cap_position OR _w13 AND GVL.stPMCtoPLC.Boat_at_cap_position AND GVL.stPMCtoPLC.VG11_Sensor_Value <= 5320;
aILK_AV[71] := _w14 AND NOT GVL.stPMCtoPLC.Boat_at_cap_position OR _w14 AND aAV[52] OR _w14 AND GVL.stPMCtoPLC.VG11_Sensor_Value <= 1995;

// NETWORK 72
aILK_AV[72] := GVL.stPMCtoPLC.I103_00;

// NETWORK 73 (disabled)
// aILK_AV[73] := TRUE;

// NETWORK 74 (disabled)
// aILK_AV[74] := TRUE;

// NETWORK 75
aILK_AV[75] := GVL.stPMCtoPLC.VG11_Sensor_Value <= 1995 AND GVL.stPMCtoPLC.I103_00;

// NETWORK 76
aILK_AV[76] := TRUE;

// NETWORK 77 (disabled)
// aILK_AV[77] := TRUE;

// NETWORK 78
aILK_AV[78] := TRUE;

// NETWORK 79
aILK_AV[79] := ((GVL.stPMCtoPLC.Boat_at_cap_position OR GVL.stPMCtoPLC.I501_07) AND GVL.stPMCtoPLC.VG11_Sensor_Value <= 1995) AND GVL.stPMCtoPLC.I103_00 AND NOT stILK.Alarm12 AND NOT stILK.Alarm98 AND (NOT GVL.stPMCtoPLC.Boat_at_cap_position OR aAV[52]);

// NETWORK 80
aILK_AV[80] := TRUE;

// NETWORK 81
aILK_AV[81] := TRUE;

// NETWORK 82
aILK_AV[82] := TRUE;

// NETWORK 83
aILK_AV[83] := TRUE;

// NETWORK 84
aILK_AV[84] := TRUE;

// NETWORK 85
// AV85 BG1
aILK_AV[85] := GVL.stPMCtoPLC.I103_00 AND NOT stILK.Alarm40;

// NETWORK 86
// AV86 BG1
aILK_AV[86] := GVL.stPMCtoPLC.I103_00 AND NOT stILK.Alarm40;

// NETWORK 87
// AV87 BG1
aILK_AV[87] := GVL.stPMCtoPLC.I103_00 AND NOT stILK.Alarm40;

// NETWORK 88
// AV88 BG1
aILK_AV[88] := GVL.stPMCtoPLC.I103_00 AND NOT stILK.Alarm40;

// NETWORK 89
aILK_AV[89] := TRUE;

// NETWORK 90
aILK_AV[90] := TRUE;

// NETWORK 91
aILK_AV[91] := TRUE;

// NETWORK 92
aILK_AV[92] := TRUE;

// NETWORK 93
aILK_AV[93] := TRUE;

// NETWORK 94
aILK_AV[94] := TRUE;

// NETWORK 95
aILK_AV[95] := TRUE;

// NETWORK 96
aILK_AV[96] := TRUE;

// NETWORK 97
aILK_AV[97] := TRUE;

// NETWORK 98
aILK_AV[98] := TRUE;

// NETWORK 99
aILK_AV[99] := TRUE;

// NETWORK 100 (disabled)
// aILK_AV[100] := TRUE;

// NETWORK 101
_w15 := (NOT aAV[26] AND NOT aAV[30] AND NOT aAV[100] AND NOT aAV[102] AND GVL.stPMCtoPLC.HTR1_SW AND GVL.stPMCtoPLC.HTR2_SW AND GVL.stPMCtoPLC.HTR3_SW AND GVL.stPMCtoPLC.HTR4_SW AND GVL.stPMCtoPLC.HTR5_SW AND GVL.stPMCtoPLC.DEPO_SW AND NOT GVL.stPMCtoPLC.CLN_SW AND NOT GVL.stPMCtoPLC.F2_CLN_SW AND GVL.stPLCtoPMC.DEPO_OK AND GVL.stPMCtoPLC.I103_00 AND GVL.stPMCtoPLC.AGV_SW AND GVL.stPMCtoPLC.VG11_Sensor_Value < 39900) AND NOT stILK.Alarm26;
aILK_AV[101] := (_w15 AND GVL.stPMCtoPLC.I501_07 AND GVL.stPMCtoPLC.VG11_Sensor_Value <= 5320 OR _w15 AND GVL.stPMCtoPLC.Boat_at_cap_position AND GVL.stPMCtoPLC.VG11_Sensor_Value <= 5320) AND aVAC[1] AND aVAC[5] AND GVL.stPMCtoPLC.HPM_valve_power_on_off AND NOT stILK.Alarm22 AND NOT stILK.alarm27 AND NOT stILK.Alarm51 AND NOT stILK.alarm52 AND NOT stILK.alarm53 AND NOT stILK.alarm61 AND NOT stILK.alarm62 AND NOT stILK.alarm80 AND NOT stILK.Alarm91 AND NOT stILK.Alarm109 AND NOT stILK.Alarm113 AND NOT stILK.Alarm116 AND NOT stILK.Alarm117;

// NETWORK 102
aILK_AV[102] := NOT aAV[101] AND NOT aAV[112] AND NOT stILK.Alarm26 AND NOT stILK.Alarm113;

// NETWORK 103
_w16 := NOT aAV[105];
_w17 := _w16 AND aAV[137];
IF NOT _w17 THEN
    _w17 := _w16 AND GVL.stPMCtoPLC.VG11_Sensor_Value <= 1995;
END_IF
aILK_AV[103] := _w17 AND NOT stILK.Alarm26 AND GVL.stPLCtoPMC.PS33_Pressure <= 200;

// NETWORK 104
aILK_AV[104] := TRUE;

// NETWORK 105
aILK_AV[105] := NOT aAV[103] AND GVL.stPMCtoPLC.VG11_Sensor_Value <= 108000;

// NETWORK 106
aILK_AV[106] := NOT aAV[100] AND NOT GVL.stPMCtoPLC.T_REF_sw;

// NETWORK 107
aILK_AV[107] := NOT aAV[137] AND GVL.stPMCtoPLC.I103_00 AND GVL.stPMCtoPLC.AGV_SW;

// NETWORK 108
aILK_AV[108] := TRUE;

// NETWORK 109
aILK_AV[109] := TRUE;

// NETWORK 110
// VG31 protect
aILK_AV[110] := TRUE;

// NETWORK 111
aILK_AV[111] := NOT aAV[112] AND GVL.stPMCtoPLC.T_REF_sw AND NOT stILK.Alarm121 OR GVL.stPMCtoPLC.T_MNT_sw AND GVL.stPMCtoPLC.T_REF_sw;

// NETWORK 112
aILK_AV[112] := NOT aAV[102] AND NOT stILK.Alarm111;

// NETWORK 113
aILK_AV[113] := TRUE;

// NETWORK 114
aILK_AV[114] := TRUE;

// NETWORK 115
aILK_AV[115] := TRUE;

// NETWORK 116
aILK_AV[116] := TRUE;

// NETWORK 117
aILK_AV[117] := TRUE;

// NETWORK 118
aILK_AV[118] := TRUE;

// NETWORK 119
aILK_AV[119] := TRUE;

// NETWORK 120
aILK_AV[120] := GVL.stPLCtoPMC.PG22_Pressure <= 200;

// NETWORK 121
aILK_AV[121] := ((NOT aAV[123] OR GVL.stPLCtoPMC.PG22_Pressure <= 20 OR NOT aAV[12] AND NOT aAV[14]) AND GVL.stPMCtoPLC.VG11_Sensor_Value <= 108000) AND aAV[124];

// NETWORK 122
aILK_AV[122] := GVL.stPLCtoPMC.PG23_Pressure <= 200;

// NETWORK 123
aILK_AV[123] := ((NOT aAV[121] OR GVL.stPLCtoPMC.PG23_Pressure <= 20 OR NOT aAV[16] AND NOT aAV[18]) AND GVL.stPMCtoPLC.VG11_Sensor_Value <= 108000) AND aAV[124];

// NETWORK 124
aILK_AV[124] := NOT aAV[22];

// NETWORK 125
aILK_AV[125] := TRUE;

// NETWORK 126
aILK_AV[126] := TRUE;

// NETWORK 127
aILK_AV[127] := TRUE;

// NETWORK 128
aILK_AV[128] := TRUE;

// NETWORK 129
aILK_AV[129] := TRUE;

// NETWORK 130
aILK_AV[130] := TRUE;

// NETWORK 131
aILK_AV[131] := TRUE;

// NETWORK 132
aILK_AV[132] := TRUE;

// NETWORK 133
aILK_AV[133] := TRUE;

// NETWORK 134
aILK_AV[134] := TRUE;

// NETWORK 135
aILK_AV[135] := TRUE;

// NETWORK 136
aILK_AV[136] := NOT aAV[137] AND GVL.stPMCtoPLC.Boat_at_cap_position AND GVL.stPMCtoPLC.I103_00 AND GVL.stPMCtoPLC.VG11_Sensor_Value <= 1995;

// NETWORK 137
aILK_AV[137] := NOT aAV[107] AND NOT aAV[136] AND GVL.stPMCtoPLC.I103_00 AND GVL.stPMCtoPLC.AGV_SW AND NOT stILK.Alarm40;

// NETWORK 138
aILK_AV[138] := TRUE;

// NETWORK 139
aILK_AV[139] := TRUE;

// NETWORK 140
aILK_AV[140] := TRUE;

// NETWORK 141
aILK_AV[141] := TRUE;

// NETWORK 142
aILK_AV[142] := TRUE;

// NETWORK 143
aILK_AV[143] := TRUE;

// NETWORK 144
aILK_AV[144] := TRUE;

// NETWORK 145
aILK_AV[145] := TRUE;

// NETWORK 146
aILK_AV[146] := TRUE;

// NETWORK 147
aILK_AV[147] := TRUE;

// NETWORK 148
aILK_AV[148] := TRUE;

// NETWORK 149
aILK_AV[149] := TRUE;

// NETWORK 150
aILK_AV[150] := TRUE;

// NETWORK 151
// Dry pump
GVL.stPLCtoPMC.DP := GVL.stPMCtoPLC.DP_sw AND GVL.stPMCtoPLC.I103_00;

// NETWORK 152
// Blower
GVL.stPLCtoPMC.BWR := GVL.stPMCtoPLC.BWR_sw AND NOT stILK.Alarm70 AND NOT stILK.Alarm72 AND (GVL.stPMCtoPLC.DPR1_sw OR GVL.stPMCtoPLC.DPR2_sw);

// NETWORK 153
// Damper-1
GVL.stPLCtoPMC.DPR1 := GVL.stPMCtoPLC.DPR1_sw AND NOT stILK.Alarm70 AND NOT stILK.Alarm72 AND NOT GVL.stPMCtoPLC.DPR2_sw;

// NETWORK 154
// Damper-2
GVL.stPLCtoPMC.DPR2 := GVL.stPMCtoPLC.DPR2_sw AND NOT stILK.Alarm70 AND NOT stILK.Alarm72 AND NOT GVL.stPMCtoPLC.DPR1_sw;

// NETWORK 155
// R-axis water
GVL.stPLCtoPMC.WAT_R := GVL.stPMCtoPLC.WAT_R_sw;

// NETWORK 156
// Flange water not using
GVL.stPLCtoPMC.WAT_F := GVL.stPMCtoPLC.WAT_F_sw;

// NETWORK 157
// HTR1 GAS
GVL.stPLCtoPMC.HTR1 := GVL.stPMCtoPLC.HTR1_SW;

// NETWORK 158
// HTR2 EXHAUST
GVL.stPLCtoPMC.HTR2 := GVL.stPMCtoPLC.HTR2_SW;

// NETWORK 159
// HTR3 HOT N2/Pump Heater
GVL.stPLCtoPMC.HTR3 := GVL.stPMCtoPLC.HTR3_SW AND NOT aAV[26] AND NOT aAV[30];

// NETWORK 160
// HTR4 LSC Heater
GVL.stPLCtoPMC.HTR4 := GVL.stPMCtoPLC.HTR4_SW;

// NETWORK 161
// HTR5 1`2F Pipe Heater
GVL.stPLCtoPMC.HTR5 := GVL.stPMCtoPLC.HTR5_SW;

// NETWORK 162
// T_REF
GVL.stPLCtoPMC.T_REF := GVL.stPMCtoPLC.T_REF_sw AND NOT aAV[106] AND NOT stILK.Alarm121 AND NOT stILK.Alarm123 AND NOT stILK.Alarm126 AND NOT stILK.Alarm116 AND GVL.stPMCtoPLC.I102_02 AND NOT stILK.Alarm113 AND (GVL.stPLCtoPMC.LSC1_Level_L OR GVL.stPLCtoPMC.LSC1_Level_M) AND NOT GVL.stPLCtoPMC.LSC1_Level_H AND NOT GVL.stPLCtoPMC.LSC1_Level_HH;

// NETWORK 163
// DEPO Select
GVL.stPLCtoPMC.DEPO := GVL.stPMCtoPLC.DEPO_SW AND NOT aAV[26] AND NOT aAV[30] AND NOT GVL.stPMCtoPLC.CLN_SW AND NOT GVL.stPMCtoPLC.F2_CLN_SW;

// NETWORK 164
// Cleaning Select
GVL.stPLCtoPMC.CLN := GVL.stPMCtoPLC.CLN_SW AND NOT aAV[12] AND NOT aAV[16] AND NOT aAV[20] AND NOT aAV[30] AND NOT aAV[101] AND NOT GVL.stPMCtoPLC.DEPO_SW AND NOT GVL.stPMCtoPLC.F2_CLN_SW;

// NETWORK 165
// Pump ECO mode
GVL.stPLCtoPMC.ECO := GVL.stPMCtoPLC.Pump1_ECO_sw AND NOT aAV[12] AND NOT aAV[16] AND NOT aAV[20] AND NOT aAV[30] AND NOT aAV[101];

// NETWORK 166
GVL.stPLCtoPMC.AGV := GVL.stPMCtoPLC.AGV_SW;

// NETWORK 167
// Spare ,NO Using
GVL.stPLCtoPMC.SP1 := TRUE;

// NETWORK 168
// PZ PS13 Auto Zero
GVL.stPLCtoPMC.PZ := GVL.stPMCtoPLC.PZ_sw AND NOT aAV[52] AND NOT aAV[67] AND NOT aAV[124] AND NOT aAV[125] AND NOT aAV[126] AND NOT aAV[127] AND NOT aAV[128] AND NOT aAV[129] AND NOT aAV[130] AND NOT aAV[131] AND NOT aAV[136] AND aAV[60];

// NETWORK 169
// Pressure control ,NO Using
GVL.stPLCtoPMC.P_CONT := GVL.stPMCtoPLC.P_CONT_sw;

// NETWORK 170
// DG1 zero adj,NO Using
GVL.stPLCtoPMC.DGZERO := GVL.stPMCtoPLC.DGZERO_sw;

// NETWORK 171
// 1 pass
GVL.stPLCtoPMC.C_EXH := GVL.stPMCtoPLC.C_EXH_sw;

// NETWORK 172
// F2 cleaning seclect
GVL.stPLCtoPMC.F2_CLN := GVL.stPMCtoPLC.F2_CLN_sw;

// NETWORK 173
// Foup N2 shut off
GVL.stPLCtoPMC.F_N := GVL.stPMCtoPLC.F_N_sw;
END_ACTION

END_PROGRAM
